VERSION 5.8 ;
BUSBITCHARS "[]" ;
DIVIDERCHAR "/" ;
UNITS
    DATABASE MICRONS 1000 ;
END UNITS

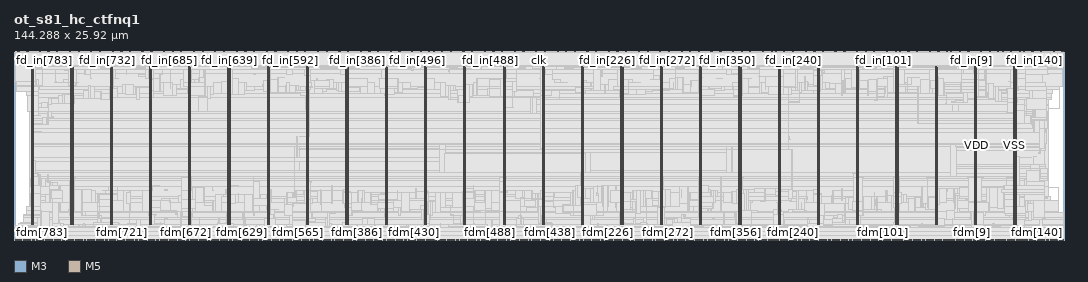
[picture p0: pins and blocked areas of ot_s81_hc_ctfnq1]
MACRO ot_s81_hc_ctfnq1
  FOREIGN ot_s81_hc_ctfnq1 0 0 ;
  CLASS BLOCK ;
  SIZE 144.288 BY 25.92 ;
  PIN clk
    DIRECTION INPUT ;
    USE SIGNAL ;
    PORT
      LAYER M3 ;
        RECT  72.144 25.882 72.162 25.92 ;
    END
  END clk
  PIN fd_in[0]
    DIRECTION INPUT ;
    USE SIGNAL ;
    PORT
      LAYER M5 ;
        RECT  129.984 25.836 130.008 25.92 ;
    END
  END fd_in[0]
  PIN fd_in[100]
    DIRECTION INPUT ;
    USE SIGNAL ;
    PORT
      LAYER M5 ;
        RECT  119.232 25.836 119.256 25.92 ;
    END
  END fd_in[100]
  PIN fd_in[101]
    DIRECTION INPUT ;
    USE SIGNAL ;
    PORT
      LAYER M5 ;
        RECT  119.424 25.836 119.448 25.92 ;
    END
  END fd_in[101]
  PIN fd_in[102]
    DIRECTION INPUT ;
    USE SIGNAL ;
    PORT
      LAYER M5 ;
        RECT  119.568 25.836 119.592 25.92 ;
    END
  END fd_in[102]
  PIN fd_in[103]
    DIRECTION INPUT ;
    USE SIGNAL ;
    PORT
      LAYER M5 ;
        RECT  119.76 25.836 119.784 25.92 ;
    END
  END fd_in[103]
  PIN fd_in[104]
    DIRECTION INPUT ;
    USE SIGNAL ;
    PORT
      LAYER M5 ;
        RECT  119.952 25.836 119.976 25.92 ;
    END
  END fd_in[104]
  PIN fd_in[105]
    DIRECTION INPUT ;
    USE SIGNAL ;
    PORT
      LAYER M5 ;
        RECT  120.144 25.836 120.168 25.92 ;
    END
  END fd_in[105]
  PIN fd_in[106]
    DIRECTION INPUT ;
    USE SIGNAL ;
    PORT
      LAYER M5 ;
        RECT  120.288 25.836 120.312 25.92 ;
    END
  END fd_in[106]
  PIN fd_in[107]
    DIRECTION INPUT ;
    USE SIGNAL ;
    PORT
      LAYER M5 ;
        RECT  120.48 25.836 120.504 25.92 ;
    END
  END fd_in[107]
  PIN fd_in[108]
    DIRECTION INPUT ;
    USE SIGNAL ;
    PORT
      LAYER M5 ;
        RECT  120.672 25.836 120.696 25.92 ;
    END
  END fd_in[108]
  PIN fd_in[109]
    DIRECTION INPUT ;
    USE SIGNAL ;
    PORT
      LAYER M5 ;
        RECT  120.864 25.836 120.888 25.92 ;
    END
  END fd_in[109]
  PIN fd_in[10]
    DIRECTION INPUT ;
    USE SIGNAL ;
    PORT
      LAYER M5 ;
        RECT  131.808 25.836 131.832 25.92 ;
    END
  END fd_in[10]
  PIN fd_in[110]
    DIRECTION INPUT ;
    USE SIGNAL ;
    PORT
      LAYER M5 ;
        RECT  121.008 25.836 121.032 25.92 ;
    END
  END fd_in[110]
  PIN fd_in[111]
    DIRECTION INPUT ;
    USE SIGNAL ;
    PORT
      LAYER M5 ;
        RECT  121.2 25.836 121.224 25.92 ;
    END
  END fd_in[111]
  PIN fd_in[112]
    DIRECTION INPUT ;
    USE SIGNAL ;
    PORT
      LAYER M5 ;
        RECT  121.392 25.836 121.416 25.92 ;
    END
  END fd_in[112]
  PIN fd_in[113]
    DIRECTION INPUT ;
    USE SIGNAL ;
    PORT
      LAYER M5 ;
        RECT  121.584 25.836 121.608 25.92 ;
    END
  END fd_in[113]
  PIN fd_in[114]
    DIRECTION INPUT ;
    USE SIGNAL ;
    PORT
      LAYER M5 ;
        RECT  121.728 25.836 121.752 25.92 ;
    END
  END fd_in[114]
  PIN fd_in[115]
    DIRECTION INPUT ;
    USE SIGNAL ;
    PORT
      LAYER M5 ;
        RECT  121.92 25.836 121.944 25.92 ;
    END
  END fd_in[115]
  PIN fd_in[116]
    DIRECTION INPUT ;
    USE SIGNAL ;
    PORT
      LAYER M5 ;
        RECT  122.112 25.836 122.136 25.92 ;
    END
  END fd_in[116]
  PIN fd_in[117]
    DIRECTION INPUT ;
    USE SIGNAL ;
    PORT
      LAYER M5 ;
        RECT  122.304 25.836 122.328 25.92 ;
    END
  END fd_in[117]
  PIN fd_in[118]
    DIRECTION INPUT ;
    USE SIGNAL ;
    PORT
      LAYER M5 ;
        RECT  122.448 25.836 122.472 25.92 ;
    END
  END fd_in[118]
  PIN fd_in[119]
    DIRECTION INPUT ;
    USE SIGNAL ;
    PORT
      LAYER M5 ;
        RECT  122.64 25.836 122.664 25.92 ;
    END
  END fd_in[119]
  PIN fd_in[11]
    DIRECTION INPUT ;
    USE SIGNAL ;
    PORT
      LAYER M5 ;
        RECT  131.952 25.836 131.976 25.92 ;
    END
  END fd_in[11]
  PIN fd_in[120]
    DIRECTION INPUT ;
    USE SIGNAL ;
    PORT
      LAYER M5 ;
        RECT  122.832 25.836 122.856 25.92 ;
    END
  END fd_in[120]
  PIN fd_in[121]
    DIRECTION INPUT ;
    USE SIGNAL ;
    PORT
      LAYER M5 ;
        RECT  122.976 25.836 123 25.92 ;
    END
  END fd_in[121]
  PIN fd_in[122]
    DIRECTION INPUT ;
    USE SIGNAL ;
    PORT
      LAYER M5 ;
        RECT  123.168 25.836 123.192 25.92 ;
    END
  END fd_in[122]
  PIN fd_in[123]
    DIRECTION INPUT ;
    USE SIGNAL ;
    PORT
      LAYER M5 ;
        RECT  123.36 25.836 123.384 25.92 ;
    END
  END fd_in[123]
  PIN fd_in[124]
    DIRECTION INPUT ;
    USE SIGNAL ;
    PORT
      LAYER M5 ;
        RECT  123.552 25.836 123.576 25.92 ;
    END
  END fd_in[124]
  PIN fd_in[125]
    DIRECTION INPUT ;
    USE SIGNAL ;
    PORT
      LAYER M5 ;
        RECT  123.696 25.836 123.72 25.92 ;
    END
  END fd_in[125]
  PIN fd_in[126]
    DIRECTION INPUT ;
    USE SIGNAL ;
    PORT
      LAYER M5 ;
        RECT  123.888 25.836 123.912 25.92 ;
    END
  END fd_in[126]
  PIN fd_in[127]
    DIRECTION INPUT ;
    USE SIGNAL ;
    PORT
      LAYER M5 ;
        RECT  124.08 25.836 124.104 25.92 ;
    END
  END fd_in[127]
  PIN fd_in[128]
    DIRECTION INPUT ;
    USE SIGNAL ;
    PORT
      LAYER M5 ;
        RECT  141.456 25.836 141.48 25.92 ;
    END
  END fd_in[128]
  PIN fd_in[129]
    DIRECTION INPUT ;
    USE SIGNAL ;
    PORT
      LAYER M5 ;
        RECT  141.648 25.836 141.672 25.92 ;
    END
  END fd_in[129]
  PIN fd_in[12]
    DIRECTION INPUT ;
    USE SIGNAL ;
    PORT
      LAYER M5 ;
        RECT  132.144 25.836 132.168 25.92 ;
    END
  END fd_in[12]
  PIN fd_in[130]
    DIRECTION INPUT ;
    USE SIGNAL ;
    PORT
      LAYER M5 ;
        RECT  141.84 25.836 141.864 25.92 ;
    END
  END fd_in[130]
  PIN fd_in[131]
    DIRECTION INPUT ;
    USE SIGNAL ;
    PORT
      LAYER M5 ;
        RECT  142.032 25.836 142.056 25.92 ;
    END
  END fd_in[131]
  PIN fd_in[132]
    DIRECTION INPUT ;
    USE SIGNAL ;
    PORT
      LAYER M5 ;
        RECT  142.176 25.836 142.2 25.92 ;
    END
  END fd_in[132]
  PIN fd_in[133]
    DIRECTION INPUT ;
    USE SIGNAL ;
    PORT
      LAYER M5 ;
        RECT  142.368 25.836 142.392 25.92 ;
    END
  END fd_in[133]
  PIN fd_in[134]
    DIRECTION INPUT ;
    USE SIGNAL ;
    PORT
      LAYER M5 ;
        RECT  142.56 25.836 142.584 25.92 ;
    END
  END fd_in[134]
  PIN fd_in[135]
    DIRECTION INPUT ;
    USE SIGNAL ;
    PORT
      LAYER M5 ;
        RECT  142.704 25.836 142.728 25.92 ;
    END
  END fd_in[135]
  PIN fd_in[136]
    DIRECTION INPUT ;
    USE SIGNAL ;
    PORT
      LAYER M5 ;
        RECT  142.896 25.836 142.92 25.92 ;
    END
  END fd_in[136]
  PIN fd_in[137]
    DIRECTION INPUT ;
    USE SIGNAL ;
    PORT
      LAYER M5 ;
        RECT  143.088 25.836 143.112 25.92 ;
    END
  END fd_in[137]
  PIN fd_in[138]
    DIRECTION INPUT ;
    USE SIGNAL ;
    PORT
      LAYER M5 ;
        RECT  143.28 25.836 143.304 25.92 ;
    END
  END fd_in[138]
  PIN fd_in[139]
    DIRECTION INPUT ;
    USE SIGNAL ;
    PORT
      LAYER M5 ;
        RECT  143.424 25.836 143.448 25.92 ;
    END
  END fd_in[139]
  PIN fd_in[13]
    DIRECTION INPUT ;
    USE SIGNAL ;
    PORT
      LAYER M5 ;
        RECT  132.336 25.836 132.36 25.92 ;
    END
  END fd_in[13]
  PIN fd_in[140]
    DIRECTION INPUT ;
    USE SIGNAL ;
    PORT
      LAYER M5 ;
        RECT  143.616 25.836 143.64 25.92 ;
    END
  END fd_in[140]
  PIN fd_in[141]
    DIRECTION INPUT ;
    USE SIGNAL ;
    PORT
      LAYER M5 ;
        RECT  143.808 25.836 143.832 25.92 ;
    END
  END fd_in[141]
  PIN fd_in[142]
    DIRECTION INPUT ;
    USE SIGNAL ;
    PORT
      LAYER M5 ;
        RECT  144 25.836 144.024 25.92 ;
    END
  END fd_in[142]
  PIN fd_in[143]
    DIRECTION INPUT ;
    USE SIGNAL ;
    PORT
      LAYER M5 ;
        RECT  144.144 25.836 144.168 25.92 ;
    END
  END fd_in[143]
  PIN fd_in[144]
    DIRECTION INPUT ;
    USE SIGNAL ;
    PORT
      LAYER M5 ;
        RECT  112.8 25.836 112.824 25.92 ;
    END
  END fd_in[144]
  PIN fd_in[145]
    DIRECTION INPUT ;
    USE SIGNAL ;
    PORT
      LAYER M5 ;
        RECT  112.944 25.836 112.968 25.92 ;
    END
  END fd_in[145]
  PIN fd_in[146]
    DIRECTION INPUT ;
    USE SIGNAL ;
    PORT
      LAYER M5 ;
        RECT  113.136 25.836 113.16 25.92 ;
    END
  END fd_in[146]
  PIN fd_in[147]
    DIRECTION INPUT ;
    USE SIGNAL ;
    PORT
      LAYER M5 ;
        RECT  113.328 25.836 113.352 25.92 ;
    END
  END fd_in[147]
  PIN fd_in[148]
    DIRECTION INPUT ;
    USE SIGNAL ;
    PORT
      LAYER M5 ;
        RECT  113.472 25.836 113.496 25.92 ;
    END
  END fd_in[148]
  PIN fd_in[149]
    DIRECTION INPUT ;
    USE SIGNAL ;
    PORT
      LAYER M5 ;
        RECT  113.664 25.836 113.688 25.92 ;
    END
  END fd_in[149]
  PIN fd_in[14]
    DIRECTION INPUT ;
    USE SIGNAL ;
    PORT
      LAYER M5 ;
        RECT  132.528 25.836 132.552 25.92 ;
    END
  END fd_in[14]
  PIN fd_in[150]
    DIRECTION INPUT ;
    USE SIGNAL ;
    PORT
      LAYER M5 ;
        RECT  113.856 25.836 113.88 25.92 ;
    END
  END fd_in[150]
  PIN fd_in[151]
    DIRECTION INPUT ;
    USE SIGNAL ;
    PORT
      LAYER M5 ;
        RECT  114.048 25.836 114.072 25.92 ;
    END
  END fd_in[151]
  PIN fd_in[152]
    DIRECTION INPUT ;
    USE SIGNAL ;
    PORT
      LAYER M5 ;
        RECT  114.192 25.836 114.216 25.92 ;
    END
  END fd_in[152]
  PIN fd_in[153]
    DIRECTION INPUT ;
    USE SIGNAL ;
    PORT
      LAYER M5 ;
        RECT  114.384 25.836 114.408 25.92 ;
    END
  END fd_in[153]
  PIN fd_in[154]
    DIRECTION INPUT ;
    USE SIGNAL ;
    PORT
      LAYER M5 ;
        RECT  114.576 25.836 114.6 25.92 ;
    END
  END fd_in[154]
  PIN fd_in[155]
    DIRECTION INPUT ;
    USE SIGNAL ;
    PORT
      LAYER M5 ;
        RECT  114.768 25.836 114.792 25.92 ;
    END
  END fd_in[155]
  PIN fd_in[156]
    DIRECTION INPUT ;
    USE SIGNAL ;
    PORT
      LAYER M5 ;
        RECT  114.912 25.836 114.936 25.92 ;
    END
  END fd_in[156]
  PIN fd_in[157]
    DIRECTION INPUT ;
    USE SIGNAL ;
    PORT
      LAYER M5 ;
        RECT  115.104 25.836 115.128 25.92 ;
    END
  END fd_in[157]
  PIN fd_in[158]
    DIRECTION INPUT ;
    USE SIGNAL ;
    PORT
      LAYER M5 ;
        RECT  115.296 25.836 115.32 25.92 ;
    END
  END fd_in[158]
  PIN fd_in[159]
    DIRECTION INPUT ;
    USE SIGNAL ;
    PORT
      LAYER M5 ;
        RECT  115.488 25.836 115.512 25.92 ;
    END
  END fd_in[159]
  PIN fd_in[15]
    DIRECTION INPUT ;
    USE SIGNAL ;
    PORT
      LAYER M5 ;
        RECT  132.672 25.836 132.696 25.92 ;
    END
  END fd_in[15]
  PIN fd_in[160]
    DIRECTION INPUT ;
    USE SIGNAL ;
    PORT
      LAYER M5 ;
        RECT  115.632 25.836 115.656 25.92 ;
    END
  END fd_in[160]
  PIN fd_in[161]
    DIRECTION INPUT ;
    USE SIGNAL ;
    PORT
      LAYER M5 ;
        RECT  115.824 25.836 115.848 25.92 ;
    END
  END fd_in[161]
  PIN fd_in[162]
    DIRECTION INPUT ;
    USE SIGNAL ;
    PORT
      LAYER M5 ;
        RECT  116.016 25.836 116.04 25.92 ;
    END
  END fd_in[162]
  PIN fd_in[163]
    DIRECTION INPUT ;
    USE SIGNAL ;
    PORT
      LAYER M5 ;
        RECT  116.208 25.836 116.232 25.92 ;
    END
  END fd_in[163]
  PIN fd_in[164]
    DIRECTION INPUT ;
    USE SIGNAL ;
    PORT
      LAYER M5 ;
        RECT  116.352 25.836 116.376 25.92 ;
    END
  END fd_in[164]
  PIN fd_in[165]
    DIRECTION INPUT ;
    USE SIGNAL ;
    PORT
      LAYER M5 ;
        RECT  116.544 25.836 116.568 25.92 ;
    END
  END fd_in[165]
  PIN fd_in[166]
    DIRECTION INPUT ;
    USE SIGNAL ;
    PORT
      LAYER M5 ;
        RECT  116.736 25.836 116.76 25.92 ;
    END
  END fd_in[166]
  PIN fd_in[167]
    DIRECTION INPUT ;
    USE SIGNAL ;
    PORT
      LAYER M5 ;
        RECT  116.88 25.836 116.904 25.92 ;
    END
  END fd_in[167]
  PIN fd_in[168]
    DIRECTION INPUT ;
    USE SIGNAL ;
    PORT
      LAYER M5 ;
        RECT  117.072 25.836 117.096 25.92 ;
    END
  END fd_in[168]
  PIN fd_in[169]
    DIRECTION INPUT ;
    USE SIGNAL ;
    PORT
      LAYER M5 ;
        RECT  117.264 25.836 117.288 25.92 ;
    END
  END fd_in[169]
  PIN fd_in[16]
    DIRECTION INPUT ;
    USE SIGNAL ;
    PORT
      LAYER M5 ;
        RECT  132.864 25.836 132.888 25.92 ;
    END
  END fd_in[16]
  PIN fd_in[170]
    DIRECTION INPUT ;
    USE SIGNAL ;
    PORT
      LAYER M5 ;
        RECT  117.456 25.836 117.48 25.92 ;
    END
  END fd_in[170]
  PIN fd_in[171]
    DIRECTION INPUT ;
    USE SIGNAL ;
    PORT
      LAYER M5 ;
        RECT  117.6 25.836 117.624 25.92 ;
    END
  END fd_in[171]
  PIN fd_in[172]
    DIRECTION INPUT ;
    USE SIGNAL ;
    PORT
      LAYER M5 ;
        RECT  117.792 25.836 117.816 25.92 ;
    END
  END fd_in[172]
  PIN fd_in[173]
    DIRECTION INPUT ;
    USE SIGNAL ;
    PORT
      LAYER M5 ;
        RECT  117.984 25.836 118.008 25.92 ;
    END
  END fd_in[173]
  PIN fd_in[174]
    DIRECTION INPUT ;
    USE SIGNAL ;
    PORT
      LAYER M5 ;
        RECT  118.176 25.836 118.2 25.92 ;
    END
  END fd_in[174]
  PIN fd_in[175]
    DIRECTION INPUT ;
    USE SIGNAL ;
    PORT
      LAYER M5 ;
        RECT  118.32 25.836 118.344 25.92 ;
    END
  END fd_in[175]
  PIN fd_in[176]
    DIRECTION INPUT ;
    USE SIGNAL ;
    PORT
      LAYER M5 ;
        RECT  101.28 25.836 101.304 25.92 ;
    END
  END fd_in[176]
  PIN fd_in[177]
    DIRECTION INPUT ;
    USE SIGNAL ;
    PORT
      LAYER M5 ;
        RECT  101.472 25.836 101.496 25.92 ;
    END
  END fd_in[177]
  PIN fd_in[178]
    DIRECTION INPUT ;
    USE SIGNAL ;
    PORT
      LAYER M5 ;
        RECT  101.664 25.836 101.688 25.92 ;
    END
  END fd_in[178]
  PIN fd_in[179]
    DIRECTION INPUT ;
    USE SIGNAL ;
    PORT
      LAYER M5 ;
        RECT  101.856 25.836 101.88 25.92 ;
    END
  END fd_in[179]
  PIN fd_in[17]
    DIRECTION INPUT ;
    USE SIGNAL ;
    PORT
      LAYER M5 ;
        RECT  133.056 25.836 133.08 25.92 ;
    END
  END fd_in[17]
  PIN fd_in[180]
    DIRECTION INPUT ;
    USE SIGNAL ;
    PORT
      LAYER M5 ;
        RECT  102 25.836 102.024 25.92 ;
    END
  END fd_in[180]
  PIN fd_in[181]
    DIRECTION INPUT ;
    USE SIGNAL ;
    PORT
      LAYER M5 ;
        RECT  102.192 25.836 102.216 25.92 ;
    END
  END fd_in[181]
  PIN fd_in[182]
    DIRECTION INPUT ;
    USE SIGNAL ;
    PORT
      LAYER M5 ;
        RECT  102.384 25.836 102.408 25.92 ;
    END
  END fd_in[182]
  PIN fd_in[183]
    DIRECTION INPUT ;
    USE SIGNAL ;
    PORT
      LAYER M5 ;
        RECT  102.576 25.836 102.6 25.92 ;
    END
  END fd_in[183]
  PIN fd_in[184]
    DIRECTION INPUT ;
    USE SIGNAL ;
    PORT
      LAYER M5 ;
        RECT  102.72 25.836 102.744 25.92 ;
    END
  END fd_in[184]
  PIN fd_in[185]
    DIRECTION INPUT ;
    USE SIGNAL ;
    PORT
      LAYER M5 ;
        RECT  102.912 25.836 102.936 25.92 ;
    END
  END fd_in[185]
  PIN fd_in[186]
    DIRECTION INPUT ;
    USE SIGNAL ;
    PORT
      LAYER M5 ;
        RECT  103.104 25.836 103.128 25.92 ;
    END
  END fd_in[186]
  PIN fd_in[187]
    DIRECTION INPUT ;
    USE SIGNAL ;
    PORT
      LAYER M5 ;
        RECT  103.248 25.836 103.272 25.92 ;
    END
  END fd_in[187]
  PIN fd_in[188]
    DIRECTION INPUT ;
    USE SIGNAL ;
    PORT
      LAYER M5 ;
        RECT  103.44 25.836 103.464 25.92 ;
    END
  END fd_in[188]
  PIN fd_in[189]
    DIRECTION INPUT ;
    USE SIGNAL ;
    PORT
      LAYER M5 ;
        RECT  103.632 25.836 103.656 25.92 ;
    END
  END fd_in[189]
  PIN fd_in[18]
    DIRECTION INPUT ;
    USE SIGNAL ;
    PORT
      LAYER M5 ;
        RECT  133.2 25.836 133.224 25.92 ;
    END
  END fd_in[18]
  PIN fd_in[190]
    DIRECTION INPUT ;
    USE SIGNAL ;
    PORT
      LAYER M5 ;
        RECT  103.824 25.836 103.848 25.92 ;
    END
  END fd_in[190]
  PIN fd_in[191]
    DIRECTION INPUT ;
    USE SIGNAL ;
    PORT
      LAYER M5 ;
        RECT  103.968 25.836 103.992 25.92 ;
    END
  END fd_in[191]
  PIN fd_in[192]
    DIRECTION INPUT ;
    USE SIGNAL ;
    PORT
      LAYER M5 ;
        RECT  104.16 25.836 104.184 25.92 ;
    END
  END fd_in[192]
  PIN fd_in[193]
    DIRECTION INPUT ;
    USE SIGNAL ;
    PORT
      LAYER M5 ;
        RECT  104.352 25.836 104.376 25.92 ;
    END
  END fd_in[193]
  PIN fd_in[194]
    DIRECTION INPUT ;
    USE SIGNAL ;
    PORT
      LAYER M5 ;
        RECT  104.544 25.836 104.568 25.92 ;
    END
  END fd_in[194]
  PIN fd_in[195]
    DIRECTION INPUT ;
    USE SIGNAL ;
    PORT
      LAYER M5 ;
        RECT  104.688 25.836 104.712 25.92 ;
    END
  END fd_in[195]
  PIN fd_in[196]
    DIRECTION INPUT ;
    USE SIGNAL ;
    PORT
      LAYER M5 ;
        RECT  104.88 25.836 104.904 25.92 ;
    END
  END fd_in[196]
  PIN fd_in[197]
    DIRECTION INPUT ;
    USE SIGNAL ;
    PORT
      LAYER M5 ;
        RECT  105.072 25.836 105.096 25.92 ;
    END
  END fd_in[197]
  PIN fd_in[198]
    DIRECTION INPUT ;
    USE SIGNAL ;
    PORT
      LAYER M5 ;
        RECT  105.264 25.836 105.288 25.92 ;
    END
  END fd_in[198]
  PIN fd_in[199]
    DIRECTION INPUT ;
    USE SIGNAL ;
    PORT
      LAYER M5 ;
        RECT  105.408 25.836 105.432 25.92 ;
    END
  END fd_in[199]
  PIN fd_in[19]
    DIRECTION INPUT ;
    USE SIGNAL ;
    PORT
      LAYER M5 ;
        RECT  133.392 25.836 133.416 25.92 ;
    END
  END fd_in[19]
  PIN fd_in[1]
    DIRECTION INPUT ;
    USE SIGNAL ;
    PORT
      LAYER M5 ;
        RECT  130.176 25.836 130.2 25.92 ;
    END
  END fd_in[1]
  PIN fd_in[200]
    DIRECTION INPUT ;
    USE SIGNAL ;
    PORT
      LAYER M5 ;
        RECT  105.6 25.836 105.624 25.92 ;
    END
  END fd_in[200]
  PIN fd_in[201]
    DIRECTION INPUT ;
    USE SIGNAL ;
    PORT
      LAYER M5 ;
        RECT  105.792 25.836 105.816 25.92 ;
    END
  END fd_in[201]
  PIN fd_in[202]
    DIRECTION INPUT ;
    USE SIGNAL ;
    PORT
      LAYER M5 ;
        RECT  105.984 25.836 106.008 25.92 ;
    END
  END fd_in[202]
  PIN fd_in[203]
    DIRECTION INPUT ;
    USE SIGNAL ;
    PORT
      LAYER M5 ;
        RECT  106.128 25.836 106.152 25.92 ;
    END
  END fd_in[203]
  PIN fd_in[204]
    DIRECTION INPUT ;
    USE SIGNAL ;
    PORT
      LAYER M5 ;
        RECT  106.32 25.836 106.344 25.92 ;
    END
  END fd_in[204]
  PIN fd_in[205]
    DIRECTION INPUT ;
    USE SIGNAL ;
    PORT
      LAYER M5 ;
        RECT  106.512 25.836 106.536 25.92 ;
    END
  END fd_in[205]
  PIN fd_in[206]
    DIRECTION INPUT ;
    USE SIGNAL ;
    PORT
      LAYER M5 ;
        RECT  106.656 25.836 106.68 25.92 ;
    END
  END fd_in[206]
  PIN fd_in[207]
    DIRECTION INPUT ;
    USE SIGNAL ;
    PORT
      LAYER M5 ;
        RECT  106.848 25.836 106.872 25.92 ;
    END
  END fd_in[207]
  PIN fd_in[208]
    DIRECTION INPUT ;
    USE SIGNAL ;
    PORT
      LAYER M5 ;
        RECT  78.336 25.836 78.36 25.92 ;
    END
  END fd_in[208]
  PIN fd_in[209]
    DIRECTION INPUT ;
    USE SIGNAL ;
    PORT
      LAYER M5 ;
        RECT  78.528 25.836 78.552 25.92 ;
    END
  END fd_in[209]
  PIN fd_in[20]
    DIRECTION INPUT ;
    USE SIGNAL ;
    PORT
      LAYER M5 ;
        RECT  133.584 25.836 133.608 25.92 ;
    END
  END fd_in[20]
  PIN fd_in[210]
    DIRECTION INPUT ;
    USE SIGNAL ;
    PORT
      LAYER M5 ;
        RECT  78.72 25.836 78.744 25.92 ;
    END
  END fd_in[210]
  PIN fd_in[211]
    DIRECTION INPUT ;
    USE SIGNAL ;
    PORT
      LAYER M5 ;
        RECT  78.864 25.836 78.888 25.92 ;
    END
  END fd_in[211]
  PIN fd_in[212]
    DIRECTION INPUT ;
    USE SIGNAL ;
    PORT
      LAYER M5 ;
        RECT  79.056 25.836 79.08 25.92 ;
    END
  END fd_in[212]
  PIN fd_in[213]
    DIRECTION INPUT ;
    USE SIGNAL ;
    PORT
      LAYER M5 ;
        RECT  79.248 25.836 79.272 25.92 ;
    END
  END fd_in[213]
  PIN fd_in[214]
    DIRECTION INPUT ;
    USE SIGNAL ;
    PORT
      LAYER M5 ;
        RECT  79.44 25.836 79.464 25.92 ;
    END
  END fd_in[214]
  PIN fd_in[215]
    DIRECTION INPUT ;
    USE SIGNAL ;
    PORT
      LAYER M5 ;
        RECT  79.584 25.836 79.608 25.92 ;
    END
  END fd_in[215]
  PIN fd_in[216]
    DIRECTION INPUT ;
    USE SIGNAL ;
    PORT
      LAYER M5 ;
        RECT  79.776 25.836 79.8 25.92 ;
    END
  END fd_in[216]
  PIN fd_in[217]
    DIRECTION INPUT ;
    USE SIGNAL ;
    PORT
      LAYER M5 ;
        RECT  79.968 25.836 79.992 25.92 ;
    END
  END fd_in[217]
  PIN fd_in[218]
    DIRECTION INPUT ;
    USE SIGNAL ;
    PORT
      LAYER M5 ;
        RECT  80.16 25.836 80.184 25.92 ;
    END
  END fd_in[218]
  PIN fd_in[219]
    DIRECTION INPUT ;
    USE SIGNAL ;
    PORT
      LAYER M5 ;
        RECT  80.304 25.836 80.328 25.92 ;
    END
  END fd_in[219]
  PIN fd_in[21]
    DIRECTION INPUT ;
    USE SIGNAL ;
    PORT
      LAYER M5 ;
        RECT  133.776 25.836 133.8 25.92 ;
    END
  END fd_in[21]
  PIN fd_in[220]
    DIRECTION INPUT ;
    USE SIGNAL ;
    PORT
      LAYER M5 ;
        RECT  80.496 25.836 80.52 25.92 ;
    END
  END fd_in[220]
  PIN fd_in[221]
    DIRECTION INPUT ;
    USE SIGNAL ;
    PORT
      LAYER M5 ;
        RECT  80.688 25.836 80.712 25.92 ;
    END
  END fd_in[221]
  PIN fd_in[222]
    DIRECTION INPUT ;
    USE SIGNAL ;
    PORT
      LAYER M5 ;
        RECT  80.832 25.836 80.856 25.92 ;
    END
  END fd_in[222]
  PIN fd_in[223]
    DIRECTION INPUT ;
    USE SIGNAL ;
    PORT
      LAYER M5 ;
        RECT  81.024 25.836 81.048 25.92 ;
    END
  END fd_in[223]
  PIN fd_in[224]
    DIRECTION INPUT ;
    USE SIGNAL ;
    PORT
      LAYER M5 ;
        RECT  81.216 25.836 81.24 25.92 ;
    END
  END fd_in[224]
  PIN fd_in[225]
    DIRECTION INPUT ;
    USE SIGNAL ;
    PORT
      LAYER M5 ;
        RECT  81.408 25.836 81.432 25.92 ;
    END
  END fd_in[225]
  PIN fd_in[226]
    DIRECTION INPUT ;
    USE SIGNAL ;
    PORT
      LAYER M5 ;
        RECT  81.552 25.836 81.576 25.92 ;
    END
  END fd_in[226]
  PIN fd_in[227]
    DIRECTION INPUT ;
    USE SIGNAL ;
    PORT
      LAYER M5 ;
        RECT  81.744 25.836 81.768 25.92 ;
    END
  END fd_in[227]
  PIN fd_in[228]
    DIRECTION INPUT ;
    USE SIGNAL ;
    PORT
      LAYER M5 ;
        RECT  81.936 25.836 81.96 25.92 ;
    END
  END fd_in[228]
  PIN fd_in[229]
    DIRECTION INPUT ;
    USE SIGNAL ;
    PORT
      LAYER M5 ;
        RECT  82.128 25.836 82.152 25.92 ;
    END
  END fd_in[229]
  PIN fd_in[22]
    DIRECTION INPUT ;
    USE SIGNAL ;
    PORT
      LAYER M5 ;
        RECT  133.92 25.836 133.944 25.92 ;
    END
  END fd_in[22]
  PIN fd_in[230]
    DIRECTION INPUT ;
    USE SIGNAL ;
    PORT
      LAYER M5 ;
        RECT  82.272 25.836 82.296 25.92 ;
    END
  END fd_in[230]
  PIN fd_in[231]
    DIRECTION INPUT ;
    USE SIGNAL ;
    PORT
      LAYER M5 ;
        RECT  82.464 25.836 82.488 25.92 ;
    END
  END fd_in[231]
  PIN fd_in[232]
    DIRECTION INPUT ;
    USE SIGNAL ;
    PORT
      LAYER M5 ;
        RECT  82.656 25.836 82.68 25.92 ;
    END
  END fd_in[232]
  PIN fd_in[233]
    DIRECTION INPUT ;
    USE SIGNAL ;
    PORT
      LAYER M5 ;
        RECT  82.848 25.836 82.872 25.92 ;
    END
  END fd_in[233]
  PIN fd_in[234]
    DIRECTION INPUT ;
    USE SIGNAL ;
    PORT
      LAYER M5 ;
        RECT  82.992 25.836 83.016 25.92 ;
    END
  END fd_in[234]
  PIN fd_in[235]
    DIRECTION INPUT ;
    USE SIGNAL ;
    PORT
      LAYER M5 ;
        RECT  83.184 25.836 83.208 25.92 ;
    END
  END fd_in[235]
  PIN fd_in[236]
    DIRECTION INPUT ;
    USE SIGNAL ;
    PORT
      LAYER M5 ;
        RECT  83.376 25.836 83.4 25.92 ;
    END
  END fd_in[236]
  PIN fd_in[237]
    DIRECTION INPUT ;
    USE SIGNAL ;
    PORT
      LAYER M5 ;
        RECT  83.52 25.836 83.544 25.92 ;
    END
  END fd_in[237]
  PIN fd_in[238]
    DIRECTION INPUT ;
    USE SIGNAL ;
    PORT
      LAYER M5 ;
        RECT  83.712 25.836 83.736 25.92 ;
    END
  END fd_in[238]
  PIN fd_in[239]
    DIRECTION INPUT ;
    USE SIGNAL ;
    PORT
      LAYER M5 ;
        RECT  83.904 25.836 83.928 25.92 ;
    END
  END fd_in[239]
  PIN fd_in[23]
    DIRECTION INPUT ;
    USE SIGNAL ;
    PORT
      LAYER M5 ;
        RECT  134.112 25.836 134.136 25.92 ;
    END
  END fd_in[23]
  PIN fd_in[240]
    DIRECTION INPUT ;
    USE SIGNAL ;
    PORT
      LAYER M5 ;
        RECT  107.04 25.836 107.064 25.92 ;
    END
  END fd_in[240]
  PIN fd_in[241]
    DIRECTION INPUT ;
    USE SIGNAL ;
    PORT
      LAYER M5 ;
        RECT  107.232 25.836 107.256 25.92 ;
    END
  END fd_in[241]
  PIN fd_in[242]
    DIRECTION INPUT ;
    USE SIGNAL ;
    PORT
      LAYER M5 ;
        RECT  107.376 25.836 107.4 25.92 ;
    END
  END fd_in[242]
  PIN fd_in[243]
    DIRECTION INPUT ;
    USE SIGNAL ;
    PORT
      LAYER M5 ;
        RECT  107.568 25.836 107.592 25.92 ;
    END
  END fd_in[243]
  PIN fd_in[244]
    DIRECTION INPUT ;
    USE SIGNAL ;
    PORT
      LAYER M5 ;
        RECT  107.76 25.836 107.784 25.92 ;
    END
  END fd_in[244]
  PIN fd_in[245]
    DIRECTION INPUT ;
    USE SIGNAL ;
    PORT
      LAYER M5 ;
        RECT  107.952 25.836 107.976 25.92 ;
    END
  END fd_in[245]
  PIN fd_in[246]
    DIRECTION INPUT ;
    USE SIGNAL ;
    PORT
      LAYER M5 ;
        RECT  108.096 25.836 108.12 25.92 ;
    END
  END fd_in[246]
  PIN fd_in[247]
    DIRECTION INPUT ;
    USE SIGNAL ;
    PORT
      LAYER M5 ;
        RECT  108.288 25.836 108.312 25.92 ;
    END
  END fd_in[247]
  PIN fd_in[248]
    DIRECTION INPUT ;
    USE SIGNAL ;
    PORT
      LAYER M5 ;
        RECT  108.48 25.836 108.504 25.92 ;
    END
  END fd_in[248]
  PIN fd_in[249]
    DIRECTION INPUT ;
    USE SIGNAL ;
    PORT
      LAYER M5 ;
        RECT  108.672 25.836 108.696 25.92 ;
    END
  END fd_in[249]
  PIN fd_in[24]
    DIRECTION INPUT ;
    USE SIGNAL ;
    PORT
      LAYER M5 ;
        RECT  134.304 25.836 134.328 25.92 ;
    END
  END fd_in[24]
  PIN fd_in[250]
    DIRECTION INPUT ;
    USE SIGNAL ;
    PORT
      LAYER M5 ;
        RECT  108.816 25.836 108.84 25.92 ;
    END
  END fd_in[250]
  PIN fd_in[251]
    DIRECTION INPUT ;
    USE SIGNAL ;
    PORT
      LAYER M5 ;
        RECT  109.008 25.836 109.032 25.92 ;
    END
  END fd_in[251]
  PIN fd_in[252]
    DIRECTION INPUT ;
    USE SIGNAL ;
    PORT
      LAYER M5 ;
        RECT  109.2 25.836 109.224 25.92 ;
    END
  END fd_in[252]
  PIN fd_in[253]
    DIRECTION INPUT ;
    USE SIGNAL ;
    PORT
      LAYER M5 ;
        RECT  109.392 25.836 109.416 25.92 ;
    END
  END fd_in[253]
  PIN fd_in[254]
    DIRECTION INPUT ;
    USE SIGNAL ;
    PORT
      LAYER M5 ;
        RECT  109.536 25.836 109.56 25.92 ;
    END
  END fd_in[254]
  PIN fd_in[255]
    DIRECTION INPUT ;
    USE SIGNAL ;
    PORT
      LAYER M5 ;
        RECT  109.728 25.836 109.752 25.92 ;
    END
  END fd_in[255]
  PIN fd_in[256]
    DIRECTION INPUT ;
    USE SIGNAL ;
    PORT
      LAYER M5 ;
        RECT  109.92 25.836 109.944 25.92 ;
    END
  END fd_in[256]
  PIN fd_in[257]
    DIRECTION INPUT ;
    USE SIGNAL ;
    PORT
      LAYER M5 ;
        RECT  110.064 25.836 110.088 25.92 ;
    END
  END fd_in[257]
  PIN fd_in[258]
    DIRECTION INPUT ;
    USE SIGNAL ;
    PORT
      LAYER M5 ;
        RECT  110.256 25.836 110.28 25.92 ;
    END
  END fd_in[258]
  PIN fd_in[259]
    DIRECTION INPUT ;
    USE SIGNAL ;
    PORT
      LAYER M5 ;
        RECT  110.448 25.836 110.472 25.92 ;
    END
  END fd_in[259]
  PIN fd_in[25]
    DIRECTION INPUT ;
    USE SIGNAL ;
    PORT
      LAYER M5 ;
        RECT  134.496 25.836 134.52 25.92 ;
    END
  END fd_in[25]
  PIN fd_in[260]
    DIRECTION INPUT ;
    USE SIGNAL ;
    PORT
      LAYER M5 ;
        RECT  110.64 25.836 110.664 25.92 ;
    END
  END fd_in[260]
  PIN fd_in[261]
    DIRECTION INPUT ;
    USE SIGNAL ;
    PORT
      LAYER M5 ;
        RECT  110.784 25.836 110.808 25.92 ;
    END
  END fd_in[261]
  PIN fd_in[262]
    DIRECTION INPUT ;
    USE SIGNAL ;
    PORT
      LAYER M5 ;
        RECT  110.976 25.836 111 25.92 ;
    END
  END fd_in[262]
  PIN fd_in[263]
    DIRECTION INPUT ;
    USE SIGNAL ;
    PORT
      LAYER M5 ;
        RECT  111.168 25.836 111.192 25.92 ;
    END
  END fd_in[263]
  PIN fd_in[264]
    DIRECTION INPUT ;
    USE SIGNAL ;
    PORT
      LAYER M5 ;
        RECT  111.36 25.836 111.384 25.92 ;
    END
  END fd_in[264]
  PIN fd_in[265]
    DIRECTION INPUT ;
    USE SIGNAL ;
    PORT
      LAYER M5 ;
        RECT  111.504 25.836 111.528 25.92 ;
    END
  END fd_in[265]
  PIN fd_in[266]
    DIRECTION INPUT ;
    USE SIGNAL ;
    PORT
      LAYER M5 ;
        RECT  111.696 25.836 111.72 25.92 ;
    END
  END fd_in[266]
  PIN fd_in[267]
    DIRECTION INPUT ;
    USE SIGNAL ;
    PORT
      LAYER M5 ;
        RECT  111.888 25.836 111.912 25.92 ;
    END
  END fd_in[267]
  PIN fd_in[268]
    DIRECTION INPUT ;
    USE SIGNAL ;
    PORT
      LAYER M5 ;
        RECT  112.08 25.836 112.104 25.92 ;
    END
  END fd_in[268]
  PIN fd_in[269]
    DIRECTION INPUT ;
    USE SIGNAL ;
    PORT
      LAYER M5 ;
        RECT  112.224 25.836 112.248 25.92 ;
    END
  END fd_in[269]
  PIN fd_in[26]
    DIRECTION INPUT ;
    USE SIGNAL ;
    PORT
      LAYER M5 ;
        RECT  134.64 25.836 134.664 25.92 ;
    END
  END fd_in[26]
  PIN fd_in[270]
    DIRECTION INPUT ;
    USE SIGNAL ;
    PORT
      LAYER M5 ;
        RECT  112.416 25.836 112.44 25.92 ;
    END
  END fd_in[270]
  PIN fd_in[271]
    DIRECTION INPUT ;
    USE SIGNAL ;
    PORT
      LAYER M5 ;
        RECT  112.608 25.836 112.632 25.92 ;
    END
  END fd_in[271]
  PIN fd_in[272]
    DIRECTION INPUT ;
    USE SIGNAL ;
    PORT
      LAYER M5 ;
        RECT  89.808 25.836 89.832 25.92 ;
    END
  END fd_in[272]
  PIN fd_in[273]
    DIRECTION INPUT ;
    USE SIGNAL ;
    PORT
      LAYER M5 ;
        RECT  90 25.836 90.024 25.92 ;
    END
  END fd_in[273]
  PIN fd_in[274]
    DIRECTION INPUT ;
    USE SIGNAL ;
    PORT
      LAYER M5 ;
        RECT  90.192 25.836 90.216 25.92 ;
    END
  END fd_in[274]
  PIN fd_in[275]
    DIRECTION INPUT ;
    USE SIGNAL ;
    PORT
      LAYER M5 ;
        RECT  90.336 25.836 90.36 25.92 ;
    END
  END fd_in[275]
  PIN fd_in[276]
    DIRECTION INPUT ;
    USE SIGNAL ;
    PORT
      LAYER M5 ;
        RECT  90.528 25.836 90.552 25.92 ;
    END
  END fd_in[276]
  PIN fd_in[277]
    DIRECTION INPUT ;
    USE SIGNAL ;
    PORT
      LAYER M5 ;
        RECT  90.72 25.836 90.744 25.92 ;
    END
  END fd_in[277]
  PIN fd_in[278]
    DIRECTION INPUT ;
    USE SIGNAL ;
    PORT
      LAYER M5 ;
        RECT  90.912 25.836 90.936 25.92 ;
    END
  END fd_in[278]
  PIN fd_in[279]
    DIRECTION INPUT ;
    USE SIGNAL ;
    PORT
      LAYER M5 ;
        RECT  91.056 25.836 91.08 25.92 ;
    END
  END fd_in[279]
  PIN fd_in[27]
    DIRECTION INPUT ;
    USE SIGNAL ;
    PORT
      LAYER M5 ;
        RECT  134.832 25.836 134.856 25.92 ;
    END
  END fd_in[27]
  PIN fd_in[280]
    DIRECTION INPUT ;
    USE SIGNAL ;
    PORT
      LAYER M5 ;
        RECT  91.248 25.836 91.272 25.92 ;
    END
  END fd_in[280]
  PIN fd_in[281]
    DIRECTION INPUT ;
    USE SIGNAL ;
    PORT
      LAYER M5 ;
        RECT  91.44 25.836 91.464 25.92 ;
    END
  END fd_in[281]
  PIN fd_in[282]
    DIRECTION INPUT ;
    USE SIGNAL ;
    PORT
      LAYER M5 ;
        RECT  91.632 25.836 91.656 25.92 ;
    END
  END fd_in[282]
  PIN fd_in[283]
    DIRECTION INPUT ;
    USE SIGNAL ;
    PORT
      LAYER M5 ;
        RECT  91.776 25.836 91.8 25.92 ;
    END
  END fd_in[283]
  PIN fd_in[284]
    DIRECTION INPUT ;
    USE SIGNAL ;
    PORT
      LAYER M5 ;
        RECT  91.968 25.836 91.992 25.92 ;
    END
  END fd_in[284]
  PIN fd_in[285]
    DIRECTION INPUT ;
    USE SIGNAL ;
    PORT
      LAYER M5 ;
        RECT  92.16 25.836 92.184 25.92 ;
    END
  END fd_in[285]
  PIN fd_in[286]
    DIRECTION INPUT ;
    USE SIGNAL ;
    PORT
      LAYER M5 ;
        RECT  92.352 25.836 92.376 25.92 ;
    END
  END fd_in[286]
  PIN fd_in[287]
    DIRECTION INPUT ;
    USE SIGNAL ;
    PORT
      LAYER M5 ;
        RECT  92.496 25.836 92.52 25.92 ;
    END
  END fd_in[287]
  PIN fd_in[288]
    DIRECTION INPUT ;
    USE SIGNAL ;
    PORT
      LAYER M5 ;
        RECT  92.688 25.836 92.712 25.92 ;
    END
  END fd_in[288]
  PIN fd_in[289]
    DIRECTION INPUT ;
    USE SIGNAL ;
    PORT
      LAYER M5 ;
        RECT  92.88 25.836 92.904 25.92 ;
    END
  END fd_in[289]
  PIN fd_in[28]
    DIRECTION INPUT ;
    USE SIGNAL ;
    PORT
      LAYER M5 ;
        RECT  135.024 25.836 135.048 25.92 ;
    END
  END fd_in[28]
  PIN fd_in[290]
    DIRECTION INPUT ;
    USE SIGNAL ;
    PORT
      LAYER M5 ;
        RECT  93.072 25.836 93.096 25.92 ;
    END
  END fd_in[290]
  PIN fd_in[291]
    DIRECTION INPUT ;
    USE SIGNAL ;
    PORT
      LAYER M5 ;
        RECT  93.216 25.836 93.24 25.92 ;
    END
  END fd_in[291]
  PIN fd_in[292]
    DIRECTION INPUT ;
    USE SIGNAL ;
    PORT
      LAYER M5 ;
        RECT  93.408 25.836 93.432 25.92 ;
    END
  END fd_in[292]
  PIN fd_in[293]
    DIRECTION INPUT ;
    USE SIGNAL ;
    PORT
      LAYER M5 ;
        RECT  93.6 25.836 93.624 25.92 ;
    END
  END fd_in[293]
  PIN fd_in[294]
    DIRECTION INPUT ;
    USE SIGNAL ;
    PORT
      LAYER M5 ;
        RECT  93.744 25.836 93.768 25.92 ;
    END
  END fd_in[294]
  PIN fd_in[295]
    DIRECTION INPUT ;
    USE SIGNAL ;
    PORT
      LAYER M5 ;
        RECT  93.936 25.836 93.96 25.92 ;
    END
  END fd_in[295]
  PIN fd_in[296]
    DIRECTION INPUT ;
    USE SIGNAL ;
    PORT
      LAYER M5 ;
        RECT  94.128 25.836 94.152 25.92 ;
    END
  END fd_in[296]
  PIN fd_in[297]
    DIRECTION INPUT ;
    USE SIGNAL ;
    PORT
      LAYER M5 ;
        RECT  94.32 25.836 94.344 25.92 ;
    END
  END fd_in[297]
  PIN fd_in[298]
    DIRECTION INPUT ;
    USE SIGNAL ;
    PORT
      LAYER M5 ;
        RECT  94.464 25.836 94.488 25.92 ;
    END
  END fd_in[298]
  PIN fd_in[299]
    DIRECTION INPUT ;
    USE SIGNAL ;
    PORT
      LAYER M5 ;
        RECT  94.656 25.836 94.68 25.92 ;
    END
  END fd_in[299]
  PIN fd_in[29]
    DIRECTION INPUT ;
    USE SIGNAL ;
    PORT
      LAYER M5 ;
        RECT  135.216 25.836 135.24 25.92 ;
    END
  END fd_in[29]
  PIN fd_in[2]
    DIRECTION INPUT ;
    USE SIGNAL ;
    PORT
      LAYER M5 ;
        RECT  130.368 25.836 130.392 25.92 ;
    END
  END fd_in[2]
  PIN fd_in[300]
    DIRECTION INPUT ;
    USE SIGNAL ;
    PORT
      LAYER M5 ;
        RECT  94.848 25.836 94.872 25.92 ;
    END
  END fd_in[300]
  PIN fd_in[301]
    DIRECTION INPUT ;
    USE SIGNAL ;
    PORT
      LAYER M5 ;
        RECT  95.04 25.836 95.064 25.92 ;
    END
  END fd_in[301]
  PIN fd_in[302]
    DIRECTION INPUT ;
    USE SIGNAL ;
    PORT
      LAYER M5 ;
        RECT  95.184 25.836 95.208 25.92 ;
    END
  END fd_in[302]
  PIN fd_in[303]
    DIRECTION INPUT ;
    USE SIGNAL ;
    PORT
      LAYER M5 ;
        RECT  95.376 25.836 95.4 25.92 ;
    END
  END fd_in[303]
  PIN fd_in[304]
    DIRECTION INPUT ;
    USE SIGNAL ;
    PORT
      LAYER M5 ;
        RECT  84.096 25.836 84.12 25.92 ;
    END
  END fd_in[304]
  PIN fd_in[305]
    DIRECTION INPUT ;
    USE SIGNAL ;
    PORT
      LAYER M5 ;
        RECT  84.24 25.836 84.264 25.92 ;
    END
  END fd_in[305]
  PIN fd_in[306]
    DIRECTION INPUT ;
    USE SIGNAL ;
    PORT
      LAYER M5 ;
        RECT  84.432 25.836 84.456 25.92 ;
    END
  END fd_in[306]
  PIN fd_in[307]
    DIRECTION INPUT ;
    USE SIGNAL ;
    PORT
      LAYER M5 ;
        RECT  84.624 25.836 84.648 25.92 ;
    END
  END fd_in[307]
  PIN fd_in[308]
    DIRECTION INPUT ;
    USE SIGNAL ;
    PORT
      LAYER M5 ;
        RECT  84.816 25.836 84.84 25.92 ;
    END
  END fd_in[308]
  PIN fd_in[309]
    DIRECTION INPUT ;
    USE SIGNAL ;
    PORT
      LAYER M5 ;
        RECT  84.96 25.836 84.984 25.92 ;
    END
  END fd_in[309]
  PIN fd_in[30]
    DIRECTION INPUT ;
    USE SIGNAL ;
    PORT
      LAYER M5 ;
        RECT  135.36 25.836 135.384 25.92 ;
    END
  END fd_in[30]
  PIN fd_in[310]
    DIRECTION INPUT ;
    USE SIGNAL ;
    PORT
      LAYER M5 ;
        RECT  85.152 25.836 85.176 25.92 ;
    END
  END fd_in[310]
  PIN fd_in[311]
    DIRECTION INPUT ;
    USE SIGNAL ;
    PORT
      LAYER M5 ;
        RECT  85.344 25.836 85.368 25.92 ;
    END
  END fd_in[311]
  PIN fd_in[312]
    DIRECTION INPUT ;
    USE SIGNAL ;
    PORT
      LAYER M5 ;
        RECT  85.536 25.836 85.56 25.92 ;
    END
  END fd_in[312]
  PIN fd_in[313]
    DIRECTION INPUT ;
    USE SIGNAL ;
    PORT
      LAYER M5 ;
        RECT  85.68 25.836 85.704 25.92 ;
    END
  END fd_in[313]
  PIN fd_in[314]
    DIRECTION INPUT ;
    USE SIGNAL ;
    PORT
      LAYER M5 ;
        RECT  85.872 25.836 85.896 25.92 ;
    END
  END fd_in[314]
  PIN fd_in[315]
    DIRECTION INPUT ;
    USE SIGNAL ;
    PORT
      LAYER M5 ;
        RECT  86.064 25.836 86.088 25.92 ;
    END
  END fd_in[315]
  PIN fd_in[316]
    DIRECTION INPUT ;
    USE SIGNAL ;
    PORT
      LAYER M5 ;
        RECT  86.256 25.836 86.28 25.92 ;
    END
  END fd_in[316]
  PIN fd_in[317]
    DIRECTION INPUT ;
    USE SIGNAL ;
    PORT
      LAYER M5 ;
        RECT  86.4 25.836 86.424 25.92 ;
    END
  END fd_in[317]
  PIN fd_in[318]
    DIRECTION INPUT ;
    USE SIGNAL ;
    PORT
      LAYER M5 ;
        RECT  86.592 25.836 86.616 25.92 ;
    END
  END fd_in[318]
  PIN fd_in[319]
    DIRECTION INPUT ;
    USE SIGNAL ;
    PORT
      LAYER M5 ;
        RECT  86.784 25.836 86.808 25.92 ;
    END
  END fd_in[319]
  PIN fd_in[31]
    DIRECTION INPUT ;
    USE SIGNAL ;
    PORT
      LAYER M5 ;
        RECT  135.552 25.836 135.576 25.92 ;
    END
  END fd_in[31]
  PIN fd_in[320]
    DIRECTION INPUT ;
    USE SIGNAL ;
    PORT
      LAYER M5 ;
        RECT  86.928 25.836 86.952 25.92 ;
    END
  END fd_in[320]
  PIN fd_in[321]
    DIRECTION INPUT ;
    USE SIGNAL ;
    PORT
      LAYER M5 ;
        RECT  87.12 25.836 87.144 25.92 ;
    END
  END fd_in[321]
  PIN fd_in[322]
    DIRECTION INPUT ;
    USE SIGNAL ;
    PORT
      LAYER M5 ;
        RECT  87.312 25.836 87.336 25.92 ;
    END
  END fd_in[322]
  PIN fd_in[323]
    DIRECTION INPUT ;
    USE SIGNAL ;
    PORT
      LAYER M5 ;
        RECT  87.504 25.836 87.528 25.92 ;
    END
  END fd_in[323]
  PIN fd_in[324]
    DIRECTION INPUT ;
    USE SIGNAL ;
    PORT
      LAYER M5 ;
        RECT  87.648 25.836 87.672 25.92 ;
    END
  END fd_in[324]
  PIN fd_in[325]
    DIRECTION INPUT ;
    USE SIGNAL ;
    PORT
      LAYER M5 ;
        RECT  87.84 25.836 87.864 25.92 ;
    END
  END fd_in[325]
  PIN fd_in[326]
    DIRECTION INPUT ;
    USE SIGNAL ;
    PORT
      LAYER M5 ;
        RECT  88.032 25.836 88.056 25.92 ;
    END
  END fd_in[326]
  PIN fd_in[327]
    DIRECTION INPUT ;
    USE SIGNAL ;
    PORT
      LAYER M5 ;
        RECT  88.224 25.836 88.248 25.92 ;
    END
  END fd_in[327]
  PIN fd_in[328]
    DIRECTION INPUT ;
    USE SIGNAL ;
    PORT
      LAYER M5 ;
        RECT  88.368 25.836 88.392 25.92 ;
    END
  END fd_in[328]
  PIN fd_in[329]
    DIRECTION INPUT ;
    USE SIGNAL ;
    PORT
      LAYER M5 ;
        RECT  88.56 25.836 88.584 25.92 ;
    END
  END fd_in[329]
  PIN fd_in[32]
    DIRECTION INPUT ;
    USE SIGNAL ;
    PORT
      LAYER M5 ;
        RECT  124.272 25.836 124.296 25.92 ;
    END
  END fd_in[32]
  PIN fd_in[330]
    DIRECTION INPUT ;
    USE SIGNAL ;
    PORT
      LAYER M5 ;
        RECT  88.752 25.836 88.776 25.92 ;
    END
  END fd_in[330]
  PIN fd_in[331]
    DIRECTION INPUT ;
    USE SIGNAL ;
    PORT
      LAYER M5 ;
        RECT  88.944 25.836 88.968 25.92 ;
    END
  END fd_in[331]
  PIN fd_in[332]
    DIRECTION INPUT ;
    USE SIGNAL ;
    PORT
      LAYER M5 ;
        RECT  89.088 25.836 89.112 25.92 ;
    END
  END fd_in[332]
  PIN fd_in[333]
    DIRECTION INPUT ;
    USE SIGNAL ;
    PORT
      LAYER M5 ;
        RECT  89.28 25.836 89.304 25.92 ;
    END
  END fd_in[333]
  PIN fd_in[334]
    DIRECTION INPUT ;
    USE SIGNAL ;
    PORT
      LAYER M5 ;
        RECT  89.472 25.836 89.496 25.92 ;
    END
  END fd_in[334]
  PIN fd_in[335]
    DIRECTION INPUT ;
    USE SIGNAL ;
    PORT
      LAYER M5 ;
        RECT  89.664 25.836 89.688 25.92 ;
    END
  END fd_in[335]
  PIN fd_in[336]
    DIRECTION INPUT ;
    USE SIGNAL ;
    PORT
      LAYER M5 ;
        RECT  95.568 25.836 95.592 25.92 ;
    END
  END fd_in[336]
  PIN fd_in[337]
    DIRECTION INPUT ;
    USE SIGNAL ;
    PORT
      LAYER M5 ;
        RECT  95.76 25.836 95.784 25.92 ;
    END
  END fd_in[337]
  PIN fd_in[338]
    DIRECTION INPUT ;
    USE SIGNAL ;
    PORT
      LAYER M5 ;
        RECT  95.904 25.836 95.928 25.92 ;
    END
  END fd_in[338]
  PIN fd_in[339]
    DIRECTION INPUT ;
    USE SIGNAL ;
    PORT
      LAYER M5 ;
        RECT  96.096 25.836 96.12 25.92 ;
    END
  END fd_in[339]
  PIN fd_in[33]
    DIRECTION INPUT ;
    USE SIGNAL ;
    PORT
      LAYER M5 ;
        RECT  124.416 25.836 124.44 25.92 ;
    END
  END fd_in[33]
  PIN fd_in[340]
    DIRECTION INPUT ;
    USE SIGNAL ;
    PORT
      LAYER M5 ;
        RECT  96.288 25.836 96.312 25.92 ;
    END
  END fd_in[340]
  PIN fd_in[341]
    DIRECTION INPUT ;
    USE SIGNAL ;
    PORT
      LAYER M5 ;
        RECT  96.48 25.836 96.504 25.92 ;
    END
  END fd_in[341]
  PIN fd_in[342]
    DIRECTION INPUT ;
    USE SIGNAL ;
    PORT
      LAYER M5 ;
        RECT  96.624 25.836 96.648 25.92 ;
    END
  END fd_in[342]
  PIN fd_in[343]
    DIRECTION INPUT ;
    USE SIGNAL ;
    PORT
      LAYER M5 ;
        RECT  96.816 25.836 96.84 25.92 ;
    END
  END fd_in[343]
  PIN fd_in[344]
    DIRECTION INPUT ;
    USE SIGNAL ;
    PORT
      LAYER M5 ;
        RECT  97.008 25.836 97.032 25.92 ;
    END
  END fd_in[344]
  PIN fd_in[345]
    DIRECTION INPUT ;
    USE SIGNAL ;
    PORT
      LAYER M5 ;
        RECT  97.152 25.836 97.176 25.92 ;
    END
  END fd_in[345]
  PIN fd_in[346]
    DIRECTION INPUT ;
    USE SIGNAL ;
    PORT
      LAYER M5 ;
        RECT  97.344 25.836 97.368 25.92 ;
    END
  END fd_in[346]
  PIN fd_in[347]
    DIRECTION INPUT ;
    USE SIGNAL ;
    PORT
      LAYER M5 ;
        RECT  97.536 25.836 97.56 25.92 ;
    END
  END fd_in[347]
  PIN fd_in[348]
    DIRECTION INPUT ;
    USE SIGNAL ;
    PORT
      LAYER M5 ;
        RECT  97.728 25.836 97.752 25.92 ;
    END
  END fd_in[348]
  PIN fd_in[349]
    DIRECTION INPUT ;
    USE SIGNAL ;
    PORT
      LAYER M5 ;
        RECT  97.872 25.836 97.896 25.92 ;
    END
  END fd_in[349]
  PIN fd_in[34]
    DIRECTION INPUT ;
    USE SIGNAL ;
    PORT
      LAYER M5 ;
        RECT  124.608 25.836 124.632 25.92 ;
    END
  END fd_in[34]
  PIN fd_in[350]
    DIRECTION INPUT ;
    USE SIGNAL ;
    PORT
      LAYER M5 ;
        RECT  98.064 25.836 98.088 25.92 ;
    END
  END fd_in[350]
  PIN fd_in[351]
    DIRECTION INPUT ;
    USE SIGNAL ;
    PORT
      LAYER M5 ;
        RECT  98.256 25.836 98.28 25.92 ;
    END
  END fd_in[351]
  PIN fd_in[352]
    DIRECTION INPUT ;
    USE SIGNAL ;
    PORT
      LAYER M5 ;
        RECT  98.448 25.836 98.472 25.92 ;
    END
  END fd_in[352]
  PIN fd_in[353]
    DIRECTION INPUT ;
    USE SIGNAL ;
    PORT
      LAYER M5 ;
        RECT  98.592 25.836 98.616 25.92 ;
    END
  END fd_in[353]
  PIN fd_in[354]
    DIRECTION INPUT ;
    USE SIGNAL ;
    PORT
      LAYER M5 ;
        RECT  98.784 25.836 98.808 25.92 ;
    END
  END fd_in[354]
  PIN fd_in[355]
    DIRECTION INPUT ;
    USE SIGNAL ;
    PORT
      LAYER M5 ;
        RECT  98.976 25.836 99 25.92 ;
    END
  END fd_in[355]
  PIN fd_in[356]
    DIRECTION INPUT ;
    USE SIGNAL ;
    PORT
      LAYER M5 ;
        RECT  99.168 25.836 99.192 25.92 ;
    END
  END fd_in[356]
  PIN fd_in[357]
    DIRECTION INPUT ;
    USE SIGNAL ;
    PORT
      LAYER M5 ;
        RECT  99.312 25.836 99.336 25.92 ;
    END
  END fd_in[357]
  PIN fd_in[358]
    DIRECTION INPUT ;
    USE SIGNAL ;
    PORT
      LAYER M5 ;
        RECT  99.504 25.836 99.528 25.92 ;
    END
  END fd_in[358]
  PIN fd_in[359]
    DIRECTION INPUT ;
    USE SIGNAL ;
    PORT
      LAYER M5 ;
        RECT  99.696 25.836 99.72 25.92 ;
    END
  END fd_in[359]
  PIN fd_in[35]
    DIRECTION INPUT ;
    USE SIGNAL ;
    PORT
      LAYER M5 ;
        RECT  124.8 25.836 124.824 25.92 ;
    END
  END fd_in[35]
  PIN fd_in[360]
    DIRECTION INPUT ;
    USE SIGNAL ;
    PORT
      LAYER M5 ;
        RECT  99.84 25.836 99.864 25.92 ;
    END
  END fd_in[360]
  PIN fd_in[361]
    DIRECTION INPUT ;
    USE SIGNAL ;
    PORT
      LAYER M5 ;
        RECT  100.032 25.836 100.056 25.92 ;
    END
  END fd_in[361]
  PIN fd_in[362]
    DIRECTION INPUT ;
    USE SIGNAL ;
    PORT
      LAYER M5 ;
        RECT  100.224 25.836 100.248 25.92 ;
    END
  END fd_in[362]
  PIN fd_in[363]
    DIRECTION INPUT ;
    USE SIGNAL ;
    PORT
      LAYER M5 ;
        RECT  100.416 25.836 100.44 25.92 ;
    END
  END fd_in[363]
  PIN fd_in[364]
    DIRECTION INPUT ;
    USE SIGNAL ;
    PORT
      LAYER M5 ;
        RECT  100.56 25.836 100.584 25.92 ;
    END
  END fd_in[364]
  PIN fd_in[365]
    DIRECTION INPUT ;
    USE SIGNAL ;
    PORT
      LAYER M5 ;
        RECT  100.752 25.836 100.776 25.92 ;
    END
  END fd_in[365]
  PIN fd_in[366]
    DIRECTION INPUT ;
    USE SIGNAL ;
    PORT
      LAYER M5 ;
        RECT  100.944 25.836 100.968 25.92 ;
    END
  END fd_in[366]
  PIN fd_in[367]
    DIRECTION INPUT ;
    USE SIGNAL ;
    PORT
      LAYER M5 ;
        RECT  101.136 25.836 101.16 25.92 ;
    END
  END fd_in[367]
  PIN fd_in[368]
    DIRECTION INPUT ;
    USE SIGNAL ;
    PORT
      LAYER M5 ;
        RECT  43.92 25.836 43.944 25.92 ;
    END
  END fd_in[368]
  PIN fd_in[369]
    DIRECTION INPUT ;
    USE SIGNAL ;
    PORT
      LAYER M5 ;
        RECT  44.112 25.836 44.136 25.92 ;
    END
  END fd_in[369]
  PIN fd_in[36]
    DIRECTION INPUT ;
    USE SIGNAL ;
    PORT
      LAYER M5 ;
        RECT  124.992 25.836 125.016 25.92 ;
    END
  END fd_in[36]
  PIN fd_in[370]
    DIRECTION INPUT ;
    USE SIGNAL ;
    PORT
      LAYER M5 ;
        RECT  44.256 25.836 44.28 25.92 ;
    END
  END fd_in[370]
  PIN fd_in[371]
    DIRECTION INPUT ;
    USE SIGNAL ;
    PORT
      LAYER M5 ;
        RECT  44.448 25.836 44.472 25.92 ;
    END
  END fd_in[371]
  PIN fd_in[372]
    DIRECTION INPUT ;
    USE SIGNAL ;
    PORT
      LAYER M5 ;
        RECT  44.64 25.836 44.664 25.92 ;
    END
  END fd_in[372]
  PIN fd_in[373]
    DIRECTION INPUT ;
    USE SIGNAL ;
    PORT
      LAYER M5 ;
        RECT  44.784 25.836 44.808 25.92 ;
    END
  END fd_in[373]
  PIN fd_in[374]
    DIRECTION INPUT ;
    USE SIGNAL ;
    PORT
      LAYER M5 ;
        RECT  44.976 25.836 45 25.92 ;
    END
  END fd_in[374]
  PIN fd_in[375]
    DIRECTION INPUT ;
    USE SIGNAL ;
    PORT
      LAYER M5 ;
        RECT  45.168 25.836 45.192 25.92 ;
    END
  END fd_in[375]
  PIN fd_in[376]
    DIRECTION INPUT ;
    USE SIGNAL ;
    PORT
      LAYER M5 ;
        RECT  45.36 25.836 45.384 25.92 ;
    END
  END fd_in[376]
  PIN fd_in[377]
    DIRECTION INPUT ;
    USE SIGNAL ;
    PORT
      LAYER M5 ;
        RECT  45.504 25.836 45.528 25.92 ;
    END
  END fd_in[377]
  PIN fd_in[378]
    DIRECTION INPUT ;
    USE SIGNAL ;
    PORT
      LAYER M5 ;
        RECT  45.696 25.836 45.72 25.92 ;
    END
  END fd_in[378]
  PIN fd_in[379]
    DIRECTION INPUT ;
    USE SIGNAL ;
    PORT
      LAYER M5 ;
        RECT  45.888 25.836 45.912 25.92 ;
    END
  END fd_in[379]
  PIN fd_in[37]
    DIRECTION INPUT ;
    USE SIGNAL ;
    PORT
      LAYER M5 ;
        RECT  125.136 25.836 125.16 25.92 ;
    END
  END fd_in[37]
  PIN fd_in[380]
    DIRECTION INPUT ;
    USE SIGNAL ;
    PORT
      LAYER M5 ;
        RECT  46.08 25.836 46.104 25.92 ;
    END
  END fd_in[380]
  PIN fd_in[381]
    DIRECTION INPUT ;
    USE SIGNAL ;
    PORT
      LAYER M5 ;
        RECT  46.224 25.836 46.248 25.92 ;
    END
  END fd_in[381]
  PIN fd_in[382]
    DIRECTION INPUT ;
    USE SIGNAL ;
    PORT
      LAYER M5 ;
        RECT  46.416 25.836 46.44 25.92 ;
    END
  END fd_in[382]
  PIN fd_in[383]
    DIRECTION INPUT ;
    USE SIGNAL ;
    PORT
      LAYER M5 ;
        RECT  46.608 25.836 46.632 25.92 ;
    END
  END fd_in[383]
  PIN fd_in[384]
    DIRECTION INPUT ;
    USE SIGNAL ;
    PORT
      LAYER M5 ;
        RECT  46.8 25.836 46.824 25.92 ;
    END
  END fd_in[384]
  PIN fd_in[385]
    DIRECTION INPUT ;
    USE SIGNAL ;
    PORT
      LAYER M5 ;
        RECT  46.944 25.836 46.968 25.92 ;
    END
  END fd_in[385]
  PIN fd_in[386]
    DIRECTION INPUT ;
    USE SIGNAL ;
    PORT
      LAYER M5 ;
        RECT  47.136 25.836 47.16 25.92 ;
    END
  END fd_in[386]
  PIN fd_in[387]
    DIRECTION INPUT ;
    USE SIGNAL ;
    PORT
      LAYER M5 ;
        RECT  47.328 25.836 47.352 25.92 ;
    END
  END fd_in[387]
  PIN fd_in[388]
    DIRECTION INPUT ;
    USE SIGNAL ;
    PORT
      LAYER M5 ;
        RECT  47.472 25.836 47.496 25.92 ;
    END
  END fd_in[388]
  PIN fd_in[389]
    DIRECTION INPUT ;
    USE SIGNAL ;
    PORT
      LAYER M5 ;
        RECT  47.664 25.836 47.688 25.92 ;
    END
  END fd_in[389]
  PIN fd_in[38]
    DIRECTION INPUT ;
    USE SIGNAL ;
    PORT
      LAYER M5 ;
        RECT  125.328 25.836 125.352 25.92 ;
    END
  END fd_in[38]
  PIN fd_in[390]
    DIRECTION INPUT ;
    USE SIGNAL ;
    PORT
      LAYER M5 ;
        RECT  47.856 25.836 47.88 25.92 ;
    END
  END fd_in[390]
  PIN fd_in[391]
    DIRECTION INPUT ;
    USE SIGNAL ;
    PORT
      LAYER M5 ;
        RECT  48.048 25.836 48.072 25.92 ;
    END
  END fd_in[391]
  PIN fd_in[392]
    DIRECTION INPUT ;
    USE SIGNAL ;
    PORT
      LAYER M5 ;
        RECT  48.192 25.836 48.216 25.92 ;
    END
  END fd_in[392]
  PIN fd_in[393]
    DIRECTION INPUT ;
    USE SIGNAL ;
    PORT
      LAYER M5 ;
        RECT  48.384 25.836 48.408 25.92 ;
    END
  END fd_in[393]
  PIN fd_in[394]
    DIRECTION INPUT ;
    USE SIGNAL ;
    PORT
      LAYER M5 ;
        RECT  48.576 25.836 48.6 25.92 ;
    END
  END fd_in[394]
  PIN fd_in[395]
    DIRECTION INPUT ;
    USE SIGNAL ;
    PORT
      LAYER M5 ;
        RECT  48.768 25.836 48.792 25.92 ;
    END
  END fd_in[395]
  PIN fd_in[396]
    DIRECTION INPUT ;
    USE SIGNAL ;
    PORT
      LAYER M5 ;
        RECT  48.912 25.836 48.936 25.92 ;
    END
  END fd_in[396]
  PIN fd_in[397]
    DIRECTION INPUT ;
    USE SIGNAL ;
    PORT
      LAYER M5 ;
        RECT  49.104 25.836 49.128 25.92 ;
    END
  END fd_in[397]
  PIN fd_in[398]
    DIRECTION INPUT ;
    USE SIGNAL ;
    PORT
      LAYER M5 ;
        RECT  49.296 25.836 49.32 25.92 ;
    END
  END fd_in[398]
  PIN fd_in[399]
    DIRECTION INPUT ;
    USE SIGNAL ;
    PORT
      LAYER M5 ;
        RECT  49.488 25.836 49.512 25.92 ;
    END
  END fd_in[399]
  PIN fd_in[39]
    DIRECTION INPUT ;
    USE SIGNAL ;
    PORT
      LAYER M5 ;
        RECT  125.52 25.836 125.544 25.92 ;
    END
  END fd_in[39]
  PIN fd_in[3]
    DIRECTION INPUT ;
    USE SIGNAL ;
    PORT
      LAYER M5 ;
        RECT  130.512 25.836 130.536 25.92 ;
    END
  END fd_in[3]
  PIN fd_in[400]
    DIRECTION INPUT ;
    USE SIGNAL ;
    PORT
      LAYER M5 ;
        RECT  49.632 25.836 49.656 25.92 ;
    END
  END fd_in[400]
  PIN fd_in[401]
    DIRECTION INPUT ;
    USE SIGNAL ;
    PORT
      LAYER M5 ;
        RECT  49.824 25.836 49.848 25.92 ;
    END
  END fd_in[401]
  PIN fd_in[402]
    DIRECTION INPUT ;
    USE SIGNAL ;
    PORT
      LAYER M5 ;
        RECT  50.016 25.836 50.04 25.92 ;
    END
  END fd_in[402]
  PIN fd_in[403]
    DIRECTION INPUT ;
    USE SIGNAL ;
    PORT
      LAYER M5 ;
        RECT  50.208 25.836 50.232 25.92 ;
    END
  END fd_in[403]
  PIN fd_in[404]
    DIRECTION INPUT ;
    USE SIGNAL ;
    PORT
      LAYER M5 ;
        RECT  50.352 25.836 50.376 25.92 ;
    END
  END fd_in[404]
  PIN fd_in[405]
    DIRECTION INPUT ;
    USE SIGNAL ;
    PORT
      LAYER M5 ;
        RECT  50.544 25.836 50.568 25.92 ;
    END
  END fd_in[405]
  PIN fd_in[406]
    DIRECTION INPUT ;
    USE SIGNAL ;
    PORT
      LAYER M5 ;
        RECT  50.736 25.836 50.76 25.92 ;
    END
  END fd_in[406]
  PIN fd_in[407]
    DIRECTION INPUT ;
    USE SIGNAL ;
    PORT
      LAYER M5 ;
        RECT  50.88 25.836 50.904 25.92 ;
    END
  END fd_in[407]
  PIN fd_in[408]
    DIRECTION INPUT ;
    USE SIGNAL ;
    PORT
      LAYER M5 ;
        RECT  51.072 25.836 51.096 25.92 ;
    END
  END fd_in[408]
  PIN fd_in[409]
    DIRECTION INPUT ;
    USE SIGNAL ;
    PORT
      LAYER M5 ;
        RECT  51.264 25.836 51.288 25.92 ;
    END
  END fd_in[409]
  PIN fd_in[40]
    DIRECTION INPUT ;
    USE SIGNAL ;
    PORT
      LAYER M5 ;
        RECT  125.712 25.836 125.736 25.92 ;
    END
  END fd_in[40]
  PIN fd_in[410]
    DIRECTION INPUT ;
    USE SIGNAL ;
    PORT
      LAYER M5 ;
        RECT  51.456 25.836 51.48 25.92 ;
    END
  END fd_in[410]
  PIN fd_in[411]
    DIRECTION INPUT ;
    USE SIGNAL ;
    PORT
      LAYER M5 ;
        RECT  51.6 25.836 51.624 25.92 ;
    END
  END fd_in[411]
  PIN fd_in[412]
    DIRECTION INPUT ;
    USE SIGNAL ;
    PORT
      LAYER M5 ;
        RECT  51.792 25.836 51.816 25.92 ;
    END
  END fd_in[412]
  PIN fd_in[413]
    DIRECTION INPUT ;
    USE SIGNAL ;
    PORT
      LAYER M5 ;
        RECT  51.984 25.836 52.008 25.92 ;
    END
  END fd_in[413]
  PIN fd_in[414]
    DIRECTION INPUT ;
    USE SIGNAL ;
    PORT
      LAYER M5 ;
        RECT  52.176 25.836 52.2 25.92 ;
    END
  END fd_in[414]
  PIN fd_in[415]
    DIRECTION INPUT ;
    USE SIGNAL ;
    PORT
      LAYER M5 ;
        RECT  52.32 25.836 52.344 25.92 ;
    END
  END fd_in[415]
  PIN fd_in[416]
    DIRECTION INPUT ;
    USE SIGNAL ;
    PORT
      LAYER M5 ;
        RECT  52.512 25.836 52.536 25.92 ;
    END
  END fd_in[416]
  PIN fd_in[417]
    DIRECTION INPUT ;
    USE SIGNAL ;
    PORT
      LAYER M5 ;
        RECT  52.704 25.836 52.728 25.92 ;
    END
  END fd_in[417]
  PIN fd_in[418]
    DIRECTION INPUT ;
    USE SIGNAL ;
    PORT
      LAYER M5 ;
        RECT  52.896 25.836 52.92 25.92 ;
    END
  END fd_in[418]
  PIN fd_in[419]
    DIRECTION INPUT ;
    USE SIGNAL ;
    PORT
      LAYER M5 ;
        RECT  53.04 25.836 53.064 25.92 ;
    END
  END fd_in[419]
  PIN fd_in[41]
    DIRECTION INPUT ;
    USE SIGNAL ;
    PORT
      LAYER M5 ;
        RECT  125.856 25.836 125.88 25.92 ;
    END
  END fd_in[41]
  PIN fd_in[420]
    DIRECTION INPUT ;
    USE SIGNAL ;
    PORT
      LAYER M5 ;
        RECT  53.232 25.836 53.256 25.92 ;
    END
  END fd_in[420]
  PIN fd_in[421]
    DIRECTION INPUT ;
    USE SIGNAL ;
    PORT
      LAYER M5 ;
        RECT  53.424 25.836 53.448 25.92 ;
    END
  END fd_in[421]
  PIN fd_in[422]
    DIRECTION INPUT ;
    USE SIGNAL ;
    PORT
      LAYER M5 ;
        RECT  53.616 25.836 53.64 25.92 ;
    END
  END fd_in[422]
  PIN fd_in[423]
    DIRECTION INPUT ;
    USE SIGNAL ;
    PORT
      LAYER M5 ;
        RECT  53.76 25.836 53.784 25.92 ;
    END
  END fd_in[423]
  PIN fd_in[424]
    DIRECTION INPUT ;
    USE SIGNAL ;
    PORT
      LAYER M5 ;
        RECT  53.952 25.836 53.976 25.92 ;
    END
  END fd_in[424]
  PIN fd_in[425]
    DIRECTION INPUT ;
    USE SIGNAL ;
    PORT
      LAYER M5 ;
        RECT  54.144 25.836 54.168 25.92 ;
    END
  END fd_in[425]
  PIN fd_in[426]
    DIRECTION INPUT ;
    USE SIGNAL ;
    PORT
      LAYER M5 ;
        RECT  54.288 25.836 54.312 25.92 ;
    END
  END fd_in[426]
  PIN fd_in[427]
    DIRECTION INPUT ;
    USE SIGNAL ;
    PORT
      LAYER M5 ;
        RECT  54.48 25.836 54.504 25.92 ;
    END
  END fd_in[427]
  PIN fd_in[428]
    DIRECTION INPUT ;
    USE SIGNAL ;
    PORT
      LAYER M5 ;
        RECT  54.672 25.836 54.696 25.92 ;
    END
  END fd_in[428]
  PIN fd_in[429]
    DIRECTION INPUT ;
    USE SIGNAL ;
    PORT
      LAYER M5 ;
        RECT  54.864 25.836 54.888 25.92 ;
    END
  END fd_in[429]
  PIN fd_in[42]
    DIRECTION INPUT ;
    USE SIGNAL ;
    PORT
      LAYER M5 ;
        RECT  126.048 25.836 126.072 25.92 ;
    END
  END fd_in[42]
  PIN fd_in[430]
    DIRECTION INPUT ;
    USE SIGNAL ;
    PORT
      LAYER M5 ;
        RECT  55.008 25.836 55.032 25.92 ;
    END
  END fd_in[430]
  PIN fd_in[431]
    DIRECTION INPUT ;
    USE SIGNAL ;
    PORT
      LAYER M5 ;
        RECT  55.2 25.836 55.224 25.92 ;
    END
  END fd_in[431]
  PIN fd_in[432]
    DIRECTION INPUT ;
    USE SIGNAL ;
    PORT
      LAYER M5 ;
        RECT  72.624 25.836 72.648 25.92 ;
    END
  END fd_in[432]
  PIN fd_in[433]
    DIRECTION INPUT ;
    USE SIGNAL ;
    PORT
      LAYER M5 ;
        RECT  72.768 25.836 72.792 25.92 ;
    END
  END fd_in[433]
  PIN fd_in[434]
    DIRECTION INPUT ;
    USE SIGNAL ;
    PORT
      LAYER M5 ;
        RECT  72.96 25.836 72.984 25.92 ;
    END
  END fd_in[434]
  PIN fd_in[435]
    DIRECTION INPUT ;
    USE SIGNAL ;
    PORT
      LAYER M5 ;
        RECT  73.152 25.836 73.176 25.92 ;
    END
  END fd_in[435]
  PIN fd_in[436]
    DIRECTION INPUT ;
    USE SIGNAL ;
    PORT
      LAYER M5 ;
        RECT  73.344 25.836 73.368 25.92 ;
    END
  END fd_in[436]
  PIN fd_in[437]
    DIRECTION INPUT ;
    USE SIGNAL ;
    PORT
      LAYER M5 ;
        RECT  73.488 25.836 73.512 25.92 ;
    END
  END fd_in[437]
  PIN fd_in[438]
    DIRECTION INPUT ;
    USE SIGNAL ;
    PORT
      LAYER M5 ;
        RECT  73.68 25.836 73.704 25.92 ;
    END
  END fd_in[438]
  PIN fd_in[439]
    DIRECTION INPUT ;
    USE SIGNAL ;
    PORT
      LAYER M5 ;
        RECT  73.872 25.836 73.896 25.92 ;
    END
  END fd_in[439]
  PIN fd_in[43]
    DIRECTION INPUT ;
    USE SIGNAL ;
    PORT
      LAYER M5 ;
        RECT  126.24 25.836 126.264 25.92 ;
    END
  END fd_in[43]
  PIN fd_in[440]
    DIRECTION INPUT ;
    USE SIGNAL ;
    PORT
      LAYER M5 ;
        RECT  74.016 25.836 74.04 25.92 ;
    END
  END fd_in[440]
  PIN fd_in[441]
    DIRECTION INPUT ;
    USE SIGNAL ;
    PORT
      LAYER M5 ;
        RECT  74.208 25.836 74.232 25.92 ;
    END
  END fd_in[441]
  PIN fd_in[442]
    DIRECTION INPUT ;
    USE SIGNAL ;
    PORT
      LAYER M5 ;
        RECT  74.4 25.836 74.424 25.92 ;
    END
  END fd_in[442]
  PIN fd_in[443]
    DIRECTION INPUT ;
    USE SIGNAL ;
    PORT
      LAYER M5 ;
        RECT  74.592 25.836 74.616 25.92 ;
    END
  END fd_in[443]
  PIN fd_in[444]
    DIRECTION INPUT ;
    USE SIGNAL ;
    PORT
      LAYER M5 ;
        RECT  74.736 25.836 74.76 25.92 ;
    END
  END fd_in[444]
  PIN fd_in[445]
    DIRECTION INPUT ;
    USE SIGNAL ;
    PORT
      LAYER M5 ;
        RECT  74.928 25.836 74.952 25.92 ;
    END
  END fd_in[445]
  PIN fd_in[446]
    DIRECTION INPUT ;
    USE SIGNAL ;
    PORT
      LAYER M5 ;
        RECT  75.12 25.836 75.144 25.92 ;
    END
  END fd_in[446]
  PIN fd_in[447]
    DIRECTION INPUT ;
    USE SIGNAL ;
    PORT
      LAYER M5 ;
        RECT  75.312 25.836 75.336 25.92 ;
    END
  END fd_in[447]
  PIN fd_in[448]
    DIRECTION INPUT ;
    USE SIGNAL ;
    PORT
      LAYER M5 ;
        RECT  75.456 25.836 75.48 25.92 ;
    END
  END fd_in[448]
  PIN fd_in[449]
    DIRECTION INPUT ;
    USE SIGNAL ;
    PORT
      LAYER M5 ;
        RECT  75.648 25.836 75.672 25.92 ;
    END
  END fd_in[449]
  PIN fd_in[44]
    DIRECTION INPUT ;
    USE SIGNAL ;
    PORT
      LAYER M5 ;
        RECT  126.384 25.836 126.408 25.92 ;
    END
  END fd_in[44]
  PIN fd_in[450]
    DIRECTION INPUT ;
    USE SIGNAL ;
    PORT
      LAYER M5 ;
        RECT  75.84 25.836 75.864 25.92 ;
    END
  END fd_in[450]
  PIN fd_in[451]
    DIRECTION INPUT ;
    USE SIGNAL ;
    PORT
      LAYER M5 ;
        RECT  76.032 25.836 76.056 25.92 ;
    END
  END fd_in[451]
  PIN fd_in[452]
    DIRECTION INPUT ;
    USE SIGNAL ;
    PORT
      LAYER M5 ;
        RECT  76.176 25.836 76.2 25.92 ;
    END
  END fd_in[452]
  PIN fd_in[453]
    DIRECTION INPUT ;
    USE SIGNAL ;
    PORT
      LAYER M5 ;
        RECT  76.368 25.836 76.392 25.92 ;
    END
  END fd_in[453]
  PIN fd_in[454]
    DIRECTION INPUT ;
    USE SIGNAL ;
    PORT
      LAYER M5 ;
        RECT  76.56 25.836 76.584 25.92 ;
    END
  END fd_in[454]
  PIN fd_in[455]
    DIRECTION INPUT ;
    USE SIGNAL ;
    PORT
      LAYER M5 ;
        RECT  76.752 25.836 76.776 25.92 ;
    END
  END fd_in[455]
  PIN fd_in[456]
    DIRECTION INPUT ;
    USE SIGNAL ;
    PORT
      LAYER M5 ;
        RECT  76.896 25.836 76.92 25.92 ;
    END
  END fd_in[456]
  PIN fd_in[457]
    DIRECTION INPUT ;
    USE SIGNAL ;
    PORT
      LAYER M5 ;
        RECT  77.088 25.836 77.112 25.92 ;
    END
  END fd_in[457]
  PIN fd_in[458]
    DIRECTION INPUT ;
    USE SIGNAL ;
    PORT
      LAYER M5 ;
        RECT  77.28 25.836 77.304 25.92 ;
    END
  END fd_in[458]
  PIN fd_in[459]
    DIRECTION INPUT ;
    USE SIGNAL ;
    PORT
      LAYER M5 ;
        RECT  77.424 25.836 77.448 25.92 ;
    END
  END fd_in[459]
  PIN fd_in[45]
    DIRECTION INPUT ;
    USE SIGNAL ;
    PORT
      LAYER M5 ;
        RECT  126.576 25.836 126.6 25.92 ;
    END
  END fd_in[45]
  PIN fd_in[460]
    DIRECTION INPUT ;
    USE SIGNAL ;
    PORT
      LAYER M5 ;
        RECT  77.616 25.836 77.64 25.92 ;
    END
  END fd_in[460]
  PIN fd_in[461]
    DIRECTION INPUT ;
    USE SIGNAL ;
    PORT
      LAYER M5 ;
        RECT  77.808 25.836 77.832 25.92 ;
    END
  END fd_in[461]
  PIN fd_in[462]
    DIRECTION INPUT ;
    USE SIGNAL ;
    PORT
      LAYER M5 ;
        RECT  78 25.836 78.024 25.92 ;
    END
  END fd_in[462]
  PIN fd_in[463]
    DIRECTION INPUT ;
    USE SIGNAL ;
    PORT
      LAYER M5 ;
        RECT  78.144 25.836 78.168 25.92 ;
    END
  END fd_in[463]
  PIN fd_in[464]
    DIRECTION INPUT ;
    USE SIGNAL ;
    PORT
      LAYER M5 ;
        RECT  61.104 25.836 61.128 25.92 ;
    END
  END fd_in[464]
  PIN fd_in[465]
    DIRECTION INPUT ;
    USE SIGNAL ;
    PORT
      LAYER M5 ;
        RECT  61.296 25.836 61.32 25.92 ;
    END
  END fd_in[465]
  PIN fd_in[466]
    DIRECTION INPUT ;
    USE SIGNAL ;
    PORT
      LAYER M5 ;
        RECT  61.488 25.836 61.512 25.92 ;
    END
  END fd_in[466]
  PIN fd_in[467]
    DIRECTION INPUT ;
    USE SIGNAL ;
    PORT
      LAYER M5 ;
        RECT  61.68 25.836 61.704 25.92 ;
    END
  END fd_in[467]
  PIN fd_in[468]
    DIRECTION INPUT ;
    USE SIGNAL ;
    PORT
      LAYER M5 ;
        RECT  61.824 25.836 61.848 25.92 ;
    END
  END fd_in[468]
  PIN fd_in[469]
    DIRECTION INPUT ;
    USE SIGNAL ;
    PORT
      LAYER M5 ;
        RECT  62.016 25.836 62.04 25.92 ;
    END
  END fd_in[469]
  PIN fd_in[46]
    DIRECTION INPUT ;
    USE SIGNAL ;
    PORT
      LAYER M5 ;
        RECT  126.768 25.836 126.792 25.92 ;
    END
  END fd_in[46]
  PIN fd_in[470]
    DIRECTION INPUT ;
    USE SIGNAL ;
    PORT
      LAYER M5 ;
        RECT  62.208 25.836 62.232 25.92 ;
    END
  END fd_in[470]
  PIN fd_in[471]
    DIRECTION INPUT ;
    USE SIGNAL ;
    PORT
      LAYER M5 ;
        RECT  62.4 25.836 62.424 25.92 ;
    END
  END fd_in[471]
  PIN fd_in[472]
    DIRECTION INPUT ;
    USE SIGNAL ;
    PORT
      LAYER M5 ;
        RECT  62.544 25.836 62.568 25.92 ;
    END
  END fd_in[472]
  PIN fd_in[473]
    DIRECTION INPUT ;
    USE SIGNAL ;
    PORT
      LAYER M5 ;
        RECT  62.736 25.836 62.76 25.92 ;
    END
  END fd_in[473]
  PIN fd_in[474]
    DIRECTION INPUT ;
    USE SIGNAL ;
    PORT
      LAYER M5 ;
        RECT  62.928 25.836 62.952 25.92 ;
    END
  END fd_in[474]
  PIN fd_in[475]
    DIRECTION INPUT ;
    USE SIGNAL ;
    PORT
      LAYER M5 ;
        RECT  63.12 25.836 63.144 25.92 ;
    END
  END fd_in[475]
  PIN fd_in[476]
    DIRECTION INPUT ;
    USE SIGNAL ;
    PORT
      LAYER M5 ;
        RECT  63.264 25.836 63.288 25.92 ;
    END
  END fd_in[476]
  PIN fd_in[477]
    DIRECTION INPUT ;
    USE SIGNAL ;
    PORT
      LAYER M5 ;
        RECT  63.456 25.836 63.48 25.92 ;
    END
  END fd_in[477]
  PIN fd_in[478]
    DIRECTION INPUT ;
    USE SIGNAL ;
    PORT
      LAYER M5 ;
        RECT  63.648 25.836 63.672 25.92 ;
    END
  END fd_in[478]
  PIN fd_in[479]
    DIRECTION INPUT ;
    USE SIGNAL ;
    PORT
      LAYER M5 ;
        RECT  63.84 25.836 63.864 25.92 ;
    END
  END fd_in[479]
  PIN fd_in[47]
    DIRECTION INPUT ;
    USE SIGNAL ;
    PORT
      LAYER M5 ;
        RECT  126.96 25.836 126.984 25.92 ;
    END
  END fd_in[47]
  PIN fd_in[480]
    DIRECTION INPUT ;
    USE SIGNAL ;
    PORT
      LAYER M5 ;
        RECT  63.984 25.836 64.008 25.92 ;
    END
  END fd_in[480]
  PIN fd_in[481]
    DIRECTION INPUT ;
    USE SIGNAL ;
    PORT
      LAYER M5 ;
        RECT  64.176 25.836 64.2 25.92 ;
    END
  END fd_in[481]
  PIN fd_in[482]
    DIRECTION INPUT ;
    USE SIGNAL ;
    PORT
      LAYER M5 ;
        RECT  64.368 25.836 64.392 25.92 ;
    END
  END fd_in[482]
  PIN fd_in[483]
    DIRECTION INPUT ;
    USE SIGNAL ;
    PORT
      LAYER M5 ;
        RECT  64.512 25.836 64.536 25.92 ;
    END
  END fd_in[483]
  PIN fd_in[484]
    DIRECTION INPUT ;
    USE SIGNAL ;
    PORT
      LAYER M5 ;
        RECT  64.704 25.836 64.728 25.92 ;
    END
  END fd_in[484]
  PIN fd_in[485]
    DIRECTION INPUT ;
    USE SIGNAL ;
    PORT
      LAYER M5 ;
        RECT  64.896 25.836 64.92 25.92 ;
    END
  END fd_in[485]
  PIN fd_in[486]
    DIRECTION INPUT ;
    USE SIGNAL ;
    PORT
      LAYER M5 ;
        RECT  65.088 25.836 65.112 25.92 ;
    END
  END fd_in[486]
  PIN fd_in[487]
    DIRECTION INPUT ;
    USE SIGNAL ;
    PORT
      LAYER M5 ;
        RECT  65.232 25.836 65.256 25.92 ;
    END
  END fd_in[487]
  PIN fd_in[488]
    DIRECTION INPUT ;
    USE SIGNAL ;
    PORT
      LAYER M5 ;
        RECT  65.424 25.836 65.448 25.92 ;
    END
  END fd_in[488]
  PIN fd_in[489]
    DIRECTION INPUT ;
    USE SIGNAL ;
    PORT
      LAYER M5 ;
        RECT  65.616 25.836 65.64 25.92 ;
    END
  END fd_in[489]
  PIN fd_in[48]
    DIRECTION INPUT ;
    USE SIGNAL ;
    PORT
      LAYER M5 ;
        RECT  127.104 25.836 127.128 25.92 ;
    END
  END fd_in[48]
  PIN fd_in[490]
    DIRECTION INPUT ;
    USE SIGNAL ;
    PORT
      LAYER M5 ;
        RECT  65.808 25.836 65.832 25.92 ;
    END
  END fd_in[490]
  PIN fd_in[491]
    DIRECTION INPUT ;
    USE SIGNAL ;
    PORT
      LAYER M5 ;
        RECT  65.952 25.836 65.976 25.92 ;
    END
  END fd_in[491]
  PIN fd_in[492]
    DIRECTION INPUT ;
    USE SIGNAL ;
    PORT
      LAYER M5 ;
        RECT  66.144 25.836 66.168 25.92 ;
    END
  END fd_in[492]
  PIN fd_in[493]
    DIRECTION INPUT ;
    USE SIGNAL ;
    PORT
      LAYER M5 ;
        RECT  66.336 25.836 66.36 25.92 ;
    END
  END fd_in[493]
  PIN fd_in[494]
    DIRECTION INPUT ;
    USE SIGNAL ;
    PORT
      LAYER M5 ;
        RECT  66.528 25.836 66.552 25.92 ;
    END
  END fd_in[494]
  PIN fd_in[495]
    DIRECTION INPUT ;
    USE SIGNAL ;
    PORT
      LAYER M5 ;
        RECT  66.672 25.836 66.696 25.92 ;
    END
  END fd_in[495]
  PIN fd_in[496]
    DIRECTION INPUT ;
    USE SIGNAL ;
    PORT
      LAYER M5 ;
        RECT  55.392 25.836 55.416 25.92 ;
    END
  END fd_in[496]
  PIN fd_in[497]
    DIRECTION INPUT ;
    USE SIGNAL ;
    PORT
      LAYER M5 ;
        RECT  55.584 25.836 55.608 25.92 ;
    END
  END fd_in[497]
  PIN fd_in[498]
    DIRECTION INPUT ;
    USE SIGNAL ;
    PORT
      LAYER M5 ;
        RECT  55.728 25.836 55.752 25.92 ;
    END
  END fd_in[498]
  PIN fd_in[499]
    DIRECTION INPUT ;
    USE SIGNAL ;
    PORT
      LAYER M5 ;
        RECT  55.92 25.836 55.944 25.92 ;
    END
  END fd_in[499]
  PIN fd_in[49]
    DIRECTION INPUT ;
    USE SIGNAL ;
    PORT
      LAYER M5 ;
        RECT  127.296 25.836 127.32 25.92 ;
    END
  END fd_in[49]
  PIN fd_in[4]
    DIRECTION INPUT ;
    USE SIGNAL ;
    PORT
      LAYER M5 ;
        RECT  130.704 25.836 130.728 25.92 ;
    END
  END fd_in[4]
  PIN fd_in[500]
    DIRECTION INPUT ;
    USE SIGNAL ;
    PORT
      LAYER M5 ;
        RECT  56.112 25.836 56.136 25.92 ;
    END
  END fd_in[500]
  PIN fd_in[501]
    DIRECTION INPUT ;
    USE SIGNAL ;
    PORT
      LAYER M5 ;
        RECT  56.304 25.836 56.328 25.92 ;
    END
  END fd_in[501]
  PIN fd_in[502]
    DIRECTION INPUT ;
    USE SIGNAL ;
    PORT
      LAYER M5 ;
        RECT  56.448 25.836 56.472 25.92 ;
    END
  END fd_in[502]
  PIN fd_in[503]
    DIRECTION INPUT ;
    USE SIGNAL ;
    PORT
      LAYER M5 ;
        RECT  56.64 25.836 56.664 25.92 ;
    END
  END fd_in[503]
  PIN fd_in[504]
    DIRECTION INPUT ;
    USE SIGNAL ;
    PORT
      LAYER M5 ;
        RECT  56.832 25.836 56.856 25.92 ;
    END
  END fd_in[504]
  PIN fd_in[505]
    DIRECTION INPUT ;
    USE SIGNAL ;
    PORT
      LAYER M5 ;
        RECT  57.024 25.836 57.048 25.92 ;
    END
  END fd_in[505]
  PIN fd_in[506]
    DIRECTION INPUT ;
    USE SIGNAL ;
    PORT
      LAYER M5 ;
        RECT  57.168 25.836 57.192 25.92 ;
    END
  END fd_in[506]
  PIN fd_in[507]
    DIRECTION INPUT ;
    USE SIGNAL ;
    PORT
      LAYER M5 ;
        RECT  57.36 25.836 57.384 25.92 ;
    END
  END fd_in[507]
  PIN fd_in[508]
    DIRECTION INPUT ;
    USE SIGNAL ;
    PORT
      LAYER M5 ;
        RECT  57.552 25.836 57.576 25.92 ;
    END
  END fd_in[508]
  PIN fd_in[509]
    DIRECTION INPUT ;
    USE SIGNAL ;
    PORT
      LAYER M5 ;
        RECT  57.696 25.836 57.72 25.92 ;
    END
  END fd_in[509]
  PIN fd_in[50]
    DIRECTION INPUT ;
    USE SIGNAL ;
    PORT
      LAYER M5 ;
        RECT  127.488 25.836 127.512 25.92 ;
    END
  END fd_in[50]
  PIN fd_in[510]
    DIRECTION INPUT ;
    USE SIGNAL ;
    PORT
      LAYER M5 ;
        RECT  57.888 25.836 57.912 25.92 ;
    END
  END fd_in[510]
  PIN fd_in[511]
    DIRECTION INPUT ;
    USE SIGNAL ;
    PORT
      LAYER M5 ;
        RECT  58.08 25.836 58.104 25.92 ;
    END
  END fd_in[511]
  PIN fd_in[512]
    DIRECTION INPUT ;
    USE SIGNAL ;
    PORT
      LAYER M5 ;
        RECT  58.272 25.836 58.296 25.92 ;
    END
  END fd_in[512]
  PIN fd_in[513]
    DIRECTION INPUT ;
    USE SIGNAL ;
    PORT
      LAYER M5 ;
        RECT  58.416 25.836 58.44 25.92 ;
    END
  END fd_in[513]
  PIN fd_in[514]
    DIRECTION INPUT ;
    USE SIGNAL ;
    PORT
      LAYER M5 ;
        RECT  58.608 25.836 58.632 25.92 ;
    END
  END fd_in[514]
  PIN fd_in[515]
    DIRECTION INPUT ;
    USE SIGNAL ;
    PORT
      LAYER M5 ;
        RECT  58.8 25.836 58.824 25.92 ;
    END
  END fd_in[515]
  PIN fd_in[516]
    DIRECTION INPUT ;
    USE SIGNAL ;
    PORT
      LAYER M5 ;
        RECT  58.992 25.836 59.016 25.92 ;
    END
  END fd_in[516]
  PIN fd_in[517]
    DIRECTION INPUT ;
    USE SIGNAL ;
    PORT
      LAYER M5 ;
        RECT  59.136 25.836 59.16 25.92 ;
    END
  END fd_in[517]
  PIN fd_in[518]
    DIRECTION INPUT ;
    USE SIGNAL ;
    PORT
      LAYER M5 ;
        RECT  59.328 25.836 59.352 25.92 ;
    END
  END fd_in[518]
  PIN fd_in[519]
    DIRECTION INPUT ;
    USE SIGNAL ;
    PORT
      LAYER M5 ;
        RECT  59.52 25.836 59.544 25.92 ;
    END
  END fd_in[519]
  PIN fd_in[51]
    DIRECTION INPUT ;
    USE SIGNAL ;
    PORT
      LAYER M5 ;
        RECT  127.68 25.836 127.704 25.92 ;
    END
  END fd_in[51]
  PIN fd_in[520]
    DIRECTION INPUT ;
    USE SIGNAL ;
    PORT
      LAYER M5 ;
        RECT  59.712 25.836 59.736 25.92 ;
    END
  END fd_in[520]
  PIN fd_in[521]
    DIRECTION INPUT ;
    USE SIGNAL ;
    PORT
      LAYER M5 ;
        RECT  59.856 25.836 59.88 25.92 ;
    END
  END fd_in[521]
  PIN fd_in[522]
    DIRECTION INPUT ;
    USE SIGNAL ;
    PORT
      LAYER M5 ;
        RECT  60.048 25.836 60.072 25.92 ;
    END
  END fd_in[522]
  PIN fd_in[523]
    DIRECTION INPUT ;
    USE SIGNAL ;
    PORT
      LAYER M5 ;
        RECT  60.24 25.836 60.264 25.92 ;
    END
  END fd_in[523]
  PIN fd_in[524]
    DIRECTION INPUT ;
    USE SIGNAL ;
    PORT
      LAYER M5 ;
        RECT  60.432 25.836 60.456 25.92 ;
    END
  END fd_in[524]
  PIN fd_in[525]
    DIRECTION INPUT ;
    USE SIGNAL ;
    PORT
      LAYER M5 ;
        RECT  60.576 25.836 60.6 25.92 ;
    END
  END fd_in[525]
  PIN fd_in[526]
    DIRECTION INPUT ;
    USE SIGNAL ;
    PORT
      LAYER M5 ;
        RECT  60.768 25.836 60.792 25.92 ;
    END
  END fd_in[526]
  PIN fd_in[527]
    DIRECTION INPUT ;
    USE SIGNAL ;
    PORT
      LAYER M5 ;
        RECT  60.96 25.836 60.984 25.92 ;
    END
  END fd_in[527]
  PIN fd_in[528]
    DIRECTION INPUT ;
    USE SIGNAL ;
    PORT
      LAYER M5 ;
        RECT  66.864 25.836 66.888 25.92 ;
    END
  END fd_in[528]
  PIN fd_in[529]
    DIRECTION INPUT ;
    USE SIGNAL ;
    PORT
      LAYER M5 ;
        RECT  67.056 25.836 67.08 25.92 ;
    END
  END fd_in[529]
  PIN fd_in[52]
    DIRECTION INPUT ;
    USE SIGNAL ;
    PORT
      LAYER M5 ;
        RECT  127.824 25.836 127.848 25.92 ;
    END
  END fd_in[52]
  PIN fd_in[530]
    DIRECTION INPUT ;
    USE SIGNAL ;
    PORT
      LAYER M5 ;
        RECT  67.2 25.836 67.224 25.92 ;
    END
  END fd_in[530]
  PIN fd_in[531]
    DIRECTION INPUT ;
    USE SIGNAL ;
    PORT
      LAYER M5 ;
        RECT  67.392 25.836 67.416 25.92 ;
    END
  END fd_in[531]
  PIN fd_in[532]
    DIRECTION INPUT ;
    USE SIGNAL ;
    PORT
      LAYER M5 ;
        RECT  67.584 25.836 67.608 25.92 ;
    END
  END fd_in[532]
  PIN fd_in[533]
    DIRECTION INPUT ;
    USE SIGNAL ;
    PORT
      LAYER M5 ;
        RECT  67.776 25.836 67.8 25.92 ;
    END
  END fd_in[533]
  PIN fd_in[534]
    DIRECTION INPUT ;
    USE SIGNAL ;
    PORT
      LAYER M5 ;
        RECT  67.92 25.836 67.944 25.92 ;
    END
  END fd_in[534]
  PIN fd_in[535]
    DIRECTION INPUT ;
    USE SIGNAL ;
    PORT
      LAYER M5 ;
        RECT  68.112 25.836 68.136 25.92 ;
    END
  END fd_in[535]
  PIN fd_in[536]
    DIRECTION INPUT ;
    USE SIGNAL ;
    PORT
      LAYER M5 ;
        RECT  68.304 25.836 68.328 25.92 ;
    END
  END fd_in[536]
  PIN fd_in[537]
    DIRECTION INPUT ;
    USE SIGNAL ;
    PORT
      LAYER M5 ;
        RECT  68.496 25.836 68.52 25.92 ;
    END
  END fd_in[537]
  PIN fd_in[538]
    DIRECTION INPUT ;
    USE SIGNAL ;
    PORT
      LAYER M5 ;
        RECT  68.64 25.836 68.664 25.92 ;
    END
  END fd_in[538]
  PIN fd_in[539]
    DIRECTION INPUT ;
    USE SIGNAL ;
    PORT
      LAYER M5 ;
        RECT  68.832 25.836 68.856 25.92 ;
    END
  END fd_in[539]
  PIN fd_in[53]
    DIRECTION INPUT ;
    USE SIGNAL ;
    PORT
      LAYER M5 ;
        RECT  128.016 25.836 128.04 25.92 ;
    END
  END fd_in[53]
  PIN fd_in[540]
    DIRECTION INPUT ;
    USE SIGNAL ;
    PORT
      LAYER M5 ;
        RECT  69.024 25.836 69.048 25.92 ;
    END
  END fd_in[540]
  PIN fd_in[541]
    DIRECTION INPUT ;
    USE SIGNAL ;
    PORT
      LAYER M5 ;
        RECT  69.216 25.836 69.24 25.92 ;
    END
  END fd_in[541]
  PIN fd_in[542]
    DIRECTION INPUT ;
    USE SIGNAL ;
    PORT
      LAYER M5 ;
        RECT  69.36 25.836 69.384 25.92 ;
    END
  END fd_in[542]
  PIN fd_in[543]
    DIRECTION INPUT ;
    USE SIGNAL ;
    PORT
      LAYER M5 ;
        RECT  69.552 25.836 69.576 25.92 ;
    END
  END fd_in[543]
  PIN fd_in[544]
    DIRECTION INPUT ;
    USE SIGNAL ;
    PORT
      LAYER M5 ;
        RECT  69.744 25.836 69.768 25.92 ;
    END
  END fd_in[544]
  PIN fd_in[545]
    DIRECTION INPUT ;
    USE SIGNAL ;
    PORT
      LAYER M5 ;
        RECT  69.936 25.836 69.96 25.92 ;
    END
  END fd_in[545]
  PIN fd_in[546]
    DIRECTION INPUT ;
    USE SIGNAL ;
    PORT
      LAYER M5 ;
        RECT  70.08 25.836 70.104 25.92 ;
    END
  END fd_in[546]
  PIN fd_in[547]
    DIRECTION INPUT ;
    USE SIGNAL ;
    PORT
      LAYER M5 ;
        RECT  70.272 25.836 70.296 25.92 ;
    END
  END fd_in[547]
  PIN fd_in[548]
    DIRECTION INPUT ;
    USE SIGNAL ;
    PORT
      LAYER M5 ;
        RECT  70.464 25.836 70.488 25.92 ;
    END
  END fd_in[548]
  PIN fd_in[549]
    DIRECTION INPUT ;
    USE SIGNAL ;
    PORT
      LAYER M5 ;
        RECT  70.608 25.836 70.632 25.92 ;
    END
  END fd_in[549]
  PIN fd_in[54]
    DIRECTION INPUT ;
    USE SIGNAL ;
    PORT
      LAYER M5 ;
        RECT  128.208 25.836 128.232 25.92 ;
    END
  END fd_in[54]
  PIN fd_in[550]
    DIRECTION INPUT ;
    USE SIGNAL ;
    PORT
      LAYER M5 ;
        RECT  70.8 25.836 70.824 25.92 ;
    END
  END fd_in[550]
  PIN fd_in[551]
    DIRECTION INPUT ;
    USE SIGNAL ;
    PORT
      LAYER M5 ;
        RECT  70.992 25.836 71.016 25.92 ;
    END
  END fd_in[551]
  PIN fd_in[552]
    DIRECTION INPUT ;
    USE SIGNAL ;
    PORT
      LAYER M5 ;
        RECT  71.184 25.836 71.208 25.92 ;
    END
  END fd_in[552]
  PIN fd_in[553]
    DIRECTION INPUT ;
    USE SIGNAL ;
    PORT
      LAYER M5 ;
        RECT  71.328 25.836 71.352 25.92 ;
    END
  END fd_in[553]
  PIN fd_in[554]
    DIRECTION INPUT ;
    USE SIGNAL ;
    PORT
      LAYER M5 ;
        RECT  71.52 25.836 71.544 25.92 ;
    END
  END fd_in[554]
  PIN fd_in[555]
    DIRECTION INPUT ;
    USE SIGNAL ;
    PORT
      LAYER M5 ;
        RECT  71.712 25.836 71.736 25.92 ;
    END
  END fd_in[555]
  PIN fd_in[556]
    DIRECTION INPUT ;
    USE SIGNAL ;
    PORT
      LAYER M5 ;
        RECT  71.904 25.836 71.928 25.92 ;
    END
  END fd_in[556]
  PIN fd_in[557]
    DIRECTION INPUT ;
    USE SIGNAL ;
    PORT
      LAYER M5 ;
        RECT  72.048 25.836 72.072 25.92 ;
    END
  END fd_in[557]
  PIN fd_in[558]
    DIRECTION INPUT ;
    USE SIGNAL ;
    PORT
      LAYER M5 ;
        RECT  72.24 25.836 72.264 25.92 ;
    END
  END fd_in[558]
  PIN fd_in[559]
    DIRECTION INPUT ;
    USE SIGNAL ;
    PORT
      LAYER M5 ;
        RECT  72.432 25.836 72.456 25.92 ;
    END
  END fd_in[559]
  PIN fd_in[55]
    DIRECTION INPUT ;
    USE SIGNAL ;
    PORT
      LAYER M5 ;
        RECT  128.4 25.836 128.424 25.92 ;
    END
  END fd_in[55]
  PIN fd_in[560]
    DIRECTION INPUT ;
    USE SIGNAL ;
    PORT
      LAYER M5 ;
        RECT  38.16 25.836 38.184 25.92 ;
    END
  END fd_in[560]
  PIN fd_in[561]
    DIRECTION INPUT ;
    USE SIGNAL ;
    PORT
      LAYER M5 ;
        RECT  38.352 25.836 38.376 25.92 ;
    END
  END fd_in[561]
  PIN fd_in[562]
    DIRECTION INPUT ;
    USE SIGNAL ;
    PORT
      LAYER M5 ;
        RECT  38.544 25.836 38.568 25.92 ;
    END
  END fd_in[562]
  PIN fd_in[563]
    DIRECTION INPUT ;
    USE SIGNAL ;
    PORT
      LAYER M5 ;
        RECT  38.688 25.836 38.712 25.92 ;
    END
  END fd_in[563]
  PIN fd_in[564]
    DIRECTION INPUT ;
    USE SIGNAL ;
    PORT
      LAYER M5 ;
        RECT  38.88 25.836 38.904 25.92 ;
    END
  END fd_in[564]
  PIN fd_in[565]
    DIRECTION INPUT ;
    USE SIGNAL ;
    PORT
      LAYER M5 ;
        RECT  39.072 25.836 39.096 25.92 ;
    END
  END fd_in[565]
  PIN fd_in[566]
    DIRECTION INPUT ;
    USE SIGNAL ;
    PORT
      LAYER M5 ;
        RECT  39.264 25.836 39.288 25.92 ;
    END
  END fd_in[566]
  PIN fd_in[567]
    DIRECTION INPUT ;
    USE SIGNAL ;
    PORT
      LAYER M5 ;
        RECT  39.408 25.836 39.432 25.92 ;
    END
  END fd_in[567]
  PIN fd_in[568]
    DIRECTION INPUT ;
    USE SIGNAL ;
    PORT
      LAYER M5 ;
        RECT  39.6 25.836 39.624 25.92 ;
    END
  END fd_in[568]
  PIN fd_in[569]
    DIRECTION INPUT ;
    USE SIGNAL ;
    PORT
      LAYER M5 ;
        RECT  39.792 25.836 39.816 25.92 ;
    END
  END fd_in[569]
  PIN fd_in[56]
    DIRECTION INPUT ;
    USE SIGNAL ;
    PORT
      LAYER M5 ;
        RECT  128.544 25.836 128.568 25.92 ;
    END
  END fd_in[56]
  PIN fd_in[570]
    DIRECTION INPUT ;
    USE SIGNAL ;
    PORT
      LAYER M5 ;
        RECT  39.984 25.836 40.008 25.92 ;
    END
  END fd_in[570]
  PIN fd_in[571]
    DIRECTION INPUT ;
    USE SIGNAL ;
    PORT
      LAYER M5 ;
        RECT  40.128 25.836 40.152 25.92 ;
    END
  END fd_in[571]
  PIN fd_in[572]
    DIRECTION INPUT ;
    USE SIGNAL ;
    PORT
      LAYER M5 ;
        RECT  40.32 25.836 40.344 25.92 ;
    END
  END fd_in[572]
  PIN fd_in[573]
    DIRECTION INPUT ;
    USE SIGNAL ;
    PORT
      LAYER M5 ;
        RECT  40.512 25.836 40.536 25.92 ;
    END
  END fd_in[573]
  PIN fd_in[574]
    DIRECTION INPUT ;
    USE SIGNAL ;
    PORT
      LAYER M5 ;
        RECT  40.704 25.836 40.728 25.92 ;
    END
  END fd_in[574]
  PIN fd_in[575]
    DIRECTION INPUT ;
    USE SIGNAL ;
    PORT
      LAYER M5 ;
        RECT  40.848 25.836 40.872 25.92 ;
    END
  END fd_in[575]
  PIN fd_in[576]
    DIRECTION INPUT ;
    USE SIGNAL ;
    PORT
      LAYER M5 ;
        RECT  41.04 25.836 41.064 25.92 ;
    END
  END fd_in[576]
  PIN fd_in[577]
    DIRECTION INPUT ;
    USE SIGNAL ;
    PORT
      LAYER M5 ;
        RECT  41.232 25.836 41.256 25.92 ;
    END
  END fd_in[577]
  PIN fd_in[578]
    DIRECTION INPUT ;
    USE SIGNAL ;
    PORT
      LAYER M5 ;
        RECT  41.376 25.836 41.4 25.92 ;
    END
  END fd_in[578]
  PIN fd_in[579]
    DIRECTION INPUT ;
    USE SIGNAL ;
    PORT
      LAYER M5 ;
        RECT  41.568 25.836 41.592 25.92 ;
    END
  END fd_in[579]
  PIN fd_in[57]
    DIRECTION INPUT ;
    USE SIGNAL ;
    PORT
      LAYER M5 ;
        RECT  128.736 25.836 128.76 25.92 ;
    END
  END fd_in[57]
  PIN fd_in[580]
    DIRECTION INPUT ;
    USE SIGNAL ;
    PORT
      LAYER M5 ;
        RECT  41.76 25.836 41.784 25.92 ;
    END
  END fd_in[580]
  PIN fd_in[581]
    DIRECTION INPUT ;
    USE SIGNAL ;
    PORT
      LAYER M5 ;
        RECT  41.952 25.836 41.976 25.92 ;
    END
  END fd_in[581]
  PIN fd_in[582]
    DIRECTION INPUT ;
    USE SIGNAL ;
    PORT
      LAYER M5 ;
        RECT  42.096 25.836 42.12 25.92 ;
    END
  END fd_in[582]
  PIN fd_in[583]
    DIRECTION INPUT ;
    USE SIGNAL ;
    PORT
      LAYER M5 ;
        RECT  42.288 25.836 42.312 25.92 ;
    END
  END fd_in[583]
  PIN fd_in[584]
    DIRECTION INPUT ;
    USE SIGNAL ;
    PORT
      LAYER M5 ;
        RECT  42.48 25.836 42.504 25.92 ;
    END
  END fd_in[584]
  PIN fd_in[585]
    DIRECTION INPUT ;
    USE SIGNAL ;
    PORT
      LAYER M5 ;
        RECT  42.672 25.836 42.696 25.92 ;
    END
  END fd_in[585]
  PIN fd_in[586]
    DIRECTION INPUT ;
    USE SIGNAL ;
    PORT
      LAYER M5 ;
        RECT  42.816 25.836 42.84 25.92 ;
    END
  END fd_in[586]
  PIN fd_in[587]
    DIRECTION INPUT ;
    USE SIGNAL ;
    PORT
      LAYER M5 ;
        RECT  43.008 25.836 43.032 25.92 ;
    END
  END fd_in[587]
  PIN fd_in[588]
    DIRECTION INPUT ;
    USE SIGNAL ;
    PORT
      LAYER M5 ;
        RECT  43.2 25.836 43.224 25.92 ;
    END
  END fd_in[588]
  PIN fd_in[589]
    DIRECTION INPUT ;
    USE SIGNAL ;
    PORT
      LAYER M5 ;
        RECT  43.392 25.836 43.416 25.92 ;
    END
  END fd_in[589]
  PIN fd_in[58]
    DIRECTION INPUT ;
    USE SIGNAL ;
    PORT
      LAYER M5 ;
        RECT  128.928 25.836 128.952 25.92 ;
    END
  END fd_in[58]
  PIN fd_in[590]
    DIRECTION INPUT ;
    USE SIGNAL ;
    PORT
      LAYER M5 ;
        RECT  43.536 25.836 43.56 25.92 ;
    END
  END fd_in[590]
  PIN fd_in[591]
    DIRECTION INPUT ;
    USE SIGNAL ;
    PORT
      LAYER M5 ;
        RECT  43.728 25.836 43.752 25.92 ;
    END
  END fd_in[591]
  PIN fd_in[592]
    DIRECTION INPUT ;
    USE SIGNAL ;
    PORT
      LAYER M5 ;
        RECT  37.968 25.836 37.992 25.92 ;
    END
  END fd_in[592]
  PIN fd_in[593]
    DIRECTION INPUT ;
    USE SIGNAL ;
    PORT
      LAYER M5 ;
        RECT  37.824 25.836 37.848 25.92 ;
    END
  END fd_in[593]
  PIN fd_in[594]
    DIRECTION INPUT ;
    USE SIGNAL ;
    PORT
      LAYER M5 ;
        RECT  37.632 25.836 37.656 25.92 ;
    END
  END fd_in[594]
  PIN fd_in[595]
    DIRECTION INPUT ;
    USE SIGNAL ;
    PORT
      LAYER M5 ;
        RECT  37.44 25.836 37.464 25.92 ;
    END
  END fd_in[595]
  PIN fd_in[596]
    DIRECTION INPUT ;
    USE SIGNAL ;
    PORT
      LAYER M5 ;
        RECT  37.296 25.836 37.32 25.92 ;
    END
  END fd_in[596]
  PIN fd_in[597]
    DIRECTION INPUT ;
    USE SIGNAL ;
    PORT
      LAYER M5 ;
        RECT  37.104 25.836 37.128 25.92 ;
    END
  END fd_in[597]
  PIN fd_in[598]
    DIRECTION INPUT ;
    USE SIGNAL ;
    PORT
      LAYER M5 ;
        RECT  36.912 25.836 36.936 25.92 ;
    END
  END fd_in[598]
  PIN fd_in[599]
    DIRECTION INPUT ;
    USE SIGNAL ;
    PORT
      LAYER M5 ;
        RECT  36.72 25.836 36.744 25.92 ;
    END
  END fd_in[599]
  PIN fd_in[59]
    DIRECTION INPUT ;
    USE SIGNAL ;
    PORT
      LAYER M5 ;
        RECT  129.12 25.836 129.144 25.92 ;
    END
  END fd_in[59]
  PIN fd_in[5]
    DIRECTION INPUT ;
    USE SIGNAL ;
    PORT
      LAYER M5 ;
        RECT  130.896 25.836 130.92 25.92 ;
    END
  END fd_in[5]
  PIN fd_in[600]
    DIRECTION INPUT ;
    USE SIGNAL ;
    PORT
      LAYER M5 ;
        RECT  36.576 25.836 36.6 25.92 ;
    END
  END fd_in[600]
  PIN fd_in[601]
    DIRECTION INPUT ;
    USE SIGNAL ;
    PORT
      LAYER M5 ;
        RECT  36.384 25.836 36.408 25.92 ;
    END
  END fd_in[601]
  PIN fd_in[602]
    DIRECTION INPUT ;
    USE SIGNAL ;
    PORT
      LAYER M5 ;
        RECT  36.192 25.836 36.216 25.92 ;
    END
  END fd_in[602]
  PIN fd_in[603]
    DIRECTION INPUT ;
    USE SIGNAL ;
    PORT
      LAYER M5 ;
        RECT  36 25.836 36.024 25.92 ;
    END
  END fd_in[603]
  PIN fd_in[604]
    DIRECTION INPUT ;
    USE SIGNAL ;
    PORT
      LAYER M5 ;
        RECT  35.856 25.836 35.88 25.92 ;
    END
  END fd_in[604]
  PIN fd_in[605]
    DIRECTION INPUT ;
    USE SIGNAL ;
    PORT
      LAYER M5 ;
        RECT  35.664 25.836 35.688 25.92 ;
    END
  END fd_in[605]
  PIN fd_in[606]
    DIRECTION INPUT ;
    USE SIGNAL ;
    PORT
      LAYER M5 ;
        RECT  35.472 25.836 35.496 25.92 ;
    END
  END fd_in[606]
  PIN fd_in[607]
    DIRECTION INPUT ;
    USE SIGNAL ;
    PORT
      LAYER M5 ;
        RECT  35.28 25.836 35.304 25.92 ;
    END
  END fd_in[607]
  PIN fd_in[608]
    DIRECTION INPUT ;
    USE SIGNAL ;
    PORT
      LAYER M5 ;
        RECT  35.136 25.836 35.16 25.92 ;
    END
  END fd_in[608]
  PIN fd_in[609]
    DIRECTION INPUT ;
    USE SIGNAL ;
    PORT
      LAYER M5 ;
        RECT  34.944 25.836 34.968 25.92 ;
    END
  END fd_in[609]
  PIN fd_in[60]
    DIRECTION INPUT ;
    USE SIGNAL ;
    PORT
      LAYER M5 ;
        RECT  129.264 25.836 129.288 25.92 ;
    END
  END fd_in[60]
  PIN fd_in[610]
    DIRECTION INPUT ;
    USE SIGNAL ;
    PORT
      LAYER M5 ;
        RECT  34.752 25.836 34.776 25.92 ;
    END
  END fd_in[610]
  PIN fd_in[611]
    DIRECTION INPUT ;
    USE SIGNAL ;
    PORT
      LAYER M5 ;
        RECT  34.56 25.836 34.584 25.92 ;
    END
  END fd_in[611]
  PIN fd_in[612]
    DIRECTION INPUT ;
    USE SIGNAL ;
    PORT
      LAYER M5 ;
        RECT  34.416 25.836 34.44 25.92 ;
    END
  END fd_in[612]
  PIN fd_in[613]
    DIRECTION INPUT ;
    USE SIGNAL ;
    PORT
      LAYER M5 ;
        RECT  34.224 25.836 34.248 25.92 ;
    END
  END fd_in[613]
  PIN fd_in[614]
    DIRECTION INPUT ;
    USE SIGNAL ;
    PORT
      LAYER M5 ;
        RECT  34.032 25.836 34.056 25.92 ;
    END
  END fd_in[614]
  PIN fd_in[615]
    DIRECTION INPUT ;
    USE SIGNAL ;
    PORT
      LAYER M5 ;
        RECT  33.888 25.836 33.912 25.92 ;
    END
  END fd_in[615]
  PIN fd_in[616]
    DIRECTION INPUT ;
    USE SIGNAL ;
    PORT
      LAYER M5 ;
        RECT  33.696 25.836 33.72 25.92 ;
    END
  END fd_in[616]
  PIN fd_in[617]
    DIRECTION INPUT ;
    USE SIGNAL ;
    PORT
      LAYER M5 ;
        RECT  33.504 25.836 33.528 25.92 ;
    END
  END fd_in[617]
  PIN fd_in[618]
    DIRECTION INPUT ;
    USE SIGNAL ;
    PORT
      LAYER M5 ;
        RECT  33.312 25.836 33.336 25.92 ;
    END
  END fd_in[618]
  PIN fd_in[619]
    DIRECTION INPUT ;
    USE SIGNAL ;
    PORT
      LAYER M5 ;
        RECT  33.168 25.836 33.192 25.92 ;
    END
  END fd_in[619]
  PIN fd_in[61]
    DIRECTION INPUT ;
    USE SIGNAL ;
    PORT
      LAYER M5 ;
        RECT  129.456 25.836 129.48 25.92 ;
    END
  END fd_in[61]
  PIN fd_in[620]
    DIRECTION INPUT ;
    USE SIGNAL ;
    PORT
      LAYER M5 ;
        RECT  32.976 25.836 33 25.92 ;
    END
  END fd_in[620]
  PIN fd_in[621]
    DIRECTION INPUT ;
    USE SIGNAL ;
    PORT
      LAYER M5 ;
        RECT  32.784 25.836 32.808 25.92 ;
    END
  END fd_in[621]
  PIN fd_in[622]
    DIRECTION INPUT ;
    USE SIGNAL ;
    PORT
      LAYER M5 ;
        RECT  32.592 25.836 32.616 25.92 ;
    END
  END fd_in[622]
  PIN fd_in[623]
    DIRECTION INPUT ;
    USE SIGNAL ;
    PORT
      LAYER M5 ;
        RECT  32.448 25.836 32.472 25.92 ;
    END
  END fd_in[623]
  PIN fd_in[624]
    DIRECTION INPUT ;
    USE SIGNAL ;
    PORT
      LAYER M5 ;
        RECT  32.256 25.836 32.28 25.92 ;
    END
  END fd_in[624]
  PIN fd_in[625]
    DIRECTION INPUT ;
    USE SIGNAL ;
    PORT
      LAYER M5 ;
        RECT  32.064 25.836 32.088 25.92 ;
    END
  END fd_in[625]
  PIN fd_in[626]
    DIRECTION INPUT ;
    USE SIGNAL ;
    PORT
      LAYER M5 ;
        RECT  31.872 25.836 31.896 25.92 ;
    END
  END fd_in[626]
  PIN fd_in[627]
    DIRECTION INPUT ;
    USE SIGNAL ;
    PORT
      LAYER M5 ;
        RECT  31.728 25.836 31.752 25.92 ;
    END
  END fd_in[627]
  PIN fd_in[628]
    DIRECTION INPUT ;
    USE SIGNAL ;
    PORT
      LAYER M5 ;
        RECT  31.536 25.836 31.56 25.92 ;
    END
  END fd_in[628]
  PIN fd_in[629]
    DIRECTION INPUT ;
    USE SIGNAL ;
    PORT
      LAYER M5 ;
        RECT  31.344 25.836 31.368 25.92 ;
    END
  END fd_in[629]
  PIN fd_in[62]
    DIRECTION INPUT ;
    USE SIGNAL ;
    PORT
      LAYER M5 ;
        RECT  129.648 25.836 129.672 25.92 ;
    END
  END fd_in[62]
  PIN fd_in[630]
    DIRECTION INPUT ;
    USE SIGNAL ;
    PORT
      LAYER M5 ;
        RECT  31.152 25.836 31.176 25.92 ;
    END
  END fd_in[630]
  PIN fd_in[631]
    DIRECTION INPUT ;
    USE SIGNAL ;
    PORT
      LAYER M5 ;
        RECT  31.008 25.836 31.032 25.92 ;
    END
  END fd_in[631]
  PIN fd_in[632]
    DIRECTION INPUT ;
    USE SIGNAL ;
    PORT
      LAYER M5 ;
        RECT  30.816 25.836 30.84 25.92 ;
    END
  END fd_in[632]
  PIN fd_in[633]
    DIRECTION INPUT ;
    USE SIGNAL ;
    PORT
      LAYER M5 ;
        RECT  30.624 25.836 30.648 25.92 ;
    END
  END fd_in[633]
  PIN fd_in[634]
    DIRECTION INPUT ;
    USE SIGNAL ;
    PORT
      LAYER M5 ;
        RECT  30.48 25.836 30.504 25.92 ;
    END
  END fd_in[634]
  PIN fd_in[635]
    DIRECTION INPUT ;
    USE SIGNAL ;
    PORT
      LAYER M5 ;
        RECT  30.288 25.836 30.312 25.92 ;
    END
  END fd_in[635]
  PIN fd_in[636]
    DIRECTION INPUT ;
    USE SIGNAL ;
    PORT
      LAYER M5 ;
        RECT  30.096 25.836 30.12 25.92 ;
    END
  END fd_in[636]
  PIN fd_in[637]
    DIRECTION INPUT ;
    USE SIGNAL ;
    PORT
      LAYER M5 ;
        RECT  29.904 25.836 29.928 25.92 ;
    END
  END fd_in[637]
  PIN fd_in[638]
    DIRECTION INPUT ;
    USE SIGNAL ;
    PORT
      LAYER M5 ;
        RECT  29.76 25.836 29.784 25.92 ;
    END
  END fd_in[638]
  PIN fd_in[639]
    DIRECTION INPUT ;
    USE SIGNAL ;
    PORT
      LAYER M5 ;
        RECT  29.568 25.836 29.592 25.92 ;
    END
  END fd_in[639]
  PIN fd_in[63]
    DIRECTION INPUT ;
    USE SIGNAL ;
    PORT
      LAYER M5 ;
        RECT  129.792 25.836 129.816 25.92 ;
    END
  END fd_in[63]
  PIN fd_in[640]
    DIRECTION INPUT ;
    USE SIGNAL ;
    PORT
      LAYER M5 ;
        RECT  29.376 25.836 29.4 25.92 ;
    END
  END fd_in[640]
  PIN fd_in[641]
    DIRECTION INPUT ;
    USE SIGNAL ;
    PORT
      LAYER M5 ;
        RECT  29.184 25.836 29.208 25.92 ;
    END
  END fd_in[641]
  PIN fd_in[642]
    DIRECTION INPUT ;
    USE SIGNAL ;
    PORT
      LAYER M5 ;
        RECT  29.04 25.836 29.064 25.92 ;
    END
  END fd_in[642]
  PIN fd_in[643]
    DIRECTION INPUT ;
    USE SIGNAL ;
    PORT
      LAYER M5 ;
        RECT  28.848 25.836 28.872 25.92 ;
    END
  END fd_in[643]
  PIN fd_in[644]
    DIRECTION INPUT ;
    USE SIGNAL ;
    PORT
      LAYER M5 ;
        RECT  28.656 25.836 28.68 25.92 ;
    END
  END fd_in[644]
  PIN fd_in[645]
    DIRECTION INPUT ;
    USE SIGNAL ;
    PORT
      LAYER M5 ;
        RECT  28.464 25.836 28.488 25.92 ;
    END
  END fd_in[645]
  PIN fd_in[646]
    DIRECTION INPUT ;
    USE SIGNAL ;
    PORT
      LAYER M5 ;
        RECT  28.32 25.836 28.344 25.92 ;
    END
  END fd_in[646]
  PIN fd_in[647]
    DIRECTION INPUT ;
    USE SIGNAL ;
    PORT
      LAYER M5 ;
        RECT  28.128 25.836 28.152 25.92 ;
    END
  END fd_in[647]
  PIN fd_in[648]
    DIRECTION INPUT ;
    USE SIGNAL ;
    PORT
      LAYER M5 ;
        RECT  27.936 25.836 27.96 25.92 ;
    END
  END fd_in[648]
  PIN fd_in[649]
    DIRECTION INPUT ;
    USE SIGNAL ;
    PORT
      LAYER M5 ;
        RECT  27.792 25.836 27.816 25.92 ;
    END
  END fd_in[649]
  PIN fd_in[64]
    DIRECTION INPUT ;
    USE SIGNAL ;
    PORT
      LAYER M5 ;
        RECT  135.744 25.836 135.768 25.92 ;
    END
  END fd_in[64]
  PIN fd_in[650]
    DIRECTION INPUT ;
    USE SIGNAL ;
    PORT
      LAYER M5 ;
        RECT  27.6 25.836 27.624 25.92 ;
    END
  END fd_in[650]
  PIN fd_in[651]
    DIRECTION INPUT ;
    USE SIGNAL ;
    PORT
      LAYER M5 ;
        RECT  27.408 25.836 27.432 25.92 ;
    END
  END fd_in[651]
  PIN fd_in[652]
    DIRECTION INPUT ;
    USE SIGNAL ;
    PORT
      LAYER M5 ;
        RECT  27.216 25.836 27.24 25.92 ;
    END
  END fd_in[652]
  PIN fd_in[653]
    DIRECTION INPUT ;
    USE SIGNAL ;
    PORT
      LAYER M5 ;
        RECT  27.072 25.836 27.096 25.92 ;
    END
  END fd_in[653]
  PIN fd_in[654]
    DIRECTION INPUT ;
    USE SIGNAL ;
    PORT
      LAYER M5 ;
        RECT  26.88 25.836 26.904 25.92 ;
    END
  END fd_in[654]
  PIN fd_in[655]
    DIRECTION INPUT ;
    USE SIGNAL ;
    PORT
      LAYER M5 ;
        RECT  26.688 25.836 26.712 25.92 ;
    END
  END fd_in[655]
  PIN fd_in[656]
    DIRECTION INPUT ;
    USE SIGNAL ;
    PORT
      LAYER M5 ;
        RECT  26.496 25.836 26.52 25.92 ;
    END
  END fd_in[656]
  PIN fd_in[657]
    DIRECTION INPUT ;
    USE SIGNAL ;
    PORT
      LAYER M5 ;
        RECT  26.352 25.836 26.376 25.92 ;
    END
  END fd_in[657]
  PIN fd_in[658]
    DIRECTION INPUT ;
    USE SIGNAL ;
    PORT
      LAYER M5 ;
        RECT  26.16 25.836 26.184 25.92 ;
    END
  END fd_in[658]
  PIN fd_in[659]
    DIRECTION INPUT ;
    USE SIGNAL ;
    PORT
      LAYER M5 ;
        RECT  25.968 25.836 25.992 25.92 ;
    END
  END fd_in[659]
  PIN fd_in[65]
    DIRECTION INPUT ;
    USE SIGNAL ;
    PORT
      LAYER M5 ;
        RECT  135.888 25.836 135.912 25.92 ;
    END
  END fd_in[65]
  PIN fd_in[660]
    DIRECTION INPUT ;
    USE SIGNAL ;
    PORT
      LAYER M5 ;
        RECT  25.776 25.836 25.8 25.92 ;
    END
  END fd_in[660]
  PIN fd_in[661]
    DIRECTION INPUT ;
    USE SIGNAL ;
    PORT
      LAYER M5 ;
        RECT  25.632 25.836 25.656 25.92 ;
    END
  END fd_in[661]
  PIN fd_in[662]
    DIRECTION INPUT ;
    USE SIGNAL ;
    PORT
      LAYER M5 ;
        RECT  25.44 25.836 25.464 25.92 ;
    END
  END fd_in[662]
  PIN fd_in[663]
    DIRECTION INPUT ;
    USE SIGNAL ;
    PORT
      LAYER M5 ;
        RECT  25.248 25.836 25.272 25.92 ;
    END
  END fd_in[663]
  PIN fd_in[664]
    DIRECTION INPUT ;
    USE SIGNAL ;
    PORT
      LAYER M5 ;
        RECT  25.056 25.836 25.08 25.92 ;
    END
  END fd_in[664]
  PIN fd_in[665]
    DIRECTION INPUT ;
    USE SIGNAL ;
    PORT
      LAYER M5 ;
        RECT  24.912 25.836 24.936 25.92 ;
    END
  END fd_in[665]
  PIN fd_in[666]
    DIRECTION INPUT ;
    USE SIGNAL ;
    PORT
      LAYER M5 ;
        RECT  24.72 25.836 24.744 25.92 ;
    END
  END fd_in[666]
  PIN fd_in[667]
    DIRECTION INPUT ;
    USE SIGNAL ;
    PORT
      LAYER M5 ;
        RECT  24.528 25.836 24.552 25.92 ;
    END
  END fd_in[667]
  PIN fd_in[668]
    DIRECTION INPUT ;
    USE SIGNAL ;
    PORT
      LAYER M5 ;
        RECT  24.384 25.836 24.408 25.92 ;
    END
  END fd_in[668]
  PIN fd_in[669]
    DIRECTION INPUT ;
    USE SIGNAL ;
    PORT
      LAYER M5 ;
        RECT  24.192 25.836 24.216 25.92 ;
    END
  END fd_in[669]
  PIN fd_in[66]
    DIRECTION INPUT ;
    USE SIGNAL ;
    PORT
      LAYER M5 ;
        RECT  136.08 25.836 136.104 25.92 ;
    END
  END fd_in[66]
  PIN fd_in[670]
    DIRECTION INPUT ;
    USE SIGNAL ;
    PORT
      LAYER M5 ;
        RECT  24 25.836 24.024 25.92 ;
    END
  END fd_in[670]
  PIN fd_in[671]
    DIRECTION INPUT ;
    USE SIGNAL ;
    PORT
      LAYER M5 ;
        RECT  23.808 25.836 23.832 25.92 ;
    END
  END fd_in[671]
  PIN fd_in[672]
    DIRECTION INPUT ;
    USE SIGNAL ;
    PORT
      LAYER M5 ;
        RECT  23.664 25.836 23.688 25.92 ;
    END
  END fd_in[672]
  PIN fd_in[673]
    DIRECTION INPUT ;
    USE SIGNAL ;
    PORT
      LAYER M5 ;
        RECT  23.472 25.836 23.496 25.92 ;
    END
  END fd_in[673]
  PIN fd_in[674]
    DIRECTION INPUT ;
    USE SIGNAL ;
    PORT
      LAYER M5 ;
        RECT  23.28 25.836 23.304 25.92 ;
    END
  END fd_in[674]
  PIN fd_in[675]
    DIRECTION INPUT ;
    USE SIGNAL ;
    PORT
      LAYER M5 ;
        RECT  23.088 25.836 23.112 25.92 ;
    END
  END fd_in[675]
  PIN fd_in[676]
    DIRECTION INPUT ;
    USE SIGNAL ;
    PORT
      LAYER M5 ;
        RECT  22.944 25.836 22.968 25.92 ;
    END
  END fd_in[676]
  PIN fd_in[677]
    DIRECTION INPUT ;
    USE SIGNAL ;
    PORT
      LAYER M5 ;
        RECT  22.752 25.836 22.776 25.92 ;
    END
  END fd_in[677]
  PIN fd_in[678]
    DIRECTION INPUT ;
    USE SIGNAL ;
    PORT
      LAYER M5 ;
        RECT  22.56 25.836 22.584 25.92 ;
    END
  END fd_in[678]
  PIN fd_in[679]
    DIRECTION INPUT ;
    USE SIGNAL ;
    PORT
      LAYER M5 ;
        RECT  22.368 25.836 22.392 25.92 ;
    END
  END fd_in[679]
  PIN fd_in[67]
    DIRECTION INPUT ;
    USE SIGNAL ;
    PORT
      LAYER M5 ;
        RECT  136.272 25.836 136.296 25.92 ;
    END
  END fd_in[67]
  PIN fd_in[680]
    DIRECTION INPUT ;
    USE SIGNAL ;
    PORT
      LAYER M5 ;
        RECT  22.224 25.836 22.248 25.92 ;
    END
  END fd_in[680]
  PIN fd_in[681]
    DIRECTION INPUT ;
    USE SIGNAL ;
    PORT
      LAYER M5 ;
        RECT  22.032 25.836 22.056 25.92 ;
    END
  END fd_in[681]
  PIN fd_in[682]
    DIRECTION INPUT ;
    USE SIGNAL ;
    PORT
      LAYER M5 ;
        RECT  21.84 25.836 21.864 25.92 ;
    END
  END fd_in[682]
  PIN fd_in[683]
    DIRECTION INPUT ;
    USE SIGNAL ;
    PORT
      LAYER M5 ;
        RECT  21.648 25.836 21.672 25.92 ;
    END
  END fd_in[683]
  PIN fd_in[684]
    DIRECTION INPUT ;
    USE SIGNAL ;
    PORT
      LAYER M5 ;
        RECT  21.504 25.836 21.528 25.92 ;
    END
  END fd_in[684]
  PIN fd_in[685]
    DIRECTION INPUT ;
    USE SIGNAL ;
    PORT
      LAYER M5 ;
        RECT  21.312 25.836 21.336 25.92 ;
    END
  END fd_in[685]
  PIN fd_in[686]
    DIRECTION INPUT ;
    USE SIGNAL ;
    PORT
      LAYER M5 ;
        RECT  21.12 25.836 21.144 25.92 ;
    END
  END fd_in[686]
  PIN fd_in[687]
    DIRECTION INPUT ;
    USE SIGNAL ;
    PORT
      LAYER M5 ;
        RECT  20.976 25.836 21 25.92 ;
    END
  END fd_in[687]
  PIN fd_in[688]
    DIRECTION INPUT ;
    USE SIGNAL ;
    PORT
      LAYER M5 ;
        RECT  20.784 25.836 20.808 25.92 ;
    END
  END fd_in[688]
  PIN fd_in[689]
    DIRECTION INPUT ;
    USE SIGNAL ;
    PORT
      LAYER M5 ;
        RECT  20.592 25.836 20.616 25.92 ;
    END
  END fd_in[689]
  PIN fd_in[68]
    DIRECTION INPUT ;
    USE SIGNAL ;
    PORT
      LAYER M5 ;
        RECT  136.464 25.836 136.488 25.92 ;
    END
  END fd_in[68]
  PIN fd_in[690]
    DIRECTION INPUT ;
    USE SIGNAL ;
    PORT
      LAYER M5 ;
        RECT  20.4 25.836 20.424 25.92 ;
    END
  END fd_in[690]
  PIN fd_in[691]
    DIRECTION INPUT ;
    USE SIGNAL ;
    PORT
      LAYER M5 ;
        RECT  20.256 25.836 20.28 25.92 ;
    END
  END fd_in[691]
  PIN fd_in[692]
    DIRECTION INPUT ;
    USE SIGNAL ;
    PORT
      LAYER M5 ;
        RECT  20.064 25.836 20.088 25.92 ;
    END
  END fd_in[692]
  PIN fd_in[693]
    DIRECTION INPUT ;
    USE SIGNAL ;
    PORT
      LAYER M5 ;
        RECT  19.872 25.836 19.896 25.92 ;
    END
  END fd_in[693]
  PIN fd_in[694]
    DIRECTION INPUT ;
    USE SIGNAL ;
    PORT
      LAYER M5 ;
        RECT  19.68 25.836 19.704 25.92 ;
    END
  END fd_in[694]
  PIN fd_in[695]
    DIRECTION INPUT ;
    USE SIGNAL ;
    PORT
      LAYER M5 ;
        RECT  19.536 25.836 19.56 25.92 ;
    END
  END fd_in[695]
  PIN fd_in[696]
    DIRECTION INPUT ;
    USE SIGNAL ;
    PORT
      LAYER M5 ;
        RECT  19.344 25.836 19.368 25.92 ;
    END
  END fd_in[696]
  PIN fd_in[697]
    DIRECTION INPUT ;
    USE SIGNAL ;
    PORT
      LAYER M5 ;
        RECT  19.152 25.836 19.176 25.92 ;
    END
  END fd_in[697]
  PIN fd_in[698]
    DIRECTION INPUT ;
    USE SIGNAL ;
    PORT
      LAYER M5 ;
        RECT  18.96 25.836 18.984 25.92 ;
    END
  END fd_in[698]
  PIN fd_in[699]
    DIRECTION INPUT ;
    USE SIGNAL ;
    PORT
      LAYER M5 ;
        RECT  18.816 25.836 18.84 25.92 ;
    END
  END fd_in[699]
  PIN fd_in[69]
    DIRECTION INPUT ;
    USE SIGNAL ;
    PORT
      LAYER M5 ;
        RECT  136.608 25.836 136.632 25.92 ;
    END
  END fd_in[69]
  PIN fd_in[6]
    DIRECTION INPUT ;
    USE SIGNAL ;
    PORT
      LAYER M5 ;
        RECT  131.088 25.836 131.112 25.92 ;
    END
  END fd_in[6]
  PIN fd_in[700]
    DIRECTION INPUT ;
    USE SIGNAL ;
    PORT
      LAYER M5 ;
        RECT  18.624 25.836 18.648 25.92 ;
    END
  END fd_in[700]
  PIN fd_in[701]
    DIRECTION INPUT ;
    USE SIGNAL ;
    PORT
      LAYER M5 ;
        RECT  18.432 25.836 18.456 25.92 ;
    END
  END fd_in[701]
  PIN fd_in[702]
    DIRECTION INPUT ;
    USE SIGNAL ;
    PORT
      LAYER M5 ;
        RECT  18.24 25.836 18.264 25.92 ;
    END
  END fd_in[702]
  PIN fd_in[703]
    DIRECTION INPUT ;
    USE SIGNAL ;
    PORT
      LAYER M5 ;
        RECT  18.096 25.836 18.12 25.92 ;
    END
  END fd_in[703]
  PIN fd_in[704]
    DIRECTION INPUT ;
    USE SIGNAL ;
    PORT
      LAYER M5 ;
        RECT  17.904 25.836 17.928 25.92 ;
    END
  END fd_in[704]
  PIN fd_in[705]
    DIRECTION INPUT ;
    USE SIGNAL ;
    PORT
      LAYER M5 ;
        RECT  17.712 25.836 17.736 25.92 ;
    END
  END fd_in[705]
  PIN fd_in[706]
    DIRECTION INPUT ;
    USE SIGNAL ;
    PORT
      LAYER M5 ;
        RECT  17.568 25.836 17.592 25.92 ;
    END
  END fd_in[706]
  PIN fd_in[707]
    DIRECTION INPUT ;
    USE SIGNAL ;
    PORT
      LAYER M5 ;
        RECT  17.376 25.836 17.4 25.92 ;
    END
  END fd_in[707]
  PIN fd_in[708]
    DIRECTION INPUT ;
    USE SIGNAL ;
    PORT
      LAYER M5 ;
        RECT  17.184 25.836 17.208 25.92 ;
    END
  END fd_in[708]
  PIN fd_in[709]
    DIRECTION INPUT ;
    USE SIGNAL ;
    PORT
      LAYER M5 ;
        RECT  16.992 25.836 17.016 25.92 ;
    END
  END fd_in[709]
  PIN fd_in[70]
    DIRECTION INPUT ;
    USE SIGNAL ;
    PORT
      LAYER M5 ;
        RECT  136.8 25.836 136.824 25.92 ;
    END
  END fd_in[70]
  PIN fd_in[710]
    DIRECTION INPUT ;
    USE SIGNAL ;
    PORT
      LAYER M5 ;
        RECT  16.848 25.836 16.872 25.92 ;
    END
  END fd_in[710]
  PIN fd_in[711]
    DIRECTION INPUT ;
    USE SIGNAL ;
    PORT
      LAYER M5 ;
        RECT  16.656 25.836 16.68 25.92 ;
    END
  END fd_in[711]
  PIN fd_in[712]
    DIRECTION INPUT ;
    USE SIGNAL ;
    PORT
      LAYER M5 ;
        RECT  16.464 25.836 16.488 25.92 ;
    END
  END fd_in[712]
  PIN fd_in[713]
    DIRECTION INPUT ;
    USE SIGNAL ;
    PORT
      LAYER M5 ;
        RECT  16.272 25.836 16.296 25.92 ;
    END
  END fd_in[713]
  PIN fd_in[714]
    DIRECTION INPUT ;
    USE SIGNAL ;
    PORT
      LAYER M5 ;
        RECT  16.128 25.836 16.152 25.92 ;
    END
  END fd_in[714]
  PIN fd_in[715]
    DIRECTION INPUT ;
    USE SIGNAL ;
    PORT
      LAYER M5 ;
        RECT  15.936 25.836 15.96 25.92 ;
    END
  END fd_in[715]
  PIN fd_in[716]
    DIRECTION INPUT ;
    USE SIGNAL ;
    PORT
      LAYER M5 ;
        RECT  15.744 25.836 15.768 25.92 ;
    END
  END fd_in[716]
  PIN fd_in[717]
    DIRECTION INPUT ;
    USE SIGNAL ;
    PORT
      LAYER M5 ;
        RECT  15.552 25.836 15.576 25.92 ;
    END
  END fd_in[717]
  PIN fd_in[718]
    DIRECTION INPUT ;
    USE SIGNAL ;
    PORT
      LAYER M5 ;
        RECT  15.408 25.836 15.432 25.92 ;
    END
  END fd_in[718]
  PIN fd_in[719]
    DIRECTION INPUT ;
    USE SIGNAL ;
    PORT
      LAYER M5 ;
        RECT  15.216 25.836 15.24 25.92 ;
    END
  END fd_in[719]
  PIN fd_in[71]
    DIRECTION INPUT ;
    USE SIGNAL ;
    PORT
      LAYER M5 ;
        RECT  136.992 25.836 137.016 25.92 ;
    END
  END fd_in[71]
  PIN fd_in[720]
    DIRECTION INPUT ;
    USE SIGNAL ;
    PORT
      LAYER M5 ;
        RECT  15.024 25.836 15.048 25.92 ;
    END
  END fd_in[720]
  PIN fd_in[721]
    DIRECTION INPUT ;
    USE SIGNAL ;
    PORT
      LAYER M5 ;
        RECT  14.832 25.836 14.856 25.92 ;
    END
  END fd_in[721]
  PIN fd_in[722]
    DIRECTION INPUT ;
    USE SIGNAL ;
    PORT
      LAYER M5 ;
        RECT  14.688 25.836 14.712 25.92 ;
    END
  END fd_in[722]
  PIN fd_in[723]
    DIRECTION INPUT ;
    USE SIGNAL ;
    PORT
      LAYER M5 ;
        RECT  14.496 25.836 14.52 25.92 ;
    END
  END fd_in[723]
  PIN fd_in[724]
    DIRECTION INPUT ;
    USE SIGNAL ;
    PORT
      LAYER M5 ;
        RECT  14.304 25.836 14.328 25.92 ;
    END
  END fd_in[724]
  PIN fd_in[725]
    DIRECTION INPUT ;
    USE SIGNAL ;
    PORT
      LAYER M5 ;
        RECT  14.16 25.836 14.184 25.92 ;
    END
  END fd_in[725]
  PIN fd_in[726]
    DIRECTION INPUT ;
    USE SIGNAL ;
    PORT
      LAYER M5 ;
        RECT  13.968 25.836 13.992 25.92 ;
    END
  END fd_in[726]
  PIN fd_in[727]
    DIRECTION INPUT ;
    USE SIGNAL ;
    PORT
      LAYER M5 ;
        RECT  13.776 25.836 13.8 25.92 ;
    END
  END fd_in[727]
  PIN fd_in[728]
    DIRECTION INPUT ;
    USE SIGNAL ;
    PORT
      LAYER M5 ;
        RECT  13.584 25.836 13.608 25.92 ;
    END
  END fd_in[728]
  PIN fd_in[729]
    DIRECTION INPUT ;
    USE SIGNAL ;
    PORT
      LAYER M5 ;
        RECT  13.44 25.836 13.464 25.92 ;
    END
  END fd_in[729]
  PIN fd_in[72]
    DIRECTION INPUT ;
    USE SIGNAL ;
    PORT
      LAYER M5 ;
        RECT  137.184 25.836 137.208 25.92 ;
    END
  END fd_in[72]
  PIN fd_in[730]
    DIRECTION INPUT ;
    USE SIGNAL ;
    PORT
      LAYER M5 ;
        RECT  13.248 25.836 13.272 25.92 ;
    END
  END fd_in[730]
  PIN fd_in[731]
    DIRECTION INPUT ;
    USE SIGNAL ;
    PORT
      LAYER M5 ;
        RECT  13.056 25.836 13.08 25.92 ;
    END
  END fd_in[731]
  PIN fd_in[732]
    DIRECTION INPUT ;
    USE SIGNAL ;
    PORT
      LAYER M5 ;
        RECT  12.864 25.836 12.888 25.92 ;
    END
  END fd_in[732]
  PIN fd_in[733]
    DIRECTION INPUT ;
    USE SIGNAL ;
    PORT
      LAYER M5 ;
        RECT  12.72 25.836 12.744 25.92 ;
    END
  END fd_in[733]
  PIN fd_in[734]
    DIRECTION INPUT ;
    USE SIGNAL ;
    PORT
      LAYER M5 ;
        RECT  12.528 25.836 12.552 25.92 ;
    END
  END fd_in[734]
  PIN fd_in[735]
    DIRECTION INPUT ;
    USE SIGNAL ;
    PORT
      LAYER M5 ;
        RECT  12.336 25.836 12.36 25.92 ;
    END
  END fd_in[735]
  PIN fd_in[736]
    DIRECTION INPUT ;
    USE SIGNAL ;
    PORT
      LAYER M5 ;
        RECT  12.144 25.836 12.168 25.92 ;
    END
  END fd_in[736]
  PIN fd_in[737]
    DIRECTION INPUT ;
    USE SIGNAL ;
    PORT
      LAYER M5 ;
        RECT  12 25.836 12.024 25.92 ;
    END
  END fd_in[737]
  PIN fd_in[738]
    DIRECTION INPUT ;
    USE SIGNAL ;
    PORT
      LAYER M5 ;
        RECT  11.808 25.836 11.832 25.92 ;
    END
  END fd_in[738]
  PIN fd_in[739]
    DIRECTION INPUT ;
    USE SIGNAL ;
    PORT
      LAYER M5 ;
        RECT  11.616 25.836 11.64 25.92 ;
    END
  END fd_in[739]
  PIN fd_in[73]
    DIRECTION INPUT ;
    USE SIGNAL ;
    PORT
      LAYER M5 ;
        RECT  137.328 25.836 137.352 25.92 ;
    END
  END fd_in[73]
  PIN fd_in[740]
    DIRECTION INPUT ;
    USE SIGNAL ;
    PORT
      LAYER M5 ;
        RECT  11.472 25.836 11.496 25.92 ;
    END
  END fd_in[740]
  PIN fd_in[741]
    DIRECTION INPUT ;
    USE SIGNAL ;
    PORT
      LAYER M5 ;
        RECT  11.28 25.836 11.304 25.92 ;
    END
  END fd_in[741]
  PIN fd_in[742]
    DIRECTION INPUT ;
    USE SIGNAL ;
    PORT
      LAYER M5 ;
        RECT  11.088 25.836 11.112 25.92 ;
    END
  END fd_in[742]
  PIN fd_in[743]
    DIRECTION INPUT ;
    USE SIGNAL ;
    PORT
      LAYER M5 ;
        RECT  10.896 25.836 10.92 25.92 ;
    END
  END fd_in[743]
  PIN fd_in[744]
    DIRECTION INPUT ;
    USE SIGNAL ;
    PORT
      LAYER M5 ;
        RECT  10.752 25.836 10.776 25.92 ;
    END
  END fd_in[744]
  PIN fd_in[745]
    DIRECTION INPUT ;
    USE SIGNAL ;
    PORT
      LAYER M5 ;
        RECT  10.56 25.836 10.584 25.92 ;
    END
  END fd_in[745]
  PIN fd_in[746]
    DIRECTION INPUT ;
    USE SIGNAL ;
    PORT
      LAYER M5 ;
        RECT  10.368 25.836 10.392 25.92 ;
    END
  END fd_in[746]
  PIN fd_in[747]
    DIRECTION INPUT ;
    USE SIGNAL ;
    PORT
      LAYER M5 ;
        RECT  10.176 25.836 10.2 25.92 ;
    END
  END fd_in[747]
  PIN fd_in[748]
    DIRECTION INPUT ;
    USE SIGNAL ;
    PORT
      LAYER M5 ;
        RECT  10.032 25.836 10.056 25.92 ;
    END
  END fd_in[748]
  PIN fd_in[749]
    DIRECTION INPUT ;
    USE SIGNAL ;
    PORT
      LAYER M5 ;
        RECT  9.84 25.836 9.864 25.92 ;
    END
  END fd_in[749]
  PIN fd_in[74]
    DIRECTION INPUT ;
    USE SIGNAL ;
    PORT
      LAYER M5 ;
        RECT  137.52 25.836 137.544 25.92 ;
    END
  END fd_in[74]
  PIN fd_in[750]
    DIRECTION INPUT ;
    USE SIGNAL ;
    PORT
      LAYER M5 ;
        RECT  9.648 25.836 9.672 25.92 ;
    END
  END fd_in[750]
  PIN fd_in[751]
    DIRECTION INPUT ;
    USE SIGNAL ;
    PORT
      LAYER M5 ;
        RECT  9.456 25.836 9.48 25.92 ;
    END
  END fd_in[751]
  PIN fd_in[752]
    DIRECTION INPUT ;
    USE SIGNAL ;
    PORT
      LAYER M5 ;
        RECT  9.312 25.836 9.336 25.92 ;
    END
  END fd_in[752]
  PIN fd_in[753]
    DIRECTION INPUT ;
    USE SIGNAL ;
    PORT
      LAYER M5 ;
        RECT  9.12 25.836 9.144 25.92 ;
    END
  END fd_in[753]
  PIN fd_in[754]
    DIRECTION INPUT ;
    USE SIGNAL ;
    PORT
      LAYER M5 ;
        RECT  8.928 25.836 8.952 25.92 ;
    END
  END fd_in[754]
  PIN fd_in[755]
    DIRECTION INPUT ;
    USE SIGNAL ;
    PORT
      LAYER M5 ;
        RECT  8.736 25.836 8.76 25.92 ;
    END
  END fd_in[755]
  PIN fd_in[756]
    DIRECTION INPUT ;
    USE SIGNAL ;
    PORT
      LAYER M5 ;
        RECT  8.592 25.836 8.616 25.92 ;
    END
  END fd_in[756]
  PIN fd_in[757]
    DIRECTION INPUT ;
    USE SIGNAL ;
    PORT
      LAYER M5 ;
        RECT  8.4 25.836 8.424 25.92 ;
    END
  END fd_in[757]
  PIN fd_in[758]
    DIRECTION INPUT ;
    USE SIGNAL ;
    PORT
      LAYER M5 ;
        RECT  8.208 25.836 8.232 25.92 ;
    END
  END fd_in[758]
  PIN fd_in[759]
    DIRECTION INPUT ;
    USE SIGNAL ;
    PORT
      LAYER M5 ;
        RECT  8.064 25.836 8.088 25.92 ;
    END
  END fd_in[759]
  PIN fd_in[75]
    DIRECTION INPUT ;
    USE SIGNAL ;
    PORT
      LAYER M5 ;
        RECT  137.712 25.836 137.736 25.92 ;
    END
  END fd_in[75]
  PIN fd_in[760]
    DIRECTION INPUT ;
    USE SIGNAL ;
    PORT
      LAYER M5 ;
        RECT  7.872 25.836 7.896 25.92 ;
    END
  END fd_in[760]
  PIN fd_in[761]
    DIRECTION INPUT ;
    USE SIGNAL ;
    PORT
      LAYER M5 ;
        RECT  7.68 25.836 7.704 25.92 ;
    END
  END fd_in[761]
  PIN fd_in[762]
    DIRECTION INPUT ;
    USE SIGNAL ;
    PORT
      LAYER M5 ;
        RECT  7.488 25.836 7.512 25.92 ;
    END
  END fd_in[762]
  PIN fd_in[763]
    DIRECTION INPUT ;
    USE SIGNAL ;
    PORT
      LAYER M5 ;
        RECT  7.344 25.836 7.368 25.92 ;
    END
  END fd_in[763]
  PIN fd_in[764]
    DIRECTION INPUT ;
    USE SIGNAL ;
    PORT
      LAYER M5 ;
        RECT  7.152 25.836 7.176 25.92 ;
    END
  END fd_in[764]
  PIN fd_in[765]
    DIRECTION INPUT ;
    USE SIGNAL ;
    PORT
      LAYER M5 ;
        RECT  6.96 25.836 6.984 25.92 ;
    END
  END fd_in[765]
  PIN fd_in[766]
    DIRECTION INPUT ;
    USE SIGNAL ;
    PORT
      LAYER M5 ;
        RECT  6.768 25.836 6.792 25.92 ;
    END
  END fd_in[766]
  PIN fd_in[767]
    DIRECTION INPUT ;
    USE SIGNAL ;
    PORT
      LAYER M5 ;
        RECT  6.624 25.836 6.648 25.92 ;
    END
  END fd_in[767]
  PIN fd_in[768]
    DIRECTION INPUT ;
    USE SIGNAL ;
    PORT
      LAYER M5 ;
        RECT  6.432 25.836 6.456 25.92 ;
    END
  END fd_in[768]
  PIN fd_in[769]
    DIRECTION INPUT ;
    USE SIGNAL ;
    PORT
      LAYER M5 ;
        RECT  6.24 25.836 6.264 25.92 ;
    END
  END fd_in[769]
  PIN fd_in[76]
    DIRECTION INPUT ;
    USE SIGNAL ;
    PORT
      LAYER M5 ;
        RECT  137.904 25.836 137.928 25.92 ;
    END
  END fd_in[76]
  PIN fd_in[770]
    DIRECTION INPUT ;
    USE SIGNAL ;
    PORT
      LAYER M5 ;
        RECT  6.048 25.836 6.072 25.92 ;
    END
  END fd_in[770]
  PIN fd_in[771]
    DIRECTION INPUT ;
    USE SIGNAL ;
    PORT
      LAYER M5 ;
        RECT  5.904 25.836 5.928 25.92 ;
    END
  END fd_in[771]
  PIN fd_in[772]
    DIRECTION INPUT ;
    USE SIGNAL ;
    PORT
      LAYER M5 ;
        RECT  5.712 25.836 5.736 25.92 ;
    END
  END fd_in[772]
  PIN fd_in[773]
    DIRECTION INPUT ;
    USE SIGNAL ;
    PORT
      LAYER M5 ;
        RECT  5.52 25.836 5.544 25.92 ;
    END
  END fd_in[773]
  PIN fd_in[774]
    DIRECTION INPUT ;
    USE SIGNAL ;
    PORT
      LAYER M5 ;
        RECT  5.328 25.836 5.352 25.92 ;
    END
  END fd_in[774]
  PIN fd_in[775]
    DIRECTION INPUT ;
    USE SIGNAL ;
    PORT
      LAYER M5 ;
        RECT  5.184 25.836 5.208 25.92 ;
    END
  END fd_in[775]
  PIN fd_in[776]
    DIRECTION INPUT ;
    USE SIGNAL ;
    PORT
      LAYER M5 ;
        RECT  4.992 25.836 5.016 25.92 ;
    END
  END fd_in[776]
  PIN fd_in[777]
    DIRECTION INPUT ;
    USE SIGNAL ;
    PORT
      LAYER M5 ;
        RECT  4.8 25.836 4.824 25.92 ;
    END
  END fd_in[777]
  PIN fd_in[778]
    DIRECTION INPUT ;
    USE SIGNAL ;
    PORT
      LAYER M5 ;
        RECT  4.656 25.836 4.68 25.92 ;
    END
  END fd_in[778]
  PIN fd_in[779]
    DIRECTION INPUT ;
    USE SIGNAL ;
    PORT
      LAYER M5 ;
        RECT  4.464 25.836 4.488 25.92 ;
    END
  END fd_in[779]
  PIN fd_in[77]
    DIRECTION INPUT ;
    USE SIGNAL ;
    PORT
      LAYER M5 ;
        RECT  138.048 25.836 138.072 25.92 ;
    END
  END fd_in[77]
  PIN fd_in[780]
    DIRECTION INPUT ;
    USE SIGNAL ;
    PORT
      LAYER M5 ;
        RECT  4.272 25.836 4.296 25.92 ;
    END
  END fd_in[780]
  PIN fd_in[781]
    DIRECTION INPUT ;
    USE SIGNAL ;
    PORT
      LAYER M5 ;
        RECT  4.08 25.836 4.104 25.92 ;
    END
  END fd_in[781]
  PIN fd_in[782]
    DIRECTION INPUT ;
    USE SIGNAL ;
    PORT
      LAYER M5 ;
        RECT  3.936 25.836 3.96 25.92 ;
    END
  END fd_in[782]
  PIN fd_in[783]
    DIRECTION INPUT ;
    USE SIGNAL ;
    PORT
      LAYER M5 ;
        RECT  3.744 25.836 3.768 25.92 ;
    END
  END fd_in[783]
  PIN fd_in[784]
    DIRECTION INPUT ;
    USE SIGNAL ;
    PORT
      LAYER M5 ;
        RECT  3.552 25.836 3.576 25.92 ;
    END
  END fd_in[784]
  PIN fd_in[785]
    DIRECTION INPUT ;
    USE SIGNAL ;
    PORT
      LAYER M5 ;
        RECT  3.36 25.836 3.384 25.92 ;
    END
  END fd_in[785]
  PIN fd_in[786]
    DIRECTION INPUT ;
    USE SIGNAL ;
    PORT
      LAYER M5 ;
        RECT  3.216 25.836 3.24 25.92 ;
    END
  END fd_in[786]
  PIN fd_in[787]
    DIRECTION INPUT ;
    USE SIGNAL ;
    PORT
      LAYER M5 ;
        RECT  3.024 25.836 3.048 25.92 ;
    END
  END fd_in[787]
  PIN fd_in[788]
    DIRECTION INPUT ;
    USE SIGNAL ;
    PORT
      LAYER M5 ;
        RECT  2.832 25.836 2.856 25.92 ;
    END
  END fd_in[788]
  PIN fd_in[789]
    DIRECTION INPUT ;
    USE SIGNAL ;
    PORT
      LAYER M5 ;
        RECT  2.64 25.836 2.664 25.92 ;
    END
  END fd_in[789]
  PIN fd_in[78]
    DIRECTION INPUT ;
    USE SIGNAL ;
    PORT
      LAYER M5 ;
        RECT  138.24 25.836 138.264 25.92 ;
    END
  END fd_in[78]
  PIN fd_in[790]
    DIRECTION INPUT ;
    USE SIGNAL ;
    PORT
      LAYER M5 ;
        RECT  2.496 25.836 2.52 25.92 ;
    END
  END fd_in[790]
  PIN fd_in[791]
    DIRECTION INPUT ;
    USE SIGNAL ;
    PORT
      LAYER M5 ;
        RECT  2.304 25.836 2.328 25.92 ;
    END
  END fd_in[791]
  PIN fd_in[792]
    DIRECTION INPUT ;
    USE SIGNAL ;
    PORT
      LAYER M5 ;
        RECT  2.112 25.836 2.136 25.92 ;
    END
  END fd_in[792]
  PIN fd_in[793]
    DIRECTION INPUT ;
    USE SIGNAL ;
    PORT
      LAYER M5 ;
        RECT  1.92 25.836 1.944 25.92 ;
    END
  END fd_in[793]
  PIN fd_in[794]
    DIRECTION INPUT ;
    USE SIGNAL ;
    PORT
      LAYER M5 ;
        RECT  1.776 25.836 1.8 25.92 ;
    END
  END fd_in[794]
  PIN fd_in[795]
    DIRECTION INPUT ;
    USE SIGNAL ;
    PORT
      LAYER M5 ;
        RECT  1.584 25.836 1.608 25.92 ;
    END
  END fd_in[795]
  PIN fd_in[796]
    DIRECTION INPUT ;
    USE SIGNAL ;
    PORT
      LAYER M5 ;
        RECT  1.392 25.836 1.416 25.92 ;
    END
  END fd_in[796]
  PIN fd_in[797]
    DIRECTION INPUT ;
    USE SIGNAL ;
    PORT
      LAYER M5 ;
        RECT  1.248 25.836 1.272 25.92 ;
    END
  END fd_in[797]
  PIN fd_in[798]
    DIRECTION INPUT ;
    USE SIGNAL ;
    PORT
      LAYER M5 ;
        RECT  1.056 25.836 1.08 25.92 ;
    END
  END fd_in[798]
  PIN fd_in[799]
    DIRECTION INPUT ;
    USE SIGNAL ;
    PORT
      LAYER M5 ;
        RECT  0.864 25.836 0.888 25.92 ;
    END
  END fd_in[799]
  PIN fd_in[79]
    DIRECTION INPUT ;
    USE SIGNAL ;
    PORT
      LAYER M5 ;
        RECT  138.432 25.836 138.456 25.92 ;
    END
  END fd_in[79]
  PIN fd_in[7]
    DIRECTION INPUT ;
    USE SIGNAL ;
    PORT
      LAYER M5 ;
        RECT  131.232 25.836 131.256 25.92 ;
    END
  END fd_in[7]
  PIN fd_in[800]
    DIRECTION INPUT ;
    USE SIGNAL ;
    PORT
      LAYER M5 ;
        RECT  0.672 25.836 0.696 25.92 ;
    END
  END fd_in[800]
  PIN fd_in[801]
    DIRECTION INPUT ;
    USE SIGNAL ;
    PORT
      LAYER M5 ;
        RECT  0.528 25.836 0.552 25.92 ;
    END
  END fd_in[801]
  PIN fd_in[802]
    DIRECTION INPUT ;
    USE SIGNAL ;
    PORT
      LAYER M5 ;
        RECT  0.336 25.836 0.36 25.92 ;
    END
  END fd_in[802]
  PIN fd_in[803]
    DIRECTION INPUT ;
    USE SIGNAL ;
    PORT
      LAYER M5 ;
        RECT  0.144 25.836 0.168 25.92 ;
    END
  END fd_in[803]
  PIN fd_in[80]
    DIRECTION INPUT ;
    USE SIGNAL ;
    PORT
      LAYER M5 ;
        RECT  138.624 25.836 138.648 25.92 ;
    END
  END fd_in[80]
  PIN fd_in[81]
    DIRECTION INPUT ;
    USE SIGNAL ;
    PORT
      LAYER M5 ;
        RECT  138.768 25.836 138.792 25.92 ;
    END
  END fd_in[81]
  PIN fd_in[82]
    DIRECTION INPUT ;
    USE SIGNAL ;
    PORT
      LAYER M5 ;
        RECT  138.96 25.836 138.984 25.92 ;
    END
  END fd_in[82]
  PIN fd_in[83]
    DIRECTION INPUT ;
    USE SIGNAL ;
    PORT
      LAYER M5 ;
        RECT  139.152 25.836 139.176 25.92 ;
    END
  END fd_in[83]
  PIN fd_in[84]
    DIRECTION INPUT ;
    USE SIGNAL ;
    PORT
      LAYER M5 ;
        RECT  139.296 25.836 139.32 25.92 ;
    END
  END fd_in[84]
  PIN fd_in[85]
    DIRECTION INPUT ;
    USE SIGNAL ;
    PORT
      LAYER M5 ;
        RECT  139.488 25.836 139.512 25.92 ;
    END
  END fd_in[85]
  PIN fd_in[86]
    DIRECTION INPUT ;
    USE SIGNAL ;
    PORT
      LAYER M5 ;
        RECT  139.68 25.836 139.704 25.92 ;
    END
  END fd_in[86]
  PIN fd_in[87]
    DIRECTION INPUT ;
    USE SIGNAL ;
    PORT
      LAYER M5 ;
        RECT  139.872 25.836 139.896 25.92 ;
    END
  END fd_in[87]
  PIN fd_in[88]
    DIRECTION INPUT ;
    USE SIGNAL ;
    PORT
      LAYER M5 ;
        RECT  140.016 25.836 140.04 25.92 ;
    END
  END fd_in[88]
  PIN fd_in[89]
    DIRECTION INPUT ;
    USE SIGNAL ;
    PORT
      LAYER M5 ;
        RECT  140.208 25.836 140.232 25.92 ;
    END
  END fd_in[89]
  PIN fd_in[8]
    DIRECTION INPUT ;
    USE SIGNAL ;
    PORT
      LAYER M5 ;
        RECT  131.424 25.836 131.448 25.92 ;
    END
  END fd_in[8]
  PIN fd_in[90]
    DIRECTION INPUT ;
    USE SIGNAL ;
    PORT
      LAYER M5 ;
        RECT  140.4 25.836 140.424 25.92 ;
    END
  END fd_in[90]
  PIN fd_in[91]
    DIRECTION INPUT ;
    USE SIGNAL ;
    PORT
      LAYER M5 ;
        RECT  140.592 25.836 140.616 25.92 ;
    END
  END fd_in[91]
  PIN fd_in[92]
    DIRECTION INPUT ;
    USE SIGNAL ;
    PORT
      LAYER M5 ;
        RECT  140.736 25.836 140.76 25.92 ;
    END
  END fd_in[92]
  PIN fd_in[93]
    DIRECTION INPUT ;
    USE SIGNAL ;
    PORT
      LAYER M5 ;
        RECT  140.928 25.836 140.952 25.92 ;
    END
  END fd_in[93]
  PIN fd_in[94]
    DIRECTION INPUT ;
    USE SIGNAL ;
    PORT
      LAYER M5 ;
        RECT  141.12 25.836 141.144 25.92 ;
    END
  END fd_in[94]
  PIN fd_in[95]
    DIRECTION INPUT ;
    USE SIGNAL ;
    PORT
      LAYER M5 ;
        RECT  141.312 25.836 141.336 25.92 ;
    END
  END fd_in[95]
  PIN fd_in[96]
    DIRECTION INPUT ;
    USE SIGNAL ;
    PORT
      LAYER M5 ;
        RECT  118.512 25.836 118.536 25.92 ;
    END
  END fd_in[96]
  PIN fd_in[97]
    DIRECTION INPUT ;
    USE SIGNAL ;
    PORT
      LAYER M5 ;
        RECT  118.704 25.836 118.728 25.92 ;
    END
  END fd_in[97]
  PIN fd_in[98]
    DIRECTION INPUT ;
    USE SIGNAL ;
    PORT
      LAYER M5 ;
        RECT  118.896 25.836 118.92 25.92 ;
    END
  END fd_in[98]
  PIN fd_in[99]
    DIRECTION INPUT ;
    USE SIGNAL ;
    PORT
      LAYER M5 ;
        RECT  119.04 25.836 119.064 25.92 ;
    END
  END fd_in[99]
  PIN fd_in[9]
    DIRECTION INPUT ;
    USE SIGNAL ;
    PORT
      LAYER M5 ;
        RECT  131.616 25.836 131.64 25.92 ;
    END
  END fd_in[9]
  PIN fdm[0]
    DIRECTION OUTPUT ;
    USE SIGNAL ;
    PORT
      LAYER M5 ;
        RECT  129.984 0 130.008 0.084 ;
    END
  END fdm[0]
  PIN fdm[100]
    DIRECTION OUTPUT ;
    USE SIGNAL ;
    PORT
      LAYER M5 ;
        RECT  119.232 0 119.256 0.084 ;
    END
  END fdm[100]
  PIN fdm[101]
    DIRECTION OUTPUT ;
    USE SIGNAL ;
    PORT
      LAYER M5 ;
        RECT  119.424 0 119.448 0.084 ;
    END
  END fdm[101]
  PIN fdm[102]
    DIRECTION OUTPUT ;
    USE SIGNAL ;
    PORT
      LAYER M5 ;
        RECT  119.568 0 119.592 0.084 ;
    END
  END fdm[102]
  PIN fdm[103]
    DIRECTION OUTPUT ;
    USE SIGNAL ;
    PORT
      LAYER M5 ;
        RECT  119.76 0 119.784 0.084 ;
    END
  END fdm[103]
  PIN fdm[104]
    DIRECTION OUTPUT ;
    USE SIGNAL ;
    PORT
      LAYER M5 ;
        RECT  119.952 0 119.976 0.084 ;
    END
  END fdm[104]
  PIN fdm[105]
    DIRECTION OUTPUT ;
    USE SIGNAL ;
    PORT
      LAYER M5 ;
        RECT  120.144 0 120.168 0.084 ;
    END
  END fdm[105]
  PIN fdm[106]
    DIRECTION OUTPUT ;
    USE SIGNAL ;
    PORT
      LAYER M5 ;
        RECT  120.288 0 120.312 0.084 ;
    END
  END fdm[106]
  PIN fdm[107]
    DIRECTION OUTPUT ;
    USE SIGNAL ;
    PORT
      LAYER M5 ;
        RECT  120.48 0 120.504 0.084 ;
    END
  END fdm[107]
  PIN fdm[108]
    DIRECTION OUTPUT ;
    USE SIGNAL ;
    PORT
      LAYER M5 ;
        RECT  120.672 0 120.696 0.084 ;
    END
  END fdm[108]
  PIN fdm[109]
    DIRECTION OUTPUT ;
    USE SIGNAL ;
    PORT
      LAYER M5 ;
        RECT  120.864 0 120.888 0.084 ;
    END
  END fdm[109]
  PIN fdm[10]
    DIRECTION OUTPUT ;
    USE SIGNAL ;
    PORT
      LAYER M5 ;
        RECT  131.808 0 131.832 0.084 ;
    END
  END fdm[10]
  PIN fdm[110]
    DIRECTION OUTPUT ;
    USE SIGNAL ;
    PORT
      LAYER M5 ;
        RECT  121.008 0 121.032 0.084 ;
    END
  END fdm[110]
  PIN fdm[111]
    DIRECTION OUTPUT ;
    USE SIGNAL ;
    PORT
      LAYER M5 ;
        RECT  121.2 0 121.224 0.084 ;
    END
  END fdm[111]
  PIN fdm[112]
    DIRECTION OUTPUT ;
    USE SIGNAL ;
    PORT
      LAYER M5 ;
        RECT  121.392 0 121.416 0.084 ;
    END
  END fdm[112]
  PIN fdm[113]
    DIRECTION OUTPUT ;
    USE SIGNAL ;
    PORT
      LAYER M5 ;
        RECT  121.584 0 121.608 0.084 ;
    END
  END fdm[113]
  PIN fdm[114]
    DIRECTION OUTPUT ;
    USE SIGNAL ;
    PORT
      LAYER M5 ;
        RECT  121.728 0 121.752 0.084 ;
    END
  END fdm[114]
  PIN fdm[115]
    DIRECTION OUTPUT ;
    USE SIGNAL ;
    PORT
      LAYER M5 ;
        RECT  121.92 0 121.944 0.084 ;
    END
  END fdm[115]
  PIN fdm[116]
    DIRECTION OUTPUT ;
    USE SIGNAL ;
    PORT
      LAYER M5 ;
        RECT  122.112 0 122.136 0.084 ;
    END
  END fdm[116]
  PIN fdm[117]
    DIRECTION OUTPUT ;
    USE SIGNAL ;
    PORT
      LAYER M5 ;
        RECT  122.304 0 122.328 0.084 ;
    END
  END fdm[117]
  PIN fdm[118]
    DIRECTION OUTPUT ;
    USE SIGNAL ;
    PORT
      LAYER M5 ;
        RECT  122.448 0 122.472 0.084 ;
    END
  END fdm[118]
  PIN fdm[119]
    DIRECTION OUTPUT ;
    USE SIGNAL ;
    PORT
      LAYER M5 ;
        RECT  122.64 0 122.664 0.084 ;
    END
  END fdm[119]
  PIN fdm[11]
    DIRECTION OUTPUT ;
    USE SIGNAL ;
    PORT
      LAYER M5 ;
        RECT  131.952 0 131.976 0.084 ;
    END
  END fdm[11]
  PIN fdm[120]
    DIRECTION OUTPUT ;
    USE SIGNAL ;
    PORT
      LAYER M5 ;
        RECT  122.832 0 122.856 0.084 ;
    END
  END fdm[120]
  PIN fdm[121]
    DIRECTION OUTPUT ;
    USE SIGNAL ;
    PORT
      LAYER M5 ;
        RECT  122.976 0 123 0.084 ;
    END
  END fdm[121]
  PIN fdm[122]
    DIRECTION OUTPUT ;
    USE SIGNAL ;
    PORT
      LAYER M5 ;
        RECT  123.168 0 123.192 0.084 ;
    END
  END fdm[122]
  PIN fdm[123]
    DIRECTION OUTPUT ;
    USE SIGNAL ;
    PORT
      LAYER M5 ;
        RECT  123.36 0 123.384 0.084 ;
    END
  END fdm[123]
  PIN fdm[124]
    DIRECTION OUTPUT ;
    USE SIGNAL ;
    PORT
      LAYER M5 ;
        RECT  123.552 0 123.576 0.084 ;
    END
  END fdm[124]
  PIN fdm[125]
    DIRECTION OUTPUT ;
    USE SIGNAL ;
    PORT
      LAYER M5 ;
        RECT  123.696 0 123.72 0.084 ;
    END
  END fdm[125]
  PIN fdm[126]
    DIRECTION OUTPUT ;
    USE SIGNAL ;
    PORT
      LAYER M5 ;
        RECT  123.888 0 123.912 0.084 ;
    END
  END fdm[126]
  PIN fdm[127]
    DIRECTION OUTPUT ;
    USE SIGNAL ;
    PORT
      LAYER M5 ;
        RECT  124.08 0 124.104 0.084 ;
    END
  END fdm[127]
  PIN fdm[128]
    DIRECTION OUTPUT ;
    USE SIGNAL ;
    PORT
      LAYER M5 ;
        RECT  141.456 0 141.48 0.084 ;
    END
  END fdm[128]
  PIN fdm[129]
    DIRECTION OUTPUT ;
    USE SIGNAL ;
    PORT
      LAYER M5 ;
        RECT  141.648 0 141.672 0.084 ;
    END
  END fdm[129]
  PIN fdm[12]
    DIRECTION OUTPUT ;
    USE SIGNAL ;
    PORT
      LAYER M5 ;
        RECT  132.144 0 132.168 0.084 ;
    END
  END fdm[12]
  PIN fdm[130]
    DIRECTION OUTPUT ;
    USE SIGNAL ;
    PORT
      LAYER M5 ;
        RECT  141.84 0 141.864 0.084 ;
    END
  END fdm[130]
  PIN fdm[131]
    DIRECTION OUTPUT ;
    USE SIGNAL ;
    PORT
      LAYER M5 ;
        RECT  142.032 0 142.056 0.084 ;
    END
  END fdm[131]
  PIN fdm[132]
    DIRECTION OUTPUT ;
    USE SIGNAL ;
    PORT
      LAYER M5 ;
        RECT  142.176 0 142.2 0.084 ;
    END
  END fdm[132]
  PIN fdm[133]
    DIRECTION OUTPUT ;
    USE SIGNAL ;
    PORT
      LAYER M5 ;
        RECT  142.368 0 142.392 0.084 ;
    END
  END fdm[133]
  PIN fdm[134]
    DIRECTION OUTPUT ;
    USE SIGNAL ;
    PORT
      LAYER M5 ;
        RECT  142.56 0 142.584 0.084 ;
    END
  END fdm[134]
  PIN fdm[135]
    DIRECTION OUTPUT ;
    USE SIGNAL ;
    PORT
      LAYER M5 ;
        RECT  142.704 0 142.728 0.084 ;
    END
  END fdm[135]
  PIN fdm[136]
    DIRECTION OUTPUT ;
    USE SIGNAL ;
    PORT
      LAYER M5 ;
        RECT  142.896 0 142.92 0.084 ;
    END
  END fdm[136]
  PIN fdm[137]
    DIRECTION OUTPUT ;
    USE SIGNAL ;
    PORT
      LAYER M5 ;
        RECT  143.088 0 143.112 0.084 ;
    END
  END fdm[137]
  PIN fdm[138]
    DIRECTION OUTPUT ;
    USE SIGNAL ;
    PORT
      LAYER M5 ;
        RECT  143.28 0 143.304 0.084 ;
    END
  END fdm[138]
  PIN fdm[139]
    DIRECTION OUTPUT ;
    USE SIGNAL ;
    PORT
      LAYER M5 ;
        RECT  143.424 0 143.448 0.084 ;
    END
  END fdm[139]
  PIN fdm[13]
    DIRECTION OUTPUT ;
    USE SIGNAL ;
    PORT
      LAYER M5 ;
        RECT  132.336 0 132.36 0.084 ;
    END
  END fdm[13]
  PIN fdm[140]
    DIRECTION OUTPUT ;
    USE SIGNAL ;
    PORT
      LAYER M5 ;
        RECT  143.616 0 143.64 0.084 ;
    END
  END fdm[140]
  PIN fdm[141]
    DIRECTION OUTPUT ;
    USE SIGNAL ;
    PORT
      LAYER M5 ;
        RECT  143.808 0 143.832 0.084 ;
    END
  END fdm[141]
  PIN fdm[142]
    DIRECTION OUTPUT ;
    USE SIGNAL ;
    PORT
      LAYER M5 ;
        RECT  144 0 144.024 0.084 ;
    END
  END fdm[142]
  PIN fdm[143]
    DIRECTION OUTPUT ;
    USE SIGNAL ;
    PORT
      LAYER M5 ;
        RECT  144.144 0 144.168 0.084 ;
    END
  END fdm[143]
  PIN fdm[144]
    DIRECTION OUTPUT ;
    USE SIGNAL ;
    PORT
      LAYER M5 ;
        RECT  112.8 0 112.824 0.084 ;
    END
  END fdm[144]
  PIN fdm[145]
    DIRECTION OUTPUT ;
    USE SIGNAL ;
    PORT
      LAYER M5 ;
        RECT  112.944 0 112.968 0.084 ;
    END
  END fdm[145]
  PIN fdm[146]
    DIRECTION OUTPUT ;
    USE SIGNAL ;
    PORT
      LAYER M5 ;
        RECT  113.136 0 113.16 0.084 ;
    END
  END fdm[146]
  PIN fdm[147]
    DIRECTION OUTPUT ;
    USE SIGNAL ;
    PORT
      LAYER M5 ;
        RECT  113.328 0 113.352 0.084 ;
    END
  END fdm[147]
  PIN fdm[148]
    DIRECTION OUTPUT ;
    USE SIGNAL ;
    PORT
      LAYER M5 ;
        RECT  113.472 0 113.496 0.084 ;
    END
  END fdm[148]
  PIN fdm[149]
    DIRECTION OUTPUT ;
    USE SIGNAL ;
    PORT
      LAYER M5 ;
        RECT  113.664 0 113.688 0.084 ;
    END
  END fdm[149]
  PIN fdm[14]
    DIRECTION OUTPUT ;
    USE SIGNAL ;
    PORT
      LAYER M5 ;
        RECT  132.528 0 132.552 0.084 ;
    END
  END fdm[14]
  PIN fdm[150]
    DIRECTION OUTPUT ;
    USE SIGNAL ;
    PORT
      LAYER M5 ;
        RECT  113.856 0 113.88 0.084 ;
    END
  END fdm[150]
  PIN fdm[151]
    DIRECTION OUTPUT ;
    USE SIGNAL ;
    PORT
      LAYER M5 ;
        RECT  114.048 0 114.072 0.084 ;
    END
  END fdm[151]
  PIN fdm[152]
    DIRECTION OUTPUT ;
    USE SIGNAL ;
    PORT
      LAYER M5 ;
        RECT  114.192 0 114.216 0.084 ;
    END
  END fdm[152]
  PIN fdm[153]
    DIRECTION OUTPUT ;
    USE SIGNAL ;
    PORT
      LAYER M5 ;
        RECT  114.384 0 114.408 0.084 ;
    END
  END fdm[153]
  PIN fdm[154]
    DIRECTION OUTPUT ;
    USE SIGNAL ;
    PORT
      LAYER M5 ;
        RECT  114.576 0 114.6 0.084 ;
    END
  END fdm[154]
  PIN fdm[155]
    DIRECTION OUTPUT ;
    USE SIGNAL ;
    PORT
      LAYER M5 ;
        RECT  114.768 0 114.792 0.084 ;
    END
  END fdm[155]
  PIN fdm[156]
    DIRECTION OUTPUT ;
    USE SIGNAL ;
    PORT
      LAYER M5 ;
        RECT  114.912 0 114.936 0.084 ;
    END
  END fdm[156]
  PIN fdm[157]
    DIRECTION OUTPUT ;
    USE SIGNAL ;
    PORT
      LAYER M5 ;
        RECT  115.104 0 115.128 0.084 ;
    END
  END fdm[157]
  PIN fdm[158]
    DIRECTION OUTPUT ;
    USE SIGNAL ;
    PORT
      LAYER M5 ;
        RECT  115.296 0 115.32 0.084 ;
    END
  END fdm[158]
  PIN fdm[159]
    DIRECTION OUTPUT ;
    USE SIGNAL ;
    PORT
      LAYER M5 ;
        RECT  115.488 0 115.512 0.084 ;
    END
  END fdm[159]
  PIN fdm[15]
    DIRECTION OUTPUT ;
    USE SIGNAL ;
    PORT
      LAYER M5 ;
        RECT  132.672 0 132.696 0.084 ;
    END
  END fdm[15]
  PIN fdm[160]
    DIRECTION OUTPUT ;
    USE SIGNAL ;
    PORT
      LAYER M5 ;
        RECT  115.632 0 115.656 0.084 ;
    END
  END fdm[160]
  PIN fdm[161]
    DIRECTION OUTPUT ;
    USE SIGNAL ;
    PORT
      LAYER M5 ;
        RECT  115.824 0 115.848 0.084 ;
    END
  END fdm[161]
  PIN fdm[162]
    DIRECTION OUTPUT ;
    USE SIGNAL ;
    PORT
      LAYER M5 ;
        RECT  116.016 0 116.04 0.084 ;
    END
  END fdm[162]
  PIN fdm[163]
    DIRECTION OUTPUT ;
    USE SIGNAL ;
    PORT
      LAYER M5 ;
        RECT  116.208 0 116.232 0.084 ;
    END
  END fdm[163]
  PIN fdm[164]
    DIRECTION OUTPUT ;
    USE SIGNAL ;
    PORT
      LAYER M5 ;
        RECT  116.352 0 116.376 0.084 ;
    END
  END fdm[164]
  PIN fdm[165]
    DIRECTION OUTPUT ;
    USE SIGNAL ;
    PORT
      LAYER M5 ;
        RECT  116.544 0 116.568 0.084 ;
    END
  END fdm[165]
  PIN fdm[166]
    DIRECTION OUTPUT ;
    USE SIGNAL ;
    PORT
      LAYER M5 ;
        RECT  116.736 0 116.76 0.084 ;
    END
  END fdm[166]
  PIN fdm[167]
    DIRECTION OUTPUT ;
    USE SIGNAL ;
    PORT
      LAYER M5 ;
        RECT  116.88 0 116.904 0.084 ;
    END
  END fdm[167]
  PIN fdm[168]
    DIRECTION OUTPUT ;
    USE SIGNAL ;
    PORT
      LAYER M5 ;
        RECT  117.072 0 117.096 0.084 ;
    END
  END fdm[168]
  PIN fdm[169]
    DIRECTION OUTPUT ;
    USE SIGNAL ;
    PORT
      LAYER M5 ;
        RECT  117.264 0 117.288 0.084 ;
    END
  END fdm[169]
  PIN fdm[16]
    DIRECTION OUTPUT ;
    USE SIGNAL ;
    PORT
      LAYER M5 ;
        RECT  132.864 0 132.888 0.084 ;
    END
  END fdm[16]
  PIN fdm[170]
    DIRECTION OUTPUT ;
    USE SIGNAL ;
    PORT
      LAYER M5 ;
        RECT  117.456 0 117.48 0.084 ;
    END
  END fdm[170]
  PIN fdm[171]
    DIRECTION OUTPUT ;
    USE SIGNAL ;
    PORT
      LAYER M5 ;
        RECT  117.6 0 117.624 0.084 ;
    END
  END fdm[171]
  PIN fdm[172]
    DIRECTION OUTPUT ;
    USE SIGNAL ;
    PORT
      LAYER M5 ;
        RECT  117.792 0 117.816 0.084 ;
    END
  END fdm[172]
  PIN fdm[173]
    DIRECTION OUTPUT ;
    USE SIGNAL ;
    PORT
      LAYER M5 ;
        RECT  117.984 0 118.008 0.084 ;
    END
  END fdm[173]
  PIN fdm[174]
    DIRECTION OUTPUT ;
    USE SIGNAL ;
    PORT
      LAYER M5 ;
        RECT  118.176 0 118.2 0.084 ;
    END
  END fdm[174]
  PIN fdm[175]
    DIRECTION OUTPUT ;
    USE SIGNAL ;
    PORT
      LAYER M5 ;
        RECT  118.32 0 118.344 0.084 ;
    END
  END fdm[175]
  PIN fdm[176]
    DIRECTION OUTPUT ;
    USE SIGNAL ;
    PORT
      LAYER M5 ;
        RECT  101.28 0 101.304 0.084 ;
    END
  END fdm[176]
  PIN fdm[177]
    DIRECTION OUTPUT ;
    USE SIGNAL ;
    PORT
      LAYER M5 ;
        RECT  101.472 0 101.496 0.084 ;
    END
  END fdm[177]
  PIN fdm[178]
    DIRECTION OUTPUT ;
    USE SIGNAL ;
    PORT
      LAYER M5 ;
        RECT  101.664 0 101.688 0.084 ;
    END
  END fdm[178]
  PIN fdm[179]
    DIRECTION OUTPUT ;
    USE SIGNAL ;
    PORT
      LAYER M5 ;
        RECT  101.856 0 101.88 0.084 ;
    END
  END fdm[179]
  PIN fdm[17]
    DIRECTION OUTPUT ;
    USE SIGNAL ;
    PORT
      LAYER M5 ;
        RECT  133.056 0 133.08 0.084 ;
    END
  END fdm[17]
  PIN fdm[180]
    DIRECTION OUTPUT ;
    USE SIGNAL ;
    PORT
      LAYER M5 ;
        RECT  102 0 102.024 0.084 ;
    END
  END fdm[180]
  PIN fdm[181]
    DIRECTION OUTPUT ;
    USE SIGNAL ;
    PORT
      LAYER M5 ;
        RECT  102.192 0 102.216 0.084 ;
    END
  END fdm[181]
  PIN fdm[182]
    DIRECTION OUTPUT ;
    USE SIGNAL ;
    PORT
      LAYER M5 ;
        RECT  102.384 0 102.408 0.084 ;
    END
  END fdm[182]
  PIN fdm[183]
    DIRECTION OUTPUT ;
    USE SIGNAL ;
    PORT
      LAYER M5 ;
        RECT  102.576 0 102.6 0.084 ;
    END
  END fdm[183]
  PIN fdm[184]
    DIRECTION OUTPUT ;
    USE SIGNAL ;
    PORT
      LAYER M5 ;
        RECT  102.72 0 102.744 0.084 ;
    END
  END fdm[184]
  PIN fdm[185]
    DIRECTION OUTPUT ;
    USE SIGNAL ;
    PORT
      LAYER M5 ;
        RECT  102.912 0 102.936 0.084 ;
    END
  END fdm[185]
  PIN fdm[186]
    DIRECTION OUTPUT ;
    USE SIGNAL ;
    PORT
      LAYER M5 ;
        RECT  103.104 0 103.128 0.084 ;
    END
  END fdm[186]
  PIN fdm[187]
    DIRECTION OUTPUT ;
    USE SIGNAL ;
    PORT
      LAYER M5 ;
        RECT  103.248 0 103.272 0.084 ;
    END
  END fdm[187]
  PIN fdm[188]
    DIRECTION OUTPUT ;
    USE SIGNAL ;
    PORT
      LAYER M5 ;
        RECT  103.44 0 103.464 0.084 ;
    END
  END fdm[188]
  PIN fdm[189]
    DIRECTION OUTPUT ;
    USE SIGNAL ;
    PORT
      LAYER M5 ;
        RECT  103.632 0 103.656 0.084 ;
    END
  END fdm[189]
  PIN fdm[18]
    DIRECTION OUTPUT ;
    USE SIGNAL ;
    PORT
      LAYER M5 ;
        RECT  133.2 0 133.224 0.084 ;
    END
  END fdm[18]
  PIN fdm[190]
    DIRECTION OUTPUT ;
    USE SIGNAL ;
    PORT
      LAYER M5 ;
        RECT  103.824 0 103.848 0.084 ;
    END
  END fdm[190]
  PIN fdm[191]
    DIRECTION OUTPUT ;
    USE SIGNAL ;
    PORT
      LAYER M5 ;
        RECT  103.968 0 103.992 0.084 ;
    END
  END fdm[191]
  PIN fdm[192]
    DIRECTION OUTPUT ;
    USE SIGNAL ;
    PORT
      LAYER M5 ;
        RECT  104.16 0 104.184 0.084 ;
    END
  END fdm[192]
  PIN fdm[193]
    DIRECTION OUTPUT ;
    USE SIGNAL ;
    PORT
      LAYER M5 ;
        RECT  104.352 0 104.376 0.084 ;
    END
  END fdm[193]
  PIN fdm[194]
    DIRECTION OUTPUT ;
    USE SIGNAL ;
    PORT
      LAYER M5 ;
        RECT  104.544 0 104.568 0.084 ;
    END
  END fdm[194]
  PIN fdm[195]
    DIRECTION OUTPUT ;
    USE SIGNAL ;
    PORT
      LAYER M5 ;
        RECT  104.688 0 104.712 0.084 ;
    END
  END fdm[195]
  PIN fdm[196]
    DIRECTION OUTPUT ;
    USE SIGNAL ;
    PORT
      LAYER M5 ;
        RECT  104.88 0 104.904 0.084 ;
    END
  END fdm[196]
  PIN fdm[197]
    DIRECTION OUTPUT ;
    USE SIGNAL ;
    PORT
      LAYER M5 ;
        RECT  105.072 0 105.096 0.084 ;
    END
  END fdm[197]
  PIN fdm[198]
    DIRECTION OUTPUT ;
    USE SIGNAL ;
    PORT
      LAYER M5 ;
        RECT  105.264 0 105.288 0.084 ;
    END
  END fdm[198]
  PIN fdm[199]
    DIRECTION OUTPUT ;
    USE SIGNAL ;
    PORT
      LAYER M5 ;
        RECT  105.408 0 105.432 0.084 ;
    END
  END fdm[199]
  PIN fdm[19]
    DIRECTION OUTPUT ;
    USE SIGNAL ;
    PORT
      LAYER M5 ;
        RECT  133.392 0 133.416 0.084 ;
    END
  END fdm[19]
  PIN fdm[1]
    DIRECTION OUTPUT ;
    USE SIGNAL ;
    PORT
      LAYER M5 ;
        RECT  130.176 0 130.2 0.084 ;
    END
  END fdm[1]
  PIN fdm[200]
    DIRECTION OUTPUT ;
    USE SIGNAL ;
    PORT
      LAYER M5 ;
        RECT  105.6 0 105.624 0.084 ;
    END
  END fdm[200]
  PIN fdm[201]
    DIRECTION OUTPUT ;
    USE SIGNAL ;
    PORT
      LAYER M5 ;
        RECT  105.792 0 105.816 0.084 ;
    END
  END fdm[201]
  PIN fdm[202]
    DIRECTION OUTPUT ;
    USE SIGNAL ;
    PORT
      LAYER M5 ;
        RECT  105.984 0 106.008 0.084 ;
    END
  END fdm[202]
  PIN fdm[203]
    DIRECTION OUTPUT ;
    USE SIGNAL ;
    PORT
      LAYER M5 ;
        RECT  106.128 0 106.152 0.084 ;
    END
  END fdm[203]
  PIN fdm[204]
    DIRECTION OUTPUT ;
    USE SIGNAL ;
    PORT
      LAYER M5 ;
        RECT  106.32 0 106.344 0.084 ;
    END
  END fdm[204]
  PIN fdm[205]
    DIRECTION OUTPUT ;
    USE SIGNAL ;
    PORT
      LAYER M5 ;
        RECT  106.512 0 106.536 0.084 ;
    END
  END fdm[205]
  PIN fdm[206]
    DIRECTION OUTPUT ;
    USE SIGNAL ;
    PORT
      LAYER M5 ;
        RECT  106.656 0 106.68 0.084 ;
    END
  END fdm[206]
  PIN fdm[207]
    DIRECTION OUTPUT ;
    USE SIGNAL ;
    PORT
      LAYER M5 ;
        RECT  106.848 0 106.872 0.084 ;
    END
  END fdm[207]
  PIN fdm[208]
    DIRECTION OUTPUT ;
    USE SIGNAL ;
    PORT
      LAYER M5 ;
        RECT  78.336 0 78.36 0.084 ;
    END
  END fdm[208]
  PIN fdm[209]
    DIRECTION OUTPUT ;
    USE SIGNAL ;
    PORT
      LAYER M5 ;
        RECT  78.528 0 78.552 0.084 ;
    END
  END fdm[209]
  PIN fdm[20]
    DIRECTION OUTPUT ;
    USE SIGNAL ;
    PORT
      LAYER M5 ;
        RECT  133.584 0 133.608 0.084 ;
    END
  END fdm[20]
  PIN fdm[210]
    DIRECTION OUTPUT ;
    USE SIGNAL ;
    PORT
      LAYER M5 ;
        RECT  78.72 0 78.744 0.084 ;
    END
  END fdm[210]
  PIN fdm[211]
    DIRECTION OUTPUT ;
    USE SIGNAL ;
    PORT
      LAYER M5 ;
        RECT  78.864 0 78.888 0.084 ;
    END
  END fdm[211]
  PIN fdm[212]
    DIRECTION OUTPUT ;
    USE SIGNAL ;
    PORT
      LAYER M5 ;
        RECT  79.056 0 79.08 0.084 ;
    END
  END fdm[212]
  PIN fdm[213]
    DIRECTION OUTPUT ;
    USE SIGNAL ;
    PORT
      LAYER M5 ;
        RECT  79.248 0 79.272 0.084 ;
    END
  END fdm[213]
  PIN fdm[214]
    DIRECTION OUTPUT ;
    USE SIGNAL ;
    PORT
      LAYER M5 ;
        RECT  79.44 0 79.464 0.084 ;
    END
  END fdm[214]
  PIN fdm[215]
    DIRECTION OUTPUT ;
    USE SIGNAL ;
    PORT
      LAYER M5 ;
        RECT  79.584 0 79.608 0.084 ;
    END
  END fdm[215]
  PIN fdm[216]
    DIRECTION OUTPUT ;
    USE SIGNAL ;
    PORT
      LAYER M5 ;
        RECT  79.776 0 79.8 0.084 ;
    END
  END fdm[216]
  PIN fdm[217]
    DIRECTION OUTPUT ;
    USE SIGNAL ;
    PORT
      LAYER M5 ;
        RECT  79.968 0 79.992 0.084 ;
    END
  END fdm[217]
  PIN fdm[218]
    DIRECTION OUTPUT ;
    USE SIGNAL ;
    PORT
      LAYER M5 ;
        RECT  80.16 0 80.184 0.084 ;
    END
  END fdm[218]
  PIN fdm[219]
    DIRECTION OUTPUT ;
    USE SIGNAL ;
    PORT
      LAYER M5 ;
        RECT  80.304 0 80.328 0.084 ;
    END
  END fdm[219]
  PIN fdm[21]
    DIRECTION OUTPUT ;
    USE SIGNAL ;
    PORT
      LAYER M5 ;
        RECT  133.776 0 133.8 0.084 ;
    END
  END fdm[21]
  PIN fdm[220]
    DIRECTION OUTPUT ;
    USE SIGNAL ;
    PORT
      LAYER M5 ;
        RECT  80.496 0 80.52 0.084 ;
    END
  END fdm[220]
  PIN fdm[221]
    DIRECTION OUTPUT ;
    USE SIGNAL ;
    PORT
      LAYER M5 ;
        RECT  80.688 0 80.712 0.084 ;
    END
  END fdm[221]
  PIN fdm[222]
    DIRECTION OUTPUT ;
    USE SIGNAL ;
    PORT
      LAYER M5 ;
        RECT  80.832 0 80.856 0.084 ;
    END
  END fdm[222]
  PIN fdm[223]
    DIRECTION OUTPUT ;
    USE SIGNAL ;
    PORT
      LAYER M5 ;
        RECT  81.024 0 81.048 0.084 ;
    END
  END fdm[223]
  PIN fdm[224]
    DIRECTION OUTPUT ;
    USE SIGNAL ;
    PORT
      LAYER M5 ;
        RECT  81.216 0 81.24 0.084 ;
    END
  END fdm[224]
  PIN fdm[225]
    DIRECTION OUTPUT ;
    USE SIGNAL ;
    PORT
      LAYER M5 ;
        RECT  81.408 0 81.432 0.084 ;
    END
  END fdm[225]
  PIN fdm[226]
    DIRECTION OUTPUT ;
    USE SIGNAL ;
    PORT
      LAYER M5 ;
        RECT  81.552 0 81.576 0.084 ;
    END
  END fdm[226]
  PIN fdm[227]
    DIRECTION OUTPUT ;
    USE SIGNAL ;
    PORT
      LAYER M5 ;
        RECT  81.744 0 81.768 0.084 ;
    END
  END fdm[227]
  PIN fdm[228]
    DIRECTION OUTPUT ;
    USE SIGNAL ;
    PORT
      LAYER M5 ;
        RECT  81.936 0 81.96 0.084 ;
    END
  END fdm[228]
  PIN fdm[229]
    DIRECTION OUTPUT ;
    USE SIGNAL ;
    PORT
      LAYER M5 ;
        RECT  82.128 0 82.152 0.084 ;
    END
  END fdm[229]
  PIN fdm[22]
    DIRECTION OUTPUT ;
    USE SIGNAL ;
    PORT
      LAYER M5 ;
        RECT  133.92 0 133.944 0.084 ;
    END
  END fdm[22]
  PIN fdm[230]
    DIRECTION OUTPUT ;
    USE SIGNAL ;
    PORT
      LAYER M5 ;
        RECT  82.272 0 82.296 0.084 ;
    END
  END fdm[230]
  PIN fdm[231]
    DIRECTION OUTPUT ;
    USE SIGNAL ;
    PORT
      LAYER M5 ;
        RECT  82.464 0 82.488 0.084 ;
    END
  END fdm[231]
  PIN fdm[232]
    DIRECTION OUTPUT ;
    USE SIGNAL ;
    PORT
      LAYER M5 ;
        RECT  82.656 0 82.68 0.084 ;
    END
  END fdm[232]
  PIN fdm[233]
    DIRECTION OUTPUT ;
    USE SIGNAL ;
    PORT
      LAYER M5 ;
        RECT  82.848 0 82.872 0.084 ;
    END
  END fdm[233]
  PIN fdm[234]
    DIRECTION OUTPUT ;
    USE SIGNAL ;
    PORT
      LAYER M5 ;
        RECT  82.992 0 83.016 0.084 ;
    END
  END fdm[234]
  PIN fdm[235]
    DIRECTION OUTPUT ;
    USE SIGNAL ;
    PORT
      LAYER M5 ;
        RECT  83.184 0 83.208 0.084 ;
    END
  END fdm[235]
  PIN fdm[236]
    DIRECTION OUTPUT ;
    USE SIGNAL ;
    PORT
      LAYER M5 ;
        RECT  83.376 0 83.4 0.084 ;
    END
  END fdm[236]
  PIN fdm[237]
    DIRECTION OUTPUT ;
    USE SIGNAL ;
    PORT
      LAYER M5 ;
        RECT  83.52 0 83.544 0.084 ;
    END
  END fdm[237]
  PIN fdm[238]
    DIRECTION OUTPUT ;
    USE SIGNAL ;
    PORT
      LAYER M5 ;
        RECT  83.712 0 83.736 0.084 ;
    END
  END fdm[238]
  PIN fdm[239]
    DIRECTION OUTPUT ;
    USE SIGNAL ;
    PORT
      LAYER M5 ;
        RECT  83.904 0 83.928 0.084 ;
    END
  END fdm[239]
  PIN fdm[23]
    DIRECTION OUTPUT ;
    USE SIGNAL ;
    PORT
      LAYER M5 ;
        RECT  134.112 0 134.136 0.084 ;
    END
  END fdm[23]
  PIN fdm[240]
    DIRECTION OUTPUT ;
    USE SIGNAL ;
    PORT
      LAYER M5 ;
        RECT  107.04 0 107.064 0.084 ;
    END
  END fdm[240]
  PIN fdm[241]
    DIRECTION OUTPUT ;
    USE SIGNAL ;
    PORT
      LAYER M5 ;
        RECT  107.232 0 107.256 0.084 ;
    END
  END fdm[241]
  PIN fdm[242]
    DIRECTION OUTPUT ;
    USE SIGNAL ;
    PORT
      LAYER M5 ;
        RECT  107.376 0 107.4 0.084 ;
    END
  END fdm[242]
  PIN fdm[243]
    DIRECTION OUTPUT ;
    USE SIGNAL ;
    PORT
      LAYER M5 ;
        RECT  107.568 0 107.592 0.084 ;
    END
  END fdm[243]
  PIN fdm[244]
    DIRECTION OUTPUT ;
    USE SIGNAL ;
    PORT
      LAYER M5 ;
        RECT  107.76 0 107.784 0.084 ;
    END
  END fdm[244]
  PIN fdm[245]
    DIRECTION OUTPUT ;
    USE SIGNAL ;
    PORT
      LAYER M5 ;
        RECT  107.952 0 107.976 0.084 ;
    END
  END fdm[245]
  PIN fdm[246]
    DIRECTION OUTPUT ;
    USE SIGNAL ;
    PORT
      LAYER M5 ;
        RECT  108.096 0 108.12 0.084 ;
    END
  END fdm[246]
  PIN fdm[247]
    DIRECTION OUTPUT ;
    USE SIGNAL ;
    PORT
      LAYER M5 ;
        RECT  108.288 0 108.312 0.084 ;
    END
  END fdm[247]
  PIN fdm[248]
    DIRECTION OUTPUT ;
    USE SIGNAL ;
    PORT
      LAYER M5 ;
        RECT  108.48 0 108.504 0.084 ;
    END
  END fdm[248]
  PIN fdm[249]
    DIRECTION OUTPUT ;
    USE SIGNAL ;
    PORT
      LAYER M5 ;
        RECT  108.672 0 108.696 0.084 ;
    END
  END fdm[249]
  PIN fdm[24]
    DIRECTION OUTPUT ;
    USE SIGNAL ;
    PORT
      LAYER M5 ;
        RECT  134.304 0 134.328 0.084 ;
    END
  END fdm[24]
  PIN fdm[250]
    DIRECTION OUTPUT ;
    USE SIGNAL ;
    PORT
      LAYER M5 ;
        RECT  108.816 0 108.84 0.084 ;
    END
  END fdm[250]
  PIN fdm[251]
    DIRECTION OUTPUT ;
    USE SIGNAL ;
    PORT
      LAYER M5 ;
        RECT  109.008 0 109.032 0.084 ;
    END
  END fdm[251]
  PIN fdm[252]
    DIRECTION OUTPUT ;
    USE SIGNAL ;
    PORT
      LAYER M5 ;
        RECT  109.2 0 109.224 0.084 ;
    END
  END fdm[252]
  PIN fdm[253]
    DIRECTION OUTPUT ;
    USE SIGNAL ;
    PORT
      LAYER M5 ;
        RECT  109.392 0 109.416 0.084 ;
    END
  END fdm[253]
  PIN fdm[254]
    DIRECTION OUTPUT ;
    USE SIGNAL ;
    PORT
      LAYER M5 ;
        RECT  109.536 0 109.56 0.084 ;
    END
  END fdm[254]
  PIN fdm[255]
    DIRECTION OUTPUT ;
    USE SIGNAL ;
    PORT
      LAYER M5 ;
        RECT  109.728 0 109.752 0.084 ;
    END
  END fdm[255]
  PIN fdm[256]
    DIRECTION OUTPUT ;
    USE SIGNAL ;
    PORT
      LAYER M5 ;
        RECT  109.92 0 109.944 0.084 ;
    END
  END fdm[256]
  PIN fdm[257]
    DIRECTION OUTPUT ;
    USE SIGNAL ;
    PORT
      LAYER M5 ;
        RECT  110.064 0 110.088 0.084 ;
    END
  END fdm[257]
  PIN fdm[258]
    DIRECTION OUTPUT ;
    USE SIGNAL ;
    PORT
      LAYER M5 ;
        RECT  110.256 0 110.28 0.084 ;
    END
  END fdm[258]
  PIN fdm[259]
    DIRECTION OUTPUT ;
    USE SIGNAL ;
    PORT
      LAYER M5 ;
        RECT  110.448 0 110.472 0.084 ;
    END
  END fdm[259]
  PIN fdm[25]
    DIRECTION OUTPUT ;
    USE SIGNAL ;
    PORT
      LAYER M5 ;
        RECT  134.496 0 134.52 0.084 ;
    END
  END fdm[25]
  PIN fdm[260]
    DIRECTION OUTPUT ;
    USE SIGNAL ;
    PORT
      LAYER M5 ;
        RECT  110.64 0 110.664 0.084 ;
    END
  END fdm[260]
  PIN fdm[261]
    DIRECTION OUTPUT ;
    USE SIGNAL ;
    PORT
      LAYER M5 ;
        RECT  110.784 0 110.808 0.084 ;
    END
  END fdm[261]
  PIN fdm[262]
    DIRECTION OUTPUT ;
    USE SIGNAL ;
    PORT
      LAYER M5 ;
        RECT  110.976 0 111 0.084 ;
    END
  END fdm[262]
  PIN fdm[263]
    DIRECTION OUTPUT ;
    USE SIGNAL ;
    PORT
      LAYER M5 ;
        RECT  111.168 0 111.192 0.084 ;
    END
  END fdm[263]
  PIN fdm[264]
    DIRECTION OUTPUT ;
    USE SIGNAL ;
    PORT
      LAYER M5 ;
        RECT  111.36 0 111.384 0.084 ;
    END
  END fdm[264]
  PIN fdm[265]
    DIRECTION OUTPUT ;
    USE SIGNAL ;
    PORT
      LAYER M5 ;
        RECT  111.504 0 111.528 0.084 ;
    END
  END fdm[265]
  PIN fdm[266]
    DIRECTION OUTPUT ;
    USE SIGNAL ;
    PORT
      LAYER M5 ;
        RECT  111.696 0 111.72 0.084 ;
    END
  END fdm[266]
  PIN fdm[267]
    DIRECTION OUTPUT ;
    USE SIGNAL ;
    PORT
      LAYER M5 ;
        RECT  111.888 0 111.912 0.084 ;
    END
  END fdm[267]
  PIN fdm[268]
    DIRECTION OUTPUT ;
    USE SIGNAL ;
    PORT
      LAYER M5 ;
        RECT  112.08 0 112.104 0.084 ;
    END
  END fdm[268]
  PIN fdm[269]
    DIRECTION OUTPUT ;
    USE SIGNAL ;
    PORT
      LAYER M5 ;
        RECT  112.224 0 112.248 0.084 ;
    END
  END fdm[269]
  PIN fdm[26]
    DIRECTION OUTPUT ;
    USE SIGNAL ;
    PORT
      LAYER M5 ;
        RECT  134.64 0 134.664 0.084 ;
    END
  END fdm[26]
  PIN fdm[270]
    DIRECTION OUTPUT ;
    USE SIGNAL ;
    PORT
      LAYER M5 ;
        RECT  112.416 0 112.44 0.084 ;
    END
  END fdm[270]
  PIN fdm[271]
    DIRECTION OUTPUT ;
    USE SIGNAL ;
    PORT
      LAYER M5 ;
        RECT  112.608 0 112.632 0.084 ;
    END
  END fdm[271]
  PIN fdm[272]
    DIRECTION OUTPUT ;
    USE SIGNAL ;
    PORT
      LAYER M5 ;
        RECT  89.808 0 89.832 0.084 ;
    END
  END fdm[272]
  PIN fdm[273]
    DIRECTION OUTPUT ;
    USE SIGNAL ;
    PORT
      LAYER M5 ;
        RECT  90 0 90.024 0.084 ;
    END
  END fdm[273]
  PIN fdm[274]
    DIRECTION OUTPUT ;
    USE SIGNAL ;
    PORT
      LAYER M5 ;
        RECT  90.192 0 90.216 0.084 ;
    END
  END fdm[274]
  PIN fdm[275]
    DIRECTION OUTPUT ;
    USE SIGNAL ;
    PORT
      LAYER M5 ;
        RECT  90.336 0 90.36 0.084 ;
    END
  END fdm[275]
  PIN fdm[276]
    DIRECTION OUTPUT ;
    USE SIGNAL ;
    PORT
      LAYER M5 ;
        RECT  90.528 0 90.552 0.084 ;
    END
  END fdm[276]
  PIN fdm[277]
    DIRECTION OUTPUT ;
    USE SIGNAL ;
    PORT
      LAYER M5 ;
        RECT  90.72 0 90.744 0.084 ;
    END
  END fdm[277]
  PIN fdm[278]
    DIRECTION OUTPUT ;
    USE SIGNAL ;
    PORT
      LAYER M5 ;
        RECT  90.912 0 90.936 0.084 ;
    END
  END fdm[278]
  PIN fdm[279]
    DIRECTION OUTPUT ;
    USE SIGNAL ;
    PORT
      LAYER M5 ;
        RECT  91.056 0 91.08 0.084 ;
    END
  END fdm[279]
  PIN fdm[27]
    DIRECTION OUTPUT ;
    USE SIGNAL ;
    PORT
      LAYER M5 ;
        RECT  134.832 0 134.856 0.084 ;
    END
  END fdm[27]
  PIN fdm[280]
    DIRECTION OUTPUT ;
    USE SIGNAL ;
    PORT
      LAYER M5 ;
        RECT  91.248 0 91.272 0.084 ;
    END
  END fdm[280]
  PIN fdm[281]
    DIRECTION OUTPUT ;
    USE SIGNAL ;
    PORT
      LAYER M5 ;
        RECT  91.44 0 91.464 0.084 ;
    END
  END fdm[281]
  PIN fdm[282]
    DIRECTION OUTPUT ;
    USE SIGNAL ;
    PORT
      LAYER M5 ;
        RECT  91.632 0 91.656 0.084 ;
    END
  END fdm[282]
  PIN fdm[283]
    DIRECTION OUTPUT ;
    USE SIGNAL ;
    PORT
      LAYER M5 ;
        RECT  91.776 0 91.8 0.084 ;
    END
  END fdm[283]
  PIN fdm[284]
    DIRECTION OUTPUT ;
    USE SIGNAL ;
    PORT
      LAYER M5 ;
        RECT  91.968 0 91.992 0.084 ;
    END
  END fdm[284]
  PIN fdm[285]
    DIRECTION OUTPUT ;
    USE SIGNAL ;
    PORT
      LAYER M5 ;
        RECT  92.16 0 92.184 0.084 ;
    END
  END fdm[285]
  PIN fdm[286]
    DIRECTION OUTPUT ;
    USE SIGNAL ;
    PORT
      LAYER M5 ;
        RECT  92.352 0 92.376 0.084 ;
    END
  END fdm[286]
  PIN fdm[287]
    DIRECTION OUTPUT ;
    USE SIGNAL ;
    PORT
      LAYER M5 ;
        RECT  92.496 0 92.52 0.084 ;
    END
  END fdm[287]
  PIN fdm[288]
    DIRECTION OUTPUT ;
    USE SIGNAL ;
    PORT
      LAYER M5 ;
        RECT  92.688 0 92.712 0.084 ;
    END
  END fdm[288]
  PIN fdm[289]
    DIRECTION OUTPUT ;
    USE SIGNAL ;
    PORT
      LAYER M5 ;
        RECT  92.88 0 92.904 0.084 ;
    END
  END fdm[289]
  PIN fdm[28]
    DIRECTION OUTPUT ;
    USE SIGNAL ;
    PORT
      LAYER M5 ;
        RECT  135.024 0 135.048 0.084 ;
    END
  END fdm[28]
  PIN fdm[290]
    DIRECTION OUTPUT ;
    USE SIGNAL ;
    PORT
      LAYER M5 ;
        RECT  93.072 0 93.096 0.084 ;
    END
  END fdm[290]
  PIN fdm[291]
    DIRECTION OUTPUT ;
    USE SIGNAL ;
    PORT
      LAYER M5 ;
        RECT  93.216 0 93.24 0.084 ;
    END
  END fdm[291]
  PIN fdm[292]
    DIRECTION OUTPUT ;
    USE SIGNAL ;
    PORT
      LAYER M5 ;
        RECT  93.408 0 93.432 0.084 ;
    END
  END fdm[292]
  PIN fdm[293]
    DIRECTION OUTPUT ;
    USE SIGNAL ;
    PORT
      LAYER M5 ;
        RECT  93.6 0 93.624 0.084 ;
    END
  END fdm[293]
  PIN fdm[294]
    DIRECTION OUTPUT ;
    USE SIGNAL ;
    PORT
      LAYER M5 ;
        RECT  93.744 0 93.768 0.084 ;
    END
  END fdm[294]
  PIN fdm[295]
    DIRECTION OUTPUT ;
    USE SIGNAL ;
    PORT
      LAYER M5 ;
        RECT  93.936 0 93.96 0.084 ;
    END
  END fdm[295]
  PIN fdm[296]
    DIRECTION OUTPUT ;
    USE SIGNAL ;
    PORT
      LAYER M5 ;
        RECT  94.128 0 94.152 0.084 ;
    END
  END fdm[296]
  PIN fdm[297]
    DIRECTION OUTPUT ;
    USE SIGNAL ;
    PORT
      LAYER M5 ;
        RECT  94.32 0 94.344 0.084 ;
    END
  END fdm[297]
  PIN fdm[298]
    DIRECTION OUTPUT ;
    USE SIGNAL ;
    PORT
      LAYER M5 ;
        RECT  94.464 0 94.488 0.084 ;
    END
  END fdm[298]
  PIN fdm[299]
    DIRECTION OUTPUT ;
    USE SIGNAL ;
    PORT
      LAYER M5 ;
        RECT  94.656 0 94.68 0.084 ;
    END
  END fdm[299]
  PIN fdm[29]
    DIRECTION OUTPUT ;
    USE SIGNAL ;
    PORT
      LAYER M5 ;
        RECT  135.216 0 135.24 0.084 ;
    END
  END fdm[29]
  PIN fdm[2]
    DIRECTION OUTPUT ;
    USE SIGNAL ;
    PORT
      LAYER M5 ;
        RECT  130.368 0 130.392 0.084 ;
    END
  END fdm[2]
  PIN fdm[300]
    DIRECTION OUTPUT ;
    USE SIGNAL ;
    PORT
      LAYER M5 ;
        RECT  94.848 0 94.872 0.084 ;
    END
  END fdm[300]
  PIN fdm[301]
    DIRECTION OUTPUT ;
    USE SIGNAL ;
    PORT
      LAYER M5 ;
        RECT  95.04 0 95.064 0.084 ;
    END
  END fdm[301]
  PIN fdm[302]
    DIRECTION OUTPUT ;
    USE SIGNAL ;
    PORT
      LAYER M5 ;
        RECT  95.184 0 95.208 0.084 ;
    END
  END fdm[302]
  PIN fdm[303]
    DIRECTION OUTPUT ;
    USE SIGNAL ;
    PORT
      LAYER M5 ;
        RECT  95.376 0 95.4 0.084 ;
    END
  END fdm[303]
  PIN fdm[304]
    DIRECTION OUTPUT ;
    USE SIGNAL ;
    PORT
      LAYER M5 ;
        RECT  84.096 0 84.12 0.084 ;
    END
  END fdm[304]
  PIN fdm[305]
    DIRECTION OUTPUT ;
    USE SIGNAL ;
    PORT
      LAYER M5 ;
        RECT  84.24 0 84.264 0.084 ;
    END
  END fdm[305]
  PIN fdm[306]
    DIRECTION OUTPUT ;
    USE SIGNAL ;
    PORT
      LAYER M5 ;
        RECT  84.432 0 84.456 0.084 ;
    END
  END fdm[306]
  PIN fdm[307]
    DIRECTION OUTPUT ;
    USE SIGNAL ;
    PORT
      LAYER M5 ;
        RECT  84.624 0 84.648 0.084 ;
    END
  END fdm[307]
  PIN fdm[308]
    DIRECTION OUTPUT ;
    USE SIGNAL ;
    PORT
      LAYER M5 ;
        RECT  84.816 0 84.84 0.084 ;
    END
  END fdm[308]
  PIN fdm[309]
    DIRECTION OUTPUT ;
    USE SIGNAL ;
    PORT
      LAYER M5 ;
        RECT  84.96 0 84.984 0.084 ;
    END
  END fdm[309]
  PIN fdm[30]
    DIRECTION OUTPUT ;
    USE SIGNAL ;
    PORT
      LAYER M5 ;
        RECT  135.36 0 135.384 0.084 ;
    END
  END fdm[30]
  PIN fdm[310]
    DIRECTION OUTPUT ;
    USE SIGNAL ;
    PORT
      LAYER M5 ;
        RECT  85.152 0 85.176 0.084 ;
    END
  END fdm[310]
  PIN fdm[311]
    DIRECTION OUTPUT ;
    USE SIGNAL ;
    PORT
      LAYER M5 ;
        RECT  85.344 0 85.368 0.084 ;
    END
  END fdm[311]
  PIN fdm[312]
    DIRECTION OUTPUT ;
    USE SIGNAL ;
    PORT
      LAYER M5 ;
        RECT  85.536 0 85.56 0.084 ;
    END
  END fdm[312]
  PIN fdm[313]
    DIRECTION OUTPUT ;
    USE SIGNAL ;
    PORT
      LAYER M5 ;
        RECT  85.68 0 85.704 0.084 ;
    END
  END fdm[313]
  PIN fdm[314]
    DIRECTION OUTPUT ;
    USE SIGNAL ;
    PORT
      LAYER M5 ;
        RECT  85.872 0 85.896 0.084 ;
    END
  END fdm[314]
  PIN fdm[315]
    DIRECTION OUTPUT ;
    USE SIGNAL ;
    PORT
      LAYER M5 ;
        RECT  86.064 0 86.088 0.084 ;
    END
  END fdm[315]
  PIN fdm[316]
    DIRECTION OUTPUT ;
    USE SIGNAL ;
    PORT
      LAYER M5 ;
        RECT  86.256 0 86.28 0.084 ;
    END
  END fdm[316]
  PIN fdm[317]
    DIRECTION OUTPUT ;
    USE SIGNAL ;
    PORT
      LAYER M5 ;
        RECT  86.4 0 86.424 0.084 ;
    END
  END fdm[317]
  PIN fdm[318]
    DIRECTION OUTPUT ;
    USE SIGNAL ;
    PORT
      LAYER M5 ;
        RECT  86.592 0 86.616 0.084 ;
    END
  END fdm[318]
  PIN fdm[319]
    DIRECTION OUTPUT ;
    USE SIGNAL ;
    PORT
      LAYER M5 ;
        RECT  86.784 0 86.808 0.084 ;
    END
  END fdm[319]
  PIN fdm[31]
    DIRECTION OUTPUT ;
    USE SIGNAL ;
    PORT
      LAYER M5 ;
        RECT  135.552 0 135.576 0.084 ;
    END
  END fdm[31]
  PIN fdm[320]
    DIRECTION OUTPUT ;
    USE SIGNAL ;
    PORT
      LAYER M5 ;
        RECT  86.928 0 86.952 0.084 ;
    END
  END fdm[320]
  PIN fdm[321]
    DIRECTION OUTPUT ;
    USE SIGNAL ;
    PORT
      LAYER M5 ;
        RECT  87.12 0 87.144 0.084 ;
    END
  END fdm[321]
  PIN fdm[322]
    DIRECTION OUTPUT ;
    USE SIGNAL ;
    PORT
      LAYER M5 ;
        RECT  87.312 0 87.336 0.084 ;
    END
  END fdm[322]
  PIN fdm[323]
    DIRECTION OUTPUT ;
    USE SIGNAL ;
    PORT
      LAYER M5 ;
        RECT  87.504 0 87.528 0.084 ;
    END
  END fdm[323]
  PIN fdm[324]
    DIRECTION OUTPUT ;
    USE SIGNAL ;
    PORT
      LAYER M5 ;
        RECT  87.648 0 87.672 0.084 ;
    END
  END fdm[324]
  PIN fdm[325]
    DIRECTION OUTPUT ;
    USE SIGNAL ;
    PORT
      LAYER M5 ;
        RECT  87.84 0 87.864 0.084 ;
    END
  END fdm[325]
  PIN fdm[326]
    DIRECTION OUTPUT ;
    USE SIGNAL ;
    PORT
      LAYER M5 ;
        RECT  88.032 0 88.056 0.084 ;
    END
  END fdm[326]
  PIN fdm[327]
    DIRECTION OUTPUT ;
    USE SIGNAL ;
    PORT
      LAYER M5 ;
        RECT  88.224 0 88.248 0.084 ;
    END
  END fdm[327]
  PIN fdm[328]
    DIRECTION OUTPUT ;
    USE SIGNAL ;
    PORT
      LAYER M5 ;
        RECT  88.368 0 88.392 0.084 ;
    END
  END fdm[328]
  PIN fdm[329]
    DIRECTION OUTPUT ;
    USE SIGNAL ;
    PORT
      LAYER M5 ;
        RECT  88.56 0 88.584 0.084 ;
    END
  END fdm[329]
  PIN fdm[32]
    DIRECTION OUTPUT ;
    USE SIGNAL ;
    PORT
      LAYER M5 ;
        RECT  124.272 0 124.296 0.084 ;
    END
  END fdm[32]
  PIN fdm[330]
    DIRECTION OUTPUT ;
    USE SIGNAL ;
    PORT
      LAYER M5 ;
        RECT  88.752 0 88.776 0.084 ;
    END
  END fdm[330]
  PIN fdm[331]
    DIRECTION OUTPUT ;
    USE SIGNAL ;
    PORT
      LAYER M5 ;
        RECT  88.944 0 88.968 0.084 ;
    END
  END fdm[331]
  PIN fdm[332]
    DIRECTION OUTPUT ;
    USE SIGNAL ;
    PORT
      LAYER M5 ;
        RECT  89.088 0 89.112 0.084 ;
    END
  END fdm[332]
  PIN fdm[333]
    DIRECTION OUTPUT ;
    USE SIGNAL ;
    PORT
      LAYER M5 ;
        RECT  89.28 0 89.304 0.084 ;
    END
  END fdm[333]
  PIN fdm[334]
    DIRECTION OUTPUT ;
    USE SIGNAL ;
    PORT
      LAYER M5 ;
        RECT  89.472 0 89.496 0.084 ;
    END
  END fdm[334]
  PIN fdm[335]
    DIRECTION OUTPUT ;
    USE SIGNAL ;
    PORT
      LAYER M5 ;
        RECT  89.664 0 89.688 0.084 ;
    END
  END fdm[335]
  PIN fdm[336]
    DIRECTION OUTPUT ;
    USE SIGNAL ;
    PORT
      LAYER M5 ;
        RECT  95.568 0 95.592 0.084 ;
    END
  END fdm[336]
  PIN fdm[337]
    DIRECTION OUTPUT ;
    USE SIGNAL ;
    PORT
      LAYER M5 ;
        RECT  95.76 0 95.784 0.084 ;
    END
  END fdm[337]
  PIN fdm[338]
    DIRECTION OUTPUT ;
    USE SIGNAL ;
    PORT
      LAYER M5 ;
        RECT  95.904 0 95.928 0.084 ;
    END
  END fdm[338]
  PIN fdm[339]
    DIRECTION OUTPUT ;
    USE SIGNAL ;
    PORT
      LAYER M5 ;
        RECT  96.096 0 96.12 0.084 ;
    END
  END fdm[339]
  PIN fdm[33]
    DIRECTION OUTPUT ;
    USE SIGNAL ;
    PORT
      LAYER M5 ;
        RECT  124.416 0 124.44 0.084 ;
    END
  END fdm[33]
  PIN fdm[340]
    DIRECTION OUTPUT ;
    USE SIGNAL ;
    PORT
      LAYER M5 ;
        RECT  96.288 0 96.312 0.084 ;
    END
  END fdm[340]
  PIN fdm[341]
    DIRECTION OUTPUT ;
    USE SIGNAL ;
    PORT
      LAYER M5 ;
        RECT  96.48 0 96.504 0.084 ;
    END
  END fdm[341]
  PIN fdm[342]
    DIRECTION OUTPUT ;
    USE SIGNAL ;
    PORT
      LAYER M5 ;
        RECT  96.624 0 96.648 0.084 ;
    END
  END fdm[342]
  PIN fdm[343]
    DIRECTION OUTPUT ;
    USE SIGNAL ;
    PORT
      LAYER M5 ;
        RECT  96.816 0 96.84 0.084 ;
    END
  END fdm[343]
  PIN fdm[344]
    DIRECTION OUTPUT ;
    USE SIGNAL ;
    PORT
      LAYER M5 ;
        RECT  97.008 0 97.032 0.084 ;
    END
  END fdm[344]
  PIN fdm[345]
    DIRECTION OUTPUT ;
    USE SIGNAL ;
    PORT
      LAYER M5 ;
        RECT  97.152 0 97.176 0.084 ;
    END
  END fdm[345]
  PIN fdm[346]
    DIRECTION OUTPUT ;
    USE SIGNAL ;
    PORT
      LAYER M5 ;
        RECT  97.344 0 97.368 0.084 ;
    END
  END fdm[346]
  PIN fdm[347]
    DIRECTION OUTPUT ;
    USE SIGNAL ;
    PORT
      LAYER M5 ;
        RECT  97.536 0 97.56 0.084 ;
    END
  END fdm[347]
  PIN fdm[348]
    DIRECTION OUTPUT ;
    USE SIGNAL ;
    PORT
      LAYER M5 ;
        RECT  97.728 0 97.752 0.084 ;
    END
  END fdm[348]
  PIN fdm[349]
    DIRECTION OUTPUT ;
    USE SIGNAL ;
    PORT
      LAYER M5 ;
        RECT  97.872 0 97.896 0.084 ;
    END
  END fdm[349]
  PIN fdm[34]
    DIRECTION OUTPUT ;
    USE SIGNAL ;
    PORT
      LAYER M5 ;
        RECT  124.608 0 124.632 0.084 ;
    END
  END fdm[34]
  PIN fdm[350]
    DIRECTION OUTPUT ;
    USE SIGNAL ;
    PORT
      LAYER M5 ;
        RECT  98.064 0 98.088 0.084 ;
    END
  END fdm[350]
  PIN fdm[351]
    DIRECTION OUTPUT ;
    USE SIGNAL ;
    PORT
      LAYER M5 ;
        RECT  98.256 0 98.28 0.084 ;
    END
  END fdm[351]
  PIN fdm[352]
    DIRECTION OUTPUT ;
    USE SIGNAL ;
    PORT
      LAYER M5 ;
        RECT  98.448 0 98.472 0.084 ;
    END
  END fdm[352]
  PIN fdm[353]
    DIRECTION OUTPUT ;
    USE SIGNAL ;
    PORT
      LAYER M5 ;
        RECT  98.592 0 98.616 0.084 ;
    END
  END fdm[353]
  PIN fdm[354]
    DIRECTION OUTPUT ;
    USE SIGNAL ;
    PORT
      LAYER M5 ;
        RECT  98.784 0 98.808 0.084 ;
    END
  END fdm[354]
  PIN fdm[355]
    DIRECTION OUTPUT ;
    USE SIGNAL ;
    PORT
      LAYER M5 ;
        RECT  98.976 0 99 0.084 ;
    END
  END fdm[355]
  PIN fdm[356]
    DIRECTION OUTPUT ;
    USE SIGNAL ;
    PORT
      LAYER M5 ;
        RECT  99.168 0 99.192 0.084 ;
    END
  END fdm[356]
  PIN fdm[357]
    DIRECTION OUTPUT ;
    USE SIGNAL ;
    PORT
      LAYER M5 ;
        RECT  99.312 0 99.336 0.084 ;
    END
  END fdm[357]
  PIN fdm[358]
    DIRECTION OUTPUT ;
    USE SIGNAL ;
    PORT
      LAYER M5 ;
        RECT  99.504 0 99.528 0.084 ;
    END
  END fdm[358]
  PIN fdm[359]
    DIRECTION OUTPUT ;
    USE SIGNAL ;
    PORT
      LAYER M5 ;
        RECT  99.696 0 99.72 0.084 ;
    END
  END fdm[359]
  PIN fdm[35]
    DIRECTION OUTPUT ;
    USE SIGNAL ;
    PORT
      LAYER M5 ;
        RECT  124.8 0 124.824 0.084 ;
    END
  END fdm[35]
  PIN fdm[360]
    DIRECTION OUTPUT ;
    USE SIGNAL ;
    PORT
      LAYER M5 ;
        RECT  99.84 0 99.864 0.084 ;
    END
  END fdm[360]
  PIN fdm[361]
    DIRECTION OUTPUT ;
    USE SIGNAL ;
    PORT
      LAYER M5 ;
        RECT  100.032 0 100.056 0.084 ;
    END
  END fdm[361]
  PIN fdm[362]
    DIRECTION OUTPUT ;
    USE SIGNAL ;
    PORT
      LAYER M5 ;
        RECT  100.224 0 100.248 0.084 ;
    END
  END fdm[362]
  PIN fdm[363]
    DIRECTION OUTPUT ;
    USE SIGNAL ;
    PORT
      LAYER M5 ;
        RECT  100.416 0 100.44 0.084 ;
    END
  END fdm[363]
  PIN fdm[364]
    DIRECTION OUTPUT ;
    USE SIGNAL ;
    PORT
      LAYER M5 ;
        RECT  100.56 0 100.584 0.084 ;
    END
  END fdm[364]
  PIN fdm[365]
    DIRECTION OUTPUT ;
    USE SIGNAL ;
    PORT
      LAYER M5 ;
        RECT  100.752 0 100.776 0.084 ;
    END
  END fdm[365]
  PIN fdm[366]
    DIRECTION OUTPUT ;
    USE SIGNAL ;
    PORT
      LAYER M5 ;
        RECT  100.944 0 100.968 0.084 ;
    END
  END fdm[366]
  PIN fdm[367]
    DIRECTION OUTPUT ;
    USE SIGNAL ;
    PORT
      LAYER M5 ;
        RECT  101.136 0 101.16 0.084 ;
    END
  END fdm[367]
  PIN fdm[368]
    DIRECTION OUTPUT ;
    USE SIGNAL ;
    PORT
      LAYER M5 ;
        RECT  43.92 0 43.944 0.084 ;
    END
  END fdm[368]
  PIN fdm[369]
    DIRECTION OUTPUT ;
    USE SIGNAL ;
    PORT
      LAYER M5 ;
        RECT  44.112 0 44.136 0.084 ;
    END
  END fdm[369]
  PIN fdm[36]
    DIRECTION OUTPUT ;
    USE SIGNAL ;
    PORT
      LAYER M5 ;
        RECT  124.992 0 125.016 0.084 ;
    END
  END fdm[36]
  PIN fdm[370]
    DIRECTION OUTPUT ;
    USE SIGNAL ;
    PORT
      LAYER M5 ;
        RECT  44.256 0 44.28 0.084 ;
    END
  END fdm[370]
  PIN fdm[371]
    DIRECTION OUTPUT ;
    USE SIGNAL ;
    PORT
      LAYER M5 ;
        RECT  44.448 0 44.472 0.084 ;
    END
  END fdm[371]
  PIN fdm[372]
    DIRECTION OUTPUT ;
    USE SIGNAL ;
    PORT
      LAYER M5 ;
        RECT  44.64 0 44.664 0.084 ;
    END
  END fdm[372]
  PIN fdm[373]
    DIRECTION OUTPUT ;
    USE SIGNAL ;
    PORT
      LAYER M5 ;
        RECT  44.784 0 44.808 0.084 ;
    END
  END fdm[373]
  PIN fdm[374]
    DIRECTION OUTPUT ;
    USE SIGNAL ;
    PORT
      LAYER M5 ;
        RECT  44.976 0 45 0.084 ;
    END
  END fdm[374]
  PIN fdm[375]
    DIRECTION OUTPUT ;
    USE SIGNAL ;
    PORT
      LAYER M5 ;
        RECT  45.168 0 45.192 0.084 ;
    END
  END fdm[375]
  PIN fdm[376]
    DIRECTION OUTPUT ;
    USE SIGNAL ;
    PORT
      LAYER M5 ;
        RECT  45.36 0 45.384 0.084 ;
    END
  END fdm[376]
  PIN fdm[377]
    DIRECTION OUTPUT ;
    USE SIGNAL ;
    PORT
      LAYER M5 ;
        RECT  45.504 0 45.528 0.084 ;
    END
  END fdm[377]
  PIN fdm[378]
    DIRECTION OUTPUT ;
    USE SIGNAL ;
    PORT
      LAYER M5 ;
        RECT  45.696 0 45.72 0.084 ;
    END
  END fdm[378]
  PIN fdm[379]
    DIRECTION OUTPUT ;
    USE SIGNAL ;
    PORT
      LAYER M5 ;
        RECT  45.888 0 45.912 0.084 ;
    END
  END fdm[379]
  PIN fdm[37]
    DIRECTION OUTPUT ;
    USE SIGNAL ;
    PORT
      LAYER M5 ;
        RECT  125.136 0 125.16 0.084 ;
    END
  END fdm[37]
  PIN fdm[380]
    DIRECTION OUTPUT ;
    USE SIGNAL ;
    PORT
      LAYER M5 ;
        RECT  46.08 0 46.104 0.084 ;
    END
  END fdm[380]
  PIN fdm[381]
    DIRECTION OUTPUT ;
    USE SIGNAL ;
    PORT
      LAYER M5 ;
        RECT  46.224 0 46.248 0.084 ;
    END
  END fdm[381]
  PIN fdm[382]
    DIRECTION OUTPUT ;
    USE SIGNAL ;
    PORT
      LAYER M5 ;
        RECT  46.416 0 46.44 0.084 ;
    END
  END fdm[382]
  PIN fdm[383]
    DIRECTION OUTPUT ;
    USE SIGNAL ;
    PORT
      LAYER M5 ;
        RECT  46.608 0 46.632 0.084 ;
    END
  END fdm[383]
  PIN fdm[384]
    DIRECTION OUTPUT ;
    USE SIGNAL ;
    PORT
      LAYER M5 ;
        RECT  46.8 0 46.824 0.084 ;
    END
  END fdm[384]
  PIN fdm[385]
    DIRECTION OUTPUT ;
    USE SIGNAL ;
    PORT
      LAYER M5 ;
        RECT  46.944 0 46.968 0.084 ;
    END
  END fdm[385]
  PIN fdm[386]
    DIRECTION OUTPUT ;
    USE SIGNAL ;
    PORT
      LAYER M5 ;
        RECT  47.136 0 47.16 0.084 ;
    END
  END fdm[386]
  PIN fdm[387]
    DIRECTION OUTPUT ;
    USE SIGNAL ;
    PORT
      LAYER M5 ;
        RECT  47.328 0 47.352 0.084 ;
    END
  END fdm[387]
  PIN fdm[388]
    DIRECTION OUTPUT ;
    USE SIGNAL ;
    PORT
      LAYER M5 ;
        RECT  47.472 0 47.496 0.084 ;
    END
  END fdm[388]
  PIN fdm[389]
    DIRECTION OUTPUT ;
    USE SIGNAL ;
    PORT
      LAYER M5 ;
        RECT  47.664 0 47.688 0.084 ;
    END
  END fdm[389]
  PIN fdm[38]
    DIRECTION OUTPUT ;
    USE SIGNAL ;
    PORT
      LAYER M5 ;
        RECT  125.328 0 125.352 0.084 ;
    END
  END fdm[38]
  PIN fdm[390]
    DIRECTION OUTPUT ;
    USE SIGNAL ;
    PORT
      LAYER M5 ;
        RECT  47.856 0 47.88 0.084 ;
    END
  END fdm[390]
  PIN fdm[391]
    DIRECTION OUTPUT ;
    USE SIGNAL ;
    PORT
      LAYER M5 ;
        RECT  48.048 0 48.072 0.084 ;
    END
  END fdm[391]
  PIN fdm[392]
    DIRECTION OUTPUT ;
    USE SIGNAL ;
    PORT
      LAYER M5 ;
        RECT  48.192 0 48.216 0.084 ;
    END
  END fdm[392]
  PIN fdm[393]
    DIRECTION OUTPUT ;
    USE SIGNAL ;
    PORT
      LAYER M5 ;
        RECT  48.384 0 48.408 0.084 ;
    END
  END fdm[393]
  PIN fdm[394]
    DIRECTION OUTPUT ;
    USE SIGNAL ;
    PORT
      LAYER M5 ;
        RECT  48.576 0 48.6 0.084 ;
    END
  END fdm[394]
  PIN fdm[395]
    DIRECTION OUTPUT ;
    USE SIGNAL ;
    PORT
      LAYER M5 ;
        RECT  48.768 0 48.792 0.084 ;
    END
  END fdm[395]
  PIN fdm[396]
    DIRECTION OUTPUT ;
    USE SIGNAL ;
    PORT
      LAYER M5 ;
        RECT  48.912 0 48.936 0.084 ;
    END
  END fdm[396]
  PIN fdm[397]
    DIRECTION OUTPUT ;
    USE SIGNAL ;
    PORT
      LAYER M5 ;
        RECT  49.104 0 49.128 0.084 ;
    END
  END fdm[397]
  PIN fdm[398]
    DIRECTION OUTPUT ;
    USE SIGNAL ;
    PORT
      LAYER M5 ;
        RECT  49.296 0 49.32 0.084 ;
    END
  END fdm[398]
  PIN fdm[399]
    DIRECTION OUTPUT ;
    USE SIGNAL ;
    PORT
      LAYER M5 ;
        RECT  49.488 0 49.512 0.084 ;
    END
  END fdm[399]
  PIN fdm[39]
    DIRECTION OUTPUT ;
    USE SIGNAL ;
    PORT
      LAYER M5 ;
        RECT  125.52 0 125.544 0.084 ;
    END
  END fdm[39]
  PIN fdm[3]
    DIRECTION OUTPUT ;
    USE SIGNAL ;
    PORT
      LAYER M5 ;
        RECT  130.512 0 130.536 0.084 ;
    END
  END fdm[3]
  PIN fdm[400]
    DIRECTION OUTPUT ;
    USE SIGNAL ;
    PORT
      LAYER M5 ;
        RECT  49.632 0 49.656 0.084 ;
    END
  END fdm[400]
  PIN fdm[401]
    DIRECTION OUTPUT ;
    USE SIGNAL ;
    PORT
      LAYER M5 ;
        RECT  49.824 0 49.848 0.084 ;
    END
  END fdm[401]
  PIN fdm[402]
    DIRECTION OUTPUT ;
    USE SIGNAL ;
    PORT
      LAYER M5 ;
        RECT  50.016 0 50.04 0.084 ;
    END
  END fdm[402]
  PIN fdm[403]
    DIRECTION OUTPUT ;
    USE SIGNAL ;
    PORT
      LAYER M5 ;
        RECT  50.208 0 50.232 0.084 ;
    END
  END fdm[403]
  PIN fdm[404]
    DIRECTION OUTPUT ;
    USE SIGNAL ;
    PORT
      LAYER M5 ;
        RECT  50.352 0 50.376 0.084 ;
    END
  END fdm[404]
  PIN fdm[405]
    DIRECTION OUTPUT ;
    USE SIGNAL ;
    PORT
      LAYER M5 ;
        RECT  50.544 0 50.568 0.084 ;
    END
  END fdm[405]
  PIN fdm[406]
    DIRECTION OUTPUT ;
    USE SIGNAL ;
    PORT
      LAYER M5 ;
        RECT  50.736 0 50.76 0.084 ;
    END
  END fdm[406]
  PIN fdm[407]
    DIRECTION OUTPUT ;
    USE SIGNAL ;
    PORT
      LAYER M5 ;
        RECT  50.88 0 50.904 0.084 ;
    END
  END fdm[407]
  PIN fdm[408]
    DIRECTION OUTPUT ;
    USE SIGNAL ;
    PORT
      LAYER M5 ;
        RECT  51.072 0 51.096 0.084 ;
    END
  END fdm[408]
  PIN fdm[409]
    DIRECTION OUTPUT ;
    USE SIGNAL ;
    PORT
      LAYER M5 ;
        RECT  51.264 0 51.288 0.084 ;
    END
  END fdm[409]
  PIN fdm[40]
    DIRECTION OUTPUT ;
    USE SIGNAL ;
    PORT
      LAYER M5 ;
        RECT  125.712 0 125.736 0.084 ;
    END
  END fdm[40]
  PIN fdm[410]
    DIRECTION OUTPUT ;
    USE SIGNAL ;
    PORT
      LAYER M5 ;
        RECT  51.456 0 51.48 0.084 ;
    END
  END fdm[410]
  PIN fdm[411]
    DIRECTION OUTPUT ;
    USE SIGNAL ;
    PORT
      LAYER M5 ;
        RECT  51.6 0 51.624 0.084 ;
    END
  END fdm[411]
  PIN fdm[412]
    DIRECTION OUTPUT ;
    USE SIGNAL ;
    PORT
      LAYER M5 ;
        RECT  51.792 0 51.816 0.084 ;
    END
  END fdm[412]
  PIN fdm[413]
    DIRECTION OUTPUT ;
    USE SIGNAL ;
    PORT
      LAYER M5 ;
        RECT  51.984 0 52.008 0.084 ;
    END
  END fdm[413]
  PIN fdm[414]
    DIRECTION OUTPUT ;
    USE SIGNAL ;
    PORT
      LAYER M5 ;
        RECT  52.176 0 52.2 0.084 ;
    END
  END fdm[414]
  PIN fdm[415]
    DIRECTION OUTPUT ;
    USE SIGNAL ;
    PORT
      LAYER M5 ;
        RECT  52.32 0 52.344 0.084 ;
    END
  END fdm[415]
  PIN fdm[416]
    DIRECTION OUTPUT ;
    USE SIGNAL ;
    PORT
      LAYER M5 ;
        RECT  52.512 0 52.536 0.084 ;
    END
  END fdm[416]
  PIN fdm[417]
    DIRECTION OUTPUT ;
    USE SIGNAL ;
    PORT
      LAYER M5 ;
        RECT  52.704 0 52.728 0.084 ;
    END
  END fdm[417]
  PIN fdm[418]
    DIRECTION OUTPUT ;
    USE SIGNAL ;
    PORT
      LAYER M5 ;
        RECT  52.896 0 52.92 0.084 ;
    END
  END fdm[418]
  PIN fdm[419]
    DIRECTION OUTPUT ;
    USE SIGNAL ;
    PORT
      LAYER M5 ;
        RECT  53.04 0 53.064 0.084 ;
    END
  END fdm[419]
  PIN fdm[41]
    DIRECTION OUTPUT ;
    USE SIGNAL ;
    PORT
      LAYER M5 ;
        RECT  125.856 0 125.88 0.084 ;
    END
  END fdm[41]
  PIN fdm[420]
    DIRECTION OUTPUT ;
    USE SIGNAL ;
    PORT
      LAYER M5 ;
        RECT  53.232 0 53.256 0.084 ;
    END
  END fdm[420]
  PIN fdm[421]
    DIRECTION OUTPUT ;
    USE SIGNAL ;
    PORT
      LAYER M5 ;
        RECT  53.424 0 53.448 0.084 ;
    END
  END fdm[421]
  PIN fdm[422]
    DIRECTION OUTPUT ;
    USE SIGNAL ;
    PORT
      LAYER M5 ;
        RECT  53.616 0 53.64 0.084 ;
    END
  END fdm[422]
  PIN fdm[423]
    DIRECTION OUTPUT ;
    USE SIGNAL ;
    PORT
      LAYER M5 ;
        RECT  53.76 0 53.784 0.084 ;
    END
  END fdm[423]
  PIN fdm[424]
    DIRECTION OUTPUT ;
    USE SIGNAL ;
    PORT
      LAYER M5 ;
        RECT  53.952 0 53.976 0.084 ;
    END
  END fdm[424]
  PIN fdm[425]
    DIRECTION OUTPUT ;
    USE SIGNAL ;
    PORT
      LAYER M5 ;
        RECT  54.144 0 54.168 0.084 ;
    END
  END fdm[425]
  PIN fdm[426]
    DIRECTION OUTPUT ;
    USE SIGNAL ;
    PORT
      LAYER M5 ;
        RECT  54.288 0 54.312 0.084 ;
    END
  END fdm[426]
  PIN fdm[427]
    DIRECTION OUTPUT ;
    USE SIGNAL ;
    PORT
      LAYER M5 ;
        RECT  54.48 0 54.504 0.084 ;
    END
  END fdm[427]
  PIN fdm[428]
    DIRECTION OUTPUT ;
    USE SIGNAL ;
    PORT
      LAYER M5 ;
        RECT  54.672 0 54.696 0.084 ;
    END
  END fdm[428]
  PIN fdm[429]
    DIRECTION OUTPUT ;
    USE SIGNAL ;
    PORT
      LAYER M5 ;
        RECT  54.864 0 54.888 0.084 ;
    END
  END fdm[429]
  PIN fdm[42]
    DIRECTION OUTPUT ;
    USE SIGNAL ;
    PORT
      LAYER M5 ;
        RECT  126.048 0 126.072 0.084 ;
    END
  END fdm[42]
  PIN fdm[430]
    DIRECTION OUTPUT ;
    USE SIGNAL ;
    PORT
      LAYER M5 ;
        RECT  55.008 0 55.032 0.084 ;
    END
  END fdm[430]
  PIN fdm[431]
    DIRECTION OUTPUT ;
    USE SIGNAL ;
    PORT
      LAYER M5 ;
        RECT  55.2 0 55.224 0.084 ;
    END
  END fdm[431]
  PIN fdm[432]
    DIRECTION OUTPUT ;
    USE SIGNAL ;
    PORT
      LAYER M5 ;
        RECT  72.624 0 72.648 0.084 ;
    END
  END fdm[432]
  PIN fdm[433]
    DIRECTION OUTPUT ;
    USE SIGNAL ;
    PORT
      LAYER M5 ;
        RECT  72.768 0 72.792 0.084 ;
    END
  END fdm[433]
  PIN fdm[434]
    DIRECTION OUTPUT ;
    USE SIGNAL ;
    PORT
      LAYER M5 ;
        RECT  72.96 0 72.984 0.084 ;
    END
  END fdm[434]
  PIN fdm[435]
    DIRECTION OUTPUT ;
    USE SIGNAL ;
    PORT
      LAYER M5 ;
        RECT  73.152 0 73.176 0.084 ;
    END
  END fdm[435]
  PIN fdm[436]
    DIRECTION OUTPUT ;
    USE SIGNAL ;
    PORT
      LAYER M5 ;
        RECT  73.344 0 73.368 0.084 ;
    END
  END fdm[436]
  PIN fdm[437]
    DIRECTION OUTPUT ;
    USE SIGNAL ;
    PORT
      LAYER M5 ;
        RECT  73.488 0 73.512 0.084 ;
    END
  END fdm[437]
  PIN fdm[438]
    DIRECTION OUTPUT ;
    USE SIGNAL ;
    PORT
      LAYER M5 ;
        RECT  73.68 0 73.704 0.084 ;
    END
  END fdm[438]
  PIN fdm[439]
    DIRECTION OUTPUT ;
    USE SIGNAL ;
    PORT
      LAYER M5 ;
        RECT  73.872 0 73.896 0.084 ;
    END
  END fdm[439]
  PIN fdm[43]
    DIRECTION OUTPUT ;
    USE SIGNAL ;
    PORT
      LAYER M5 ;
        RECT  126.24 0 126.264 0.084 ;
    END
  END fdm[43]
  PIN fdm[440]
    DIRECTION OUTPUT ;
    USE SIGNAL ;
    PORT
      LAYER M5 ;
        RECT  74.016 0 74.04 0.084 ;
    END
  END fdm[440]
  PIN fdm[441]
    DIRECTION OUTPUT ;
    USE SIGNAL ;
    PORT
      LAYER M5 ;
        RECT  74.208 0 74.232 0.084 ;
    END
  END fdm[441]
  PIN fdm[442]
    DIRECTION OUTPUT ;
    USE SIGNAL ;
    PORT
      LAYER M5 ;
        RECT  74.4 0 74.424 0.084 ;
    END
  END fdm[442]
  PIN fdm[443]
    DIRECTION OUTPUT ;
    USE SIGNAL ;
    PORT
      LAYER M5 ;
        RECT  74.592 0 74.616 0.084 ;
    END
  END fdm[443]
  PIN fdm[444]
    DIRECTION OUTPUT ;
    USE SIGNAL ;
    PORT
      LAYER M5 ;
        RECT  74.736 0 74.76 0.084 ;
    END
  END fdm[444]
  PIN fdm[445]
    DIRECTION OUTPUT ;
    USE SIGNAL ;
    PORT
      LAYER M5 ;
        RECT  74.928 0 74.952 0.084 ;
    END
  END fdm[445]
  PIN fdm[446]
    DIRECTION OUTPUT ;
    USE SIGNAL ;
    PORT
      LAYER M5 ;
        RECT  75.12 0 75.144 0.084 ;
    END
  END fdm[446]
  PIN fdm[447]
    DIRECTION OUTPUT ;
    USE SIGNAL ;
    PORT
      LAYER M5 ;
        RECT  75.312 0 75.336 0.084 ;
    END
  END fdm[447]
  PIN fdm[448]
    DIRECTION OUTPUT ;
    USE SIGNAL ;
    PORT
      LAYER M5 ;
        RECT  75.456 0 75.48 0.084 ;
    END
  END fdm[448]
  PIN fdm[449]
    DIRECTION OUTPUT ;
    USE SIGNAL ;
    PORT
      LAYER M5 ;
        RECT  75.648 0 75.672 0.084 ;
    END
  END fdm[449]
  PIN fdm[44]
    DIRECTION OUTPUT ;
    USE SIGNAL ;
    PORT
      LAYER M5 ;
        RECT  126.384 0 126.408 0.084 ;
    END
  END fdm[44]
  PIN fdm[450]
    DIRECTION OUTPUT ;
    USE SIGNAL ;
    PORT
      LAYER M5 ;
        RECT  75.84 0 75.864 0.084 ;
    END
  END fdm[450]
  PIN fdm[451]
    DIRECTION OUTPUT ;
    USE SIGNAL ;
    PORT
      LAYER M5 ;
        RECT  76.032 0 76.056 0.084 ;
    END
  END fdm[451]
  PIN fdm[452]
    DIRECTION OUTPUT ;
    USE SIGNAL ;
    PORT
      LAYER M5 ;
        RECT  76.176 0 76.2 0.084 ;
    END
  END fdm[452]
  PIN fdm[453]
    DIRECTION OUTPUT ;
    USE SIGNAL ;
    PORT
      LAYER M5 ;
        RECT  76.368 0 76.392 0.084 ;
    END
  END fdm[453]
  PIN fdm[454]
    DIRECTION OUTPUT ;
    USE SIGNAL ;
    PORT
      LAYER M5 ;
        RECT  76.56 0 76.584 0.084 ;
    END
  END fdm[454]
  PIN fdm[455]
    DIRECTION OUTPUT ;
    USE SIGNAL ;
    PORT
      LAYER M5 ;
        RECT  76.752 0 76.776 0.084 ;
    END
  END fdm[455]
  PIN fdm[456]
    DIRECTION OUTPUT ;
    USE SIGNAL ;
    PORT
      LAYER M5 ;
        RECT  76.896 0 76.92 0.084 ;
    END
  END fdm[456]
  PIN fdm[457]
    DIRECTION OUTPUT ;
    USE SIGNAL ;
    PORT
      LAYER M5 ;
        RECT  77.088 0 77.112 0.084 ;
    END
  END fdm[457]
  PIN fdm[458]
    DIRECTION OUTPUT ;
    USE SIGNAL ;
    PORT
      LAYER M5 ;
        RECT  77.28 0 77.304 0.084 ;
    END
  END fdm[458]
  PIN fdm[459]
    DIRECTION OUTPUT ;
    USE SIGNAL ;
    PORT
      LAYER M5 ;
        RECT  77.424 0 77.448 0.084 ;
    END
  END fdm[459]
  PIN fdm[45]
    DIRECTION OUTPUT ;
    USE SIGNAL ;
    PORT
      LAYER M5 ;
        RECT  126.576 0 126.6 0.084 ;
    END
  END fdm[45]
  PIN fdm[460]
    DIRECTION OUTPUT ;
    USE SIGNAL ;
    PORT
      LAYER M5 ;
        RECT  77.616 0 77.64 0.084 ;
    END
  END fdm[460]
  PIN fdm[461]
    DIRECTION OUTPUT ;
    USE SIGNAL ;
    PORT
      LAYER M5 ;
        RECT  77.808 0 77.832 0.084 ;
    END
  END fdm[461]
  PIN fdm[462]
    DIRECTION OUTPUT ;
    USE SIGNAL ;
    PORT
      LAYER M5 ;
        RECT  78 0 78.024 0.084 ;
    END
  END fdm[462]
  PIN fdm[463]
    DIRECTION OUTPUT ;
    USE SIGNAL ;
    PORT
      LAYER M5 ;
        RECT  78.144 0 78.168 0.084 ;
    END
  END fdm[463]
  PIN fdm[464]
    DIRECTION OUTPUT ;
    USE SIGNAL ;
    PORT
      LAYER M5 ;
        RECT  61.104 0 61.128 0.084 ;
    END
  END fdm[464]
  PIN fdm[465]
    DIRECTION OUTPUT ;
    USE SIGNAL ;
    PORT
      LAYER M5 ;
        RECT  61.296 0 61.32 0.084 ;
    END
  END fdm[465]
  PIN fdm[466]
    DIRECTION OUTPUT ;
    USE SIGNAL ;
    PORT
      LAYER M5 ;
        RECT  61.488 0 61.512 0.084 ;
    END
  END fdm[466]
  PIN fdm[467]
    DIRECTION OUTPUT ;
    USE SIGNAL ;
    PORT
      LAYER M5 ;
        RECT  61.68 0 61.704 0.084 ;
    END
  END fdm[467]
  PIN fdm[468]
    DIRECTION OUTPUT ;
    USE SIGNAL ;
    PORT
      LAYER M5 ;
        RECT  61.824 0 61.848 0.084 ;
    END
  END fdm[468]
  PIN fdm[469]
    DIRECTION OUTPUT ;
    USE SIGNAL ;
    PORT
      LAYER M5 ;
        RECT  62.016 0 62.04 0.084 ;
    END
  END fdm[469]
  PIN fdm[46]
    DIRECTION OUTPUT ;
    USE SIGNAL ;
    PORT
      LAYER M5 ;
        RECT  126.768 0 126.792 0.084 ;
    END
  END fdm[46]
  PIN fdm[470]
    DIRECTION OUTPUT ;
    USE SIGNAL ;
    PORT
      LAYER M5 ;
        RECT  62.208 0 62.232 0.084 ;
    END
  END fdm[470]
  PIN fdm[471]
    DIRECTION OUTPUT ;
    USE SIGNAL ;
    PORT
      LAYER M5 ;
        RECT  62.4 0 62.424 0.084 ;
    END
  END fdm[471]
  PIN fdm[472]
    DIRECTION OUTPUT ;
    USE SIGNAL ;
    PORT
      LAYER M5 ;
        RECT  62.544 0 62.568 0.084 ;
    END
  END fdm[472]
  PIN fdm[473]
    DIRECTION OUTPUT ;
    USE SIGNAL ;
    PORT
      LAYER M5 ;
        RECT  62.736 0 62.76 0.084 ;
    END
  END fdm[473]
  PIN fdm[474]
    DIRECTION OUTPUT ;
    USE SIGNAL ;
    PORT
      LAYER M5 ;
        RECT  62.928 0 62.952 0.084 ;
    END
  END fdm[474]
  PIN fdm[475]
    DIRECTION OUTPUT ;
    USE SIGNAL ;
    PORT
      LAYER M5 ;
        RECT  63.12 0 63.144 0.084 ;
    END
  END fdm[475]
  PIN fdm[476]
    DIRECTION OUTPUT ;
    USE SIGNAL ;
    PORT
      LAYER M5 ;
        RECT  63.264 0 63.288 0.084 ;
    END
  END fdm[476]
  PIN fdm[477]
    DIRECTION OUTPUT ;
    USE SIGNAL ;
    PORT
      LAYER M5 ;
        RECT  63.456 0 63.48 0.084 ;
    END
  END fdm[477]
  PIN fdm[478]
    DIRECTION OUTPUT ;
    USE SIGNAL ;
    PORT
      LAYER M5 ;
        RECT  63.648 0 63.672 0.084 ;
    END
  END fdm[478]
  PIN fdm[479]
    DIRECTION OUTPUT ;
    USE SIGNAL ;
    PORT
      LAYER M5 ;
        RECT  63.84 0 63.864 0.084 ;
    END
  END fdm[479]
  PIN fdm[47]
    DIRECTION OUTPUT ;
    USE SIGNAL ;
    PORT
      LAYER M5 ;
        RECT  126.96 0 126.984 0.084 ;
    END
  END fdm[47]
  PIN fdm[480]
    DIRECTION OUTPUT ;
    USE SIGNAL ;
    PORT
      LAYER M5 ;
        RECT  63.984 0 64.008 0.084 ;
    END
  END fdm[480]
  PIN fdm[481]
    DIRECTION OUTPUT ;
    USE SIGNAL ;
    PORT
      LAYER M5 ;
        RECT  64.176 0 64.2 0.084 ;
    END
  END fdm[481]
  PIN fdm[482]
    DIRECTION OUTPUT ;
    USE SIGNAL ;
    PORT
      LAYER M5 ;
        RECT  64.368 0 64.392 0.084 ;
    END
  END fdm[482]
  PIN fdm[483]
    DIRECTION OUTPUT ;
    USE SIGNAL ;
    PORT
      LAYER M5 ;
        RECT  64.512 0 64.536 0.084 ;
    END
  END fdm[483]
  PIN fdm[484]
    DIRECTION OUTPUT ;
    USE SIGNAL ;
    PORT
      LAYER M5 ;
        RECT  64.704 0 64.728 0.084 ;
    END
  END fdm[484]
  PIN fdm[485]
    DIRECTION OUTPUT ;
    USE SIGNAL ;
    PORT
      LAYER M5 ;
        RECT  64.896 0 64.92 0.084 ;
    END
  END fdm[485]
  PIN fdm[486]
    DIRECTION OUTPUT ;
    USE SIGNAL ;
    PORT
      LAYER M5 ;
        RECT  65.088 0 65.112 0.084 ;
    END
  END fdm[486]
  PIN fdm[487]
    DIRECTION OUTPUT ;
    USE SIGNAL ;
    PORT
      LAYER M5 ;
        RECT  65.232 0 65.256 0.084 ;
    END
  END fdm[487]
  PIN fdm[488]
    DIRECTION OUTPUT ;
    USE SIGNAL ;
    PORT
      LAYER M5 ;
        RECT  65.424 0 65.448 0.084 ;
    END
  END fdm[488]
  PIN fdm[489]
    DIRECTION OUTPUT ;
    USE SIGNAL ;
    PORT
      LAYER M5 ;
        RECT  65.616 0 65.64 0.084 ;
    END
  END fdm[489]
  PIN fdm[48]
    DIRECTION OUTPUT ;
    USE SIGNAL ;
    PORT
      LAYER M5 ;
        RECT  127.104 0 127.128 0.084 ;
    END
  END fdm[48]
  PIN fdm[490]
    DIRECTION OUTPUT ;
    USE SIGNAL ;
    PORT
      LAYER M5 ;
        RECT  65.808 0 65.832 0.084 ;
    END
  END fdm[490]
  PIN fdm[491]
    DIRECTION OUTPUT ;
    USE SIGNAL ;
    PORT
      LAYER M5 ;
        RECT  65.952 0 65.976 0.084 ;
    END
  END fdm[491]
  PIN fdm[492]
    DIRECTION OUTPUT ;
    USE SIGNAL ;
    PORT
      LAYER M5 ;
        RECT  66.144 0 66.168 0.084 ;
    END
  END fdm[492]
  PIN fdm[493]
    DIRECTION OUTPUT ;
    USE SIGNAL ;
    PORT
      LAYER M5 ;
        RECT  66.336 0 66.36 0.084 ;
    END
  END fdm[493]
  PIN fdm[494]
    DIRECTION OUTPUT ;
    USE SIGNAL ;
    PORT
      LAYER M5 ;
        RECT  66.528 0 66.552 0.084 ;
    END
  END fdm[494]
  PIN fdm[495]
    DIRECTION OUTPUT ;
    USE SIGNAL ;
    PORT
      LAYER M5 ;
        RECT  66.672 0 66.696 0.084 ;
    END
  END fdm[495]
  PIN fdm[496]
    DIRECTION OUTPUT ;
    USE SIGNAL ;
    PORT
      LAYER M5 ;
        RECT  55.392 0 55.416 0.084 ;
    END
  END fdm[496]
  PIN fdm[497]
    DIRECTION OUTPUT ;
    USE SIGNAL ;
    PORT
      LAYER M5 ;
        RECT  55.584 0 55.608 0.084 ;
    END
  END fdm[497]
  PIN fdm[498]
    DIRECTION OUTPUT ;
    USE SIGNAL ;
    PORT
      LAYER M5 ;
        RECT  55.728 0 55.752 0.084 ;
    END
  END fdm[498]
  PIN fdm[499]
    DIRECTION OUTPUT ;
    USE SIGNAL ;
    PORT
      LAYER M5 ;
        RECT  55.92 0 55.944 0.084 ;
    END
  END fdm[499]
  PIN fdm[49]
    DIRECTION OUTPUT ;
    USE SIGNAL ;
    PORT
      LAYER M5 ;
        RECT  127.296 0 127.32 0.084 ;
    END
  END fdm[49]
  PIN fdm[4]
    DIRECTION OUTPUT ;
    USE SIGNAL ;
    PORT
      LAYER M5 ;
        RECT  130.704 0 130.728 0.084 ;
    END
  END fdm[4]
  PIN fdm[500]
    DIRECTION OUTPUT ;
    USE SIGNAL ;
    PORT
      LAYER M5 ;
        RECT  56.112 0 56.136 0.084 ;
    END
  END fdm[500]
  PIN fdm[501]
    DIRECTION OUTPUT ;
    USE SIGNAL ;
    PORT
      LAYER M5 ;
        RECT  56.304 0 56.328 0.084 ;
    END
  END fdm[501]
  PIN fdm[502]
    DIRECTION OUTPUT ;
    USE SIGNAL ;
    PORT
      LAYER M5 ;
        RECT  56.448 0 56.472 0.084 ;
    END
  END fdm[502]
  PIN fdm[503]
    DIRECTION OUTPUT ;
    USE SIGNAL ;
    PORT
      LAYER M5 ;
        RECT  56.64 0 56.664 0.084 ;
    END
  END fdm[503]
  PIN fdm[504]
    DIRECTION OUTPUT ;
    USE SIGNAL ;
    PORT
      LAYER M5 ;
        RECT  56.832 0 56.856 0.084 ;
    END
  END fdm[504]
  PIN fdm[505]
    DIRECTION OUTPUT ;
    USE SIGNAL ;
    PORT
      LAYER M5 ;
        RECT  57.024 0 57.048 0.084 ;
    END
  END fdm[505]
  PIN fdm[506]
    DIRECTION OUTPUT ;
    USE SIGNAL ;
    PORT
      LAYER M5 ;
        RECT  57.168 0 57.192 0.084 ;
    END
  END fdm[506]
  PIN fdm[507]
    DIRECTION OUTPUT ;
    USE SIGNAL ;
    PORT
      LAYER M5 ;
        RECT  57.36 0 57.384 0.084 ;
    END
  END fdm[507]
  PIN fdm[508]
    DIRECTION OUTPUT ;
    USE SIGNAL ;
    PORT
      LAYER M5 ;
        RECT  57.552 0 57.576 0.084 ;
    END
  END fdm[508]
  PIN fdm[509]
    DIRECTION OUTPUT ;
    USE SIGNAL ;
    PORT
      LAYER M5 ;
        RECT  57.696 0 57.72 0.084 ;
    END
  END fdm[509]
  PIN fdm[50]
    DIRECTION OUTPUT ;
    USE SIGNAL ;
    PORT
      LAYER M5 ;
        RECT  127.488 0 127.512 0.084 ;
    END
  END fdm[50]
  PIN fdm[510]
    DIRECTION OUTPUT ;
    USE SIGNAL ;
    PORT
      LAYER M5 ;
        RECT  57.888 0 57.912 0.084 ;
    END
  END fdm[510]
  PIN fdm[511]
    DIRECTION OUTPUT ;
    USE SIGNAL ;
    PORT
      LAYER M5 ;
        RECT  58.08 0 58.104 0.084 ;
    END
  END fdm[511]
  PIN fdm[512]
    DIRECTION OUTPUT ;
    USE SIGNAL ;
    PORT
      LAYER M5 ;
        RECT  58.272 0 58.296 0.084 ;
    END
  END fdm[512]
  PIN fdm[513]
    DIRECTION OUTPUT ;
    USE SIGNAL ;
    PORT
      LAYER M5 ;
        RECT  58.416 0 58.44 0.084 ;
    END
  END fdm[513]
  PIN fdm[514]
    DIRECTION OUTPUT ;
    USE SIGNAL ;
    PORT
      LAYER M5 ;
        RECT  58.608 0 58.632 0.084 ;
    END
  END fdm[514]
  PIN fdm[515]
    DIRECTION OUTPUT ;
    USE SIGNAL ;
    PORT
      LAYER M5 ;
        RECT  58.8 0 58.824 0.084 ;
    END
  END fdm[515]
  PIN fdm[516]
    DIRECTION OUTPUT ;
    USE SIGNAL ;
    PORT
      LAYER M5 ;
        RECT  58.992 0 59.016 0.084 ;
    END
  END fdm[516]
  PIN fdm[517]
    DIRECTION OUTPUT ;
    USE SIGNAL ;
    PORT
      LAYER M5 ;
        RECT  59.136 0 59.16 0.084 ;
    END
  END fdm[517]
  PIN fdm[518]
    DIRECTION OUTPUT ;
    USE SIGNAL ;
    PORT
      LAYER M5 ;
        RECT  59.328 0 59.352 0.084 ;
    END
  END fdm[518]
  PIN fdm[519]
    DIRECTION OUTPUT ;
    USE SIGNAL ;
    PORT
      LAYER M5 ;
        RECT  59.52 0 59.544 0.084 ;
    END
  END fdm[519]
  PIN fdm[51]
    DIRECTION OUTPUT ;
    USE SIGNAL ;
    PORT
      LAYER M5 ;
        RECT  127.68 0 127.704 0.084 ;
    END
  END fdm[51]
  PIN fdm[520]
    DIRECTION OUTPUT ;
    USE SIGNAL ;
    PORT
      LAYER M5 ;
        RECT  59.712 0 59.736 0.084 ;
    END
  END fdm[520]
  PIN fdm[521]
    DIRECTION OUTPUT ;
    USE SIGNAL ;
    PORT
      LAYER M5 ;
        RECT  59.856 0 59.88 0.084 ;
    END
  END fdm[521]
  PIN fdm[522]
    DIRECTION OUTPUT ;
    USE SIGNAL ;
    PORT
      LAYER M5 ;
        RECT  60.048 0 60.072 0.084 ;
    END
  END fdm[522]
  PIN fdm[523]
    DIRECTION OUTPUT ;
    USE SIGNAL ;
    PORT
      LAYER M5 ;
        RECT  60.24 0 60.264 0.084 ;
    END
  END fdm[523]
  PIN fdm[524]
    DIRECTION OUTPUT ;
    USE SIGNAL ;
    PORT
      LAYER M5 ;
        RECT  60.432 0 60.456 0.084 ;
    END
  END fdm[524]
  PIN fdm[525]
    DIRECTION OUTPUT ;
    USE SIGNAL ;
    PORT
      LAYER M5 ;
        RECT  60.576 0 60.6 0.084 ;
    END
  END fdm[525]
  PIN fdm[526]
    DIRECTION OUTPUT ;
    USE SIGNAL ;
    PORT
      LAYER M5 ;
        RECT  60.768 0 60.792 0.084 ;
    END
  END fdm[526]
  PIN fdm[527]
    DIRECTION OUTPUT ;
    USE SIGNAL ;
    PORT
      LAYER M5 ;
        RECT  60.96 0 60.984 0.084 ;
    END
  END fdm[527]
  PIN fdm[528]
    DIRECTION OUTPUT ;
    USE SIGNAL ;
    PORT
      LAYER M5 ;
        RECT  66.864 0 66.888 0.084 ;
    END
  END fdm[528]
  PIN fdm[529]
    DIRECTION OUTPUT ;
    USE SIGNAL ;
    PORT
      LAYER M5 ;
        RECT  67.056 0 67.08 0.084 ;
    END
  END fdm[529]
  PIN fdm[52]
    DIRECTION OUTPUT ;
    USE SIGNAL ;
    PORT
      LAYER M5 ;
        RECT  127.824 0 127.848 0.084 ;
    END
  END fdm[52]
  PIN fdm[530]
    DIRECTION OUTPUT ;
    USE SIGNAL ;
    PORT
      LAYER M5 ;
        RECT  67.2 0 67.224 0.084 ;
    END
  END fdm[530]
  PIN fdm[531]
    DIRECTION OUTPUT ;
    USE SIGNAL ;
    PORT
      LAYER M5 ;
        RECT  67.392 0 67.416 0.084 ;
    END
  END fdm[531]
  PIN fdm[532]
    DIRECTION OUTPUT ;
    USE SIGNAL ;
    PORT
      LAYER M5 ;
        RECT  67.584 0 67.608 0.084 ;
    END
  END fdm[532]
  PIN fdm[533]
    DIRECTION OUTPUT ;
    USE SIGNAL ;
    PORT
      LAYER M5 ;
        RECT  67.776 0 67.8 0.084 ;
    END
  END fdm[533]
  PIN fdm[534]
    DIRECTION OUTPUT ;
    USE SIGNAL ;
    PORT
      LAYER M5 ;
        RECT  67.92 0 67.944 0.084 ;
    END
  END fdm[534]
  PIN fdm[535]
    DIRECTION OUTPUT ;
    USE SIGNAL ;
    PORT
      LAYER M5 ;
        RECT  68.112 0 68.136 0.084 ;
    END
  END fdm[535]
  PIN fdm[536]
    DIRECTION OUTPUT ;
    USE SIGNAL ;
    PORT
      LAYER M5 ;
        RECT  68.304 0 68.328 0.084 ;
    END
  END fdm[536]
  PIN fdm[537]
    DIRECTION OUTPUT ;
    USE SIGNAL ;
    PORT
      LAYER M5 ;
        RECT  68.496 0 68.52 0.084 ;
    END
  END fdm[537]
  PIN fdm[538]
    DIRECTION OUTPUT ;
    USE SIGNAL ;
    PORT
      LAYER M5 ;
        RECT  68.64 0 68.664 0.084 ;
    END
  END fdm[538]
  PIN fdm[539]
    DIRECTION OUTPUT ;
    USE SIGNAL ;
    PORT
      LAYER M5 ;
        RECT  68.832 0 68.856 0.084 ;
    END
  END fdm[539]
  PIN fdm[53]
    DIRECTION OUTPUT ;
    USE SIGNAL ;
    PORT
      LAYER M5 ;
        RECT  128.016 0 128.04 0.084 ;
    END
  END fdm[53]
  PIN fdm[540]
    DIRECTION OUTPUT ;
    USE SIGNAL ;
    PORT
      LAYER M5 ;
        RECT  69.024 0 69.048 0.084 ;
    END
  END fdm[540]
  PIN fdm[541]
    DIRECTION OUTPUT ;
    USE SIGNAL ;
    PORT
      LAYER M5 ;
        RECT  69.216 0 69.24 0.084 ;
    END
  END fdm[541]
  PIN fdm[542]
    DIRECTION OUTPUT ;
    USE SIGNAL ;
    PORT
      LAYER M5 ;
        RECT  69.36 0 69.384 0.084 ;
    END
  END fdm[542]
  PIN fdm[543]
    DIRECTION OUTPUT ;
    USE SIGNAL ;
    PORT
      LAYER M5 ;
        RECT  69.552 0 69.576 0.084 ;
    END
  END fdm[543]
  PIN fdm[544]
    DIRECTION OUTPUT ;
    USE SIGNAL ;
    PORT
      LAYER M5 ;
        RECT  69.744 0 69.768 0.084 ;
    END
  END fdm[544]
  PIN fdm[545]
    DIRECTION OUTPUT ;
    USE SIGNAL ;
    PORT
      LAYER M5 ;
        RECT  69.936 0 69.96 0.084 ;
    END
  END fdm[545]
  PIN fdm[546]
    DIRECTION OUTPUT ;
    USE SIGNAL ;
    PORT
      LAYER M5 ;
        RECT  70.08 0 70.104 0.084 ;
    END
  END fdm[546]
  PIN fdm[547]
    DIRECTION OUTPUT ;
    USE SIGNAL ;
    PORT
      LAYER M5 ;
        RECT  70.272 0 70.296 0.084 ;
    END
  END fdm[547]
  PIN fdm[548]
    DIRECTION OUTPUT ;
    USE SIGNAL ;
    PORT
      LAYER M5 ;
        RECT  70.464 0 70.488 0.084 ;
    END
  END fdm[548]
  PIN fdm[549]
    DIRECTION OUTPUT ;
    USE SIGNAL ;
    PORT
      LAYER M5 ;
        RECT  70.608 0 70.632 0.084 ;
    END
  END fdm[549]
  PIN fdm[54]
    DIRECTION OUTPUT ;
    USE SIGNAL ;
    PORT
      LAYER M5 ;
        RECT  128.208 0 128.232 0.084 ;
    END
  END fdm[54]
  PIN fdm[550]
    DIRECTION OUTPUT ;
    USE SIGNAL ;
    PORT
      LAYER M5 ;
        RECT  70.8 0 70.824 0.084 ;
    END
  END fdm[550]
  PIN fdm[551]
    DIRECTION OUTPUT ;
    USE SIGNAL ;
    PORT
      LAYER M5 ;
        RECT  70.992 0 71.016 0.084 ;
    END
  END fdm[551]
  PIN fdm[552]
    DIRECTION OUTPUT ;
    USE SIGNAL ;
    PORT
      LAYER M5 ;
        RECT  71.184 0 71.208 0.084 ;
    END
  END fdm[552]
  PIN fdm[553]
    DIRECTION OUTPUT ;
    USE SIGNAL ;
    PORT
      LAYER M5 ;
        RECT  71.328 0 71.352 0.084 ;
    END
  END fdm[553]
  PIN fdm[554]
    DIRECTION OUTPUT ;
    USE SIGNAL ;
    PORT
      LAYER M5 ;
        RECT  71.52 0 71.544 0.084 ;
    END
  END fdm[554]
  PIN fdm[555]
    DIRECTION OUTPUT ;
    USE SIGNAL ;
    PORT
      LAYER M5 ;
        RECT  71.712 0 71.736 0.084 ;
    END
  END fdm[555]
  PIN fdm[556]
    DIRECTION OUTPUT ;
    USE SIGNAL ;
    PORT
      LAYER M5 ;
        RECT  71.904 0 71.928 0.084 ;
    END
  END fdm[556]
  PIN fdm[557]
    DIRECTION OUTPUT ;
    USE SIGNAL ;
    PORT
      LAYER M5 ;
        RECT  72.048 0 72.072 0.084 ;
    END
  END fdm[557]
  PIN fdm[558]
    DIRECTION OUTPUT ;
    USE SIGNAL ;
    PORT
      LAYER M5 ;
        RECT  72.24 0 72.264 0.084 ;
    END
  END fdm[558]
  PIN fdm[559]
    DIRECTION OUTPUT ;
    USE SIGNAL ;
    PORT
      LAYER M5 ;
        RECT  72.432 0 72.456 0.084 ;
    END
  END fdm[559]
  PIN fdm[55]
    DIRECTION OUTPUT ;
    USE SIGNAL ;
    PORT
      LAYER M5 ;
        RECT  128.4 0 128.424 0.084 ;
    END
  END fdm[55]
  PIN fdm[560]
    DIRECTION OUTPUT ;
    USE SIGNAL ;
    PORT
      LAYER M5 ;
        RECT  38.16 0 38.184 0.084 ;
    END
  END fdm[560]
  PIN fdm[561]
    DIRECTION OUTPUT ;
    USE SIGNAL ;
    PORT
      LAYER M5 ;
        RECT  38.352 0 38.376 0.084 ;
    END
  END fdm[561]
  PIN fdm[562]
    DIRECTION OUTPUT ;
    USE SIGNAL ;
    PORT
      LAYER M5 ;
        RECT  38.544 0 38.568 0.084 ;
    END
  END fdm[562]
  PIN fdm[563]
    DIRECTION OUTPUT ;
    USE SIGNAL ;
    PORT
      LAYER M5 ;
        RECT  38.688 0 38.712 0.084 ;
    END
  END fdm[563]
  PIN fdm[564]
    DIRECTION OUTPUT ;
    USE SIGNAL ;
    PORT
      LAYER M5 ;
        RECT  38.88 0 38.904 0.084 ;
    END
  END fdm[564]
  PIN fdm[565]
    DIRECTION OUTPUT ;
    USE SIGNAL ;
    PORT
      LAYER M5 ;
        RECT  39.072 0 39.096 0.084 ;
    END
  END fdm[565]
  PIN fdm[566]
    DIRECTION OUTPUT ;
    USE SIGNAL ;
    PORT
      LAYER M5 ;
        RECT  39.264 0 39.288 0.084 ;
    END
  END fdm[566]
  PIN fdm[567]
    DIRECTION OUTPUT ;
    USE SIGNAL ;
    PORT
      LAYER M5 ;
        RECT  39.408 0 39.432 0.084 ;
    END
  END fdm[567]
  PIN fdm[568]
    DIRECTION OUTPUT ;
    USE SIGNAL ;
    PORT
      LAYER M5 ;
        RECT  39.6 0 39.624 0.084 ;
    END
  END fdm[568]
  PIN fdm[569]
    DIRECTION OUTPUT ;
    USE SIGNAL ;
    PORT
      LAYER M5 ;
        RECT  39.792 0 39.816 0.084 ;
    END
  END fdm[569]
  PIN fdm[56]
    DIRECTION OUTPUT ;
    USE SIGNAL ;
    PORT
      LAYER M5 ;
        RECT  128.544 0 128.568 0.084 ;
    END
  END fdm[56]
  PIN fdm[570]
    DIRECTION OUTPUT ;
    USE SIGNAL ;
    PORT
      LAYER M5 ;
        RECT  39.984 0 40.008 0.084 ;
    END
  END fdm[570]
  PIN fdm[571]
    DIRECTION OUTPUT ;
    USE SIGNAL ;
    PORT
      LAYER M5 ;
        RECT  40.128 0 40.152 0.084 ;
    END
  END fdm[571]
  PIN fdm[572]
    DIRECTION OUTPUT ;
    USE SIGNAL ;
    PORT
      LAYER M5 ;
        RECT  40.32 0 40.344 0.084 ;
    END
  END fdm[572]
  PIN fdm[573]
    DIRECTION OUTPUT ;
    USE SIGNAL ;
    PORT
      LAYER M5 ;
        RECT  40.512 0 40.536 0.084 ;
    END
  END fdm[573]
  PIN fdm[574]
    DIRECTION OUTPUT ;
    USE SIGNAL ;
    PORT
      LAYER M5 ;
        RECT  40.704 0 40.728 0.084 ;
    END
  END fdm[574]
  PIN fdm[575]
    DIRECTION OUTPUT ;
    USE SIGNAL ;
    PORT
      LAYER M5 ;
        RECT  40.848 0 40.872 0.084 ;
    END
  END fdm[575]
  PIN fdm[576]
    DIRECTION OUTPUT ;
    USE SIGNAL ;
    PORT
      LAYER M5 ;
        RECT  41.04 0 41.064 0.084 ;
    END
  END fdm[576]
  PIN fdm[577]
    DIRECTION OUTPUT ;
    USE SIGNAL ;
    PORT
      LAYER M5 ;
        RECT  41.232 0 41.256 0.084 ;
    END
  END fdm[577]
  PIN fdm[578]
    DIRECTION OUTPUT ;
    USE SIGNAL ;
    PORT
      LAYER M5 ;
        RECT  41.376 0 41.4 0.084 ;
    END
  END fdm[578]
  PIN fdm[579]
    DIRECTION OUTPUT ;
    USE SIGNAL ;
    PORT
      LAYER M5 ;
        RECT  41.568 0 41.592 0.084 ;
    END
  END fdm[579]
  PIN fdm[57]
    DIRECTION OUTPUT ;
    USE SIGNAL ;
    PORT
      LAYER M5 ;
        RECT  128.736 0 128.76 0.084 ;
    END
  END fdm[57]
  PIN fdm[580]
    DIRECTION OUTPUT ;
    USE SIGNAL ;
    PORT
      LAYER M5 ;
        RECT  41.76 0 41.784 0.084 ;
    END
  END fdm[580]
  PIN fdm[581]
    DIRECTION OUTPUT ;
    USE SIGNAL ;
    PORT
      LAYER M5 ;
        RECT  41.952 0 41.976 0.084 ;
    END
  END fdm[581]
  PIN fdm[582]
    DIRECTION OUTPUT ;
    USE SIGNAL ;
    PORT
      LAYER M5 ;
        RECT  42.096 0 42.12 0.084 ;
    END
  END fdm[582]
  PIN fdm[583]
    DIRECTION OUTPUT ;
    USE SIGNAL ;
    PORT
      LAYER M5 ;
        RECT  42.288 0 42.312 0.084 ;
    END
  END fdm[583]
  PIN fdm[584]
    DIRECTION OUTPUT ;
    USE SIGNAL ;
    PORT
      LAYER M5 ;
        RECT  42.48 0 42.504 0.084 ;
    END
  END fdm[584]
  PIN fdm[585]
    DIRECTION OUTPUT ;
    USE SIGNAL ;
    PORT
      LAYER M5 ;
        RECT  42.672 0 42.696 0.084 ;
    END
  END fdm[585]
  PIN fdm[586]
    DIRECTION OUTPUT ;
    USE SIGNAL ;
    PORT
      LAYER M5 ;
        RECT  42.816 0 42.84 0.084 ;
    END
  END fdm[586]
  PIN fdm[587]
    DIRECTION OUTPUT ;
    USE SIGNAL ;
    PORT
      LAYER M5 ;
        RECT  43.008 0 43.032 0.084 ;
    END
  END fdm[587]
  PIN fdm[588]
    DIRECTION OUTPUT ;
    USE SIGNAL ;
    PORT
      LAYER M5 ;
        RECT  43.2 0 43.224 0.084 ;
    END
  END fdm[588]
  PIN fdm[589]
    DIRECTION OUTPUT ;
    USE SIGNAL ;
    PORT
      LAYER M5 ;
        RECT  43.392 0 43.416 0.084 ;
    END
  END fdm[589]
  PIN fdm[58]
    DIRECTION OUTPUT ;
    USE SIGNAL ;
    PORT
      LAYER M5 ;
        RECT  128.928 0 128.952 0.084 ;
    END
  END fdm[58]
  PIN fdm[590]
    DIRECTION OUTPUT ;
    USE SIGNAL ;
    PORT
      LAYER M5 ;
        RECT  43.536 0 43.56 0.084 ;
    END
  END fdm[590]
  PIN fdm[591]
    DIRECTION OUTPUT ;
    USE SIGNAL ;
    PORT
      LAYER M5 ;
        RECT  43.728 0 43.752 0.084 ;
    END
  END fdm[591]
  PIN fdm[592]
    DIRECTION OUTPUT ;
    USE SIGNAL ;
    PORT
      LAYER M5 ;
        RECT  37.968 0 37.992 0.084 ;
    END
  END fdm[592]
  PIN fdm[593]
    DIRECTION OUTPUT ;
    USE SIGNAL ;
    PORT
      LAYER M5 ;
        RECT  37.824 0 37.848 0.084 ;
    END
  END fdm[593]
  PIN fdm[594]
    DIRECTION OUTPUT ;
    USE SIGNAL ;
    PORT
      LAYER M5 ;
        RECT  37.632 0 37.656 0.084 ;
    END
  END fdm[594]
  PIN fdm[595]
    DIRECTION OUTPUT ;
    USE SIGNAL ;
    PORT
      LAYER M5 ;
        RECT  37.44 0 37.464 0.084 ;
    END
  END fdm[595]
  PIN fdm[596]
    DIRECTION OUTPUT ;
    USE SIGNAL ;
    PORT
      LAYER M5 ;
        RECT  37.296 0 37.32 0.084 ;
    END
  END fdm[596]
  PIN fdm[597]
    DIRECTION OUTPUT ;
    USE SIGNAL ;
    PORT
      LAYER M5 ;
        RECT  37.104 0 37.128 0.084 ;
    END
  END fdm[597]
  PIN fdm[598]
    DIRECTION OUTPUT ;
    USE SIGNAL ;
    PORT
      LAYER M5 ;
        RECT  36.912 0 36.936 0.084 ;
    END
  END fdm[598]
  PIN fdm[599]
    DIRECTION OUTPUT ;
    USE SIGNAL ;
    PORT
      LAYER M5 ;
        RECT  36.72 0 36.744 0.084 ;
    END
  END fdm[599]
  PIN fdm[59]
    DIRECTION OUTPUT ;
    USE SIGNAL ;
    PORT
      LAYER M5 ;
        RECT  129.12 0 129.144 0.084 ;
    END
  END fdm[59]
  PIN fdm[5]
    DIRECTION OUTPUT ;
    USE SIGNAL ;
    PORT
      LAYER M5 ;
        RECT  130.896 0 130.92 0.084 ;
    END
  END fdm[5]
  PIN fdm[600]
    DIRECTION OUTPUT ;
    USE SIGNAL ;
    PORT
      LAYER M5 ;
        RECT  36.576 0 36.6 0.084 ;
    END
  END fdm[600]
  PIN fdm[601]
    DIRECTION OUTPUT ;
    USE SIGNAL ;
    PORT
      LAYER M5 ;
        RECT  36.384 0 36.408 0.084 ;
    END
  END fdm[601]
  PIN fdm[602]
    DIRECTION OUTPUT ;
    USE SIGNAL ;
    PORT
      LAYER M5 ;
        RECT  36.192 0 36.216 0.084 ;
    END
  END fdm[602]
  PIN fdm[603]
    DIRECTION OUTPUT ;
    USE SIGNAL ;
    PORT
      LAYER M5 ;
        RECT  36 0 36.024 0.084 ;
    END
  END fdm[603]
  PIN fdm[604]
    DIRECTION OUTPUT ;
    USE SIGNAL ;
    PORT
      LAYER M5 ;
        RECT  35.856 0 35.88 0.084 ;
    END
  END fdm[604]
  PIN fdm[605]
    DIRECTION OUTPUT ;
    USE SIGNAL ;
    PORT
      LAYER M5 ;
        RECT  35.664 0 35.688 0.084 ;
    END
  END fdm[605]
  PIN fdm[606]
    DIRECTION OUTPUT ;
    USE SIGNAL ;
    PORT
      LAYER M5 ;
        RECT  35.472 0 35.496 0.084 ;
    END
  END fdm[606]
  PIN fdm[607]
    DIRECTION OUTPUT ;
    USE SIGNAL ;
    PORT
      LAYER M5 ;
        RECT  35.28 0 35.304 0.084 ;
    END
  END fdm[607]
  PIN fdm[608]
    DIRECTION OUTPUT ;
    USE SIGNAL ;
    PORT
      LAYER M5 ;
        RECT  35.136 0 35.16 0.084 ;
    END
  END fdm[608]
  PIN fdm[609]
    DIRECTION OUTPUT ;
    USE SIGNAL ;
    PORT
      LAYER M5 ;
        RECT  34.944 0 34.968 0.084 ;
    END
  END fdm[609]
  PIN fdm[60]
    DIRECTION OUTPUT ;
    USE SIGNAL ;
    PORT
      LAYER M5 ;
        RECT  129.264 0 129.288 0.084 ;
    END
  END fdm[60]
  PIN fdm[610]
    DIRECTION OUTPUT ;
    USE SIGNAL ;
    PORT
      LAYER M5 ;
        RECT  34.752 0 34.776 0.084 ;
    END
  END fdm[610]
  PIN fdm[611]
    DIRECTION OUTPUT ;
    USE SIGNAL ;
    PORT
      LAYER M5 ;
        RECT  34.56 0 34.584 0.084 ;
    END
  END fdm[611]
  PIN fdm[612]
    DIRECTION OUTPUT ;
    USE SIGNAL ;
    PORT
      LAYER M5 ;
        RECT  34.416 0 34.44 0.084 ;
    END
  END fdm[612]
  PIN fdm[613]
    DIRECTION OUTPUT ;
    USE SIGNAL ;
    PORT
      LAYER M5 ;
        RECT  34.224 0 34.248 0.084 ;
    END
  END fdm[613]
  PIN fdm[614]
    DIRECTION OUTPUT ;
    USE SIGNAL ;
    PORT
      LAYER M5 ;
        RECT  34.032 0 34.056 0.084 ;
    END
  END fdm[614]
  PIN fdm[615]
    DIRECTION OUTPUT ;
    USE SIGNAL ;
    PORT
      LAYER M5 ;
        RECT  33.888 0 33.912 0.084 ;
    END
  END fdm[615]
  PIN fdm[616]
    DIRECTION OUTPUT ;
    USE SIGNAL ;
    PORT
      LAYER M5 ;
        RECT  33.696 0 33.72 0.084 ;
    END
  END fdm[616]
  PIN fdm[617]
    DIRECTION OUTPUT ;
    USE SIGNAL ;
    PORT
      LAYER M5 ;
        RECT  33.504 0 33.528 0.084 ;
    END
  END fdm[617]
  PIN fdm[618]
    DIRECTION OUTPUT ;
    USE SIGNAL ;
    PORT
      LAYER M5 ;
        RECT  33.312 0 33.336 0.084 ;
    END
  END fdm[618]
  PIN fdm[619]
    DIRECTION OUTPUT ;
    USE SIGNAL ;
    PORT
      LAYER M5 ;
        RECT  33.168 0 33.192 0.084 ;
    END
  END fdm[619]
  PIN fdm[61]
    DIRECTION OUTPUT ;
    USE SIGNAL ;
    PORT
      LAYER M5 ;
        RECT  129.456 0 129.48 0.084 ;
    END
  END fdm[61]
  PIN fdm[620]
    DIRECTION OUTPUT ;
    USE SIGNAL ;
    PORT
      LAYER M5 ;
        RECT  32.976 0 33 0.084 ;
    END
  END fdm[620]
  PIN fdm[621]
    DIRECTION OUTPUT ;
    USE SIGNAL ;
    PORT
      LAYER M5 ;
        RECT  32.784 0 32.808 0.084 ;
    END
  END fdm[621]
  PIN fdm[622]
    DIRECTION OUTPUT ;
    USE SIGNAL ;
    PORT
      LAYER M5 ;
        RECT  32.592 0 32.616 0.084 ;
    END
  END fdm[622]
  PIN fdm[623]
    DIRECTION OUTPUT ;
    USE SIGNAL ;
    PORT
      LAYER M5 ;
        RECT  32.448 0 32.472 0.084 ;
    END
  END fdm[623]
  PIN fdm[624]
    DIRECTION OUTPUT ;
    USE SIGNAL ;
    PORT
      LAYER M5 ;
        RECT  32.256 0 32.28 0.084 ;
    END
  END fdm[624]
  PIN fdm[625]
    DIRECTION OUTPUT ;
    USE SIGNAL ;
    PORT
      LAYER M5 ;
        RECT  32.064 0 32.088 0.084 ;
    END
  END fdm[625]
  PIN fdm[626]
    DIRECTION OUTPUT ;
    USE SIGNAL ;
    PORT
      LAYER M5 ;
        RECT  31.872 0 31.896 0.084 ;
    END
  END fdm[626]
  PIN fdm[627]
    DIRECTION OUTPUT ;
    USE SIGNAL ;
    PORT
      LAYER M5 ;
        RECT  31.728 0 31.752 0.084 ;
    END
  END fdm[627]
  PIN fdm[628]
    DIRECTION OUTPUT ;
    USE SIGNAL ;
    PORT
      LAYER M5 ;
        RECT  31.536 0 31.56 0.084 ;
    END
  END fdm[628]
  PIN fdm[629]
    DIRECTION OUTPUT ;
    USE SIGNAL ;
    PORT
      LAYER M5 ;
        RECT  31.344 0 31.368 0.084 ;
    END
  END fdm[629]
  PIN fdm[62]
    DIRECTION OUTPUT ;
    USE SIGNAL ;
    PORT
      LAYER M5 ;
        RECT  129.648 0 129.672 0.084 ;
    END
  END fdm[62]
  PIN fdm[630]
    DIRECTION OUTPUT ;
    USE SIGNAL ;
    PORT
      LAYER M5 ;
        RECT  31.152 0 31.176 0.084 ;
    END
  END fdm[630]
  PIN fdm[631]
    DIRECTION OUTPUT ;
    USE SIGNAL ;
    PORT
      LAYER M5 ;
        RECT  31.008 0 31.032 0.084 ;
    END
  END fdm[631]
  PIN fdm[632]
    DIRECTION OUTPUT ;
    USE SIGNAL ;
    PORT
      LAYER M5 ;
        RECT  30.816 0 30.84 0.084 ;
    END
  END fdm[632]
  PIN fdm[633]
    DIRECTION OUTPUT ;
    USE SIGNAL ;
    PORT
      LAYER M5 ;
        RECT  30.624 0 30.648 0.084 ;
    END
  END fdm[633]
  PIN fdm[634]
    DIRECTION OUTPUT ;
    USE SIGNAL ;
    PORT
      LAYER M5 ;
        RECT  30.48 0 30.504 0.084 ;
    END
  END fdm[634]
  PIN fdm[635]
    DIRECTION OUTPUT ;
    USE SIGNAL ;
    PORT
      LAYER M5 ;
        RECT  30.288 0 30.312 0.084 ;
    END
  END fdm[635]
  PIN fdm[636]
    DIRECTION OUTPUT ;
    USE SIGNAL ;
    PORT
      LAYER M5 ;
        RECT  30.096 0 30.12 0.084 ;
    END
  END fdm[636]
  PIN fdm[637]
    DIRECTION OUTPUT ;
    USE SIGNAL ;
    PORT
      LAYER M5 ;
        RECT  29.904 0 29.928 0.084 ;
    END
  END fdm[637]
  PIN fdm[638]
    DIRECTION OUTPUT ;
    USE SIGNAL ;
    PORT
      LAYER M5 ;
        RECT  29.76 0 29.784 0.084 ;
    END
  END fdm[638]
  PIN fdm[639]
    DIRECTION OUTPUT ;
    USE SIGNAL ;
    PORT
      LAYER M5 ;
        RECT  29.568 0 29.592 0.084 ;
    END
  END fdm[639]
  PIN fdm[63]
    DIRECTION OUTPUT ;
    USE SIGNAL ;
    PORT
      LAYER M5 ;
        RECT  129.792 0 129.816 0.084 ;
    END
  END fdm[63]
  PIN fdm[640]
    DIRECTION OUTPUT ;
    USE SIGNAL ;
    PORT
      LAYER M5 ;
        RECT  29.376 0 29.4 0.084 ;
    END
  END fdm[640]
  PIN fdm[641]
    DIRECTION OUTPUT ;
    USE SIGNAL ;
    PORT
      LAYER M5 ;
        RECT  29.184 0 29.208 0.084 ;
    END
  END fdm[641]
  PIN fdm[642]
    DIRECTION OUTPUT ;
    USE SIGNAL ;
    PORT
      LAYER M5 ;
        RECT  29.04 0 29.064 0.084 ;
    END
  END fdm[642]
  PIN fdm[643]
    DIRECTION OUTPUT ;
    USE SIGNAL ;
    PORT
      LAYER M5 ;
        RECT  28.848 0 28.872 0.084 ;
    END
  END fdm[643]
  PIN fdm[644]
    DIRECTION OUTPUT ;
    USE SIGNAL ;
    PORT
      LAYER M5 ;
        RECT  28.656 0 28.68 0.084 ;
    END
  END fdm[644]
  PIN fdm[645]
    DIRECTION OUTPUT ;
    USE SIGNAL ;
    PORT
      LAYER M5 ;
        RECT  28.464 0 28.488 0.084 ;
    END
  END fdm[645]
  PIN fdm[646]
    DIRECTION OUTPUT ;
    USE SIGNAL ;
    PORT
      LAYER M5 ;
        RECT  28.32 0 28.344 0.084 ;
    END
  END fdm[646]
  PIN fdm[647]
    DIRECTION OUTPUT ;
    USE SIGNAL ;
    PORT
      LAYER M5 ;
        RECT  28.128 0 28.152 0.084 ;
    END
  END fdm[647]
  PIN fdm[648]
    DIRECTION OUTPUT ;
    USE SIGNAL ;
    PORT
      LAYER M5 ;
        RECT  27.936 0 27.96 0.084 ;
    END
  END fdm[648]
  PIN fdm[649]
    DIRECTION OUTPUT ;
    USE SIGNAL ;
    PORT
      LAYER M5 ;
        RECT  27.792 0 27.816 0.084 ;
    END
  END fdm[649]
  PIN fdm[64]
    DIRECTION OUTPUT ;
    USE SIGNAL ;
    PORT
      LAYER M5 ;
        RECT  135.744 0 135.768 0.084 ;
    END
  END fdm[64]
  PIN fdm[650]
    DIRECTION OUTPUT ;
    USE SIGNAL ;
    PORT
      LAYER M5 ;
        RECT  27.6 0 27.624 0.084 ;
    END
  END fdm[650]
  PIN fdm[651]
    DIRECTION OUTPUT ;
    USE SIGNAL ;
    PORT
      LAYER M5 ;
        RECT  27.408 0 27.432 0.084 ;
    END
  END fdm[651]
  PIN fdm[652]
    DIRECTION OUTPUT ;
    USE SIGNAL ;
    PORT
      LAYER M5 ;
        RECT  27.216 0 27.24 0.084 ;
    END
  END fdm[652]
  PIN fdm[653]
    DIRECTION OUTPUT ;
    USE SIGNAL ;
    PORT
      LAYER M5 ;
        RECT  27.072 0 27.096 0.084 ;
    END
  END fdm[653]
  PIN fdm[654]
    DIRECTION OUTPUT ;
    USE SIGNAL ;
    PORT
      LAYER M5 ;
        RECT  26.88 0 26.904 0.084 ;
    END
  END fdm[654]
  PIN fdm[655]
    DIRECTION OUTPUT ;
    USE SIGNAL ;
    PORT
      LAYER M5 ;
        RECT  26.688 0 26.712 0.084 ;
    END
  END fdm[655]
  PIN fdm[656]
    DIRECTION OUTPUT ;
    USE SIGNAL ;
    PORT
      LAYER M5 ;
        RECT  26.496 0 26.52 0.084 ;
    END
  END fdm[656]
  PIN fdm[657]
    DIRECTION OUTPUT ;
    USE SIGNAL ;
    PORT
      LAYER M5 ;
        RECT  26.352 0 26.376 0.084 ;
    END
  END fdm[657]
  PIN fdm[658]
    DIRECTION OUTPUT ;
    USE SIGNAL ;
    PORT
      LAYER M5 ;
        RECT  26.16 0 26.184 0.084 ;
    END
  END fdm[658]
  PIN fdm[659]
    DIRECTION OUTPUT ;
    USE SIGNAL ;
    PORT
      LAYER M5 ;
        RECT  25.968 0 25.992 0.084 ;
    END
  END fdm[659]
  PIN fdm[65]
    DIRECTION OUTPUT ;
    USE SIGNAL ;
    PORT
      LAYER M5 ;
        RECT  135.888 0 135.912 0.084 ;
    END
  END fdm[65]
  PIN fdm[660]
    DIRECTION OUTPUT ;
    USE SIGNAL ;
    PORT
      LAYER M5 ;
        RECT  25.776 0 25.8 0.084 ;
    END
  END fdm[660]
  PIN fdm[661]
    DIRECTION OUTPUT ;
    USE SIGNAL ;
    PORT
      LAYER M5 ;
        RECT  25.632 0 25.656 0.084 ;
    END
  END fdm[661]
  PIN fdm[662]
    DIRECTION OUTPUT ;
    USE SIGNAL ;
    PORT
      LAYER M5 ;
        RECT  25.44 0 25.464 0.084 ;
    END
  END fdm[662]
  PIN fdm[663]
    DIRECTION OUTPUT ;
    USE SIGNAL ;
    PORT
      LAYER M5 ;
        RECT  25.248 0 25.272 0.084 ;
    END
  END fdm[663]
  PIN fdm[664]
    DIRECTION OUTPUT ;
    USE SIGNAL ;
    PORT
      LAYER M5 ;
        RECT  25.056 0 25.08 0.084 ;
    END
  END fdm[664]
  PIN fdm[665]
    DIRECTION OUTPUT ;
    USE SIGNAL ;
    PORT
      LAYER M5 ;
        RECT  24.912 0 24.936 0.084 ;
    END
  END fdm[665]
  PIN fdm[666]
    DIRECTION OUTPUT ;
    USE SIGNAL ;
    PORT
      LAYER M5 ;
        RECT  24.72 0 24.744 0.084 ;
    END
  END fdm[666]
  PIN fdm[667]
    DIRECTION OUTPUT ;
    USE SIGNAL ;
    PORT
      LAYER M5 ;
        RECT  24.528 0 24.552 0.084 ;
    END
  END fdm[667]
  PIN fdm[668]
    DIRECTION OUTPUT ;
    USE SIGNAL ;
    PORT
      LAYER M5 ;
        RECT  24.384 0 24.408 0.084 ;
    END
  END fdm[668]
  PIN fdm[669]
    DIRECTION OUTPUT ;
    USE SIGNAL ;
    PORT
      LAYER M5 ;
        RECT  24.192 0 24.216 0.084 ;
    END
  END fdm[669]
  PIN fdm[66]
    DIRECTION OUTPUT ;
    USE SIGNAL ;
    PORT
      LAYER M5 ;
        RECT  136.08 0 136.104 0.084 ;
    END
  END fdm[66]
  PIN fdm[670]
    DIRECTION OUTPUT ;
    USE SIGNAL ;
    PORT
      LAYER M5 ;
        RECT  24 0 24.024 0.084 ;
    END
  END fdm[670]
  PIN fdm[671]
    DIRECTION OUTPUT ;
    USE SIGNAL ;
    PORT
      LAYER M5 ;
        RECT  23.808 0 23.832 0.084 ;
    END
  END fdm[671]
  PIN fdm[672]
    DIRECTION OUTPUT ;
    USE SIGNAL ;
    PORT
      LAYER M5 ;
        RECT  23.664 0 23.688 0.084 ;
    END
  END fdm[672]
  PIN fdm[673]
    DIRECTION OUTPUT ;
    USE SIGNAL ;
    PORT
      LAYER M5 ;
        RECT  23.472 0 23.496 0.084 ;
    END
  END fdm[673]
  PIN fdm[674]
    DIRECTION OUTPUT ;
    USE SIGNAL ;
    PORT
      LAYER M5 ;
        RECT  23.28 0 23.304 0.084 ;
    END
  END fdm[674]
  PIN fdm[675]
    DIRECTION OUTPUT ;
    USE SIGNAL ;
    PORT
      LAYER M5 ;
        RECT  23.088 0 23.112 0.084 ;
    END
  END fdm[675]
  PIN fdm[676]
    DIRECTION OUTPUT ;
    USE SIGNAL ;
    PORT
      LAYER M5 ;
        RECT  22.944 0 22.968 0.084 ;
    END
  END fdm[676]
  PIN fdm[677]
    DIRECTION OUTPUT ;
    USE SIGNAL ;
    PORT
      LAYER M5 ;
        RECT  22.752 0 22.776 0.084 ;
    END
  END fdm[677]
  PIN fdm[678]
    DIRECTION OUTPUT ;
    USE SIGNAL ;
    PORT
      LAYER M5 ;
        RECT  22.56 0 22.584 0.084 ;
    END
  END fdm[678]
  PIN fdm[679]
    DIRECTION OUTPUT ;
    USE SIGNAL ;
    PORT
      LAYER M5 ;
        RECT  22.368 0 22.392 0.084 ;
    END
  END fdm[679]
  PIN fdm[67]
    DIRECTION OUTPUT ;
    USE SIGNAL ;
    PORT
      LAYER M5 ;
        RECT  136.272 0 136.296 0.084 ;
    END
  END fdm[67]
  PIN fdm[680]
    DIRECTION OUTPUT ;
    USE SIGNAL ;
    PORT
      LAYER M5 ;
        RECT  22.224 0 22.248 0.084 ;
    END
  END fdm[680]
  PIN fdm[681]
    DIRECTION OUTPUT ;
    USE SIGNAL ;
    PORT
      LAYER M5 ;
        RECT  22.032 0 22.056 0.084 ;
    END
  END fdm[681]
  PIN fdm[682]
    DIRECTION OUTPUT ;
    USE SIGNAL ;
    PORT
      LAYER M5 ;
        RECT  21.84 0 21.864 0.084 ;
    END
  END fdm[682]
  PIN fdm[683]
    DIRECTION OUTPUT ;
    USE SIGNAL ;
    PORT
      LAYER M5 ;
        RECT  21.648 0 21.672 0.084 ;
    END
  END fdm[683]
  PIN fdm[684]
    DIRECTION OUTPUT ;
    USE SIGNAL ;
    PORT
      LAYER M5 ;
        RECT  21.504 0 21.528 0.084 ;
    END
  END fdm[684]
  PIN fdm[685]
    DIRECTION OUTPUT ;
    USE SIGNAL ;
    PORT
      LAYER M5 ;
        RECT  21.312 0 21.336 0.084 ;
    END
  END fdm[685]
  PIN fdm[686]
    DIRECTION OUTPUT ;
    USE SIGNAL ;
    PORT
      LAYER M5 ;
        RECT  21.12 0 21.144 0.084 ;
    END
  END fdm[686]
  PIN fdm[687]
    DIRECTION OUTPUT ;
    USE SIGNAL ;
    PORT
      LAYER M5 ;
        RECT  20.976 0 21 0.084 ;
    END
  END fdm[687]
  PIN fdm[688]
    DIRECTION OUTPUT ;
    USE SIGNAL ;
    PORT
      LAYER M5 ;
        RECT  20.784 0 20.808 0.084 ;
    END
  END fdm[688]
  PIN fdm[689]
    DIRECTION OUTPUT ;
    USE SIGNAL ;
    PORT
      LAYER M5 ;
        RECT  20.592 0 20.616 0.084 ;
    END
  END fdm[689]
  PIN fdm[68]
    DIRECTION OUTPUT ;
    USE SIGNAL ;
    PORT
      LAYER M5 ;
        RECT  136.464 0 136.488 0.084 ;
    END
  END fdm[68]
  PIN fdm[690]
    DIRECTION OUTPUT ;
    USE SIGNAL ;
    PORT
      LAYER M5 ;
        RECT  20.4 0 20.424 0.084 ;
    END
  END fdm[690]
  PIN fdm[691]
    DIRECTION OUTPUT ;
    USE SIGNAL ;
    PORT
      LAYER M5 ;
        RECT  20.256 0 20.28 0.084 ;
    END
  END fdm[691]
  PIN fdm[692]
    DIRECTION OUTPUT ;
    USE SIGNAL ;
    PORT
      LAYER M5 ;
        RECT  20.064 0 20.088 0.084 ;
    END
  END fdm[692]
  PIN fdm[693]
    DIRECTION OUTPUT ;
    USE SIGNAL ;
    PORT
      LAYER M5 ;
        RECT  19.872 0 19.896 0.084 ;
    END
  END fdm[693]
  PIN fdm[694]
    DIRECTION OUTPUT ;
    USE SIGNAL ;
    PORT
      LAYER M5 ;
        RECT  19.68 0 19.704 0.084 ;
    END
  END fdm[694]
  PIN fdm[695]
    DIRECTION OUTPUT ;
    USE SIGNAL ;
    PORT
      LAYER M5 ;
        RECT  19.536 0 19.56 0.084 ;
    END
  END fdm[695]
  PIN fdm[696]
    DIRECTION OUTPUT ;
    USE SIGNAL ;
    PORT
      LAYER M5 ;
        RECT  19.344 0 19.368 0.084 ;
    END
  END fdm[696]
  PIN fdm[697]
    DIRECTION OUTPUT ;
    USE SIGNAL ;
    PORT
      LAYER M5 ;
        RECT  19.152 0 19.176 0.084 ;
    END
  END fdm[697]
  PIN fdm[698]
    DIRECTION OUTPUT ;
    USE SIGNAL ;
    PORT
      LAYER M5 ;
        RECT  18.96 0 18.984 0.084 ;
    END
  END fdm[698]
  PIN fdm[699]
    DIRECTION OUTPUT ;
    USE SIGNAL ;
    PORT
      LAYER M5 ;
        RECT  18.816 0 18.84 0.084 ;
    END
  END fdm[699]
  PIN fdm[69]
    DIRECTION OUTPUT ;
    USE SIGNAL ;
    PORT
      LAYER M5 ;
        RECT  136.608 0 136.632 0.084 ;
    END
  END fdm[69]
  PIN fdm[6]
    DIRECTION OUTPUT ;
    USE SIGNAL ;
    PORT
      LAYER M5 ;
        RECT  131.088 0 131.112 0.084 ;
    END
  END fdm[6]
  PIN fdm[700]
    DIRECTION OUTPUT ;
    USE SIGNAL ;
    PORT
      LAYER M5 ;
        RECT  18.624 0 18.648 0.084 ;
    END
  END fdm[700]
  PIN fdm[701]
    DIRECTION OUTPUT ;
    USE SIGNAL ;
    PORT
      LAYER M5 ;
        RECT  18.432 0 18.456 0.084 ;
    END
  END fdm[701]
  PIN fdm[702]
    DIRECTION OUTPUT ;
    USE SIGNAL ;
    PORT
      LAYER M5 ;
        RECT  18.24 0 18.264 0.084 ;
    END
  END fdm[702]
  PIN fdm[703]
    DIRECTION OUTPUT ;
    USE SIGNAL ;
    PORT
      LAYER M5 ;
        RECT  18.096 0 18.12 0.084 ;
    END
  END fdm[703]
  PIN fdm[704]
    DIRECTION OUTPUT ;
    USE SIGNAL ;
    PORT
      LAYER M5 ;
        RECT  17.904 0 17.928 0.084 ;
    END
  END fdm[704]
  PIN fdm[705]
    DIRECTION OUTPUT ;
    USE SIGNAL ;
    PORT
      LAYER M5 ;
        RECT  17.712 0 17.736 0.084 ;
    END
  END fdm[705]
  PIN fdm[706]
    DIRECTION OUTPUT ;
    USE SIGNAL ;
    PORT
      LAYER M5 ;
        RECT  17.568 0 17.592 0.084 ;
    END
  END fdm[706]
  PIN fdm[707]
    DIRECTION OUTPUT ;
    USE SIGNAL ;
    PORT
      LAYER M5 ;
        RECT  17.376 0 17.4 0.084 ;
    END
  END fdm[707]
  PIN fdm[708]
    DIRECTION OUTPUT ;
    USE SIGNAL ;
    PORT
      LAYER M5 ;
        RECT  17.184 0 17.208 0.084 ;
    END
  END fdm[708]
  PIN fdm[709]
    DIRECTION OUTPUT ;
    USE SIGNAL ;
    PORT
      LAYER M5 ;
        RECT  16.992 0 17.016 0.084 ;
    END
  END fdm[709]
  PIN fdm[70]
    DIRECTION OUTPUT ;
    USE SIGNAL ;
    PORT
      LAYER M5 ;
        RECT  136.8 0 136.824 0.084 ;
    END
  END fdm[70]
  PIN fdm[710]
    DIRECTION OUTPUT ;
    USE SIGNAL ;
    PORT
      LAYER M5 ;
        RECT  16.848 0 16.872 0.084 ;
    END
  END fdm[710]
  PIN fdm[711]
    DIRECTION OUTPUT ;
    USE SIGNAL ;
    PORT
      LAYER M5 ;
        RECT  16.656 0 16.68 0.084 ;
    END
  END fdm[711]
  PIN fdm[712]
    DIRECTION OUTPUT ;
    USE SIGNAL ;
    PORT
      LAYER M5 ;
        RECT  16.464 0 16.488 0.084 ;
    END
  END fdm[712]
  PIN fdm[713]
    DIRECTION OUTPUT ;
    USE SIGNAL ;
    PORT
      LAYER M5 ;
        RECT  16.272 0 16.296 0.084 ;
    END
  END fdm[713]
  PIN fdm[714]
    DIRECTION OUTPUT ;
    USE SIGNAL ;
    PORT
      LAYER M5 ;
        RECT  16.128 0 16.152 0.084 ;
    END
  END fdm[714]
  PIN fdm[715]
    DIRECTION OUTPUT ;
    USE SIGNAL ;
    PORT
      LAYER M5 ;
        RECT  15.936 0 15.96 0.084 ;
    END
  END fdm[715]
  PIN fdm[716]
    DIRECTION OUTPUT ;
    USE SIGNAL ;
    PORT
      LAYER M5 ;
        RECT  15.744 0 15.768 0.084 ;
    END
  END fdm[716]
  PIN fdm[717]
    DIRECTION OUTPUT ;
    USE SIGNAL ;
    PORT
      LAYER M5 ;
        RECT  15.552 0 15.576 0.084 ;
    END
  END fdm[717]
  PIN fdm[718]
    DIRECTION OUTPUT ;
    USE SIGNAL ;
    PORT
      LAYER M5 ;
        RECT  15.408 0 15.432 0.084 ;
    END
  END fdm[718]
  PIN fdm[719]
    DIRECTION OUTPUT ;
    USE SIGNAL ;
    PORT
      LAYER M5 ;
        RECT  15.216 0 15.24 0.084 ;
    END
  END fdm[719]
  PIN fdm[71]
    DIRECTION OUTPUT ;
    USE SIGNAL ;
    PORT
      LAYER M5 ;
        RECT  136.992 0 137.016 0.084 ;
    END
  END fdm[71]
  PIN fdm[720]
    DIRECTION OUTPUT ;
    USE SIGNAL ;
    PORT
      LAYER M5 ;
        RECT  15.024 0 15.048 0.084 ;
    END
  END fdm[720]
  PIN fdm[721]
    DIRECTION OUTPUT ;
    USE SIGNAL ;
    PORT
      LAYER M5 ;
        RECT  14.832 0 14.856 0.084 ;
    END
  END fdm[721]
  PIN fdm[722]
    DIRECTION OUTPUT ;
    USE SIGNAL ;
    PORT
      LAYER M5 ;
        RECT  14.688 0 14.712 0.084 ;
    END
  END fdm[722]
  PIN fdm[723]
    DIRECTION OUTPUT ;
    USE SIGNAL ;
    PORT
      LAYER M5 ;
        RECT  14.496 0 14.52 0.084 ;
    END
  END fdm[723]
  PIN fdm[724]
    DIRECTION OUTPUT ;
    USE SIGNAL ;
    PORT
      LAYER M5 ;
        RECT  14.304 0 14.328 0.084 ;
    END
  END fdm[724]
  PIN fdm[725]
    DIRECTION OUTPUT ;
    USE SIGNAL ;
    PORT
      LAYER M5 ;
        RECT  14.16 0 14.184 0.084 ;
    END
  END fdm[725]
  PIN fdm[726]
    DIRECTION OUTPUT ;
    USE SIGNAL ;
    PORT
      LAYER M5 ;
        RECT  13.968 0 13.992 0.084 ;
    END
  END fdm[726]
  PIN fdm[727]
    DIRECTION OUTPUT ;
    USE SIGNAL ;
    PORT
      LAYER M5 ;
        RECT  13.776 0 13.8 0.084 ;
    END
  END fdm[727]
  PIN fdm[728]
    DIRECTION OUTPUT ;
    USE SIGNAL ;
    PORT
      LAYER M5 ;
        RECT  13.584 0 13.608 0.084 ;
    END
  END fdm[728]
  PIN fdm[729]
    DIRECTION OUTPUT ;
    USE SIGNAL ;
    PORT
      LAYER M5 ;
        RECT  13.44 0 13.464 0.084 ;
    END
  END fdm[729]
  PIN fdm[72]
    DIRECTION OUTPUT ;
    USE SIGNAL ;
    PORT
      LAYER M5 ;
        RECT  137.184 0 137.208 0.084 ;
    END
  END fdm[72]
  PIN fdm[730]
    DIRECTION OUTPUT ;
    USE SIGNAL ;
    PORT
      LAYER M5 ;
        RECT  13.248 0 13.272 0.084 ;
    END
  END fdm[730]
  PIN fdm[731]
    DIRECTION OUTPUT ;
    USE SIGNAL ;
    PORT
      LAYER M5 ;
        RECT  13.056 0 13.08 0.084 ;
    END
  END fdm[731]
  PIN fdm[732]
    DIRECTION OUTPUT ;
    USE SIGNAL ;
    PORT
      LAYER M5 ;
        RECT  12.864 0 12.888 0.084 ;
    END
  END fdm[732]
  PIN fdm[733]
    DIRECTION OUTPUT ;
    USE SIGNAL ;
    PORT
      LAYER M5 ;
        RECT  12.72 0 12.744 0.084 ;
    END
  END fdm[733]
  PIN fdm[734]
    DIRECTION OUTPUT ;
    USE SIGNAL ;
    PORT
      LAYER M5 ;
        RECT  12.528 0 12.552 0.084 ;
    END
  END fdm[734]
  PIN fdm[735]
    DIRECTION OUTPUT ;
    USE SIGNAL ;
    PORT
      LAYER M5 ;
        RECT  12.336 0 12.36 0.084 ;
    END
  END fdm[735]
  PIN fdm[736]
    DIRECTION OUTPUT ;
    USE SIGNAL ;
    PORT
      LAYER M5 ;
        RECT  12.144 0 12.168 0.084 ;
    END
  END fdm[736]
  PIN fdm[737]
    DIRECTION OUTPUT ;
    USE SIGNAL ;
    PORT
      LAYER M5 ;
        RECT  12 0 12.024 0.084 ;
    END
  END fdm[737]
  PIN fdm[738]
    DIRECTION OUTPUT ;
    USE SIGNAL ;
    PORT
      LAYER M5 ;
        RECT  11.808 0 11.832 0.084 ;
    END
  END fdm[738]
  PIN fdm[739]
    DIRECTION OUTPUT ;
    USE SIGNAL ;
    PORT
      LAYER M5 ;
        RECT  11.616 0 11.64 0.084 ;
    END
  END fdm[739]
  PIN fdm[73]
    DIRECTION OUTPUT ;
    USE SIGNAL ;
    PORT
      LAYER M5 ;
        RECT  137.328 0 137.352 0.084 ;
    END
  END fdm[73]
  PIN fdm[740]
    DIRECTION OUTPUT ;
    USE SIGNAL ;
    PORT
      LAYER M5 ;
        RECT  11.472 0 11.496 0.084 ;
    END
  END fdm[740]
  PIN fdm[741]
    DIRECTION OUTPUT ;
    USE SIGNAL ;
    PORT
      LAYER M5 ;
        RECT  11.28 0 11.304 0.084 ;
    END
  END fdm[741]
  PIN fdm[742]
    DIRECTION OUTPUT ;
    USE SIGNAL ;
    PORT
      LAYER M5 ;
        RECT  11.088 0 11.112 0.084 ;
    END
  END fdm[742]
  PIN fdm[743]
    DIRECTION OUTPUT ;
    USE SIGNAL ;
    PORT
      LAYER M5 ;
        RECT  10.896 0 10.92 0.084 ;
    END
  END fdm[743]
  PIN fdm[744]
    DIRECTION OUTPUT ;
    USE SIGNAL ;
    PORT
      LAYER M5 ;
        RECT  10.752 0 10.776 0.084 ;
    END
  END fdm[744]
  PIN fdm[745]
    DIRECTION OUTPUT ;
    USE SIGNAL ;
    PORT
      LAYER M5 ;
        RECT  10.56 0 10.584 0.084 ;
    END
  END fdm[745]
  PIN fdm[746]
    DIRECTION OUTPUT ;
    USE SIGNAL ;
    PORT
      LAYER M5 ;
        RECT  10.368 0 10.392 0.084 ;
    END
  END fdm[746]
  PIN fdm[747]
    DIRECTION OUTPUT ;
    USE SIGNAL ;
    PORT
      LAYER M5 ;
        RECT  10.176 0 10.2 0.084 ;
    END
  END fdm[747]
  PIN fdm[748]
    DIRECTION OUTPUT ;
    USE SIGNAL ;
    PORT
      LAYER M5 ;
        RECT  10.032 0 10.056 0.084 ;
    END
  END fdm[748]
  PIN fdm[749]
    DIRECTION OUTPUT ;
    USE SIGNAL ;
    PORT
      LAYER M5 ;
        RECT  9.84 0 9.864 0.084 ;
    END
  END fdm[749]
  PIN fdm[74]
    DIRECTION OUTPUT ;
    USE SIGNAL ;
    PORT
      LAYER M5 ;
        RECT  137.52 0 137.544 0.084 ;
    END
  END fdm[74]
  PIN fdm[750]
    DIRECTION OUTPUT ;
    USE SIGNAL ;
    PORT
      LAYER M5 ;
        RECT  9.648 0 9.672 0.084 ;
    END
  END fdm[750]
  PIN fdm[751]
    DIRECTION OUTPUT ;
    USE SIGNAL ;
    PORT
      LAYER M5 ;
        RECT  9.456 0 9.48 0.084 ;
    END
  END fdm[751]
  PIN fdm[752]
    DIRECTION OUTPUT ;
    USE SIGNAL ;
    PORT
      LAYER M5 ;
        RECT  9.312 0 9.336 0.084 ;
    END
  END fdm[752]
  PIN fdm[753]
    DIRECTION OUTPUT ;
    USE SIGNAL ;
    PORT
      LAYER M5 ;
        RECT  9.12 0 9.144 0.084 ;
    END
  END fdm[753]
  PIN fdm[754]
    DIRECTION OUTPUT ;
    USE SIGNAL ;
    PORT
      LAYER M5 ;
        RECT  8.928 0 8.952 0.084 ;
    END
  END fdm[754]
  PIN fdm[755]
    DIRECTION OUTPUT ;
    USE SIGNAL ;
    PORT
      LAYER M5 ;
        RECT  8.736 0 8.76 0.084 ;
    END
  END fdm[755]
  PIN fdm[756]
    DIRECTION OUTPUT ;
    USE SIGNAL ;
    PORT
      LAYER M5 ;
        RECT  8.592 0 8.616 0.084 ;
    END
  END fdm[756]
  PIN fdm[757]
    DIRECTION OUTPUT ;
    USE SIGNAL ;
    PORT
      LAYER M5 ;
        RECT  8.4 0 8.424 0.084 ;
    END
  END fdm[757]
  PIN fdm[758]
    DIRECTION OUTPUT ;
    USE SIGNAL ;
    PORT
      LAYER M5 ;
        RECT  8.208 0 8.232 0.084 ;
    END
  END fdm[758]
  PIN fdm[759]
    DIRECTION OUTPUT ;
    USE SIGNAL ;
    PORT
      LAYER M5 ;
        RECT  8.064 0 8.088 0.084 ;
    END
  END fdm[759]
  PIN fdm[75]
    DIRECTION OUTPUT ;
    USE SIGNAL ;
    PORT
      LAYER M5 ;
        RECT  137.712 0 137.736 0.084 ;
    END
  END fdm[75]
  PIN fdm[760]
    DIRECTION OUTPUT ;
    USE SIGNAL ;
    PORT
      LAYER M5 ;
        RECT  7.872 0 7.896 0.084 ;
    END
  END fdm[760]
  PIN fdm[761]
    DIRECTION OUTPUT ;
    USE SIGNAL ;
    PORT
      LAYER M5 ;
        RECT  7.68 0 7.704 0.084 ;
    END
  END fdm[761]
  PIN fdm[762]
    DIRECTION OUTPUT ;
    USE SIGNAL ;
    PORT
      LAYER M5 ;
        RECT  7.488 0 7.512 0.084 ;
    END
  END fdm[762]
  PIN fdm[763]
    DIRECTION OUTPUT ;
    USE SIGNAL ;
    PORT
      LAYER M5 ;
        RECT  7.344 0 7.368 0.084 ;
    END
  END fdm[763]
  PIN fdm[764]
    DIRECTION OUTPUT ;
    USE SIGNAL ;
    PORT
      LAYER M5 ;
        RECT  7.152 0 7.176 0.084 ;
    END
  END fdm[764]
  PIN fdm[765]
    DIRECTION OUTPUT ;
    USE SIGNAL ;
    PORT
      LAYER M5 ;
        RECT  6.96 0 6.984 0.084 ;
    END
  END fdm[765]
  PIN fdm[766]
    DIRECTION OUTPUT ;
    USE SIGNAL ;
    PORT
      LAYER M5 ;
        RECT  6.768 0 6.792 0.084 ;
    END
  END fdm[766]
  PIN fdm[767]
    DIRECTION OUTPUT ;
    USE SIGNAL ;
    PORT
      LAYER M5 ;
        RECT  6.624 0 6.648 0.084 ;
    END
  END fdm[767]
  PIN fdm[768]
    DIRECTION OUTPUT ;
    USE SIGNAL ;
    PORT
      LAYER M5 ;
        RECT  6.432 0 6.456 0.084 ;
    END
  END fdm[768]
  PIN fdm[769]
    DIRECTION OUTPUT ;
    USE SIGNAL ;
    PORT
      LAYER M5 ;
        RECT  6.24 0 6.264 0.084 ;
    END
  END fdm[769]
  PIN fdm[76]
    DIRECTION OUTPUT ;
    USE SIGNAL ;
    PORT
      LAYER M5 ;
        RECT  137.904 0 137.928 0.084 ;
    END
  END fdm[76]
  PIN fdm[770]
    DIRECTION OUTPUT ;
    USE SIGNAL ;
    PORT
      LAYER M5 ;
        RECT  6.048 0 6.072 0.084 ;
    END
  END fdm[770]
  PIN fdm[771]
    DIRECTION OUTPUT ;
    USE SIGNAL ;
    PORT
      LAYER M5 ;
        RECT  5.904 0 5.928 0.084 ;
    END
  END fdm[771]
  PIN fdm[772]
    DIRECTION OUTPUT ;
    USE SIGNAL ;
    PORT
      LAYER M5 ;
        RECT  5.712 0 5.736 0.084 ;
    END
  END fdm[772]
  PIN fdm[773]
    DIRECTION OUTPUT ;
    USE SIGNAL ;
    PORT
      LAYER M5 ;
        RECT  5.52 0 5.544 0.084 ;
    END
  END fdm[773]
  PIN fdm[774]
    DIRECTION OUTPUT ;
    USE SIGNAL ;
    PORT
      LAYER M5 ;
        RECT  5.328 0 5.352 0.084 ;
    END
  END fdm[774]
  PIN fdm[775]
    DIRECTION OUTPUT ;
    USE SIGNAL ;
    PORT
      LAYER M5 ;
        RECT  5.184 0 5.208 0.084 ;
    END
  END fdm[775]
  PIN fdm[776]
    DIRECTION OUTPUT ;
    USE SIGNAL ;
    PORT
      LAYER M5 ;
        RECT  4.992 0 5.016 0.084 ;
    END
  END fdm[776]
  PIN fdm[777]
    DIRECTION OUTPUT ;
    USE SIGNAL ;
    PORT
      LAYER M5 ;
        RECT  4.8 0 4.824 0.084 ;
    END
  END fdm[777]
  PIN fdm[778]
    DIRECTION OUTPUT ;
    USE SIGNAL ;
    PORT
      LAYER M5 ;
        RECT  4.656 0 4.68 0.084 ;
    END
  END fdm[778]
  PIN fdm[779]
    DIRECTION OUTPUT ;
    USE SIGNAL ;
    PORT
      LAYER M5 ;
        RECT  4.464 0 4.488 0.084 ;
    END
  END fdm[779]
  PIN fdm[77]
    DIRECTION OUTPUT ;
    USE SIGNAL ;
    PORT
      LAYER M5 ;
        RECT  138.048 0 138.072 0.084 ;
    END
  END fdm[77]
  PIN fdm[780]
    DIRECTION OUTPUT ;
    USE SIGNAL ;
    PORT
      LAYER M5 ;
        RECT  4.272 0 4.296 0.084 ;
    END
  END fdm[780]
  PIN fdm[781]
    DIRECTION OUTPUT ;
    USE SIGNAL ;
    PORT
      LAYER M5 ;
        RECT  4.08 0 4.104 0.084 ;
    END
  END fdm[781]
  PIN fdm[782]
    DIRECTION OUTPUT ;
    USE SIGNAL ;
    PORT
      LAYER M5 ;
        RECT  3.936 0 3.96 0.084 ;
    END
  END fdm[782]
  PIN fdm[783]
    DIRECTION OUTPUT ;
    USE SIGNAL ;
    PORT
      LAYER M5 ;
        RECT  3.744 0 3.768 0.084 ;
    END
  END fdm[783]
  PIN fdm[784]
    DIRECTION OUTPUT ;
    USE SIGNAL ;
    PORT
      LAYER M5 ;
        RECT  3.552 0 3.576 0.084 ;
    END
  END fdm[784]
  PIN fdm[785]
    DIRECTION OUTPUT ;
    USE SIGNAL ;
    PORT
      LAYER M5 ;
        RECT  3.36 0 3.384 0.084 ;
    END
  END fdm[785]
  PIN fdm[786]
    DIRECTION OUTPUT ;
    USE SIGNAL ;
    PORT
      LAYER M5 ;
        RECT  3.216 0 3.24 0.084 ;
    END
  END fdm[786]
  PIN fdm[787]
    DIRECTION OUTPUT ;
    USE SIGNAL ;
    PORT
      LAYER M5 ;
        RECT  3.024 0 3.048 0.084 ;
    END
  END fdm[787]
  PIN fdm[788]
    DIRECTION OUTPUT ;
    USE SIGNAL ;
    PORT
      LAYER M5 ;
        RECT  2.832 0 2.856 0.084 ;
    END
  END fdm[788]
  PIN fdm[789]
    DIRECTION OUTPUT ;
    USE SIGNAL ;
    PORT
      LAYER M5 ;
        RECT  2.64 0 2.664 0.084 ;
    END
  END fdm[789]
  PIN fdm[78]
    DIRECTION OUTPUT ;
    USE SIGNAL ;
    PORT
      LAYER M5 ;
        RECT  138.24 0 138.264 0.084 ;
    END
  END fdm[78]
  PIN fdm[790]
    DIRECTION OUTPUT ;
    USE SIGNAL ;
    PORT
      LAYER M5 ;
        RECT  2.496 0 2.52 0.084 ;
    END
  END fdm[790]
  PIN fdm[791]
    DIRECTION OUTPUT ;
    USE SIGNAL ;
    PORT
      LAYER M5 ;
        RECT  2.304 0 2.328 0.084 ;
    END
  END fdm[791]
  PIN fdm[792]
    DIRECTION OUTPUT ;
    USE SIGNAL ;
    PORT
      LAYER M5 ;
        RECT  2.112 0 2.136 0.084 ;
    END
  END fdm[792]
  PIN fdm[793]
    DIRECTION OUTPUT ;
    USE SIGNAL ;
    PORT
      LAYER M5 ;
        RECT  1.92 0 1.944 0.084 ;
    END
  END fdm[793]
  PIN fdm[794]
    DIRECTION OUTPUT ;
    USE SIGNAL ;
    PORT
      LAYER M5 ;
        RECT  1.776 0 1.8 0.084 ;
    END
  END fdm[794]
  PIN fdm[795]
    DIRECTION OUTPUT ;
    USE SIGNAL ;
    PORT
      LAYER M5 ;
        RECT  1.584 0 1.608 0.084 ;
    END
  END fdm[795]
  PIN fdm[796]
    DIRECTION OUTPUT ;
    USE SIGNAL ;
    PORT
      LAYER M5 ;
        RECT  1.392 0 1.416 0.084 ;
    END
  END fdm[796]
  PIN fdm[797]
    DIRECTION OUTPUT ;
    USE SIGNAL ;
    PORT
      LAYER M5 ;
        RECT  1.248 0 1.272 0.084 ;
    END
  END fdm[797]
  PIN fdm[798]
    DIRECTION OUTPUT ;
    USE SIGNAL ;
    PORT
      LAYER M5 ;
        RECT  1.056 0 1.08 0.084 ;
    END
  END fdm[798]
  PIN fdm[799]
    DIRECTION OUTPUT ;
    USE SIGNAL ;
    PORT
      LAYER M5 ;
        RECT  0.864 0 0.888 0.084 ;
    END
  END fdm[799]
  PIN fdm[79]
    DIRECTION OUTPUT ;
    USE SIGNAL ;
    PORT
      LAYER M5 ;
        RECT  138.432 0 138.456 0.084 ;
    END
  END fdm[79]
  PIN fdm[7]
    DIRECTION OUTPUT ;
    USE SIGNAL ;
    PORT
      LAYER M5 ;
        RECT  131.232 0 131.256 0.084 ;
    END
  END fdm[7]
  PIN fdm[800]
    DIRECTION OUTPUT ;
    USE SIGNAL ;
    PORT
      LAYER M5 ;
        RECT  0.672 0 0.696 0.084 ;
    END
  END fdm[800]
  PIN fdm[801]
    DIRECTION OUTPUT ;
    USE SIGNAL ;
    PORT
      LAYER M5 ;
        RECT  0.528 0 0.552 0.084 ;
    END
  END fdm[801]
  PIN fdm[802]
    DIRECTION OUTPUT ;
    USE SIGNAL ;
    PORT
      LAYER M5 ;
        RECT  0.336 0 0.36 0.084 ;
    END
  END fdm[802]
  PIN fdm[803]
    DIRECTION OUTPUT ;
    USE SIGNAL ;
    PORT
      LAYER M5 ;
        RECT  0.144 0 0.168 0.084 ;
    END
  END fdm[803]
  PIN fdm[80]
    DIRECTION OUTPUT ;
    USE SIGNAL ;
    PORT
      LAYER M5 ;
        RECT  138.624 0 138.648 0.084 ;
    END
  END fdm[80]
  PIN fdm[81]
    DIRECTION OUTPUT ;
    USE SIGNAL ;
    PORT
      LAYER M5 ;
        RECT  138.768 0 138.792 0.084 ;
    END
  END fdm[81]
  PIN fdm[82]
    DIRECTION OUTPUT ;
    USE SIGNAL ;
    PORT
      LAYER M5 ;
        RECT  138.96 0 138.984 0.084 ;
    END
  END fdm[82]
  PIN fdm[83]
    DIRECTION OUTPUT ;
    USE SIGNAL ;
    PORT
      LAYER M5 ;
        RECT  139.152 0 139.176 0.084 ;
    END
  END fdm[83]
  PIN fdm[84]
    DIRECTION OUTPUT ;
    USE SIGNAL ;
    PORT
      LAYER M5 ;
        RECT  139.296 0 139.32 0.084 ;
    END
  END fdm[84]
  PIN fdm[85]
    DIRECTION OUTPUT ;
    USE SIGNAL ;
    PORT
      LAYER M5 ;
        RECT  139.488 0 139.512 0.084 ;
    END
  END fdm[85]
  PIN fdm[86]
    DIRECTION OUTPUT ;
    USE SIGNAL ;
    PORT
      LAYER M5 ;
        RECT  139.68 0 139.704 0.084 ;
    END
  END fdm[86]
  PIN fdm[87]
    DIRECTION OUTPUT ;
    USE SIGNAL ;
    PORT
      LAYER M5 ;
        RECT  139.872 0 139.896 0.084 ;
    END
  END fdm[87]
  PIN fdm[88]
    DIRECTION OUTPUT ;
    USE SIGNAL ;
    PORT
      LAYER M5 ;
        RECT  140.016 0 140.04 0.084 ;
    END
  END fdm[88]
  PIN fdm[89]
    DIRECTION OUTPUT ;
    USE SIGNAL ;
    PORT
      LAYER M5 ;
        RECT  140.208 0 140.232 0.084 ;
    END
  END fdm[89]
  PIN fdm[8]
    DIRECTION OUTPUT ;
    USE SIGNAL ;
    PORT
      LAYER M5 ;
        RECT  131.424 0 131.448 0.084 ;
    END
  END fdm[8]
  PIN fdm[90]
    DIRECTION OUTPUT ;
    USE SIGNAL ;
    PORT
      LAYER M5 ;
        RECT  140.4 0 140.424 0.084 ;
    END
  END fdm[90]
  PIN fdm[91]
    DIRECTION OUTPUT ;
    USE SIGNAL ;
    PORT
      LAYER M5 ;
        RECT  140.592 0 140.616 0.084 ;
    END
  END fdm[91]
  PIN fdm[92]
    DIRECTION OUTPUT ;
    USE SIGNAL ;
    PORT
      LAYER M5 ;
        RECT  140.736 0 140.76 0.084 ;
    END
  END fdm[92]
  PIN fdm[93]
    DIRECTION OUTPUT ;
    USE SIGNAL ;
    PORT
      LAYER M5 ;
        RECT  140.928 0 140.952 0.084 ;
    END
  END fdm[93]
  PIN fdm[94]
    DIRECTION OUTPUT ;
    USE SIGNAL ;
    PORT
      LAYER M5 ;
        RECT  141.12 0 141.144 0.084 ;
    END
  END fdm[94]
  PIN fdm[95]
    DIRECTION OUTPUT ;
    USE SIGNAL ;
    PORT
      LAYER M5 ;
        RECT  141.312 0 141.336 0.084 ;
    END
  END fdm[95]
  PIN fdm[96]
    DIRECTION OUTPUT ;
    USE SIGNAL ;
    PORT
      LAYER M5 ;
        RECT  118.512 0 118.536 0.084 ;
    END
  END fdm[96]
  PIN fdm[97]
    DIRECTION OUTPUT ;
    USE SIGNAL ;
    PORT
      LAYER M5 ;
        RECT  118.704 0 118.728 0.084 ;
    END
  END fdm[97]
  PIN fdm[98]
    DIRECTION OUTPUT ;
    USE SIGNAL ;
    PORT
      LAYER M5 ;
        RECT  118.896 0 118.92 0.084 ;
    END
  END fdm[98]
  PIN fdm[99]
    DIRECTION OUTPUT ;
    USE SIGNAL ;
    PORT
      LAYER M5 ;
        RECT  119.04 0 119.064 0.084 ;
    END
  END fdm[99]
  PIN fdm[9]
    DIRECTION OUTPUT ;
    USE SIGNAL ;
    PORT
      LAYER M5 ;
        RECT  131.616 0 131.64 0.084 ;
    END
  END fdm[9]
  PIN VDD
    DIRECTION INOUT ;
    USE POWER ;
    PORT
      LAYER M5 ;
        RECT  137.592 2.151 137.712 23.769 ;
        RECT  132.192 2.151 132.312 23.769 ;
        RECT  126.792 2.151 126.912 23.769 ;
        RECT  121.392 2.151 121.512 23.769 ;
        RECT  115.992 2.151 116.112 23.769 ;
        RECT  110.592 2.151 110.712 23.769 ;
        RECT  105.192 2.151 105.312 23.769 ;
        RECT  99.792 2.151 99.912 23.769 ;
        RECT  94.392 2.151 94.512 23.769 ;
        RECT  88.992 2.151 89.112 23.769 ;
        RECT  83.592 2.151 83.712 23.769 ;
        RECT  78.192 2.151 78.312 23.769 ;
        RECT  72.792 2.151 72.912 23.769 ;
        RECT  67.392 2.151 67.512 23.769 ;
        RECT  61.992 2.151 62.112 23.769 ;
        RECT  56.592 2.151 56.712 23.769 ;
        RECT  51.192 2.151 51.312 23.769 ;
        RECT  45.792 2.151 45.912 23.769 ;
        RECT  40.392 2.151 40.512 23.769 ;
        RECT  34.992 2.151 35.112 23.769 ;
        RECT  29.592 2.151 29.712 23.769 ;
        RECT  24.192 2.151 24.312 23.769 ;
        RECT  18.792 2.151 18.912 23.769 ;
        RECT  13.392 2.151 13.512 23.769 ;
        RECT  7.992 2.151 8.112 23.769 ;
        RECT  2.592 2.151 2.712 23.769 ;
    END
  END VDD
  PIN VSS
    DIRECTION INOUT ;
    USE GROUND ;
    PORT
      LAYER M5 ;
        RECT  137.4 2.137 137.52 23.783 ;
        RECT  132 2.137 132.12 23.783 ;
        RECT  126.6 2.137 126.72 23.783 ;
        RECT  121.2 2.137 121.32 23.783 ;
        RECT  115.8 2.137 115.92 23.783 ;
        RECT  110.4 2.137 110.52 23.783 ;
        RECT  105 2.137 105.12 23.783 ;
        RECT  99.6 2.137 99.72 23.783 ;
        RECT  94.2 2.137 94.32 23.783 ;
        RECT  88.8 2.137 88.92 23.783 ;
        RECT  83.4 2.137 83.52 23.783 ;
        RECT  78 2.137 78.12 23.783 ;
        RECT  72.6 2.137 72.72 23.783 ;
        RECT  67.2 2.137 67.32 23.783 ;
        RECT  61.8 2.137 61.92 23.783 ;
        RECT  56.4 2.137 56.52 23.783 ;
        RECT  51 2.137 51.12 23.783 ;
        RECT  45.6 2.137 45.72 23.783 ;
        RECT  40.2 2.137 40.32 23.783 ;
        RECT  34.8 2.137 34.92 23.783 ;
        RECT  29.4 2.137 29.52 23.783 ;
        RECT  24 2.137 24.12 23.783 ;
        RECT  18.6 2.137 18.72 23.783 ;
        RECT  13.2 2.137 13.32 23.783 ;
        RECT  7.8 2.137 7.92 23.783 ;
        RECT  2.4 2.137 2.52 23.783 ;
    END
  END VSS
  OBS
    LAYER RVTN ;
     RECT  2.16 2.16 142.128 2.295 ;
     RECT  2.16 2.565 142.128 2.835 ;
     RECT  2.16 3.105 142.128 3.375 ;
     RECT  2.16 3.645 142.128 3.915 ;
     RECT  2.16 4.185 142.128 4.455 ;
     RECT  2.16 4.725 142.128 4.995 ;
     RECT  2.16 5.265 142.128 5.535 ;
     RECT  2.16 5.805 142.128 6.075 ;
     RECT  2.16 6.345 142.128 6.615 ;
     RECT  2.16 6.885 142.128 7.155 ;
     RECT  2.16 7.425 142.128 7.695 ;
     RECT  2.16 7.965 142.128 8.235 ;
     RECT  2.16 8.505 142.128 8.775 ;
     RECT  2.16 9.045 142.128 9.315 ;
     RECT  2.16 9.585 142.128 9.855 ;
     RECT  2.16 10.125 142.128 10.395 ;
     RECT  2.16 10.665 142.128 10.935 ;
     RECT  2.16 11.205 142.128 11.475 ;
     RECT  2.16 11.745 142.128 12.015 ;
     RECT  2.16 12.285 142.128 12.555 ;
     RECT  2.16 12.825 142.128 13.095 ;
     RECT  2.16 13.365 142.128 13.635 ;
     RECT  2.16 13.905 142.128 14.175 ;
     RECT  2.16 14.445 142.128 14.715 ;
     RECT  2.16 14.985 142.128 15.255 ;
     RECT  2.16 15.525 142.128 15.795 ;
     RECT  2.16 16.065 142.128 16.335 ;
     RECT  2.16 16.605 142.128 16.875 ;
     RECT  2.16 17.145 142.128 17.415 ;
     RECT  2.16 17.685 142.128 17.955 ;
     RECT  2.16 18.225 142.128 18.495 ;
     RECT  2.16 18.765 142.128 19.035 ;
     RECT  2.16 19.305 142.128 19.575 ;
     RECT  2.16 19.845 142.128 20.115 ;
     RECT  2.16 20.385 142.128 20.655 ;
     RECT  2.16 20.925 142.128 21.195 ;
     RECT  2.16 21.465 142.128 21.735 ;
     RECT  2.16 22.005 142.128 22.275 ;
     RECT  2.16 22.545 142.128 22.815 ;
     RECT  2.16 23.085 142.128 23.355 ;
     RECT  2.16 23.625 142.128 23.76 ;
    LAYER RVTP ;
     RECT  2.16 2.295 142.128 2.565 ;
     RECT  2.16 2.835 142.128 3.105 ;
     RECT  2.16 3.375 142.128 3.645 ;
     RECT  2.16 3.915 142.128 4.185 ;
     RECT  2.16 4.455 142.128 4.725 ;
     RECT  2.16 4.995 142.128 5.265 ;
     RECT  2.16 5.535 142.128 5.805 ;
     RECT  2.16 6.075 142.128 6.345 ;
     RECT  2.16 6.615 142.128 6.885 ;
     RECT  2.16 7.155 142.128 7.425 ;
     RECT  2.16 7.695 142.128 7.965 ;
     RECT  2.16 8.235 142.128 8.505 ;
     RECT  2.16 8.775 142.128 9.045 ;
     RECT  2.16 9.315 142.128 9.585 ;
     RECT  2.16 9.855 142.128 10.125 ;
     RECT  2.16 10.395 142.128 10.665 ;
     RECT  2.16 10.935 142.128 11.205 ;
     RECT  2.16 11.475 142.128 11.745 ;
     RECT  2.16 12.015 142.128 12.285 ;
     RECT  2.16 12.555 142.128 12.825 ;
     RECT  2.16 13.095 142.128 13.365 ;
     RECT  2.16 13.635 142.128 13.905 ;
     RECT  2.16 14.175 142.128 14.445 ;
     RECT  2.16 14.715 142.128 14.985 ;
     RECT  2.16 15.255 142.128 15.525 ;
     RECT  2.16 15.795 142.128 16.065 ;
     RECT  2.16 16.335 142.128 16.605 ;
     RECT  2.16 16.875 142.128 17.145 ;
     RECT  2.16 17.415 142.128 17.685 ;
     RECT  2.16 17.955 142.128 18.225 ;
     RECT  2.16 18.495 142.128 18.765 ;
     RECT  2.16 19.035 142.128 19.305 ;
     RECT  2.16 19.575 142.128 19.845 ;
     RECT  2.16 20.115 142.128 20.385 ;
     RECT  2.16 20.655 142.128 20.925 ;
     RECT  2.16 21.195 142.128 21.465 ;
     RECT  2.16 21.735 142.128 22.005 ;
     RECT  2.16 22.275 142.128 22.545 ;
     RECT  2.16 22.815 142.128 23.085 ;
     RECT  2.16 23.355 142.128 23.625 ;
    LAYER M1 ;
     RECT  2.16 2.151 142.128 23.769 ;
    LAYER M2 ;
     RECT  1.075 2.034 1.939 2.052 ;
     RECT  1.615 3.114 1.939 3.132 ;
     RECT  1.939 2.034 2.16 3.132 ;
     RECT  1.687 22.896 2.16 22.914 ;
     RECT  0.535 0.531 2.327 0.549 ;
     RECT  2.16 2.034 2.911 23.769 ;
     RECT  2.911 1.962 3.487 23.769 ;
     RECT  3.487 1.926 5.171 23.769 ;
     RECT  5.171 1.962 5.999 23.769 ;
     RECT  5.999 2.106 7.799 23.769 ;
     RECT  7.799 2.151 10.183 23.769 ;
     RECT  10.183 2.106 10.607 23.769 ;
     RECT  10.607 2.151 13.459 23.769 ;
     RECT  13.459 2.106 13.883 23.769 ;
     RECT  13.883 2.151 20.731 23.769 ;
     RECT  20.731 2.106 20.975 23.769 ;
     RECT  20.975 2.151 22.783 23.769 ;
     RECT  22.783 2.106 23.783 23.769 ;
     RECT  23.783 2.151 26.959 23.769 ;
     RECT  26.959 2.106 27.383 23.769 ;
     RECT  27.383 2.151 28.471 23.769 ;
     RECT  28.471 2.106 28.895 23.769 ;
     RECT  28.895 2.151 30.595 23.769 ;
     RECT  30.595 2.106 31.055 23.769 ;
     RECT  31.055 2.151 32.467 23.769 ;
     RECT  32.467 2.106 33.611 23.769 ;
     RECT  33.611 2.151 34.483 23.769 ;
     RECT  34.483 2.106 34.727 23.769 ;
     RECT  34.727 2.151 37.651 23.769 ;
     RECT  37.651 2.106 38.111 23.769 ;
     RECT  38.111 2.151 41.251 23.769 ;
     RECT  41.215 1.152 41.315 1.17 ;
     RECT  41.251 2.106 43.043 23.769 ;
     RECT  43.043 2.151 44.275 23.769 ;
     RECT  44.275 2.106 44.771 23.769 ;
     RECT  44.771 2.151 47.479 23.769 ;
     RECT  47.479 2.106 48.119 23.769 ;
     RECT  48.119 2.151 52.411 23.769 ;
     RECT  52.411 2.106 53.375 23.769 ;
     RECT  53.375 2.151 54.679 23.769 ;
     RECT  54.679 2.106 55.715 23.769 ;
     RECT  55.715 2.151 57.523 23.769 ;
     RECT  57.523 2.106 59.243 23.769 ;
     RECT  59.243 2.151 60.619 23.769 ;
     RECT  60.619 2.106 61.591 23.769 ;
     RECT  61.591 2.034 62.123 23.769 ;
     RECT  62.123 2.151 64.183 23.769 ;
     RECT  64.183 2.106 67.127 23.769 ;
     RECT  67.127 2.151 70.627 23.769 ;
     RECT  70.627 2.106 71.231 23.769 ;
     RECT  71.231 2.151 77.935 23.769 ;
     RECT  77.935 2.106 78.179 23.769 ;
     RECT  78.179 2.151 80.167 23.769 ;
     RECT  80.167 2.106 80.807 23.769 ;
     RECT  80.807 2.151 84.919 23.769 ;
     RECT  84.919 2.106 85.451 23.769 ;
     RECT  85.451 2.151 87.151 23.769 ;
     RECT  87.151 2.106 87.647 23.769 ;
     RECT  87.647 2.151 98.563 23.769 ;
     RECT  98.563 2.106 100.607 23.769 ;
     RECT  100.607 2.151 103.207 23.769 ;
     RECT  103.207 2.106 103.883 23.769 ;
     RECT  103.883 2.151 104.899 23.769 ;
     RECT  104.899 2.034 105.755 23.769 ;
     RECT  106.267 1.152 106.367 1.17 ;
     RECT  105.755 2.151 108.103 23.769 ;
     RECT  108.319 1.152 108.419 1.17 ;
     RECT  108.103 2.106 110.579 23.769 ;
     RECT  110.579 2.151 112.099 23.769 ;
     RECT  112.099 2.106 112.171 23.769 ;
     RECT  112.171 2.034 113.495 23.769 ;
     RECT  113.495 2.151 115.627 23.769 ;
     RECT  115.627 2.106 116.447 23.769 ;
     RECT  116.447 2.151 119.119 23.769 ;
     RECT  119.119 2.106 119.471 23.769 ;
     RECT  119.471 2.151 121.387 23.769 ;
     RECT  121.387 2.106 122.863 23.769 ;
     RECT  122.863 1.962 124.079 23.769 ;
     RECT  124.079 2.034 124.763 23.769 ;
     RECT  124.763 2.151 128.227 23.769 ;
     RECT  128.227 2.106 128.263 23.769 ;
     RECT  128.263 2.07 128.471 23.769 ;
     RECT  128.471 2.106 128.759 23.769 ;
     RECT  128.759 2.151 134.167 23.769 ;
     RECT  134.167 2.106 134.663 23.769 ;
     RECT  134.663 2.151 135.499 23.769 ;
     RECT  135.499 2.106 135.923 23.769 ;
     RECT  135.923 2.151 138.991 23.769 ;
     RECT  138.991 2.034 140.899 23.769 ;
     RECT  140.899 1.962 142.128 23.769 ;
     RECT  142.128 1.962 142.151 5.994 ;
     RECT  142.128 19.35 142.151 22.23 ;
     RECT  142.128 23.058 142.151 23.148 ;
     RECT  142.151 4.896 142.403 5.994 ;
     RECT  142.151 1.962 142.439 3.834 ;
     RECT  142.439 1.962 142.475 2.934 ;
     RECT  142.475 2.034 142.511 2.934 ;
     RECT  142.151 19.35 142.619 19.368 ;
     RECT  142.151 20.16 142.763 22.23 ;
     RECT  142.403 4.896 142.799 5.364 ;
     RECT  142.511 2.034 142.907 2.754 ;
     RECT  142.151 23.13 143.087 23.148 ;
     RECT  142.799 4.896 143.339 5.094 ;
     RECT  142.763 20.628 143.339 22.23 ;
     RECT  143.339 21.132 143.411 22.23 ;
     RECT  143.339 4.896 143.483 4.914 ;
     RECT  142.128 7.236 143.519 7.254 ;
     RECT  142.907 2.736 143.627 2.754 ;
     RECT  142.128 18.036 143.627 18.054 ;
     RECT  143.411 22.212 143.843 22.23 ;
     RECT  143.411 21.132 144.059 21.15 ;
     RECT  142.439 3.816 144.167 3.834 ;
    LAYER M3 ;
     RECT  22.68 0.091 22.698 0.139 ;
     RECT  47.088 0.091 48.078 0.139 ;
     RECT  50.292 0.091 50.31 0.139 ;
     RECT  52.272 0.091 52.29 0.139 ;
     RECT  76.068 0.091 76.734 0.139 ;
     RECT  85.284 0.091 85.302 0.139 ;
     RECT  95.724 0.091 96.678 0.139 ;
     RECT  98.424 0.091 98.442 0.139 ;
     RECT  100.908 0.091 100.926 0.139 ;
     RECT  101.844 0.091 101.862 0.139 ;
     RECT  102.672 0.091 102.69 0.139 ;
     RECT  104.076 0.091 104.094 0.139 ;
     RECT  133.308 0.091 133.326 0.139 ;
     RECT  39.672 0.091 39.69 0.187 ;
     RECT  70.308 0.091 70.326 0.235 ;
     RECT  20.988 0.091 21.294 0.523 ;
     RECT  31.68 0.091 31.698 0.523 ;
     RECT  39.636 0.187 39.69 0.523 ;
     RECT  44.82 0.091 44.838 0.523 ;
     RECT  71.1 0.091 71.118 0.523 ;
     RECT  72.036 0.091 72.774 0.523 ;
     RECT  141.444 0.091 142.398 0.523 ;
     RECT  143.316 0.091 143.478 0.523 ;
     RECT  2.808 0.091 2.826 0.526 ;
     RECT  0.54 0.52 0.558 0.557 ;
     RECT  15.228 0.091 15.93 0.571 ;
     RECT  18.144 0.091 18.486 0.571 ;
     RECT  26.676 0.091 27.234 0.571 ;
     RECT  31.68 0.523 32.346 0.571 ;
     RECT  52.272 0.139 52.542 0.571 ;
     RECT  64.836 0.091 65.394 0.571 ;
     RECT  88.236 0.091 88.254 0.571 ;
     RECT  100.476 0.139 100.926 0.571 ;
     RECT  101.844 0.139 102.69 0.571 ;
     RECT  106.344 0.091 106.83 0.571 ;
     RECT  129.852 0.091 129.87 0.571 ;
     RECT  140.544 0.091 140.562 0.571 ;
     RECT  63.756 0.571 63.774 0.619 ;
     RECT  64.764 0.571 65.394 0.619 ;
     RECT  9.288 0.523 9.306 1.099 ;
     RECT  31.68 0.571 32.994 1.099 ;
     RECT  41.22 0.091 41.238 1.099 ;
     RECT  67.752 0.091 67.77 1.099 ;
     RECT  68.904 0.091 68.922 1.099 ;
     RECT  95.724 0.139 96.75 1.099 ;
     RECT  98.136 0.139 98.55 1.099 ;
     RECT  106.344 0.571 107.478 1.099 ;
     RECT  22.572 0.139 22.698 1.147 ;
     RECT  36.612 0.091 36.99 1.147 ;
     RECT  63.612 0.619 65.394 1.147 ;
     RECT  66.312 0.091 66.33 1.147 ;
     RECT  76.068 0.139 77.058 1.147 ;
     RECT  94.104 0.091 94.122 1.147 ;
     RECT  95.184 1.099 96.75 1.147 ;
     RECT  106.308 1.099 107.478 1.147 ;
     RECT  108.324 0.091 108.342 1.147 ;
     RECT  109.512 0.523 109.53 1.147 ;
     RECT  117.468 0.091 117.486 1.147 ;
     RECT  118.404 0.571 118.422 1.147 ;
     RECT  136.08 0.091 136.458 1.147 ;
     RECT  141.444 0.523 144.162 1.147 ;
     RECT  75.528 1.147 77.274 1.627 ;
     RECT  75.528 1.627 77.418 1.675 ;
     RECT  122.292 0.091 122.31 1.675 ;
     RECT  135.972 1.147 136.458 1.675 ;
     RECT  137.304 1.147 137.322 1.675 ;
     RECT  140.508 0.571 140.562 1.675 ;
     RECT  2.304 0.526 2.826 1.723 ;
     RECT  8.928 1.099 9.306 1.723 ;
     RECT  11.808 0.091 11.826 1.723 ;
     RECT  15.228 0.571 16.434 1.723 ;
     RECT  18.144 0.571 18.99 1.723 ;
     RECT  19.764 0.571 19.782 1.723 ;
     RECT  20.916 0.523 21.294 1.723 ;
     RECT  22.14 1.147 22.698 1.723 ;
     RECT  26.676 0.571 28.35 1.723 ;
     RECT  31.068 1.099 32.994 1.723 ;
     RECT  34.38 0.571 34.398 1.723 ;
     RECT  36.612 1.147 37.638 1.723 ;
     RECT  39.636 0.523 40.158 1.723 ;
     RECT  41.22 1.099 41.922 1.723 ;
     RECT  43.236 0.571 43.254 1.723 ;
     RECT  44.352 0.523 44.838 1.723 ;
     RECT  45.972 1.675 45.99 1.723 ;
     RECT  46.98 0.139 48.078 1.723 ;
     RECT  50.292 0.139 50.598 1.723 ;
     RECT  52.272 0.571 52.758 1.723 ;
     RECT  53.892 0.571 53.91 1.723 ;
     RECT  54.756 0.091 55.638 1.723 ;
     RECT  58.464 0.091 58.482 1.723 ;
     RECT  59.94 0.091 60.174 1.723 ;
     RECT  61.632 0.091 61.65 1.723 ;
     RECT  63.612 1.147 66.33 1.723 ;
     RECT  67.752 1.099 68.922 1.723 ;
     RECT  69.804 0.235 70.326 1.723 ;
     RECT  71.1 0.523 72.774 1.723 ;
     RECT  74.232 0.091 74.25 1.723 ;
     RECT  75.312 1.675 77.418 1.723 ;
     RECT  79.2 0.091 79.218 1.723 ;
     RECT  80.46 0.091 80.478 1.723 ;
     RECT  81.756 0.571 81.774 1.723 ;
     RECT  82.944 0.091 82.962 1.723 ;
     RECT  84.816 0.139 85.302 1.723 ;
     RECT  87.588 0.571 88.254 1.723 ;
     RECT  89.352 0.091 89.874 1.723 ;
     RECT  91.584 0.091 91.602 1.723 ;
     RECT  93.24 0.091 93.258 1.723 ;
     RECT  94.104 1.147 96.75 1.723 ;
     RECT  98.136 1.099 99.234 1.723 ;
     RECT  100.476 0.571 102.69 1.723 ;
     RECT  104.004 0.139 104.094 1.723 ;
     RECT  106.272 1.147 107.478 1.723 ;
     RECT  108.324 1.147 109.53 1.723 ;
     RECT  110.376 0.091 110.394 1.723 ;
     RECT  111.24 0.091 111.258 1.723 ;
     RECT  112.14 0.091 112.158 1.723 ;
     RECT  113.796 0.091 113.814 1.723 ;
     RECT  114.732 0.091 114.75 1.723 ;
     RECT  116.64 1.147 116.658 1.723 ;
     RECT  117.468 1.147 118.422 1.723 ;
     RECT  120.096 0.091 120.762 1.723 ;
     RECT  122.292 1.675 122.634 1.723 ;
     RECT  123.588 0.091 123.93 1.723 ;
     RECT  125.604 0.091 125.622 1.723 ;
     RECT  127.8 0.091 127.818 1.723 ;
     RECT  129.852 0.571 130.518 1.723 ;
     RECT  131.472 0.091 132.174 1.723 ;
     RECT  133.308 0.139 133.722 1.723 ;
     RECT  134.892 0.091 134.91 1.723 ;
     RECT  135.972 1.675 137.322 1.723 ;
     RECT  138.168 0.091 138.186 1.723 ;
     RECT  139.14 0.091 139.59 1.723 ;
     RECT  140.4 1.675 140.562 1.723 ;
     RECT  1.944 1.723 14.022 1.771 ;
     RECT  69.768 1.723 77.886 1.771 ;
     RECT  78.624 1.723 82.962 1.771 ;
     RECT  83.736 1.723 83.754 1.771 ;
     RECT  84.816 1.723 90.414 1.771 ;
     RECT  91.152 1.723 110.394 1.771 ;
     RECT  111.132 1.723 140.562 1.771 ;
     RECT  141.3 1.147 144.162 1.771 ;
     RECT  69.768 1.771 83.754 1.819 ;
     RECT  84.816 1.771 110.394 2.011 ;
     RECT  111.132 1.771 144.162 2.011 ;
     RECT  1.08 1.723 1.098 2.057 ;
     RECT  15.228 1.723 34.974 2.155 ;
     RECT  36.216 1.723 68.958 2.155 ;
     RECT  69.768 1.819 83.79 2.155 ;
     RECT  84.816 2.011 144.162 2.155 ;
     RECT  1.944 1.771 14.166 2.191 ;
     RECT  14.94 2.155 34.974 2.191 ;
     RECT  36.216 2.155 144.162 2.191 ;
     RECT  1.944 2.191 144.162 2.875 ;
     RECT  1.62 2.875 144.162 3.137 ;
     RECT  2.232 3.137 144.162 3.839 ;
     RECT  2.232 3.839 143.514 3.955 ;
     RECT  2.196 3.955 143.514 5.369 ;
     RECT  2.196 5.369 142.398 5.999 ;
     RECT  143.496 5.369 143.514 7.259 ;
     RECT  2.196 5.999 142.11 7.349 ;
     RECT  2.268 7.349 142.11 8.195 ;
     RECT  2.268 8.195 142.074 8.429 ;
     RECT  2.415 8.429 142.074 8.699 ;
     RECT  129.456 8.699 142.074 9.077 ;
     RECT  2.415 8.699 128.646 9.211 ;
     RECT  2.376 9.211 128.646 9.239 ;
     RECT  2.376 9.239 58.41 9.293 ;
     RECT  2.415 9.293 58.41 9.509 ;
     RECT  79.236 9.239 97.938 9.509 ;
     RECT  129.528 9.077 142.074 9.779 ;
     RECT  129.528 9.779 141.786 10.049 ;
     RECT  129.528 10.049 141.75 10.319 ;
     RECT  2.415 9.509 38.502 10.843 ;
     RECT  39.276 9.509 58.41 10.843 ;
     RECT  2.415 10.843 58.41 11.399 ;
     RECT  59.148 9.239 78.498 11.939 ;
     RECT  59.292 11.939 78.498 12.091 ;
     RECT  79.272 9.509 97.938 12.091 ;
     RECT  129.528 10.319 141.606 12.325 ;
     RECT  39.276 11.399 58.41 12.559 ;
     RECT  129.528 12.325 141.714 12.721 ;
     RECT  2.415 11.399 38.502 12.901 ;
     RECT  39.276 12.559 58.446 12.901 ;
     RECT  59.292 12.091 97.938 12.901 ;
     RECT  98.676 9.239 128.646 12.901 ;
     RECT  129.456 12.721 141.714 12.901 ;
     RECT  59.292 12.901 128.646 13.063 ;
     RECT  129.384 12.901 141.75 13.063 ;
     RECT  2.415 12.901 58.482 13.099 ;
     RECT  59.292 13.063 141.75 13.099 ;
     RECT  2.415 13.099 141.75 13.261 ;
     RECT  2.415 13.261 141.822 14.827 ;
     RECT  2.415 14.827 141.894 15.331 ;
     RECT  2.415 15.331 142.002 16.411 ;
     RECT  2.376 16.411 142.002 16.645 ;
     RECT  2.376 16.645 142.074 17.339 ;
     RECT  71.748 17.339 142.074 17.609 ;
     RECT  2.376 17.339 71.01 17.611 ;
     RECT  129.744 17.609 142.074 17.725 ;
     RECT  71.748 17.609 128.97 18.571 ;
     RECT  129.744 17.725 142.11 18.571 ;
     RECT  71.748 18.571 142.11 19.345 ;
     RECT  2.304 17.611 71.01 19.543 ;
     RECT  2.268 19.543 71.01 19.579 ;
     RECT  71.748 19.345 142.614 19.579 ;
     RECT  2.268 19.579 142.614 20.155 ;
     RECT  2.268 20.155 142.758 20.623 ;
     RECT  143.604 18.031 143.622 20.623 ;
     RECT  2.268 20.623 143.622 21.127 ;
     RECT  2.268 21.127 144.054 22.891 ;
     RECT  1.692 22.891 144.054 23.405 ;
     RECT  2.304 23.405 144.054 23.549 ;
     RECT  2.304 23.549 16.11 23.585 ;
     RECT  66.348 23.549 81.09 23.585 ;
     RECT  123.588 23.549 144.054 23.585 ;
     RECT  36.144 23.549 38.358 23.621 ;
     RECT  39.096 23.549 39.258 23.621 ;
     RECT  66.348 23.585 68.454 23.621 ;
     RECT  81.864 23.549 92.79 23.621 ;
     RECT  93.564 23.549 94.878 23.621 ;
     RECT  96.12 23.549 113.85 23.621 ;
     RECT  133.992 23.585 144.054 23.621 ;
     RECT  41.184 23.549 51.282 23.657 ;
     RECT  69.228 23.585 81.09 23.657 ;
     RECT  133.992 23.621 138.582 23.657 ;
     RECT  2.304 23.585 6.858 23.693 ;
     RECT  24.015 23.549 35.226 23.693 ;
     RECT  123.588 23.585 133.146 23.693 ;
     RECT  7.596 23.585 16.11 23.729 ;
     RECT  16.92 23.549 23.058 23.729 ;
     RECT  24.015 23.693 25.794 23.729 ;
     RECT  26.712 23.693 35.226 23.729 ;
     RECT  40.14 23.549 40.305 23.729 ;
     RECT  41.4 23.657 51.282 23.729 ;
     RECT  52.092 23.549 65.178 23.729 ;
     RECT  67.14 23.621 67.986 23.729 ;
     RECT  69.228 23.657 78.534 23.729 ;
     RECT  79.308 23.657 81.09 23.729 ;
     RECT  81.864 23.621 82.386 23.729 ;
     RECT  84.816 23.621 92.718 23.729 ;
     RECT  96.336 23.621 98.154 23.729 ;
     RECT  98.928 23.621 113.85 23.729 ;
     RECT  122.616 23.549 122.85 23.729 ;
     RECT  123.588 23.693 124.002 23.729 ;
     RECT  139.464 23.621 139.734 23.729 ;
     RECT  52.092 23.729 64.026 23.741 ;
     RECT  67.14 23.729 67.77 23.741 ;
     RECT  69.516 23.729 78.462 23.741 ;
     RECT  84.816 23.729 86.562 23.741 ;
     RECT  124.992 23.693 133.146 23.741 ;
     RECT  134.532 23.657 137.862 23.741 ;
     RECT  140.472 23.621 144.054 23.741 ;
     RECT  18.615 23.729 23.058 23.777 ;
     RECT  24.015 23.729 25.218 23.777 ;
     RECT  40.215 23.729 40.305 23.777 ;
     RECT  51.015 23.729 51.282 23.777 ;
     RECT  67.14 23.741 67.305 23.777 ;
     RECT  87.336 23.729 92.718 23.777 ;
     RECT  104.292 23.729 113.85 23.777 ;
     RECT  84.924 23.741 86.562 23.789 ;
     RECT  9.468 23.729 14.706 23.885 ;
     RECT  18.936 23.777 23.058 23.885 ;
     RECT  24.156 23.777 25.218 23.885 ;
     RECT  41.4 23.729 50.238 23.885 ;
     RECT  51.156 23.777 51.282 23.885 ;
     RECT  69.516 23.741 77.058 23.885 ;
     RECT  85.356 23.789 86.562 23.885 ;
     RECT  87.336 23.777 88.398 23.885 ;
     RECT  89.352 23.777 92.718 23.885 ;
     RECT  114.588 23.549 121.41 23.885 ;
     RECT  137.34 23.741 137.862 23.885 ;
     RECT  3.744 23.693 6.858 23.933 ;
     RECT  7.596 23.729 8.658 23.933 ;
     RECT  9.468 23.885 9.486 23.933 ;
     RECT  10.296 23.885 14.706 23.933 ;
     RECT  15.48 23.729 15.894 23.933 ;
     RECT  16.92 23.729 17.802 23.933 ;
     RECT  18.936 23.885 22.086 23.933 ;
     RECT  22.824 23.885 23.058 23.933 ;
     RECT  24.516 23.885 25.218 23.933 ;
     RECT  26.712 23.729 30.834 23.933 ;
     RECT  31.572 23.729 35.226 23.933 ;
     RECT  36.144 23.621 38.25 23.933 ;
     RECT  39.24 23.621 39.258 23.933 ;
     RECT  41.4 23.885 48.87 23.933 ;
     RECT  49.716 23.885 50.238 23.933 ;
     RECT  51.156 23.885 51.174 23.933 ;
     RECT  52.092 23.741 62.406 23.933 ;
     RECT  64.908 23.729 65.178 23.933 ;
     RECT  66.348 23.621 66.366 23.933 ;
     RECT  67.14 23.777 67.194 23.933 ;
     RECT  69.516 23.885 75.33 23.933 ;
     RECT  76.104 23.885 77.058 23.933 ;
     RECT  77.976 23.741 78.462 23.933 ;
     RECT  79.308 23.729 80.838 23.933 ;
     RECT  83.196 23.621 84.078 23.933 ;
     RECT  85.464 23.885 86.562 23.933 ;
     RECT  87.336 23.885 88.326 23.933 ;
     RECT  89.424 23.885 92.718 23.933 ;
     RECT  93.672 23.621 94.878 23.933 ;
     RECT  96.588 23.729 98.154 23.933 ;
     RECT  98.928 23.729 103.554 23.933 ;
     RECT  104.292 23.777 110.106 23.933 ;
     RECT  111.132 23.777 113.85 23.933 ;
     RECT  114.588 23.885 115.506 23.933 ;
     RECT  116.244 23.885 121.194 23.933 ;
     RECT  122.616 23.729 122.742 23.933 ;
     RECT  124.992 23.741 132.786 23.933 ;
     RECT  134.532 23.741 136.242 23.933 ;
     RECT  137.556 23.885 137.79 23.933 ;
     RECT  139.464 23.729 139.482 23.933 ;
     RECT  141.192 23.741 144.054 23.933 ;
     RECT  18.936 23.933 21.15 23.981 ;
     RECT  22.968 23.933 22.986 23.981 ;
     RECT  24.516 23.933 25.038 23.981 ;
     RECT  26.712 23.933 26.802 23.981 ;
     RECT  35.208 23.933 35.226 23.981 ;
     RECT  43.74 23.933 43.758 23.981 ;
     RECT  47.232 23.933 47.25 23.981 ;
     RECT  48.492 23.933 48.51 23.981 ;
     RECT  53.028 23.933 53.046 23.981 ;
     RECT  54.036 23.933 54.342 23.981 ;
     RECT  56.988 23.933 57.006 23.981 ;
     RECT  58.932 23.933 59.166 23.981 ;
     RECT  72.936 23.933 72.954 23.981 ;
     RECT  91.368 23.933 91.53 23.981 ;
     RECT  102.6 23.933 103.086 23.981 ;
     RECT  116.82 23.933 116.838 23.981 ;
     RECT  19.692 23.981 20.682 24.029 ;
     RECT  61.74 23.933 61.758 24.029 ;
     RECT  89.424 23.933 89.442 24.029 ;
     RECT  125.316 23.933 125.334 24.029 ;
     RECT  127.044 23.933 127.638 24.029 ;
     RECT  131.004 23.933 131.022 24.029 ;
     RECT  2.304 23.693 2.862 24.077 ;
     RECT  3.744 23.933 4.374 24.509 ;
     RECT  8.208 23.933 8.586 24.509 ;
     RECT  18.936 23.981 18.954 24.509 ;
     RECT  79.308 23.933 79.326 24.509 ;
     RECT  10.836 23.933 11.286 24.557 ;
     RECT  12.744 23.933 14.706 24.557 ;
     RECT  15.588 23.933 15.894 24.557 ;
     RECT  16.92 23.933 17.01 24.557 ;
     RECT  27.864 23.933 27.882 24.557 ;
     RECT  30.528 23.933 30.762 24.557 ;
     RECT  33.336 23.933 33.93 24.557 ;
     RECT  37.008 23.933 38.25 24.557 ;
     RECT  41.544 23.933 42.138 24.557 ;
     RECT  63.216 23.741 64.026 24.557 ;
     RECT  67.14 23.933 67.158 24.557 ;
     RECT  86.544 23.933 86.562 24.557 ;
     RECT  112.716 23.933 112.734 24.557 ;
     RECT  114.588 23.933 115.182 24.557 ;
     RECT  123.588 23.729 123.606 24.557 ;
     RECT  129.276 23.933 129.294 24.557 ;
     RECT  137.772 23.933 137.79 24.557 ;
     RECT  30.528 24.557 30.546 24.605 ;
     RECT  60.372 23.933 60.642 24.989 ;
     RECT  19.692 24.029 20.466 25.037 ;
     RECT  5.112 23.933 5.13 25.085 ;
     RECT  13.644 24.557 14.706 25.085 ;
     RECT  15.588 24.557 15.606 25.085 ;
     RECT  17.748 23.933 17.766 25.085 ;
     RECT  19.908 25.037 20.466 25.085 ;
     RECT  22.068 23.933 22.086 25.085 ;
     RECT  60.624 24.989 60.642 25.085 ;
     RECT  63.252 24.557 64.026 25.085 ;
     RECT  122.724 23.933 122.742 25.085 ;
     RECT  134.532 23.933 134.55 25.085 ;
     RECT  8.568 24.509 8.586 25.133 ;
     RECT  11.268 24.557 11.286 25.133 ;
     RECT  14.22 25.085 14.706 25.133 ;
     RECT  16.992 24.557 17.01 25.133 ;
     RECT  24.516 23.981 24.534 25.133 ;
     RECT  26.784 23.981 26.802 25.133 ;
     RECT  28.728 23.933 28.746 25.133 ;
     RECT  31.896 23.933 31.914 25.133 ;
     RECT  36.144 23.933 36.162 25.133 ;
     RECT  80.1 23.933 80.838 25.133 ;
     RECT  82.008 23.729 82.386 25.133 ;
     RECT  91.368 23.981 91.386 25.133 ;
     RECT  93.96 23.933 93.978 25.133 ;
     RECT  98.928 23.933 98.946 25.133 ;
     RECT  101.34 23.933 101.646 25.133 ;
     RECT  103.068 23.981 103.086 25.133 ;
     RECT  105.984 23.933 106.074 25.133 ;
     RECT  2.844 24.077 2.862 25.805 ;
     RECT  4.356 24.509 4.374 25.805 ;
     RECT  12.744 24.557 12.762 25.805 ;
     RECT  38.232 24.557 38.25 25.805 ;
     RECT  54.324 23.981 54.342 25.805 ;
     RECT  58.932 23.981 58.95 25.805 ;
     RECT  64.008 25.085 64.026 25.805 ;
     RECT  80.1 25.133 80.442 25.805 ;
     RECT  97.884 23.933 97.902 25.805 ;
     RECT  106.056 25.133 106.074 25.805 ;
     RECT  108.864 23.933 108.882 25.805 ;
     RECT  113.832 23.933 113.85 25.805 ;
     RECT  115.164 24.557 115.182 25.805 ;
     RECT  120.708 23.933 120.726 25.805 ;
     RECT  130.14 23.933 130.158 25.805 ;
     RECT  135.9 23.933 135.918 25.805 ;
     RECT  141.48 23.933 144.054 25.805 ;
     RECT  72.144 25.819 72.162 25.901 ;
    LAYER M4 ;
     RECT  0.133 1.92 0.325 1.944 ;
     RECT  0.133 21.792 0.517 21.816 ;
     RECT  0.485 0.528 0.569 0.552 ;
     RECT  0.325 1.776 0.661 1.944 ;
     RECT  0.661 1.776 0.853 2.28 ;
     RECT  0.517 21.792 0.853 22.776 ;
     RECT  0.853 1.776 1.025 2.328 ;
     RECT  0.325 20.448 1.045 20.472 ;
     RECT  1.237 3.504 1.381 3.528 ;
     RECT  1.045 20.4 1.381 20.472 ;
     RECT  0.853 21.792 1.381 23.688 ;
     RECT  1.025 1.728 1.565 2.328 ;
     RECT  1.381 3.408 1.565 3.528 ;
     RECT  0.661 25.68 1.573 25.704 ;
     RECT  1.381 20.4 1.765 23.688 ;
     RECT  1.765 4.56 2.293 4.584 ;
     RECT  1.765 19.824 2.293 23.688 ;
     RECT  1.909 17.616 2.329 17.64 ;
     RECT  2.293 6.384 2.365 6.408 ;
     RECT  1.565 1.728 2.408 3.528 ;
     RECT  2.293 4.56 2.408 5.112 ;
     RECT  2.365 6.384 2.408 6.888 ;
     RECT  2.365 9.264 2.408 9.288 ;
     RECT  2.329 17.616 2.408 17.736 ;
     RECT  2.293 19.824 2.408 24.072 ;
     RECT  2.408 1.728 2.704 24.072 ;
     RECT  2.704 20.4 2.801 24.072 ;
     RECT  2.704 1.728 2.819 9.288 ;
     RECT  2.293 0.096 2.837 0.12 ;
     RECT  2.801 23.376 2.867 24.072 ;
     RECT  2.801 20.4 2.873 22.104 ;
     RECT  1.573 25.68 2.915 25.8 ;
     RECT  2.704 10.848 2.953 10.872 ;
     RECT  2.873 20.448 3.089 22.104 ;
     RECT  2.819 1.728 3.203 9.144 ;
     RECT  3.203 6.192 3.341 9.144 ;
     RECT  2.704 17.088 3.341 18.792 ;
     RECT  3.089 20.88 3.377 22.104 ;
     RECT  3.377 20.88 3.413 21.72 ;
     RECT  3.341 6.192 3.441 9.048 ;
     RECT  3.413 20.88 3.449 21.096 ;
     RECT  3.203 1.728 3.593 5.16 ;
     RECT  3.441 7.344 3.629 9.048 ;
     RECT  3.341 17.088 3.629 17.112 ;
     RECT  3.593 1.728 3.724 4.104 ;
     RECT  2.867 23.952 3.733 24.072 ;
     RECT  3.629 7.344 3.737 8.424 ;
     RECT  3.341 18.144 3.805 18.792 ;
     RECT  2.704 14.832 3.845 14.856 ;
     RECT  2.704 15.936 3.877 15.96 ;
     RECT  3.449 21.072 3.997 21.096 ;
     RECT  3.733 23.952 4.069 24.504 ;
     RECT  3.593 5.136 4.273 5.16 ;
     RECT  3.441 6.192 4.273 6.264 ;
     RECT  4.069 23.904 4.307 24.504 ;
     RECT  4.307 23.904 4.381 23.928 ;
     RECT  3.737 7.392 4.385 8.424 ;
     RECT  2.915 25.776 4.385 25.8 ;
     RECT  3.877 15.936 4.417 16.872 ;
     RECT  3.805 18.144 4.565 18.84 ;
     RECT  4.417 15.888 4.597 16.872 ;
     RECT  4.645 8.976 4.732 9 ;
     RECT  4.565 18.576 4.733 18.84 ;
     RECT  4.597 15.888 4.787 17.592 ;
     RECT  4.273 5.136 4.885 6.264 ;
     RECT  4.385 7.392 4.885 7.992 ;
     RECT  3.724 1.728 4.889 3.96 ;
     RECT  4.885 5.136 5.033 7.992 ;
     RECT  4.733 18.576 5.077 19.416 ;
     RECT  5.077 18.576 5.123 19.464 ;
     RECT  4.787 16.848 5.213 17.592 ;
     RECT  5.101 25.056 5.219 25.08 ;
     RECT  4.889 3.936 5.281 3.96 ;
     RECT  5.033 5.136 5.281 7.896 ;
     RECT  5.213 16.848 5.393 16.968 ;
     RECT  5.393 16.944 5.429 16.968 ;
     RECT  4.889 1.728 5.645 2.808 ;
     RECT  5.605 21.648 5.701 21.672 ;
     RECT  5.701 21.648 5.789 21.768 ;
     RECT  5.281 3.936 6.005 7.896 ;
     RECT  5.123 18.816 6.073 19.464 ;
     RECT  5.645 1.728 6.22 2.76 ;
     RECT  6.005 3.936 6.293 7.512 ;
     RECT  6.293 3.936 6.437 7.464 ;
     RECT  6.437 3.936 6.509 3.96 ;
     RECT  6.073 18.816 6.685 19.8 ;
     RECT  5.789 21.648 6.829 21.672 ;
     RECT  6.22 1.728 6.833 2.232 ;
     RECT  4.381 23.376 6.937 23.928 ;
     RECT  6.685 18.816 6.949 19.992 ;
     RECT  6.829 21.648 7.429 22.008 ;
     RECT  7.441 4.128 7.513 4.152 ;
     RECT  7.513 3.936 7.669 4.152 ;
     RECT  6.437 5.184 7.669 7.464 ;
     RECT  7.429 25.728 7.715 25.752 ;
     RECT  6.833 1.728 7.808 2.088 ;
     RECT  7.669 3.36 7.808 4.152 ;
     RECT  7.669 5.184 7.808 8.184 ;
     RECT  6.949 18.72 7.808 19.992 ;
     RECT  7.429 21.264 7.808 22.008 ;
     RECT  6.937 23.28 7.808 23.928 ;
     RECT  7.808 1.728 8.104 23.928 ;
     RECT  8.104 21.216 8.197 23.928 ;
     RECT  8.104 18.72 8.273 19.8 ;
     RECT  8.197 21.216 8.281 24.504 ;
     RECT  8.104 3.84 8.291 6.936 ;
     RECT  8.104 8.544 8.425 8.568 ;
     RECT  8.281 21.216 8.531 23.928 ;
     RECT  8.531 21.216 8.561 21.672 ;
     RECT  8.557 25.104 8.771 25.128 ;
     RECT  8.561 21.648 8.849 21.672 ;
     RECT  8.104 1.728 8.876 2.184 ;
     RECT  8.876 1.104 8.963 2.184 ;
     RECT  8.291 3.888 9.313 6.936 ;
     RECT  9.26 0.528 9.347 0.552 ;
     RECT  9.313 3.408 9.353 6.936 ;
     RECT  9.353 5.184 9.461 6.936 ;
     RECT  8.273 19.488 9.493 19.8 ;
     RECT  8.963 1.728 9.596 2.184 ;
     RECT  8.531 23.376 9.673 23.928 ;
     RECT  9.596 1.728 9.683 2.28 ;
     RECT  9.353 3.408 9.853 3.96 ;
     RECT  9.683 1.728 9.857 2.184 ;
     RECT  9.673 22.8 9.875 23.928 ;
     RECT  9.493 19.488 10.213 20.52 ;
     RECT  10.213 19.488 10.261 21.144 ;
     RECT  10.261 19.488 10.469 21.192 ;
     RECT  10.357 25.728 10.547 25.752 ;
     RECT  10.501 22.176 10.585 22.2 ;
     RECT  9.461 5.184 10.643 6.888 ;
     RECT  9.875 23.376 10.825 23.928 ;
     RECT  9.857 1.728 10.885 1.896 ;
     RECT  10.469 19.488 11.009 21.144 ;
     RECT  10.825 23.376 11.123 24.552 ;
     RECT  10.643 5.184 11.153 6.792 ;
     RECT  10.885 1.728 11.429 2.328 ;
     RECT  9.853 3.312 11.429 3.96 ;
     RECT  11.429 1.728 11.461 3.96 ;
     RECT  11.153 5.184 11.461 6.408 ;
     RECT  11.257 25.104 11.507 25.128 ;
     RECT  11.461 1.728 11.548 6.408 ;
     RECT  11.548 4.608 11.747 6.408 ;
     RECT  11.605 0.096 11.837 0.12 ;
     RECT  11.123 23.376 11.843 23.928 ;
     RECT  11.009 19.488 11.941 20.472 ;
     RECT  11.548 1.728 12.017 3.336 ;
     RECT  11.941 19.344 12.053 20.472 ;
     RECT  12.689 25.776 12.773 25.8 ;
     RECT  12.193 6.816 12.949 6.84 ;
     RECT  11.843 23.856 13.021 23.928 ;
     RECT  12.053 19.344 13.129 20.184 ;
     RECT  12.017 1.728 13.208 2.904 ;
     RECT  11.747 4.608 13.208 5.64 ;
     RECT  12.949 6.816 13.208 7.368 ;
     RECT  13.129 19.344 13.208 21 ;
     RECT  13.021 23.856 13.208 24.552 ;
     RECT  13.208 1.728 13.283 24.552 ;
     RECT  13.283 1.728 13.504 23.928 ;
     RECT  13.504 19.584 13.619 23.928 ;
     RECT  13.619 22.128 13.889 23.928 ;
     RECT  13.504 1.728 14.033 2.328 ;
     RECT  13.633 25.056 14.209 25.08 ;
     RECT  13.619 19.584 14.243 21.144 ;
     RECT  13.504 5.472 14.285 7.368 ;
     RECT  13.889 23.376 14.317 23.928 ;
     RECT  14.209 25.056 14.317 25.128 ;
     RECT  13.889 22.128 14.321 22.152 ;
     RECT  14.033 1.776 14.501 2.328 ;
     RECT  14.317 23.376 14.867 25.128 ;
     RECT  14.243 20.112 14.893 21.144 ;
     RECT  14.285 5.472 15.001 6.84 ;
     RECT  14.485 0.144 15.013 0.168 ;
     RECT  15.001 4.512 15.109 6.84 ;
     RECT  14.867 25.056 15.251 25.128 ;
     RECT  14.893 20.112 15.325 21.384 ;
     RECT  14.501 1.776 15.397 2.184 ;
     RECT  14.867 23.376 15.397 23.928 ;
     RECT  15.397 22.704 15.509 23.928 ;
     RECT  15.397 1.728 15.613 2.184 ;
     RECT  15.109 3.936 15.833 6.84 ;
     RECT  15.509 23.376 15.833 23.928 ;
     RECT  15.251 25.056 15.865 25.08 ;
     RECT  15.013 0.096 15.941 0.168 ;
     RECT  15.833 3.936 15.971 5.736 ;
     RECT  15.325 19.968 16.409 21.384 ;
     RECT  16.261 0.576 16.445 0.6 ;
     RECT  16.409 19.968 16.661 21.144 ;
     RECT  15.833 23.376 16.691 23.4 ;
     RECT  15.865 24.528 16.837 25.08 ;
     RECT  15.613 1.728 16.873 2.28 ;
     RECT  16.661 19.968 16.873 21 ;
     RECT  16.837 23.808 16.981 25.08 ;
     RECT  16.981 23.808 17.057 25.128 ;
     RECT  17.057 23.904 17.219 25.128 ;
     RECT  16.873 19.344 17.309 21 ;
     RECT  16.873 1.728 17.381 2.76 ;
     RECT  17.219 23.904 17.813 23.928 ;
     RECT  15.971 3.936 18.025 3.96 ;
     RECT  15.971 5.088 18.025 5.736 ;
     RECT  17.125 22.512 18.025 22.776 ;
     RECT  18.025 22.512 18.061 23.772 ;
     RECT  17.219 25.056 18.275 25.128 ;
     RECT  18.025 3.936 18.465 5.736 ;
     RECT  17.893 0.096 18.497 0.12 ;
     RECT  17.381 1.728 18.608 1.896 ;
     RECT  18.465 3.36 18.608 5.736 ;
     RECT  15.833 6.816 18.608 6.84 ;
     RECT  17.309 20.112 18.608 21 ;
     RECT  18.061 22.176 18.608 23.772 ;
     RECT  18.608 1.728 18.805 23.772 ;
     RECT  18.805 1.728 18.904 24.504 ;
     RECT  18.904 23.376 18.965 24.504 ;
     RECT  18.904 6.816 19.043 7.464 ;
     RECT  18.904 19.632 19.235 22.2 ;
     RECT  18.904 1.728 19.289 3.48 ;
     RECT  18.469 25.728 19.379 25.752 ;
     RECT  19.289 3.36 19.433 3.48 ;
     RECT  19.433 3.456 19.613 3.48 ;
     RECT  18.965 23.376 19.715 23.976 ;
     RECT  18.917 0.576 19.793 0.6 ;
     RECT  19.235 20.4 19.933 22.2 ;
     RECT  19.043 7.44 19.973 7.464 ;
     RECT  19.681 25.008 20.099 25.08 ;
     RECT  18.904 4.512 20.113 5.496 ;
     RECT  20.113 4.08 20.153 5.496 ;
     RECT  19.933 20.4 20.153 22.728 ;
     RECT  20.153 5.472 20.329 5.496 ;
     RECT  20.153 22.704 20.435 22.728 ;
     RECT  20.153 20.4 20.509 21.672 ;
     RECT  19.715 23.904 20.653 23.976 ;
     RECT  19.289 1.728 20.689 2.328 ;
     RECT  20.689 1.728 20.693 2.904 ;
     RECT  20.099 25.056 20.819 25.08 ;
     RECT  20.581 0.096 20.905 0.12 ;
     RECT  20.905 0.096 21.011 0.552 ;
     RECT  20.653 6.864 21.125 6.888 ;
     RECT  20.653 23.904 21.155 24.024 ;
     RECT  20.693 2.88 21.161 2.904 ;
     RECT  21.155 23.904 21.301 23.976 ;
     RECT  21.011 0.096 21.305 0.12 ;
     RECT  20.329 5.472 21.409 5.688 ;
     RECT  20.509 19.92 21.737 21.672 ;
     RECT  20.693 1.728 21.829 1.8 ;
     RECT  21.301 23.376 21.875 23.976 ;
     RECT  21.829 1.152 22.169 1.8 ;
     RECT  20.153 4.08 22.237 4.104 ;
     RECT  22.057 25.056 22.259 25.08 ;
     RECT  22.237 3.552 22.277 4.104 ;
     RECT  21.737 19.92 22.313 21.384 ;
     RECT  22.213 0.144 22.357 0.168 ;
     RECT  22.277 3.552 22.489 3.96 ;
     RECT  22.169 1.728 22.549 1.8 ;
     RECT  21.409 5.184 22.561 5.688 ;
     RECT  21.875 23.376 22.595 23.928 ;
     RECT  22.357 0.096 22.601 0.168 ;
     RECT  22.601 0.096 22.709 0.12 ;
     RECT  22.313 20.832 22.885 21.384 ;
     RECT  22.549 1.728 22.921 1.848 ;
     RECT  22.489 3.072 22.921 3.96 ;
     RECT  22.595 23.472 22.957 23.928 ;
     RECT  22.921 1.728 23.005 3.96 ;
     RECT  22.957 23.472 23.699 23.976 ;
     RECT  23.699 23.472 23.713 23.88 ;
     RECT  22.561 5.184 23.756 6.072 ;
     RECT  23.065 7.44 23.756 7.464 ;
     RECT  22.885 20.832 23.785 22.056 ;
     RECT  23.756 5.184 23.893 7.464 ;
     RECT  23.005 3.072 23.965 3.96 ;
     RECT  23.893 5.04 23.965 7.464 ;
     RECT  23.005 1.728 24.008 1.8 ;
     RECT  23.965 3.072 24.008 7.464 ;
     RECT  23.029 8.544 24.008 8.568 ;
     RECT  23.785 20.16 24.008 22.056 ;
     RECT  23.713 23.376 24.008 23.88 ;
     RECT  24.008 1.728 24.304 23.88 ;
     RECT  24.304 23.04 24.419 23.88 ;
     RECT  24.304 2.88 24.437 7.224 ;
     RECT  24.304 8.544 24.445 8.568 ;
     RECT  24.419 23.328 24.445 23.88 ;
     RECT  23.989 25.728 24.467 25.752 ;
     RECT  24.437 3.072 24.473 7.224 ;
     RECT  24.473 3.888 24.515 7.224 ;
     RECT  24.476 25.104 24.563 25.128 ;
     RECT  24.304 19.92 24.803 22.056 ;
     RECT  24.445 23.376 24.865 23.88 ;
     RECT  24.515 3.936 24.995 7.224 ;
     RECT  24.865 23.376 25.009 23.928 ;
     RECT  24.803 20.016 25.333 22.056 ;
     RECT  25.292 17.616 25.379 17.64 ;
     RECT  25.333 20.016 25.429 22.296 ;
     RECT  25.009 23.376 25.429 23.976 ;
     RECT  25.429 20.016 25.475 23.976 ;
     RECT  25.429 2.88 25.517 2.904 ;
     RECT  25.475 20.016 25.667 23.928 ;
     RECT  24.304 1.728 25.765 1.848 ;
     RECT  24.995 5.184 26.089 7.224 ;
     RECT  24.995 3.936 26.129 3.96 ;
     RECT  26.089 5.184 26.129 7.368 ;
     RECT  26.129 5.184 26.149 6.264 ;
     RECT  25.667 20.016 26.156 23.544 ;
     RECT  26.149 4.704 26.165 6.264 ;
     RECT  26.165 4.704 26.195 6.024 ;
     RECT  25.765 1.728 26.237 1.896 ;
     RECT  26.156 19.68 26.273 23.544 ;
     RECT  26.273 22.272 26.281 23.544 ;
     RECT  26.281 22.992 26.381 23.544 ;
     RECT  26.273 19.68 26.533 21.144 ;
     RECT  26.492 17.616 26.579 17.64 ;
     RECT  26.381 23.376 26.701 23.544 ;
     RECT  26.237 1.728 26.773 1.752 ;
     RECT  26.773 1.152 26.915 1.752 ;
     RECT  26.773 25.104 26.915 25.128 ;
     RECT  26.533 19.392 27.029 21.144 ;
     RECT  26.341 0.096 27.245 0.12 ;
     RECT  26.129 7.344 27.253 7.368 ;
     RECT  26.195 4.704 27.277 5.208 ;
     RECT  27.253 6.816 27.299 7.368 ;
     RECT  27.277 3.888 27.313 5.208 ;
     RECT  27.299 6.816 27.353 6.84 ;
     RECT  27.029 20.016 27.389 21.144 ;
     RECT  26.915 1.728 27.397 1.752 ;
     RECT  27.389 20.16 27.445 21.144 ;
     RECT  27.313 3.888 27.461 5.496 ;
     RECT  27.461 3.936 27.637 5.496 ;
     RECT  26.701 23.376 27.853 23.976 ;
     RECT  27.397 1.728 27.925 1.8 ;
     RECT  27.853 23.376 27.971 24.552 ;
     RECT  27.925 1.728 28.069 2.328 ;
     RECT  28.069 1.728 28.217 2.904 ;
     RECT  27.781 0.576 28.361 0.6 ;
     RECT  27.445 20.16 28.537 21.672 ;
     RECT  27.637 3.936 29.113 6.264 ;
     RECT  28.717 25.104 29.219 25.128 ;
     RECT  28.217 1.728 29.257 2.856 ;
     RECT  29.257 1.728 29.269 2.904 ;
     RECT  29.113 3.936 29.269 6.888 ;
     RECT  29.269 1.728 29.408 6.888 ;
     RECT  28.537 20.16 29.408 21.768 ;
     RECT  27.971 23.376 29.408 23.928 ;
     RECT  29.269 0.096 29.411 0.12 ;
     RECT  29.408 1.728 29.704 23.928 ;
     RECT  29.704 3.84 29.837 3.864 ;
     RECT  29.704 19.968 30.053 23.928 ;
     RECT  29.704 1.728 30.131 2.28 ;
     RECT  29.704 5.04 30.413 6.264 ;
     RECT  30.053 23.376 30.517 23.928 ;
     RECT  30.413 5.184 30.833 6.264 ;
     RECT  30.517 23.376 30.851 24.6 ;
     RECT  29.704 7.44 30.881 7.464 ;
     RECT  30.833 5.184 30.917 6.312 ;
     RECT  30.053 19.968 30.917 22.248 ;
     RECT  30.851 23.376 31.043 24.552 ;
     RECT  30.131 1.728 31.057 1.896 ;
     RECT  31.057 1.104 31.187 1.896 ;
     RECT  31.345 3.696 31.453 3.912 ;
     RECT  31.187 1.728 31.525 1.896 ;
     RECT  31.453 2.88 31.525 3.912 ;
     RECT  31.525 1.728 31.669 3.912 ;
     RECT  30.917 5.184 31.669 6.264 ;
     RECT  30.917 19.968 31.673 21.672 ;
     RECT  31.333 0.096 31.709 0.12 ;
     RECT  31.669 1.728 31.715 6.264 ;
     RECT  31.715 1.728 31.853 2.904 ;
     RECT  31.673 20.544 31.961 21.672 ;
     RECT  31.853 1.728 31.997 2.184 ;
     RECT  31.885 25.104 32.099 25.128 ;
     RECT  32.317 0.528 32.627 0.552 ;
     RECT  31.043 23.376 32.627 23.928 ;
     RECT  31.715 3.888 32.717 6.264 ;
     RECT  32.717 3.888 32.893 3.96 ;
     RECT  32.893 3.36 32.963 3.96 ;
     RECT  32.893 8.544 32.977 8.568 ;
     RECT  32.773 0.576 33.005 0.6 ;
     RECT  32.963 3.36 33.077 3.912 ;
     RECT  31.961 20.544 33.113 21.144 ;
     RECT  32.857 22.704 33.185 22.728 ;
     RECT  31.997 1.728 33.301 1.8 ;
     RECT  32.627 23.808 33.325 23.928 ;
     RECT  33.325 23.808 33.649 24.552 ;
     RECT  33.077 3.888 33.683 3.912 ;
     RECT  33.605 7.968 33.689 7.992 ;
     RECT  33.301 1.728 33.725 2.184 ;
     RECT  32.717 5.184 33.937 6.264 ;
     RECT  33.113 21.12 34.153 21.144 ;
     RECT  33.649 23.712 34.259 24.552 ;
     RECT  34.153 21.12 34.297 21.384 ;
     RECT  34.213 0.576 34.409 0.6 ;
     RECT  33.937 4.8 34.657 6.264 ;
     RECT  34.645 0.096 34.787 0.12 ;
     RECT  34.405 2.88 34.801 3 ;
     RECT  34.657 4.128 34.801 6.264 ;
     RECT  33.725 1.728 34.808 1.848 ;
     RECT  34.801 2.88 34.808 6.264 ;
     RECT  34.297 20.4 34.808 21.96 ;
     RECT  34.259 23.712 34.808 23.976 ;
     RECT  34.808 1.728 34.985 23.976 ;
     RECT  34.985 2.016 35.104 23.976 ;
     RECT  35.104 20.304 35.219 23.976 ;
     RECT  34.933 25.728 35.219 25.752 ;
     RECT  35.104 2.016 35.267 6.888 ;
     RECT  35.267 2.88 35.315 6.888 ;
     RECT  35.315 5.184 35.353 6.888 ;
     RECT  35.315 2.88 35.813 4.152 ;
     RECT  35.813 2.88 35.929 2.904 ;
     RECT  35.219 23.376 36.035 23.976 ;
     RECT  35.989 1.776 36.161 1.8 ;
     RECT  35.219 20.304 36.277 22.104 ;
     RECT  35.813 4.128 36.317 4.152 ;
     RECT  36.277 20.304 36.317 22.392 ;
     RECT  36.161 1.728 36.353 1.8 ;
     RECT  36.133 25.104 36.755 25.128 ;
     RECT  36.035 23.376 36.997 23.928 ;
     RECT  36.557 0.096 37.001 0.12 ;
     RECT  35.353 5.184 37.148 5.736 ;
     RECT  36.317 22.368 37.217 22.392 ;
     RECT  37.177 3.408 37.261 3.432 ;
     RECT  36.317 20.304 37.285 21.144 ;
     RECT  37.148 4.896 37.393 5.736 ;
     RECT  36.353 1.728 37.429 1.752 ;
     RECT  37.285 20.304 37.465 21.192 ;
     RECT  36.997 23.376 37.465 24.552 ;
     RECT  37.465 22.704 37.475 24.552 ;
     RECT  37.429 1.728 37.609 2.184 ;
     RECT  37.475 24.528 37.667 24.552 ;
     RECT  37.609 1.152 37.693 2.184 ;
     RECT  37.465 20.304 37.865 21.672 ;
     RECT  37.093 0.144 37.907 0.168 ;
     RECT  37.693 1.728 38.197 2.184 ;
     RECT  37.393 3.888 38.243 6.552 ;
     RECT  38.149 25.776 38.261 25.8 ;
     RECT  38.243 4.56 38.297 6.552 ;
     RECT  37.475 22.704 38.297 23.4 ;
     RECT  38.297 4.656 38.441 6.552 ;
     RECT  38.185 11.376 38.501 11.4 ;
     RECT  38.441 5.04 38.533 6.552 ;
     RECT  38.501 10.848 38.585 11.4 ;
     RECT  38.533 5.04 38.837 6.792 ;
     RECT  38.585 11.376 38.915 11.4 ;
     RECT  38.861 14.256 38.945 14.28 ;
     RECT  38.297 23.376 39.052 23.4 ;
     RECT  37.865 20.304 39.161 21.192 ;
     RECT  39.052 23.376 39.229 23.448 ;
     RECT  39.161 20.304 39.308 21.144 ;
     RECT  39.229 23.376 39.313 23.928 ;
     RECT  39.397 0.096 39.581 0.12 ;
     RECT  39.581 0.096 39.701 0.216 ;
     RECT  38.837 6.288 39.769 6.792 ;
     RECT  38.837 5.04 39.877 5.208 ;
     RECT  39.769 6.288 39.877 6.84 ;
     RECT  39.313 23.376 39.925 23.772 ;
     RECT  39.925 25.584 39.973 25.608 ;
     RECT  39.877 3.84 40.021 3.864 ;
     RECT  39.308 19.92 40.069 21.144 ;
     RECT  39.701 0.144 40.129 0.216 ;
     RECT  38.197 1.728 40.208 2.712 ;
     RECT  40.021 3.84 40.208 3.912 ;
     RECT  39.877 5.04 40.208 6.84 ;
     RECT  38.869 12.48 40.208 12.504 ;
     RECT  39.193 14.208 40.208 14.232 ;
     RECT  40.069 18 40.208 18.024 ;
     RECT  40.069 19.536 40.208 21.144 ;
     RECT  39.925 22.56 40.208 23.772 ;
     RECT  40.208 1.728 40.312 23.772 ;
     RECT  40.129 0.144 40.355 0.552 ;
     RECT  39.973 25.584 40.355 25.752 ;
     RECT  40.312 1.728 40.504 23.502 ;
     RECT  40.504 14.208 40.643 14.232 ;
     RECT  40.504 19.536 40.673 21.96 ;
     RECT  40.504 2.88 40.691 3.912 ;
     RECT  40.355 25.728 40.691 25.752 ;
     RECT  40.504 7.968 40.717 8.088 ;
     RECT  40.717 7.968 40.853 7.992 ;
     RECT  40.691 2.88 40.997 3.864 ;
     RECT  40.504 5.04 41.069 5.64 ;
     RECT  40.837 0.096 41.249 0.12 ;
     RECT  40.673 20.16 41.321 21.96 ;
     RECT  40.504 23.376 41.345 23.502 ;
     RECT  40.997 2.88 41.411 2.904 ;
     RECT  41.345 23.376 41.533 23.928 ;
     RECT  41.321 21.936 41.569 21.96 ;
     RECT  41.069 5.184 41.677 5.64 ;
     RECT  40.504 6.672 41.677 6.84 ;
     RECT  41.569 21.936 41.753 22.248 ;
     RECT  40.504 1.728 41.893 1.8 ;
     RECT  41.893 1.104 41.941 1.8 ;
     RECT  41.677 5.184 42.073 6.84 ;
     RECT  41.941 1.104 42.131 2.328 ;
     RECT  41.533 23.376 42.131 24.552 ;
     RECT  42.073 5.184 42.14 6.888 ;
     RECT  42.14 4.944 42.157 6.888 ;
     RECT  42.157 4.944 42.227 6.84 ;
     RECT  42.131 23.856 42.323 24.552 ;
     RECT  41.321 20.16 42.329 20.856 ;
     RECT  42.037 3.936 42.725 3.96 ;
     RECT  42.131 1.728 42.805 2.328 ;
     RECT  42.329 20.448 42.941 20.856 ;
     RECT  41.753 21.936 42.973 21.96 ;
     RECT  42.805 1.728 43.117 2.904 ;
     RECT  42.997 0.576 43.265 0.6 ;
     RECT  42.941 20.832 43.297 20.856 ;
     RECT  42.973 21.936 43.297 22.104 ;
     RECT  43.117 1.728 43.373 3.72 ;
     RECT  43.373 1.728 43.589 2.28 ;
     RECT  42.227 5.136 43.621 6.84 ;
     RECT  43.621 5.136 43.657 7.512 ;
     RECT  42.323 23.856 43.729 23.928 ;
     RECT  43.657 5.088 43.741 7.512 ;
     RECT  43.741 5.472 43.811 7.512 ;
     RECT  43.729 23.856 43.873 23.976 ;
     RECT  43.589 1.728 43.877 1.848 ;
     RECT  43.297 20.832 43.913 22.104 ;
     RECT  43.373 3.696 44.165 3.72 ;
     RECT  43.913 20.832 44.377 21.672 ;
     RECT  44.341 0.528 44.483 0.552 ;
     RECT  43.873 23.808 44.483 23.976 ;
     RECT  44.483 23.808 44.557 23.928 ;
     RECT  44.377 20.592 44.629 21.672 ;
     RECT  44.765 0.096 44.849 0.12 ;
     RECT  44.557 23.376 44.881 23.928 ;
     RECT  43.877 1.728 45.157 1.8 ;
     RECT  43.811 5.472 45.169 6.84 ;
     RECT  45.169 5.04 45.233 6.84 ;
     RECT  45.233 5.04 45.397 6.936 ;
     RECT  45.157 1.728 45.608 2.328 ;
     RECT  45.397 4.512 45.608 6.936 ;
     RECT  40.504 12.48 45.608 12.504 ;
     RECT  44.629 20.352 45.608 21.672 ;
     RECT  44.881 22.752 45.608 23.928 ;
     RECT  45.608 1.728 45.904 23.928 ;
     RECT  45.904 1.728 45.961 1.848 ;
     RECT  45.961 1.68 46.115 1.848 ;
     RECT  45.904 3.36 46.211 6.648 ;
     RECT  46.211 3.36 46.253 6.552 ;
     RECT  46.253 3.36 46.451 4.104 ;
     RECT  46.451 3.936 46.469 4.104 ;
     RECT  46.789 0.096 46.925 0.12 ;
     RECT  46.925 0.096 47.009 0.168 ;
     RECT  46.115 1.728 47.125 1.848 ;
     RECT  46.253 5.184 47.185 6.552 ;
     RECT  45.904 23.856 47.188 23.928 ;
     RECT  47.185 5.184 47.329 6.744 ;
     RECT  47.188 23.856 47.363 23.976 ;
     RECT  47.363 23.856 47.42 23.928 ;
     RECT  45.904 20.4 47.437 20.904 ;
     RECT  46.469 4.08 47.617 4.104 ;
     RECT  47.437 20.4 47.653 21.144 ;
     RECT  47.617 3.984 47.66 4.104 ;
     RECT  47.66 3.936 47.747 4.104 ;
     RECT  47.125 1.728 47.845 2.184 ;
     RECT  47.747 3.984 47.945 4.008 ;
     RECT  47.329 5.136 47.945 6.744 ;
     RECT  47.009 0.096 48.089 0.12 ;
     RECT  47.945 5.184 48.125 6.744 ;
     RECT  47.42 23.376 48.481 23.928 ;
     RECT  47.845 1.728 48.521 2.952 ;
     RECT  47.653 20.16 48.589 21.144 ;
     RECT  45.904 22.128 48.589 22.152 ;
     RECT  48.589 20.16 48.629 22.152 ;
     RECT  48.125 5.184 48.949 6.552 ;
     RECT  48.949 4.896 49.061 6.552 ;
     RECT  48.481 23.376 49.139 23.976 ;
     RECT  48.629 20.16 49.489 21.672 ;
     RECT  49.489 20.112 49.529 21.672 ;
     RECT  48.521 1.728 49.601 2.904 ;
     RECT  49.601 1.728 49.709 2.184 ;
     RECT  49.061 4.896 49.909 5.16 ;
     RECT  49.909 3.936 50.137 5.16 ;
     RECT  50.005 0.096 50.197 0.12 ;
     RECT  50.197 0.096 50.321 0.168 ;
     RECT  50.137 3.888 50.389 5.16 ;
     RECT  49.061 6.24 50.389 6.552 ;
     RECT  50.321 0.144 50.609 0.168 ;
     RECT  49.529 20.112 50.821 21.144 ;
     RECT  50.129 22.224 50.821 22.248 ;
     RECT  50.389 3.888 50.893 6.552 ;
     RECT  50.821 20.112 50.893 22.248 ;
     RECT  49.709 1.728 51.008 1.8 ;
     RECT  50.893 3.024 51.008 6.552 ;
     RECT  45.904 12.48 51.008 12.504 ;
     RECT  50.893 19.872 51.008 22.248 ;
     RECT  49.139 23.376 51.008 23.928 ;
     RECT  50.341 25.728 51.299 25.752 ;
     RECT  51.008 1.728 51.304 23.928 ;
     RECT  51.304 1.728 51.833 1.848 ;
     RECT  52.165 0.096 52.3 0.12 ;
     RECT  52.3 0.096 52.301 0.168 ;
     RECT  51.304 19.968 52.301 20.856 ;
     RECT  52.301 0.144 52.501 0.168 ;
     RECT  52.501 0.144 52.553 0.6 ;
     RECT  51.304 5.472 52.652 6.552 ;
     RECT  52.301 20.208 52.729 20.856 ;
     RECT  51.304 22.176 52.729 22.2 ;
     RECT  52.652 5.472 52.739 6.792 ;
     RECT  52.553 0.576 52.769 0.6 ;
     RECT  52.729 20.208 52.769 22.2 ;
     RECT  51.833 1.728 52.865 1.752 ;
     RECT  51.304 3.888 52.873 4.44 ;
     RECT  51.304 23.376 52.948 23.928 ;
     RECT  52.948 23.376 53.021 23.976 ;
     RECT  52.873 3.312 53.165 4.44 ;
     RECT  53.165 3.888 53.197 4.44 ;
     RECT  52.739 5.472 53.197 6.552 ;
     RECT  52.769 20.208 53.345 21.672 ;
     RECT  53.749 0.576 53.921 0.6 ;
     RECT  52.865 1.728 53.941 1.848 ;
     RECT  53.021 23.856 54.179 23.976 ;
     RECT  53.941 1.728 54.245 2.184 ;
     RECT  53.197 3.888 54.281 6.552 ;
     RECT  53.749 25.776 54.353 25.8 ;
     RECT  54.281 3.888 54.425 4.248 ;
     RECT  53.345 20.832 54.425 21.672 ;
     RECT  54.245 1.728 54.497 1.8 ;
     RECT  54.179 23.856 54.601 23.928 ;
     RECT  54.529 3.072 54.641 3.096 ;
     RECT  54.469 0.096 54.899 0.552 ;
     RECT  54.601 23.232 54.929 23.928 ;
     RECT  54.281 5.76 55.105 6.552 ;
     RECT  55.105 5.76 55.331 7.08 ;
     RECT  54.425 20.832 55.397 21.144 ;
     RECT  54.899 0.096 55.649 0.12 ;
     RECT  54.497 1.728 55.709 1.752 ;
     RECT  54.425 4.224 55.861 4.248 ;
     RECT  55.753 2.832 55.969 2.856 ;
     RECT  55.861 4.224 55.969 4.68 ;
     RECT  55.709 1.728 56.293 1.8 ;
     RECT  55.969 2.832 56.293 4.68 ;
     RECT  56.293 1.728 56.408 4.68 ;
     RECT  55.331 5.76 56.408 6.648 ;
     RECT  51.304 12.48 56.408 12.504 ;
     RECT  55.397 20.928 56.408 21.144 ;
     RECT  54.929 23.376 56.408 23.928 ;
     RECT  56.408 1.728 56.704 23.928 ;
     RECT  56.704 2.784 56.819 6.84 ;
     RECT  56.704 1.728 56.837 1.8 ;
     RECT  56.704 23.376 56.972 23.928 ;
     RECT  56.819 2.784 56.989 6.648 ;
     RECT  56.989 6.528 57.017 6.648 ;
     RECT  56.972 23.376 57.059 23.976 ;
     RECT  56.989 2.784 57.197 5.256 ;
     RECT  57.197 3.408 57.485 5.256 ;
     RECT  56.704 20.736 57.737 22.2 ;
     RECT  56.837 1.728 57.877 1.752 ;
     RECT  57.485 3.84 57.985 5.256 ;
     RECT  57.017 6.528 57.985 6.552 ;
     RECT  58.069 0.096 58.493 0.12 ;
     RECT  57.877 1.728 58.589 1.8 ;
     RECT  57.985 3.84 58.601 6.552 ;
     RECT  57.737 20.736 58.633 21.672 ;
     RECT  58.589 1.728 58.673 2.28 ;
     RECT  58.261 25.776 58.961 25.8 ;
     RECT  57.059 23.376 59.137 23.928 ;
     RECT  58.601 4.512 59.267 6.552 ;
     RECT  58.633 19.776 59.357 21.672 ;
     RECT  59.137 23.376 59.363 23.976 ;
     RECT  58.673 1.728 59.701 1.752 ;
     RECT  59.357 19.776 59.713 21.288 ;
     RECT  59.363 23.376 59.713 23.928 ;
     RECT  59.713 23.088 59.891 23.928 ;
     RECT  59.713 19.344 59.933 21.288 ;
     RECT  59.941 3.312 60.028 3.336 ;
     RECT  59.267 4.512 60.289 4.68 ;
     RECT  59.267 5.664 60.289 6.552 ;
     RECT  60.361 24.96 60.611 24.984 ;
     RECT  59.933 20.544 60.653 21.288 ;
     RECT  59.933 19.344 60.901 19.368 ;
     RECT  59.891 23.856 60.908 23.928 ;
     RECT  59.701 1.728 60.937 2.184 ;
     RECT  60.901 18.96 61.004 19.368 ;
     RECT  60.653 20.544 61.004 20.616 ;
     RECT  60.613 25.056 61.139 25.08 ;
     RECT  60.937 1.728 61.369 2.28 ;
     RECT  60.421 3.408 61.369 3.432 ;
     RECT  61.369 1.728 61.585 3.432 ;
     RECT  60.289 4.512 61.585 6.552 ;
     RECT  61.585 1.728 61.613 6.552 ;
     RECT  59.845 0.096 61.661 0.12 ;
     RECT  60.908 23.376 61.729 23.928 ;
     RECT  61.613 1.728 61.808 6.648 ;
     RECT  56.704 12.48 61.808 12.504 ;
     RECT  61.004 18.96 61.808 20.616 ;
     RECT  61.729 22.752 61.808 24.024 ;
     RECT  61.808 1.728 62.051 24.024 ;
     RECT  62.051 1.728 62.104 23.928 ;
     RECT  62.104 23.328 62.129 23.928 ;
     RECT  62.104 3.936 62.483 7.08 ;
     RECT  62.104 18.96 62.525 21.432 ;
     RECT  62.129 23.376 62.813 23.928 ;
     RECT  62.525 19.776 63.029 21.432 ;
     RECT  62.104 1.728 63.089 1.896 ;
     RECT  62.483 3.984 63.097 7.08 ;
     RECT  62.813 23.568 63.155 23.928 ;
     RECT  63.089 1.728 63.173 2.856 ;
     RECT  63.097 3.984 63.181 7.464 ;
     RECT  63.029 19.872 63.205 21.432 ;
     RECT  63.155 23.904 63.205 23.928 ;
     RECT  63.205 23.904 63.241 24.552 ;
     RECT  63.173 1.728 63.245 2.328 ;
     RECT  63.181 3.984 63.251 6.84 ;
     RECT  63.251 5.184 63.389 6.84 ;
     RECT  63.253 0.576 63.445 0.6 ;
     RECT  63.241 23.904 63.491 25.08 ;
     RECT  63.205 19.872 63.529 21.672 ;
     RECT  63.529 19.872 63.683 22.2 ;
     RECT  63.491 23.904 63.721 23.928 ;
     RECT  63.491 25.056 63.875 25.08 ;
     RECT  63.953 25.776 64.037 25.8 ;
     RECT  63.251 3.984 64.069 4.008 ;
     RECT  63.445 0.576 64.109 0.648 ;
     RECT  63.389 5.184 64.609 5.208 ;
     RECT  63.389 6.24 64.609 6.84 ;
     RECT  64.109 0.576 64.693 0.6 ;
     RECT  64.069 3.84 64.748 4.008 ;
     RECT  64.609 5.184 64.748 6.84 ;
     RECT  63.245 1.728 64.789 2.184 ;
     RECT  64.693 0.096 64.793 0.6 ;
     RECT  64.748 3.84 64.835 6.84 ;
     RECT  64.165 23.376 64.853 23.448 ;
     RECT  63.683 19.92 65.005 20.616 ;
     RECT  64.853 23.376 65.267 23.928 ;
     RECT  65.005 19.92 65.317 20.808 ;
     RECT  63.683 22.176 65.317 22.2 ;
     RECT  65.317 19.92 65.329 22.2 ;
     RECT  65.329 19.776 65.404 22.2 ;
     RECT  64.835 4.08 65.603 6.84 ;
     RECT  64.789 1.728 65.605 2.856 ;
     RECT  65.605 1.152 65.693 2.856 ;
     RECT  65.693 1.152 65.801 1.8 ;
     RECT  65.267 23.376 66.337 23.544 ;
     RECT  64.793 0.096 66.341 0.12 ;
     RECT  65.801 1.728 66.661 1.8 ;
     RECT  65.693 2.832 66.661 2.856 ;
     RECT  65.404 19.776 66.913 20.808 ;
     RECT  65.404 22.08 66.913 22.2 ;
     RECT  66.337 23.376 67.129 23.928 ;
     RECT  66.661 1.728 67.208 2.856 ;
     RECT  65.603 4.08 67.208 4.104 ;
     RECT  65.603 5.088 67.208 6.84 ;
     RECT  66.697 7.968 67.208 8.568 ;
     RECT  62.104 12.48 67.208 12.504 ;
     RECT  66.913 19.776 67.208 22.2 ;
     RECT  67.129 23.376 67.208 24.552 ;
     RECT  67.208 1.728 67.427 24.552 ;
     RECT  67.427 1.728 67.504 23.736 ;
     RECT  67.504 5.232 67.601 5.256 ;
     RECT  67.504 21.792 67.619 23.736 ;
     RECT  67.619 21.984 67.637 23.736 ;
     RECT  67.504 3.936 67.645 3.96 ;
     RECT  67.504 8.544 67.673 8.568 ;
     RECT  67.637 23.376 67.781 23.736 ;
     RECT  67.741 0.096 67.825 0.12 ;
     RECT  67.504 1.728 68.252 1.8 ;
     RECT  68.252 1.104 68.339 1.8 ;
     RECT  67.504 18.192 68.579 18.216 ;
     RECT  67.637 21.984 68.617 22.248 ;
     RECT  68.617 21.984 68.681 22.008 ;
     RECT  67.504 19.776 68.753 20.616 ;
     RECT  67.504 6.288 68.893 6.84 ;
     RECT  68.821 0.096 68.933 0.12 ;
     RECT  67.781 23.376 69.251 23.496 ;
     RECT  69.013 2.88 69.289 2.904 ;
     RECT  68.339 1.728 69.349 1.8 ;
     RECT  69.289 2.88 69.349 3.336 ;
     RECT  69.205 0.144 69.541 0.168 ;
     RECT  69.349 1.728 69.761 3.336 ;
     RECT  69.541 0.144 69.833 0.264 ;
     RECT  68.893 5.712 69.937 6.84 ;
     RECT  69.761 1.728 70.013 2.904 ;
     RECT  69.937 5.664 70.117 6.84 ;
     RECT  70.009 4.512 70.165 4.536 ;
     RECT  70.117 5.616 70.204 6.84 ;
     RECT  69.349 23.856 70.22 23.928 ;
     RECT  70.165 4.464 70.364 4.536 ;
     RECT  70.364 3.936 70.451 4.536 ;
     RECT  67.504 12.48 70.693 12.504 ;
     RECT  70.693 12.384 70.733 12.504 ;
     RECT  70.204 5.664 71.18 6.84 ;
     RECT  70.22 23.376 71.219 23.928 ;
     RECT  71.18 5.616 71.267 6.84 ;
     RECT  71.267 5.616 71.273 6.552 ;
     RECT  68.753 19.776 71.345 20.52 ;
     RECT  71.345 19.776 71.377 19.8 ;
     RECT  71.377 19.632 71.417 19.8 ;
     RECT  70.451 4.512 71.629 4.536 ;
     RECT  71.273 5.616 71.629 6.408 ;
     RECT  70.253 0.096 71.701 0.12 ;
     RECT  70.013 1.728 71.777 2.184 ;
     RECT  71.701 0.096 71.939 0.552 ;
     RECT  71.629 4.512 71.989 6.408 ;
     RECT  71.777 1.824 72.025 2.184 ;
     RECT  71.989 3.84 72.025 6.408 ;
     RECT  70.733 12.384 72.284 12.408 ;
     RECT  72.133 25.824 72.371 25.848 ;
     RECT  72.025 1.824 72.373 6.408 ;
     RECT  71.219 23.616 72.38 23.928 ;
     RECT  72.277 22.128 72.421 22.152 ;
     RECT  72.373 1.824 72.608 6.84 ;
     RECT  72.284 12.384 72.608 12.552 ;
     RECT  71.417 19.632 72.608 19.656 ;
     RECT  72.421 21.984 72.608 22.152 ;
     RECT  72.38 23.376 72.608 23.928 ;
     RECT  72.608 1.824 72.757 23.928 ;
     RECT  71.939 0.096 72.785 0.12 ;
     RECT  72.757 1.728 72.904 23.928 ;
     RECT  72.904 22.752 72.908 23.928 ;
     RECT  72.904 1.728 72.965 3.624 ;
     RECT  72.908 22.752 72.995 23.976 ;
     RECT  72.965 1.728 73.109 2.856 ;
     RECT  72.995 22.752 73.933 23.928 ;
     RECT  73.933 22.704 74.005 23.928 ;
     RECT  73.109 1.728 74.045 2.328 ;
     RECT  74.005 22.08 74.045 23.928 ;
     RECT  72.904 4.656 74.101 5.304 ;
     RECT  72.904 6.528 74.101 6.552 ;
     RECT  74.101 4.512 74.147 5.304 ;
     RECT  74.101 6.288 74.221 6.552 ;
     RECT  74.177 0.096 74.261 0.12 ;
     RECT  74.045 22.08 74.329 22.104 ;
     RECT  74.147 4.512 74.365 4.584 ;
     RECT  72.904 19.632 74.965 20.52 ;
     RECT  74.965 19.344 75.011 20.52 ;
     RECT  75.011 19.344 75.053 19.368 ;
     RECT  74.329 21.648 75.161 22.104 ;
     RECT  74.045 1.728 75.197 1.848 ;
     RECT  75.197 1.728 75.232 1.752 ;
     RECT  74.365 3.648 75.409 4.584 ;
     RECT  75.011 20.496 75.409 20.52 ;
     RECT  75.232 1.68 75.445 1.752 ;
     RECT  75.409 3.648 75.449 4.824 ;
     RECT  75.445 1.152 75.557 1.752 ;
     RECT  74.045 23.376 75.683 23.928 ;
     RECT  75.829 0.096 76.021 0.12 ;
     RECT  75.161 21.648 76.025 21.672 ;
     RECT  75.449 3.648 76.417 3.816 ;
     RECT  75.449 4.8 76.489 4.824 ;
     RECT  74.221 5.856 76.489 6.552 ;
     RECT  76.021 0.096 76.549 0.168 ;
     RECT  76.549 0.096 76.709 0.216 ;
     RECT  76.709 0.096 76.745 0.168 ;
     RECT  76.489 4.8 76.777 6.552 ;
     RECT  76.417 3.312 76.844 3.816 ;
     RECT  76.777 4.8 76.844 6.84 ;
     RECT  75.683 23.712 76.844 23.928 ;
     RECT  76.844 3.312 76.931 6.84 ;
     RECT  76.745 0.144 77.069 0.168 ;
     RECT  75.557 1.728 77.077 1.752 ;
     RECT  75.409 20.496 77.137 20.616 ;
     RECT  77.137 20.304 77.173 20.616 ;
     RECT  76.931 4.8 77.209 6.84 ;
     RECT  77.077 1.152 77.285 1.752 ;
     RECT  77.285 1.632 77.459 1.752 ;
     RECT  77.459 1.728 77.797 1.752 ;
     RECT  77.797 1.728 77.965 1.8 ;
     RECT  77.965 1.728 78.008 1.896 ;
     RECT  76.931 3.312 78.008 3.336 ;
     RECT  77.209 4.8 78.008 7.464 ;
     RECT  77.845 9.12 78.008 9.144 ;
     RECT  72.904 12.48 78.008 12.504 ;
     RECT  77.173 20.304 78.008 21 ;
     RECT  76.844 23.376 78.008 23.928 ;
     RECT  78.008 1.728 78.304 23.928 ;
     RECT  78.304 20.304 78.473 21.912 ;
     RECT  78.304 1.728 78.563 7.08 ;
     RECT  78.473 20.496 78.659 21.912 ;
     RECT  79.045 0.096 79.229 0.12 ;
     RECT  78.563 2.88 79.235 7.08 ;
     RECT  78.304 23.376 79.297 23.928 ;
     RECT  78.659 20.496 79.301 21.624 ;
     RECT  79.235 2.88 79.553 4.104 ;
     RECT  79.297 23.376 79.633 24.504 ;
     RECT  79.235 5.184 79.693 7.08 ;
     RECT  79.301 20.592 79.693 21.624 ;
     RECT  79.633 23.376 79.693 23.448 ;
     RECT  79.693 20.592 79.697 23.448 ;
     RECT  78.563 1.728 79.765 1.8 ;
     RECT  79.553 2.88 79.769 3.432 ;
     RECT  79.633 24.48 80.003 24.504 ;
     RECT  79.765 1.728 80.233 1.896 ;
     RECT  80.233 1.728 80.339 2.28 ;
     RECT  79.765 25.776 80.453 25.8 ;
     RECT  80.449 0.096 80.533 0.12 ;
     RECT  79.697 20.592 80.561 23.4 ;
     RECT  80.561 22.464 80.668 23.4 ;
     RECT  79.693 5.184 80.773 7.416 ;
     RECT  79.769 3.36 80.849 3.432 ;
     RECT  80.668 22.464 80.849 23.448 ;
     RECT  80.773 5.184 80.917 7.464 ;
     RECT  80.849 3.408 81.025 3.432 ;
     RECT  80.917 4.608 81.025 7.464 ;
     RECT  81.025 3.408 81.065 7.464 ;
     RECT  80.561 20.592 81.164 21.384 ;
     RECT  81.164 20.208 81.251 21.384 ;
     RECT  80.339 1.728 81.397 1.848 ;
     RECT  81.065 3.984 81.533 7.464 ;
     RECT  81.397 1.728 81.605 2.184 ;
     RECT  81.251 20.592 81.637 21.384 ;
     RECT  81.533 4.608 81.641 7.464 ;
     RECT  81.701 0.576 81.785 0.6 ;
     RECT  81.605 1.728 82.001 1.848 ;
     RECT  81.641 5.232 82.609 7.464 ;
     RECT  82.609 4.512 82.741 7.464 ;
     RECT  82.001 1.728 82.981 1.8 ;
     RECT  80.849 23.376 83.141 23.448 ;
     RECT  82.981 1.728 83.149 1.896 ;
     RECT  83.149 1.728 83.221 2.28 ;
     RECT  83.221 1.728 83.269 2.808 ;
     RECT  82.741 3.984 83.269 7.464 ;
     RECT  81.637 20.592 83.269 22.104 ;
     RECT  83.269 1.728 83.408 7.464 ;
     RECT  78.304 12.48 83.408 12.504 ;
     RECT  83.269 19.776 83.408 22.104 ;
     RECT  83.141 23.376 83.408 23.928 ;
     RECT  80.809 25.104 83.411 25.128 ;
     RECT  83.408 1.728 83.704 23.928 ;
     RECT  83.704 3.408 83.765 6.552 ;
     RECT  83.704 23.376 84.133 23.928 ;
     RECT  83.704 19.968 84.419 22.008 ;
     RECT  82.261 0.096 84.613 0.12 ;
     RECT  83.765 4.128 84.757 4.152 ;
     RECT  83.765 5.328 84.757 6.552 ;
     RECT  84.613 0.096 84.845 0.168 ;
     RECT  84.133 23.376 84.917 23.784 ;
     RECT  84.419 21.648 84.989 22.008 ;
     RECT  84.917 23.76 84.997 23.784 ;
     RECT  84.757 4.128 85.052 6.552 ;
     RECT  83.704 1.728 85.129 2.328 ;
     RECT  84.845 0.096 85.313 0.12 ;
     RECT  85.129 1.728 85.453 2.952 ;
     RECT  85.052 4.128 85.453 6.792 ;
     RECT  85.453 1.728 85.457 6.792 ;
     RECT  85.457 3.696 85.477 6.792 ;
     RECT  84.419 19.968 85.529 20.664 ;
     RECT  85.477 3.696 86.141 6.84 ;
     RECT  84.989 21.648 86.141 21.672 ;
     RECT  85.141 23.856 86.245 23.928 ;
     RECT  86.245 23.424 86.249 23.928 ;
     RECT  86.249 23.424 86.348 23.448 ;
     RECT  86.141 4.56 86.537 6.84 ;
     RECT  85.457 1.728 86.569 2.328 ;
     RECT  86.537 4.656 86.753 6.84 ;
     RECT  85.529 19.968 86.753 20.616 ;
     RECT  86.533 24.528 86.819 24.552 ;
     RECT  86.569 1.728 86.969 3.144 ;
     RECT  86.969 1.728 87.077 2.328 ;
     RECT  86.348 23.376 87.281 23.448 ;
     RECT  86.389 0.144 87.301 0.168 ;
     RECT  87.301 0.144 87.617 0.6 ;
     RECT  86.753 5.664 87.779 6.84 ;
     RECT  86.753 20.448 87.797 20.616 ;
     RECT  87.617 0.144 87.829 0.168 ;
     RECT  87.469 22.08 87.829 22.104 ;
     RECT  87.281 23.376 87.829 23.928 ;
     RECT  86.753 4.656 88.405 4.68 ;
     RECT  88.405 4.56 88.549 4.68 ;
     RECT  87.779 5.664 88.549 6.696 ;
     RECT  87.829 22.08 88.645 23.928 ;
     RECT  88.645 22.08 88.787 24.216 ;
     RECT  87.077 1.728 88.808 2.184 ;
     RECT  88.549 4.56 88.808 6.696 ;
     RECT  83.704 12.48 88.808 12.504 ;
     RECT  87.797 20.496 88.808 20.616 ;
     RECT  88.787 22.08 88.808 24.024 ;
     RECT  88.808 1.728 89.104 24.024 ;
     RECT  89.104 1.728 89.267 6.888 ;
     RECT  89.104 8.544 89.267 8.568 ;
     RECT  87.829 0.096 89.363 0.168 ;
     RECT  89.104 23.376 89.453 24.024 ;
     RECT  89.267 4.512 89.507 6.888 ;
     RECT  89.267 1.728 89.597 2.904 ;
     RECT  89.363 0.096 89.885 0.12 ;
     RECT  89.104 20.592 90.083 21.672 ;
     RECT  90.083 20.736 90.097 21.672 ;
     RECT  89.507 4.56 90.173 6.888 ;
     RECT  89.453 23.376 90.641 23.928 ;
     RECT  89.597 1.728 90.709 1.8 ;
     RECT  89.597 2.88 90.709 2.904 ;
     RECT  90.097 20.736 90.853 22.2 ;
     RECT  90.709 1.728 91.177 2.904 ;
     RECT  90.853 20.736 91.177 22.296 ;
     RECT  90.173 4.56 91.393 6.552 ;
     RECT  91.357 25.104 91.475 25.128 ;
     RECT  90.641 23.904 91.501 23.928 ;
     RECT  91.393 4.56 91.505 7.368 ;
     RECT  91.429 0.096 91.613 0.12 ;
     RECT  91.177 1.728 91.757 3.096 ;
     RECT  91.757 2.736 91.765 3.096 ;
     RECT  91.501 23.904 91.811 23.976 ;
     RECT  91.177 20.736 91.897 22.344 ;
     RECT  91.765 2.736 91.957 3.432 ;
     RECT  91.897 20.304 91.973 22.344 ;
     RECT  91.811 23.904 92.077 23.928 ;
     RECT  91.957 2.736 92.081 3.48 ;
     RECT  92.081 2.832 92.261 3.48 ;
     RECT  92.261 2.832 92.387 2.904 ;
     RECT  92.54 3.936 92.581 3.96 ;
     RECT  91.505 5.04 92.581 7.368 ;
     RECT  92.581 3.936 92.657 7.368 ;
     RECT  92.657 3.936 92.837 6.552 ;
     RECT  92.387 2.88 92.915 2.904 ;
     RECT  91.973 20.304 92.972 21.432 ;
     RECT  92.837 3.936 93.337 4.536 ;
     RECT  91.757 1.728 93.725 1.752 ;
     RECT  93.725 1.728 93.925 1.8 ;
     RECT  93.337 3.888 94.021 4.536 ;
     RECT  92.837 5.616 94.021 6.552 ;
     RECT  92.972 20.304 94.021 21.96 ;
     RECT  94.021 3.888 94.057 6.552 ;
     RECT  93.949 25.104 94.069 25.128 ;
     RECT  94.057 3.888 94.093 7.464 ;
     RECT  94.069 25.104 94.163 25.752 ;
     RECT  93.185 0.096 94.177 0.12 ;
     RECT  93.925 1.728 94.208 1.848 ;
     RECT  94.093 3.024 94.208 7.464 ;
     RECT  94.057 8.544 94.208 8.568 ;
     RECT  89.104 12.48 94.208 12.504 ;
     RECT  94.021 20.304 94.208 22.152 ;
     RECT  92.077 23.376 94.208 23.928 ;
     RECT  94.208 1.728 94.309 23.928 ;
     RECT  94.163 25.728 94.499 25.752 ;
     RECT  94.309 1.152 94.504 23.928 ;
     RECT  94.504 22.272 94.565 22.296 ;
     RECT  94.504 1.152 94.709 1.8 ;
     RECT  94.504 23.376 94.889 23.928 ;
     RECT  94.709 1.152 95.132 1.752 ;
     RECT  95.132 1.104 95.219 1.752 ;
     RECT  94.504 3.936 95.465 7.464 ;
     RECT  94.504 19.92 95.568 21.144 ;
     RECT  95.465 3.936 95.699 6.984 ;
     RECT  95.365 0.096 95.749 0.12 ;
     RECT  95.699 3.936 95.897 6.84 ;
     RECT  95.965 2.88 96.037 2.904 ;
     RECT  95.897 4.272 96.076 6.84 ;
     RECT  96.037 2.88 96.149 2.952 ;
     RECT  96.149 2.928 96.293 2.952 ;
     RECT  95.568 19.92 96.316 20.856 ;
     RECT  96.076 5.184 96.401 6.84 ;
     RECT  94.889 23.376 96.577 23.448 ;
     RECT  96.401 6 96.617 6.84 ;
     RECT  95.749 0.096 96.689 0.168 ;
     RECT  96.689 0.144 96.761 0.168 ;
     RECT  95.219 1.728 96.805 1.752 ;
     RECT  97.045 3.792 97.109 3.816 ;
     RECT  97.109 3.792 97.193 3.96 ;
     RECT  96.316 20.592 97.261 20.856 ;
     RECT  97.141 8.544 97.265 8.568 ;
     RECT  96.805 1.728 97.333 1.8 ;
     RECT  96.577 22.176 97.373 22.2 ;
     RECT  96.617 6 97.441 6.552 ;
     RECT  97.333 1.728 97.484 2.184 ;
     RECT  97.193 3.792 97.484 3.816 ;
     RECT  97.484 1.728 97.571 3.816 ;
     RECT  97.261 20.592 97.697 21.144 ;
     RECT  96.577 23.376 97.861 23.928 ;
     RECT  96.469 25.776 97.913 25.8 ;
     RECT  97.861 0.096 98.053 0.12 ;
     RECT  97.571 3.792 98.093 3.816 ;
     RECT  98.053 0.096 98.453 0.168 ;
     RECT  98.453 0.144 98.561 0.168 ;
     RECT  97.441 5.088 98.593 6.552 ;
     RECT  97.861 22.752 98.627 23.928 ;
     RECT  98.593 5.088 98.668 6.648 ;
     RECT  97.697 20.736 98.693 21.144 ;
     RECT  98.521 3.84 99.061 3.864 ;
     RECT  99.061 3.264 99.097 3.864 ;
     RECT  97.571 1.728 99.157 2.184 ;
     RECT  99.157 1.728 99.169 2.28 ;
     RECT  99.097 3.264 99.169 3.96 ;
     RECT  99.169 1.728 99.205 3.96 ;
     RECT  98.693 20.736 99.241 21.672 ;
     RECT  98.668 5.04 99.277 6.648 ;
     RECT  99.205 1.104 99.347 3.96 ;
     RECT  98.917 25.104 99.347 25.128 ;
     RECT  99.241 20.688 99.493 21.672 ;
     RECT  98.627 22.752 99.493 22.776 ;
     RECT  99.347 1.728 99.608 3.96 ;
     RECT  99.277 5.04 99.608 6.936 ;
     RECT  94.504 12.48 99.608 12.504 ;
     RECT  98.876 19.68 99.608 19.704 ;
     RECT  99.493 20.688 99.608 22.776 ;
     RECT  98.627 23.856 99.608 23.928 ;
     RECT  99.608 1.728 99.904 23.928 ;
     RECT  99.904 7.968 100.067 8.568 ;
     RECT  99.904 19.92 100.115 23.928 ;
     RECT  100.115 20.16 100.145 23.928 ;
     RECT  100.067 8.544 100.181 8.568 ;
     RECT  100.213 0.096 100.405 0.12 ;
     RECT  99.904 3.168 100.649 6.936 ;
     RECT  100.145 23.376 100.787 23.928 ;
     RECT  100.649 3.84 100.865 6.936 ;
     RECT  100.145 20.16 100.937 22.2 ;
     RECT  100.405 0.096 101.125 0.168 ;
     RECT  100.865 3.84 101.189 5.496 ;
     RECT  101.125 0.096 101.333 0.6 ;
     RECT  99.904 1.728 101.369 1.8 ;
     RECT  100.937 22.176 101.405 22.2 ;
     RECT  101.189 5.088 101.441 5.496 ;
     RECT  100.865 6.528 101.689 6.936 ;
     RECT  101.329 25.104 101.699 25.128 ;
     RECT  101.441 5.472 102.125 5.496 ;
     RECT  101.189 3.84 102.197 4.056 ;
     RECT  101.333 0.096 102.233 0.216 ;
     RECT  102.233 0.096 102.341 0.168 ;
     RECT  100.937 20.16 102.445 20.904 ;
     RECT  102.365 22.464 102.445 22.488 ;
     RECT  102.445 20.16 102.449 22.488 ;
     RECT  101.369 1.728 102.553 1.752 ;
     RECT  100.787 23.856 102.589 23.928 ;
     RECT  102.589 23.856 102.611 23.976 ;
     RECT  102.553 1.728 102.637 1.848 ;
     RECT  102.197 3.84 102.665 3.864 ;
     RECT  102.449 20.16 102.665 21.672 ;
     RECT  102.553 5.28 103.093 5.304 ;
     RECT  101.689 6.528 103.093 7.08 ;
     RECT  102.611 23.904 103.139 23.976 ;
     RECT  103.093 5.28 103.277 7.08 ;
     RECT  103.277 6.048 103.313 7.08 ;
     RECT  102.637 1.728 103.621 1.8 ;
     RECT  103.057 25.104 103.667 25.128 ;
     RECT  102.665 20.304 103.705 21.672 ;
     RECT  102.341 0.096 103.949 0.12 ;
     RECT  103.949 0.096 104.033 0.168 ;
     RECT  103.957 25.776 104.099 25.8 ;
     RECT  104.033 0.096 104.105 0.12 ;
     RECT  103.705 3.936 104.317 3.96 ;
     RECT  103.139 23.904 104.32 23.928 ;
     RECT  104.317 3.936 104.341 4.152 ;
     RECT  103.621 1.728 104.533 2.184 ;
     RECT  104.32 23.856 104.533 23.928 ;
     RECT  103.313 6.288 104.636 7.08 ;
     RECT  104.341 3.408 104.869 4.152 ;
     RECT  104.821 5.184 104.869 5.208 ;
     RECT  104.533 1.728 105.008 2.328 ;
     RECT  104.869 3.36 105.008 5.208 ;
     RECT  104.636 6.192 105.008 7.08 ;
     RECT  99.904 12.48 105.008 12.504 ;
     RECT  103.705 19.968 105.008 21.672 ;
     RECT  104.749 22.752 105.008 22.776 ;
     RECT  104.533 23.76 105.008 23.928 ;
     RECT  105.008 1.728 105.304 23.928 ;
     RECT  105.304 20.016 105.365 21.192 ;
     RECT  105.304 5.184 105.401 5.208 ;
     RECT  105.304 6.624 105.401 6.936 ;
     RECT  105.304 3.84 105.437 4.152 ;
     RECT  105.397 25.776 105.685 25.8 ;
     RECT  105.365 20.016 105.733 21.096 ;
     RECT  105.304 1.728 105.82 2.808 ;
     RECT  105.685 25.728 105.973 25.8 ;
     RECT  105.82 1.728 106.013 1.848 ;
     RECT  105.973 25.104 106.085 25.8 ;
     RECT  106.085 25.104 106.163 25.128 ;
     RECT  106.013 1.728 106.268 1.8 ;
     RECT  106.268 1.104 106.355 1.8 ;
     RECT  105.401 6.72 106.403 6.936 ;
     RECT  106.364 14.16 106.405 14.184 ;
     RECT  105.437 3.84 106.477 3.864 ;
     RECT  106.405 13.824 106.547 14.28 ;
     RECT  106.357 5.472 106.585 5.496 ;
     RECT  105.304 23.376 106.588 23.928 ;
     RECT  106.547 13.824 106.733 13.848 ;
     RECT  105.733 20.016 106.805 20.904 ;
     RECT  105.973 0.096 106.841 0.12 ;
     RECT  105.304 12.48 106.873 12.504 ;
     RECT  106.585 5.28 106.885 5.496 ;
     RECT  106.873 12 106.913 12.504 ;
     RECT  106.913 12 106.957 12.024 ;
     RECT  106.477 3.84 106.985 4.248 ;
     RECT  106.355 1.728 107.029 1.8 ;
     RECT  107.029 1.728 107.129 1.896 ;
     RECT  106.805 20.592 107.413 20.904 ;
     RECT  107.221 25.728 107.459 25.752 ;
     RECT  107.221 0.576 107.489 0.6 ;
     RECT  106.985 4.224 107.557 4.248 ;
     RECT  106.885 5.28 107.557 5.736 ;
     RECT  106.403 6.72 107.557 6.84 ;
     RECT  107.557 25.776 107.699 25.8 ;
     RECT  107.413 20.592 107.701 21 ;
     RECT  106.588 23.904 107.708 23.928 ;
     RECT  107.557 4.224 107.777 6.84 ;
     RECT  107.701 20.592 107.893 21.672 ;
     RECT  106.477 18.96 107.939 18.984 ;
     RECT  107.708 23.376 108.131 23.928 ;
     RECT  107.893 20.304 108.173 21.672 ;
     RECT  108.269 0.096 108.353 0.12 ;
     RECT  107.777 4.224 108.601 5.736 ;
     RECT  108.173 20.592 108.62 21.672 ;
     RECT  108.601 3.984 108.641 5.736 ;
     RECT  108.62 20.592 108.707 22.44 ;
     RECT  107.129 1.728 108.773 1.8 ;
     RECT  108.773 1.152 108.857 1.8 ;
     RECT  108.641 3.984 108.893 4.008 ;
     RECT  108.805 25.776 108.893 25.8 ;
     RECT  108.641 5.088 108.949 5.736 ;
     RECT  107.777 6.816 108.949 6.84 ;
     RECT  108.707 20.592 109.109 21.768 ;
     RECT  108.997 2.88 109.145 2.904 ;
     RECT  109.109 20.592 109.145 21.672 ;
     RECT  108.131 23.904 109.189 23.928 ;
     RECT  108.857 1.728 109.349 1.8 ;
     RECT  109.189 23.856 109.349 23.928 ;
     RECT  109.484 0.528 109.571 0.552 ;
     RECT  108.949 5.088 109.861 6.84 ;
     RECT  109.145 20.592 109.909 21.432 ;
     RECT  109.349 23.76 110.113 23.928 ;
     RECT  109.909 20.16 110.252 21.432 ;
     RECT  109.349 1.728 110.408 2.856 ;
     RECT  109.861 5.088 110.408 6.888 ;
     RECT  110.252 20.16 110.408 22.104 ;
     RECT  110.113 23.376 110.408 23.928 ;
     RECT  110.293 25.728 110.483 25.752 ;
     RECT  110.408 1.728 110.704 23.928 ;
     RECT  110.704 20.4 110.801 23.928 ;
     RECT  110.704 1.728 110.873 3.96 ;
     RECT  110.873 2.832 110.915 3.96 ;
     RECT  110.704 5.04 110.953 6.312 ;
     RECT  110.801 20.688 111.125 23.928 ;
     RECT  111.125 23.04 111.341 23.928 ;
     RECT  110.915 2.88 111.347 3.96 ;
     RECT  111.341 23.328 111.395 23.928 ;
     RECT  110.704 19.344 111.485 19.368 ;
     RECT  111.125 20.688 111.485 21.672 ;
     RECT  111.485 20.784 112.061 21.672 ;
     RECT  109.909 0.096 112.169 0.12 ;
     RECT  110.953 5.04 112.273 6.024 ;
     RECT  112.273 5.04 112.525 6.072 ;
     RECT  111.347 2.88 112.601 3.336 ;
     RECT  112.525 5.04 112.636 6.84 ;
     RECT  111.395 23.376 112.705 23.928 ;
     RECT  110.873 1.728 112.781 1.8 ;
     RECT  112.061 20.784 112.849 21.528 ;
     RECT  112.705 23.376 112.979 24.552 ;
     RECT  112.601 3.312 113.093 3.336 ;
     RECT  113.093 3.312 113.641 3.432 ;
     RECT  112.849 20.16 113.653 21.528 ;
     RECT  112.636 6.816 113.708 6.84 ;
     RECT  113.653 20.16 113.708 21.576 ;
     RECT  113.708 6.816 113.795 7.08 ;
     RECT  113.708 19.92 113.795 21.576 ;
     RECT  113.821 25.776 113.905 25.8 ;
     RECT  112.979 23.376 113.965 23.928 ;
     RECT  113.795 20.16 114.029 21.576 ;
     RECT  113.965 22.656 114.029 23.928 ;
     RECT  113.641 2.736 114.14 3.432 ;
     RECT  112.781 1.728 114.181 1.752 ;
     RECT  114.14 2.736 114.181 3.72 ;
     RECT  114.029 20.16 114.185 23.928 ;
     RECT  114.185 20.16 114.221 22.2 ;
     RECT  114.181 1.728 114.227 3.72 ;
     RECT  112.636 5.04 114.289 5.736 ;
     RECT  114.185 23.376 114.419 23.928 ;
     RECT  114.419 23.904 114.577 23.928 ;
     RECT  114.289 5.04 114.685 5.832 ;
     RECT  113.317 0.096 114.761 0.12 ;
     RECT  114.227 1.728 114.761 2.76 ;
     RECT  114.565 25.728 114.901 25.752 ;
     RECT  114.901 25.728 115.091 25.8 ;
     RECT  114.577 23.904 115.139 24.552 ;
     RECT  115.091 25.776 115.193 25.8 ;
     RECT  115.139 23.904 115.513 23.928 ;
     RECT  114.685 4.128 115.525 5.832 ;
     RECT  115.253 9.12 115.525 9.144 ;
     RECT  114.761 1.728 115.808 2.184 ;
     RECT  115.525 3.888 115.808 5.832 ;
     RECT  113.795 6.816 115.808 6.84 ;
     RECT  115.525 8.544 115.808 9.144 ;
     RECT  114.221 20.832 115.808 22.2 ;
     RECT  115.513 23.376 115.808 23.928 ;
     RECT  115.813 0.336 116.005 0.36 ;
     RECT  116.005 0.24 116.101 0.36 ;
     RECT  115.808 1.728 116.104 23.928 ;
     RECT  116.104 20.832 116.237 23.928 ;
     RECT  116.101 0.096 116.243 0.36 ;
     RECT  116.104 3.264 116.273 5.976 ;
     RECT  116.243 0.336 116.291 0.36 ;
     RECT  116.273 3.312 116.453 5.976 ;
     RECT  116.104 1.728 116.533 1.8 ;
     RECT  116.237 23.376 116.579 23.928 ;
     RECT  116.453 3.312 116.675 5.928 ;
     RECT  116.104 8.544 116.677 8.568 ;
     RECT  116.579 23.856 116.809 23.928 ;
     RECT  116.809 23.856 116.915 23.976 ;
     RECT  116.237 20.832 117.301 21.912 ;
     RECT  117.301 19.92 117.385 21.912 ;
     RECT  117.385 19.92 117.388 22.008 ;
     RECT  117.413 0.096 117.497 0.12 ;
     RECT  116.675 4.128 117.817 5.928 ;
     RECT  116.533 1.152 117.857 1.8 ;
     RECT  117.817 4.128 118.22 6.024 ;
     RECT  118.22 4.128 118.307 6.504 ;
     RECT  116.915 23.856 118.429 23.928 ;
     RECT  118.165 0.576 118.433 0.6 ;
     RECT  118.307 4.128 118.537 6.024 ;
     RECT  118.249 19.152 118.549 19.176 ;
     RECT  117.388 20.448 118.549 22.008 ;
     RECT  118.549 19.152 118.595 22.008 ;
     RECT  118.595 20.832 118.609 22.008 ;
     RECT  118.609 20.832 118.649 22.2 ;
     RECT  118.537 3.984 118.685 6.024 ;
     RECT  117.857 1.728 119.029 1.8 ;
     RECT  119.029 1.728 119.117 1.896 ;
     RECT  118.685 3.984 119.189 4.152 ;
     RECT  118.429 23.376 119.267 23.928 ;
     RECT  118.649 22.176 119.437 22.2 ;
     RECT  118.595 19.632 119.66 19.656 ;
     RECT  118.649 20.832 119.66 21.144 ;
     RECT  119.117 1.728 119.693 1.8 ;
     RECT  119.693 1.728 119.749 1.752 ;
     RECT  118.685 5.136 119.761 6.024 ;
     RECT  119.66 19.632 120.049 21.144 ;
     RECT  119.437 22.176 120.049 22.44 ;
     RECT  119.761 5.136 120.089 6.84 ;
     RECT  120.049 19.632 120.089 22.44 ;
     RECT  119.749 1.152 120.161 1.752 ;
     RECT  119.257 3.888 120.553 3.912 ;
     RECT  120.089 5.136 120.553 6.12 ;
     RECT  120.161 1.728 120.661 1.752 ;
     RECT  120.653 25.776 120.737 25.8 ;
     RECT  120.661 1.728 120.853 2.184 ;
     RECT  120.089 20.304 120.853 22.44 ;
     RECT  119.267 23.856 120.853 23.928 ;
     RECT  120.853 1.728 120.949 2.328 ;
     RECT  120.553 3.888 120.949 6.12 ;
     RECT  120.949 1.728 121.208 6.12 ;
     RECT  120.869 8.544 121.208 8.568 ;
     RECT  120.853 20.304 121.208 23.928 ;
     RECT  121.208 1.728 121.235 23.928 ;
     RECT  121.235 1.728 121.427 23.88 ;
     RECT  121.427 1.728 121.504 23.502 ;
     RECT  121.504 3.888 121.667 3.96 ;
     RECT  121.504 8.544 121.673 8.568 ;
     RECT  121.504 1.728 121.997 1.896 ;
     RECT  121.504 5.088 122.003 6.504 ;
     RECT  122.003 5.088 122.213 6.312 ;
     RECT  119.941 0.096 122.321 0.12 ;
     RECT  122.293 25.728 122.435 25.752 ;
     RECT  121.504 20.304 122.473 21.672 ;
     RECT  121.997 1.728 122.588 1.752 ;
     RECT  121.504 23.376 122.605 23.448 ;
     RECT  122.213 5.088 122.609 6.264 ;
     RECT  122.588 1.68 122.675 1.752 ;
     RECT  122.473 20.304 122.684 20.328 ;
     RECT  122.605 23.376 122.689 23.928 ;
     RECT  122.684 20.16 122.771 20.328 ;
     RECT  122.473 21.36 122.821 21.672 ;
     RECT  121.667 3.888 122.929 3.912 ;
     RECT  122.609 5.088 122.929 5.736 ;
     RECT  122.675 1.728 122.965 1.752 ;
     RECT  122.965 1.728 123.257 2.184 ;
     RECT  122.821 21.36 123.293 22.344 ;
     RECT  122.713 25.056 123.395 25.08 ;
     RECT  123.577 24.528 123.731 24.552 ;
     RECT  122.929 3.888 123.793 5.736 ;
     RECT  123.793 3.888 123.833 5.784 ;
     RECT  123.349 0.096 123.865 0.12 ;
     RECT  123.865 0.096 123.941 0.216 ;
     RECT  123.941 0.192 123.949 0.216 ;
     RECT  122.771 20.304 124.117 20.328 ;
     RECT  124.117 20.304 124.181 21.144 ;
     RECT  123.257 1.728 124.253 1.752 ;
     RECT  124.181 19.968 124.265 21.144 ;
     RECT  123.293 22.32 124.409 22.344 ;
     RECT  123.833 4.512 124.513 5.784 ;
     RECT  124.265 20.16 124.549 21.144 ;
     RECT  124.253 1.728 124.597 1.8 ;
     RECT  122.689 23.376 124.597 23.496 ;
     RECT  124.513 4.512 124.693 6.024 ;
     RECT  124.693 4.512 124.729 6.888 ;
     RECT  124.597 23.376 124.757 23.544 ;
     RECT  124.597 1.728 124.765 1.848 ;
     RECT  124.729 4.512 124.835 7.32 ;
     RECT  124.765 1.728 124.849 2.28 ;
     RECT  124.835 4.512 124.913 6.84 ;
     RECT  124.757 23.376 124.981 23.592 ;
     RECT  124.913 4.512 125.305 6.024 ;
     RECT  124.981 23.376 125.305 23.928 ;
     RECT  125.305 23.376 125.555 24.024 ;
     RECT  125.125 0.096 125.633 0.12 ;
     RECT  125.305 4.224 125.633 6.024 ;
     RECT  124.549 20.16 125.773 22.056 ;
     RECT  125.555 23.376 125.773 23.928 ;
     RECT  124.849 1.728 125.837 1.8 ;
     RECT  125.773 20.16 126.277 23.928 ;
     RECT  125.837 1.728 126.565 1.896 ;
     RECT  126.565 1.728 126.608 2.04 ;
     RECT  125.633 4.224 126.608 5.88 ;
     RECT  125.461 8.544 126.608 8.568 ;
     RECT  124.213 16.032 126.608 16.056 ;
     RECT  126.277 20.112 126.608 23.928 ;
     RECT  126.608 1.728 126.904 23.928 ;
     RECT  126.904 23.76 126.949 23.928 ;
     RECT  126.904 19.92 127.001 22.488 ;
     RECT  126.904 4.944 127.145 7.128 ;
     RECT  126.904 1.728 127.541 1.8 ;
     RECT  126.949 23.76 127.541 24.024 ;
     RECT  127.001 19.92 127.685 22.152 ;
     RECT  127.541 23.904 127.715 24.024 ;
     RECT  127.669 0.096 127.829 0.12 ;
     RECT  127.685 19.92 127.829 21.672 ;
     RECT  127.145 5.136 128.081 7.128 ;
     RECT  128.041 18.768 128.147 18.792 ;
     RECT  127.829 19.92 128.153 20.328 ;
     RECT  126.904 2.88 128.185 3.864 ;
     RECT  128.153 20.256 128.189 20.328 ;
     RECT  128.081 5.664 129.085 7.128 ;
     RECT  128.185 2.88 129.197 4.104 ;
     RECT  129.197 3.84 129.229 4.104 ;
     RECT  129.085 5.088 129.229 7.128 ;
     RECT  127.715 23.904 129.232 23.928 ;
     RECT  129.232 23.856 129.265 23.928 ;
     RECT  128.761 18.96 129.373 18.984 ;
     RECT  129.265 23.856 129.491 24.552 ;
     RECT  129.491 23.856 129.553 23.928 ;
     RECT  129.229 3.84 129.665 7.128 ;
     RECT  127.541 1.728 129.761 1.752 ;
     RECT  129.665 5.712 129.877 7.128 ;
     RECT  129.637 0.096 129.881 0.12 ;
     RECT  128.189 20.304 129.913 20.328 ;
     RECT  129.877 5.712 129.953 7.176 ;
     RECT  129.665 3.84 129.989 4.296 ;
     RECT  129.913 20.208 130.093 20.328 ;
     RECT  127.829 21.36 130.093 21.672 ;
     RECT  129.973 25.776 130.169 25.8 ;
     RECT  130.093 20.208 130.211 21.672 ;
     RECT  129.373 18.96 130.417 19.224 ;
     RECT  130.211 20.208 130.417 20.328 ;
     RECT  129.761 1.728 130.453 1.8 ;
     RECT  130.165 0.576 130.529 0.6 ;
     RECT  130.453 1.728 130.547 1.896 ;
     RECT  129.553 23.376 130.547 23.928 ;
     RECT  129.953 5.712 130.813 5.736 ;
     RECT  130.417 18.96 130.961 20.328 ;
     RECT  130.547 23.904 130.993 23.928 ;
     RECT  129.989 3.936 131.101 4.296 ;
     RECT  130.993 23.904 131.123 24.024 ;
     RECT  131.101 3.936 131.413 4.536 ;
     RECT  130.813 5.52 131.413 5.736 ;
     RECT  131.317 2.928 131.425 2.952 ;
     RECT  131.413 3.936 131.425 5.736 ;
     RECT  131.123 23.904 131.597 23.928 ;
     RECT  130.547 1.728 131.605 1.752 ;
     RECT  131.425 2.928 131.605 5.736 ;
     RECT  131.065 22.8 131.797 22.824 ;
     RECT  130.211 21.648 131.821 21.672 ;
     RECT  131.797 22.752 131.821 22.824 ;
     RECT  131.221 0.096 131.845 0.12 ;
     RECT  131.845 0.096 131.987 0.216 ;
     RECT  131.605 1.728 132.008 5.736 ;
     RECT  129.953 7.152 132.008 7.176 ;
     RECT  131.093 8.544 132.008 8.568 ;
     RECT  126.904 16.032 132.008 16.056 ;
     RECT  130.961 19.392 132.008 20.328 ;
     RECT  131.821 21.648 132.008 22.824 ;
     RECT  131.597 23.856 132.008 23.928 ;
     RECT  132.008 1.728 132.304 23.928 ;
     RECT  132.304 19.776 132.473 22.056 ;
     RECT  132.304 1.728 132.725 1.848 ;
     RECT  132.304 23.376 132.797 23.928 ;
     RECT  132.304 3.312 133.091 5.304 ;
     RECT  132.797 23.376 133.157 23.736 ;
     RECT  132.304 8.544 133.193 8.568 ;
     RECT  131.987 0.096 133.337 0.12 ;
     RECT  132.473 21.936 133.369 22.056 ;
     RECT  133.157 23.376 133.369 23.448 ;
     RECT  132.725 1.728 133.373 1.8 ;
     RECT  132.473 19.776 133.441 20.568 ;
     RECT  133.369 21.936 133.441 23.448 ;
     RECT  133.091 3.408 133.445 5.304 ;
     RECT  133.441 19.776 133.589 23.448 ;
     RECT  133.589 22.8 133.619 23.448 ;
     RECT  133.445 3.936 133.693 5.304 ;
     RECT  132.304 6.288 133.693 7.176 ;
     RECT  133.381 0.144 133.733 0.168 ;
     RECT  133.589 19.776 133.861 21.528 ;
     RECT  133.693 3.936 134.093 7.176 ;
     RECT  133.373 1.728 134.444 1.752 ;
     RECT  133.619 23.376 134.444 23.448 ;
     RECT  134.444 1.728 134.557 2.28 ;
     RECT  133.861 19.488 134.633 21.528 ;
     RECT  134.521 25.056 134.675 25.08 ;
     RECT  134.557 1.728 134.705 2.328 ;
     RECT  134.444 23.376 134.809 23.544 ;
     RECT  134.633 19.488 134.917 21.144 ;
     RECT  134.093 4.512 135.133 7.176 ;
     RECT  134.917 19.008 135.353 21.144 ;
     RECT  134.705 1.728 135.533 1.8 ;
     RECT  135.353 19.008 135.713 20.52 ;
     RECT  135.533 1.728 135.733 1.752 ;
     RECT  135.133 4.32 135.961 7.176 ;
     RECT  135.961 4.32 136.033 7.464 ;
     RECT  136.033 4.32 136.124 7.512 ;
     RECT  136.124 3.696 136.213 7.512 ;
     RECT  136.213 3.408 136.253 7.512 ;
     RECT  136.253 3.408 136.296 5.256 ;
     RECT  134.809 23.376 136.307 23.928 ;
     RECT  135.713 20.304 136.453 20.52 ;
     RECT  134.821 0.096 136.469 0.12 ;
     RECT  136.296 3.36 136.693 5.256 ;
     RECT  136.693 3.312 136.741 5.256 ;
     RECT  135.845 25.776 136.931 25.8 ;
     RECT  136.741 3.072 137.221 5.256 ;
     RECT  135.713 19.008 137.269 19.032 ;
     RECT  136.453 20.304 137.269 20.808 ;
     RECT  136.253 6.24 137.293 7.512 ;
     RECT  136.357 8.544 137.293 8.568 ;
     RECT  135.733 1.152 137.317 1.752 ;
     RECT  137.221 2.976 137.317 5.256 ;
     RECT  136.307 23.376 137.317 23.736 ;
     RECT  137.317 1.152 137.333 5.256 ;
     RECT  136.717 21.792 137.365 21.816 ;
     RECT  137.317 23.376 137.365 23.88 ;
     RECT  137.333 1.728 137.408 5.256 ;
     RECT  137.293 6.24 137.408 8.568 ;
     RECT  132.304 16.032 137.408 16.056 ;
     RECT  136.453 17.52 137.408 17.544 ;
     RECT  137.269 18.816 137.408 20.808 ;
     RECT  137.365 21.792 137.408 23.88 ;
     RECT  137.408 1.728 137.509 23.88 ;
     RECT  137.509 1.728 137.704 23.928 ;
     RECT  137.704 20.544 137.761 23.928 ;
     RECT  137.704 18.864 137.843 19.464 ;
     RECT  137.761 20.544 137.843 24.552 ;
     RECT  137.843 20.544 137.873 22.248 ;
     RECT  137.843 23.376 137.873 24.552 ;
     RECT  137.843 19.344 137.909 19.464 ;
     RECT  137.873 20.544 137.981 21.144 ;
     RECT  137.873 24.528 138.083 24.552 ;
     RECT  137.704 3.936 138.227 8.232 ;
     RECT  137.704 1.728 138.521 2.28 ;
     RECT  137.981 21.12 138.557 21.144 ;
     RECT  137.704 16.032 138.877 17.736 ;
     RECT  137.909 19.344 138.877 19.368 ;
     RECT  138.227 7.056 138.913 8.232 ;
     RECT  138.877 16.032 138.917 19.368 ;
     RECT  138.949 25.776 139.091 25.8 ;
     RECT  139.189 9.456 139.276 9.48 ;
     RECT  138.227 3.936 139.277 5.88 ;
     RECT  138.913 7.056 139.285 8.28 ;
     RECT  137.873 22.224 139.285 22.248 ;
     RECT  137.873 23.376 139.285 23.448 ;
     RECT  139.277 5.04 139.417 5.88 ;
     RECT  139.285 7.056 139.417 9.192 ;
     RECT  138.037 0.096 139.445 0.12 ;
     RECT  138.725 2.736 139.453 2.904 ;
     RECT  139.277 3.936 139.453 3.96 ;
     RECT  139.285 22.224 139.453 23.448 ;
     RECT  138.917 18.432 139.525 19.368 ;
     RECT  139.013 20.496 139.525 20.52 ;
     RECT  139.445 0.096 139.529 0.168 ;
     RECT  139.453 22.224 139.537 23.928 ;
     RECT  139.537 22.224 139.561 23.736 ;
     RECT  139.561 22.176 139.709 23.736 ;
     RECT  139.417 5.04 139.715 9.192 ;
     RECT  138.917 16.032 139.741 17.112 ;
     RECT  139.715 7.92 139.763 9.192 ;
     RECT  139.453 2.736 139.781 3.96 ;
     RECT  139.763 7.968 139.781 9.192 ;
     RECT  137.704 11.376 139.853 11.4 ;
     RECT  139.741 15.984 139.861 17.112 ;
     RECT  139.861 15.84 139.957 17.112 ;
     RECT  139.525 18.432 139.957 20.52 ;
     RECT  139.957 15.408 139.985 20.52 ;
     RECT  139.781 7.968 139.997 9.144 ;
     RECT  139.985 15.408 140.101 20.856 ;
     RECT  140.101 15.408 140.137 21.096 ;
     RECT  139.715 5.04 140.195 6.456 ;
     RECT  140.137 14.784 140.249 21.096 ;
     RECT  138.521 1.728 140.348 1.752 ;
     RECT  140.249 20.976 140.353 21.096 ;
     RECT  139.997 8.16 140.357 9.144 ;
     RECT  139.529 0.096 140.497 0.12 ;
     RECT  139.709 23.376 140.501 23.736 ;
     RECT  140.053 11.424 140.573 11.448 ;
     RECT  140.353 20.976 140.605 21.192 ;
     RECT  139.709 22.176 140.605 22.2 ;
     RECT  140.497 0.096 140.627 0.6 ;
     RECT  140.605 20.976 140.627 22.2 ;
     RECT  140.357 8.4 140.749 9.144 ;
     RECT  139.697 10.272 140.749 10.296 ;
     RECT  140.195 5.136 140.773 6.456 ;
     RECT  140.348 1.68 140.876 1.752 ;
     RECT  139.781 2.832 140.876 3.96 ;
     RECT  140.749 8.4 140.941 10.296 ;
     RECT  140.749 11.904 140.941 11.976 ;
     RECT  140.876 1.68 140.963 3.96 ;
     RECT  140.941 8.4 141.005 9.816 ;
     RECT  140.249 14.784 141.005 19.944 ;
     RECT  141.005 8.4 141.041 8.424 ;
     RECT  141.005 9.696 141.041 9.768 ;
     RECT  140.893 22.704 141.049 22.824 ;
     RECT  140.773 5.136 141.077 6.84 ;
     RECT  140.941 11.952 141.107 11.976 ;
     RECT  140.963 1.68 141.113 1.8 ;
     RECT  141.041 9.744 141.113 9.768 ;
     RECT  141.049 22.704 141.185 22.776 ;
     RECT  141.109 23.904 141.221 23.928 ;
     RECT  141.113 1.68 141.289 1.752 ;
     RECT  141.005 14.784 141.293 18.84 ;
     RECT  140.627 20.976 141.301 21.672 ;
     RECT  141.077 5.136 141.347 5.784 ;
     RECT  141.181 6.864 141.347 6.888 ;
     RECT  141.005 19.92 141.347 19.944 ;
     RECT  141.347 5.232 141.365 5.784 ;
     RECT  141.289 1.152 141.373 1.752 ;
     RECT  141.301 20.976 141.397 21.576 ;
     RECT  141.293 14.784 141.443 16.536 ;
     RECT  140.963 2.88 141.473 3.96 ;
     RECT  141.365 5.376 141.473 5.784 ;
     RECT  141.443 14.784 141.539 15.384 ;
     RECT  141.397 19.968 141.545 21.576 ;
     RECT  141.505 12.528 141.589 12.552 ;
     RECT  141.473 2.88 141.617 3.864 ;
     RECT  141.541 7.968 141.625 7.992 ;
     RECT  141.473 5.712 141.653 5.784 ;
     RECT  141.539 14.832 141.683 15.384 ;
     RECT  141.293 18.144 141.689 18.84 ;
     RECT  141.545 21.12 141.731 21.576 ;
     RECT  141.731 21.12 141.772 21.336 ;
     RECT  141.617 2.88 141.797 2.904 ;
     RECT  141.443 16.512 141.827 16.536 ;
     RECT  141.689 18.144 141.833 18.504 ;
     RECT  141.772 21.12 141.841 21.144 ;
     RECT  140.627 0.096 141.865 0.168 ;
     RECT  141.683 14.832 141.905 14.856 ;
     RECT  141.373 1.728 141.941 1.752 ;
     RECT  141.545 19.968 141.941 19.992 ;
     RECT  141.653 5.76 142.013 5.784 ;
     RECT  141.833 18.48 142.085 18.504 ;
     RECT  141.185 22.752 142.093 22.776 ;
     RECT  141.937 23.952 142.403 23.976 ;
     RECT  141.865 0.096 142.405 0.6 ;
     RECT  142.405 0.096 142.739 1.224 ;
     RECT  141.425 25.776 143.377 25.8 ;
     RECT  143.053 23.376 143.459 23.4 ;
     RECT  142.739 0.096 143.489 1.176 ;
     RECT  143.377 25.152 143.564 25.8 ;
     RECT  143.564 25.104 143.651 25.8 ;
     RECT  143.489 0.528 144.035 1.176 ;
     RECT  143.651 25.152 144.065 25.8 ;
     RECT  144.035 0.528 144.179 0.552 ;
     RECT  144.065 25.152 144.179 25.176 ;
    LAYER M5 ;
     RECT  0.144 0.016 144.168 0.563 ;
     RECT  0.144 0.563 144.024 0.659 ;
     RECT  144 0.659 144.024 1.187 ;
     RECT  0.144 0.659 142.728 1.235 ;
     RECT  0.144 1.235 141.864 1.763 ;
     RECT  0.144 1.763 3.768 1.811 ;
     RECT  5.28 1.763 25.992 1.811 ;
     RECT  27.408 1.763 32.088 1.811 ;
     RECT  33.312 1.763 36.024 1.811 ;
     RECT  37.44 1.763 44.136 1.811 ;
     RECT  45.168 1.763 51.816 1.811 ;
     RECT  52.896 1.763 54.312 1.811 ;
     RECT  55.728 1.763 58.632 1.811 ;
     RECT  59.712 1.763 75.144 1.811 ;
     RECT  77.808 1.763 94.68 1.811 ;
     RECT  96.816 1.763 101.304 1.811 ;
     RECT  102.576 1.763 105.816 1.811 ;
     RECT  106.848 1.763 119.448 1.811 ;
     RECT  124.272 1.763 127.848 1.811 ;
     RECT  128.928 1.763 130.536 1.811 ;
     RECT  134.496 1.763 135.384 1.811 ;
     RECT  5.28 1.811 20.424 1.859 ;
     RECT  22.56 1.811 22.968 1.859 ;
     RECT  24 1.811 25.992 1.859 ;
     RECT  27.936 1.811 31.56 1.859 ;
     RECT  33.312 1.811 35.88 1.859 ;
     RECT  40.032 1.811 43.56 1.859 ;
     RECT  45.168 1.811 49.512 1.859 ;
     RECT  51 1.811 51.816 1.859 ;
     RECT  52.896 1.811 53.976 1.859 ;
     RECT  69.024 1.811 74.952 1.859 ;
     RECT  78 1.811 81.96 1.859 ;
     RECT  93.936 1.811 94.512 1.859 ;
     RECT  102.576 1.811 102.6 1.859 ;
     RECT  103.632 1.811 105.816 1.859 ;
     RECT  124.608 1.811 124.824 1.859 ;
     RECT  7.488 1.859 9.864 1.907 ;
     RECT  10.896 1.859 20.424 1.907 ;
     RECT  25.44 1.859 25.8 1.907 ;
     RECT  27.936 1.859 30.504 1.907 ;
     RECT  37.44 1.811 38.712 1.907 ;
     RECT  59.712 1.811 65.112 1.907 ;
     RECT  66.672 1.811 67.512 1.907 ;
     RECT  78 1.859 80.328 1.907 ;
     RECT  82.992 1.811 86.952 1.907 ;
     RECT  107.04 1.811 107.064 1.907 ;
     RECT  119.04 1.811 119.064 1.907 ;
     RECT  120.672 1.763 121.944 1.907 ;
     RECT  125.856 1.811 127.848 1.907 ;
     RECT  130.512 1.811 130.536 1.907 ;
     RECT  0.144 1.811 3.288 1.955 ;
     RECT  126.576 1.907 127.848 2.051 ;
     RECT  137.328 1.763 138.792 2.051 ;
     RECT  7.488 1.907 8.232 2.099 ;
     RECT  7.8 2.099 8.232 2.195 ;
     RECT  9.456 1.907 9.672 2.195 ;
     RECT  10.896 1.907 16.872 2.195 ;
     RECT  18.6 1.907 20.424 2.195 ;
     RECT  31.536 1.859 31.56 2.195 ;
     RECT  33.312 1.859 33.336 2.195 ;
     RECT  37.44 1.907 38.232 2.195 ;
     RECT  47.136 1.859 49.512 2.195 ;
     RECT  53.952 1.859 53.976 2.195 ;
     RECT  59.712 1.907 62.112 2.195 ;
     RECT  63.12 1.907 65.112 2.195 ;
     RECT  69.024 1.859 70.104 2.195 ;
     RECT  71.184 1.859 73.896 2.195 ;
     RECT  81.408 1.859 81.432 2.195 ;
     RECT  83.184 1.907 86.952 2.195 ;
     RECT  88.032 1.811 89.496 2.195 ;
     RECT  97.344 1.811 99.912 2.195 ;
     RECT  103.632 1.859 105.768 2.195 ;
     RECT  112.416 1.811 116.28 2.195 ;
     RECT  120.672 1.907 121.512 2.195 ;
     RECT  122.976 1.763 123 2.195 ;
     RECT  131.616 1.763 133.224 2.195 ;
     RECT  5.28 1.859 6.456 2.243 ;
     RECT  27.936 1.907 30.12 2.243 ;
     RECT  72.048 2.195 73.896 2.243 ;
     RECT  0.672 1.955 3.288 2.291 ;
     RECT  9.648 2.195 9.672 2.291 ;
     RECT  15.744 2.195 16.488 2.291 ;
     RECT  29.04 2.243 30.12 2.291 ;
     RECT  49.488 2.195 49.512 2.291 ;
     RECT  56.304 1.811 57.048 2.291 ;
     RECT  58.608 1.811 58.632 2.291 ;
     RECT  60.432 2.195 62.112 2.291 ;
     RECT  80.304 1.907 80.328 2.291 ;
     RECT  83.184 2.195 84.84 2.291 ;
     RECT  99.168 2.195 99.912 2.291 ;
     RECT  109.008 1.811 111.192 2.291 ;
     RECT  124.8 1.859 124.824 2.291 ;
     RECT  134.496 1.811 134.52 2.291 ;
     RECT  0.864 2.291 3.288 2.339 ;
     RECT  10.896 2.195 14.328 2.339 ;
     RECT  20.064 2.195 20.088 2.339 ;
     RECT  22.944 1.859 22.968 2.339 ;
     RECT  27.936 2.243 27.96 2.339 ;
     RECT  29.04 2.291 29.712 2.339 ;
     RECT  40.032 1.859 42.84 2.339 ;
     RECT  45.168 1.859 45.912 2.339 ;
     RECT  72.432 2.243 73.896 2.339 ;
     RECT  83.232 2.291 83.928 2.339 ;
     RECT  86.064 2.195 86.904 2.339 ;
     RECT  112.416 2.195 114.216 2.339 ;
     RECT  120.864 2.195 121.512 2.339 ;
     RECT  90.528 1.811 92.904 2.387 ;
     RECT  40.032 2.339 41.4 2.531 ;
     RECT  61.68 2.291 62.112 2.531 ;
     RECT  137.4 2.051 138.792 2.821 ;
     RECT  140.928 1.763 141.384 2.821 ;
     RECT  97.536 2.195 97.56 2.867 ;
     RECT  11.472 2.339 11.832 2.915 ;
     RECT  25.44 1.907 25.464 2.915 ;
     RECT  34.416 1.859 35.88 2.915 ;
     RECT  40.2 2.531 41.4 2.915 ;
     RECT  42.816 2.339 42.84 2.915 ;
     RECT  69.024 2.195 69.624 2.915 ;
     RECT  90.528 2.387 90.552 2.915 ;
     RECT  91.776 2.387 92.904 2.915 ;
     RECT  109.008 2.291 109.032 2.915 ;
     RECT  112.416 2.339 113.88 2.915 ;
     RECT  126.6 2.051 127.848 2.915 ;
     RECT  128.928 1.811 128.952 2.915 ;
     RECT  47.856 2.195 47.88 2.963 ;
     RECT  34.416 2.915 35.688 3.011 ;
     RECT  137.4 2.821 138.936 3.061 ;
     RECT  1.248 2.339 3.288 3.157 ;
     RECT  99.6 2.291 99.912 3.157 ;
     RECT  101.28 1.811 101.304 3.157 ;
     RECT  140.112 2.821 141.384 3.157 ;
     RECT  24 1.859 24.408 3.205 ;
     RECT  60.432 2.291 60.456 3.301 ;
     RECT  110.4 2.291 111.192 3.301 ;
     RECT  115.8 2.195 116.28 3.301 ;
     RECT  136.752 3.061 138.936 3.301 ;
     RECT  7.8 2.195 8.112 3.349 ;
     RECT  18.6 2.195 18.912 3.349 ;
     RECT  45.6 2.339 45.912 3.349 ;
     RECT  136.704 3.301 138.936 3.349 ;
     RECT  1.248 3.157 3.576 3.397 ;
     RECT  37.872 2.195 38.232 3.397 ;
     RECT  72.432 2.339 72.912 3.397 ;
     RECT  78 1.907 79.272 3.397 ;
     RECT  136.368 3.349 138.936 3.397 ;
     RECT  34.8 3.011 35.688 3.443 ;
     RECT  56.4 2.291 57.048 3.443 ;
     RECT  59.952 3.301 60.456 3.443 ;
     RECT  91.776 2.915 91.992 3.443 ;
     RECT  104.352 2.195 105.768 3.443 ;
     RECT  113.136 2.915 113.88 3.443 ;
     RECT  121.104 2.339 121.512 3.443 ;
     RECT  34.8 3.443 35.496 3.491 ;
     RECT  91.968 3.443 91.992 3.491 ;
     RECT  1.248 3.397 3.672 3.539 ;
     RECT  136.224 3.397 138.936 3.685 ;
     RECT  131.856 2.195 133.224 3.733 ;
     RECT  40.2 2.915 40.824 3.827 ;
     RECT  7.68 3.349 8.112 3.829 ;
     RECT  104.88 3.443 105.768 3.875 ;
     RECT  7.68 3.829 8.28 3.877 ;
     RECT  23.088 3.205 24.408 3.877 ;
     RECT  115.8 3.301 116.664 3.877 ;
     RECT  31.68 3.301 31.704 3.923 ;
     RECT  11.76 2.915 11.784 3.925 ;
     RECT  18.48 3.349 18.912 3.925 ;
     RECT  23.088 3.877 24.504 3.925 ;
     RECT  29.136 2.339 29.712 3.925 ;
     RECT  33.648 3.877 33.672 3.925 ;
     RECT  51 1.859 51.312 3.925 ;
     RECT  61.8 2.531 62.112 3.925 ;
     RECT  63.12 2.195 63.144 3.925 ;
     RECT  66.72 1.907 67.512 3.925 ;
     RECT  69.6 2.915 69.624 3.925 ;
     RECT  94.2 1.859 94.512 3.925 ;
     RECT  121.2 3.443 121.512 3.925 ;
     RECT  131.808 3.733 133.224 3.925 ;
     RECT  83.232 2.339 83.712 3.973 ;
     RECT  99.6 3.157 101.304 4.019 ;
     RECT  64.8 2.195 64.824 4.069 ;
     RECT  1.776 3.539 3.672 4.115 ;
     RECT  76.896 3.301 76.92 4.115 ;
     RECT  115.536 3.877 116.664 4.117 ;
     RECT  56.4 3.443 56.712 4.213 ;
     RECT  23.04 3.925 24.504 4.261 ;
     RECT  49.92 3.925 49.944 4.261 ;
     RECT  51 3.925 52.104 4.261 ;
     RECT  94.2 3.925 95.304 4.261 ;
     RECT  64.8 4.069 65.592 4.355 ;
     RECT  15.84 2.291 15.864 4.501 ;
     RECT  45.6 3.349 46.44 4.501 ;
     RECT  59.952 3.443 59.976 4.501 ;
     RECT  84.96 4.117 84.984 4.501 ;
     RECT  88.416 2.195 89.352 4.501 ;
     RECT  121.2 3.925 121.656 4.501 ;
     RECT  69.6 3.925 70.44 4.547 ;
     RECT  61.8 3.925 63.144 4.549 ;
     RECT  1.776 4.115 3.576 4.595 ;
     RECT  88.416 4.501 89.496 4.595 ;
     RECT  136.176 3.685 138.936 4.595 ;
     RECT  11.472 3.925 11.784 4.643 ;
     RECT  72.384 3.397 72.912 4.645 ;
     RECT  86.88 2.339 86.904 4.645 ;
     RECT  94.2 4.261 96.024 4.645 ;
     RECT  55.872 4.213 56.712 4.691 ;
     RECT  59.232 4.501 59.976 4.691 ;
     RECT  56.4 4.691 56.712 4.741 ;
     RECT  32.928 3.925 33.672 4.789 ;
     RECT  34.8 3.491 35.304 4.789 ;
     RECT  37.2 3.397 38.232 4.931 ;
     RECT  78 3.397 80.088 4.933 ;
     RECT  45.408 4.501 46.44 5.029 ;
     RECT  125.472 4.501 125.496 5.029 ;
     RECT  92.592 3.925 92.616 5.075 ;
     RECT  110.4 3.301 111.336 5.075 ;
     RECT  114.192 3.685 114.216 5.075 ;
     RECT  15.84 4.501 15.96 5.077 ;
     RECT  120.912 4.501 121.656 5.077 ;
     RECT  104.88 3.875 105.312 5.123 ;
     RECT  118.416 4.789 118.44 5.125 ;
     RECT  49.92 4.261 52.104 5.171 ;
     RECT  108.192 4.213 108.216 5.171 ;
     RECT  131.136 3.925 133.944 5.171 ;
     RECT  5.28 2.243 6.168 5.173 ;
     RECT  28.512 3.925 29.712 5.173 ;
     RECT  37.584 4.931 38.232 5.173 ;
     RECT  77.856 4.933 80.088 5.173 ;
     RECT  94.08 4.645 96.024 5.173 ;
     RECT  11.472 4.643 11.736 5.219 ;
     RECT  77.856 5.173 80.376 5.219 ;
     RECT  82.752 3.973 83.712 5.221 ;
     RECT  115.248 4.117 116.664 5.267 ;
     RECT  131.136 5.171 133.08 5.315 ;
     RECT  56.4 4.741 56.808 5.317 ;
     RECT  84.768 4.501 84.984 5.317 ;
     RECT  138.912 4.595 138.936 5.365 ;
     RECT  140.112 3.157 141.576 5.365 ;
     RECT  21.504 4.069 21.528 5.459 ;
     RECT  59.232 4.691 59.256 5.459 ;
     RECT  50.112 5.171 52.104 5.461 ;
     RECT  50.112 5.461 52.728 5.507 ;
     RECT  84.768 5.317 85.512 5.507 ;
     RECT  118.272 5.125 118.44 5.507 ;
     RECT  23.04 4.261 24.984 5.603 ;
     RECT  11.712 5.219 11.736 5.605 ;
     RECT  13.2 2.339 13.512 5.605 ;
     RECT  40.2 3.827 40.728 5.605 ;
     RECT  72.096 4.645 72.912 5.605 ;
     RECT  136.176 4.595 137.712 5.605 ;
     RECT  47.712 3.925 47.736 5.651 ;
     RECT  5.28 5.173 6.648 5.653 ;
     RECT  32.928 4.789 35.304 5.699 ;
     RECT  106.368 5.461 106.392 5.701 ;
     RECT  42.192 3.925 42.216 5.747 ;
     RECT  61.8 4.549 63.24 5.747 ;
     RECT  65.568 4.355 65.592 5.747 ;
     RECT  69.6 4.547 70.2 5.747 ;
     RECT  71.232 5.605 72.912 5.747 ;
     RECT  77.856 5.219 79.224 5.747 ;
     RECT  86.88 4.645 87.768 5.747 ;
     RECT  37.584 5.173 38.76 5.795 ;
     RECT  69.6 5.747 70.152 5.795 ;
     RECT  77.856 5.747 78.312 5.845 ;
     RECT  28.464 5.173 29.712 5.987 ;
     RECT  108.96 5.557 108.984 5.987 ;
     RECT  120.912 5.077 121.896 5.989 ;
     RECT  26.16 4.693 26.184 6.035 ;
     RECT  94.08 5.173 96.072 6.035 ;
     RECT  43.68 5.077 43.704 6.133 ;
     RECT  80.352 5.219 80.376 6.181 ;
     RECT  105 5.123 105.312 6.181 ;
     RECT  129.408 4.261 129.432 6.181 ;
     RECT  11.712 5.605 13.512 6.229 ;
     RECT  110.4 5.075 110.904 6.229 ;
     RECT  136.08 5.605 137.712 6.229 ;
     RECT  138.912 5.365 141.576 6.229 ;
     RECT  28.752 5.987 29.712 6.275 ;
     RECT  50.112 5.507 51.312 6.275 ;
     RECT  11.712 6.229 14.232 6.323 ;
     RECT  30.864 5.365 30.888 6.323 ;
     RECT  50.4 6.275 51.312 6.323 ;
     RECT  74.112 4.501 74.136 6.323 ;
     RECT  80.064 6.181 80.376 6.323 ;
     RECT  92.88 5.605 92.904 6.323 ;
     RECT  98.592 5.317 98.616 6.323 ;
     RECT  109.872 6.229 110.904 6.323 ;
     RECT  129.408 6.181 129.912 6.323 ;
     RECT  99.6 4.019 100.344 6.371 ;
     RECT  2.304 4.595 3.576 6.419 ;
     RECT  56.4 5.317 56.952 6.419 ;
     RECT  70.128 5.795 70.152 6.419 ;
     RECT  112.56 5.653 112.584 6.515 ;
     RECT  118.272 5.507 118.296 6.515 ;
     RECT  120.912 5.989 121.992 6.515 ;
     RECT  61.8 5.747 63.144 6.517 ;
     RECT  66.72 3.925 67.608 6.517 ;
     RECT  136.08 6.229 141.576 6.517 ;
     RECT  15.408 5.077 15.96 6.563 ;
     RECT  37.584 5.795 37.608 6.563 ;
     RECT  45.264 5.029 46.44 6.563 ;
     RECT  80.064 6.323 80.184 6.563 ;
     RECT  94.08 6.035 95.688 6.563 ;
     RECT  45.264 6.563 46.2 6.659 ;
     RECT  61.632 6.517 63.144 6.659 ;
     RECT  66.72 6.517 67.8 6.659 ;
     RECT  104.688 6.181 105.312 6.659 ;
     RECT  38.736 5.795 38.76 6.757 ;
     RECT  5.136 5.653 6.648 6.803 ;
     RECT  38.544 6.757 38.76 6.803 ;
     RECT  52.704 5.507 52.728 6.803 ;
     RECT  85.104 5.507 85.512 6.803 ;
     RECT  119.856 5.461 119.88 6.803 ;
     RECT  5.136 6.803 6.216 6.805 ;
     RECT  17.616 3.925 18.912 6.805 ;
     RECT  12.528 6.323 14.232 6.851 ;
     RECT  15.936 6.563 15.96 6.851 ;
     RECT  17.616 6.805 19.032 6.851 ;
     RECT  23.04 5.603 24.504 6.851 ;
     RECT  40.2 5.605 40.776 6.851 ;
     RECT  56.4 6.419 56.808 6.851 ;
     RECT  71.232 5.747 71.256 6.851 ;
     RECT  72.384 5.747 72.912 6.851 ;
     RECT  82.032 5.221 83.712 6.851 ;
     RECT  85.488 6.803 85.512 6.851 ;
     RECT  87.6 5.747 87.768 6.851 ;
     RECT  4.896 6.805 6.216 6.899 ;
     RECT  10.608 6.373 10.632 6.899 ;
     RECT  29.136 6.275 29.712 6.899 ;
     RECT  34.8 5.699 35.304 6.899 ;
     RECT  42.096 6.517 42.12 6.899 ;
     RECT  43.68 6.133 43.8 6.899 ;
     RECT  88.8 4.595 89.496 6.899 ;
     RECT  91.728 5.845 91.752 6.899 ;
     RECT  109.872 6.323 110.712 6.899 ;
     RECT  135.696 6.517 141.576 6.899 ;
     RECT  45.264 6.659 45.912 6.947 ;
     RECT  99.6 6.371 100.296 6.947 ;
     RECT  106.368 5.701 106.92 6.947 ;
     RECT  95.664 6.563 95.688 6.995 ;
     RECT  55.296 6.229 55.32 7.091 ;
     RECT  61.8 6.659 63.144 7.091 ;
     RECT  113.76 5.365 113.784 7.091 ;
     RECT  128.208 6.709 128.232 7.139 ;
     RECT  129.888 6.323 129.912 7.187 ;
     RECT  124.8 5.029 125.496 7.331 ;
     RECT  13.2 6.851 14.232 7.379 ;
     RECT  27.264 6.805 27.288 7.379 ;
     RECT  4.896 6.899 6.168 7.427 ;
     RECT  80.16 6.563 80.184 7.427 ;
     RECT  2.4 6.419 3.576 7.475 ;
     RECT  5.808 7.427 6.168 7.475 ;
     RECT  18.6 6.851 19.032 7.475 ;
     RECT  63.12 7.091 63.144 7.475 ;
     RECT  77.472 5.845 78.312 7.475 ;
     RECT  82.752 6.851 83.712 7.475 ;
     RECT  136.08 6.899 141.576 7.475 ;
     RECT  5.808 7.475 5.832 7.523 ;
     RECT  43.776 6.899 43.8 7.523 ;
     RECT  136.08 7.475 138.216 7.523 ;
     RECT  32.928 5.699 33.672 8.003 ;
     RECT  40.2 6.851 40.728 8.003 ;
     RECT  66.72 6.659 67.608 8.003 ;
     RECT  139.2 7.475 141.576 8.003 ;
     RECT  40.2 8.003 40.68 8.099 ;
     RECT  7.68 3.877 8.376 8.195 ;
     RECT  7.8 8.195 8.376 8.579 ;
     RECT  23.04 6.851 24.408 8.579 ;
     RECT  32.928 8.003 32.952 8.579 ;
     RECT  66.768 8.003 67.608 8.579 ;
     RECT  88.8 6.899 89.256 8.579 ;
     RECT  94.08 6.563 94.512 8.579 ;
     RECT  97.152 3.925 97.176 8.579 ;
     RECT  99.6 6.947 100.152 8.579 ;
     RECT  115.296 5.267 116.664 8.579 ;
     RECT  120.912 6.515 121.656 8.579 ;
     RECT  125.472 7.331 125.496 8.579 ;
     RECT  131.136 5.315 132.984 8.579 ;
     RECT  136.368 7.523 136.392 8.579 ;
     RECT  2.4 7.475 3.384 8.675 ;
     RECT  4.656 7.957 4.68 9.011 ;
     RECT  2.4 8.675 3.288 9.155 ;
     RECT  77.856 7.475 78.312 9.155 ;
     RECT  115.296 8.579 116.112 9.155 ;
     RECT  139.2 8.003 140.952 9.491 ;
     RECT  139.728 9.491 140.952 9.779 ;
     RECT  139.728 9.779 140.904 10.307 ;
     RECT  2.4 9.155 2.904 10.883 ;
     RECT  38.544 6.803 38.568 10.883 ;
     RECT  137.4 7.523 138.216 11.411 ;
     RECT  140.064 10.307 140.088 11.459 ;
     RECT  140.88 11.893 140.904 11.941 ;
     RECT  106.896 6.947 106.92 12.035 ;
     RECT  72.6 6.851 72.912 12.517 ;
     RECT  140.88 11.941 141.096 12.517 ;
     RECT  106.416 12.469 106.44 13.813 ;
     RECT  40.2 8.099 40.512 14.197 ;
     RECT  38.88 11.365 38.904 14.291 ;
     RECT  106.416 13.813 106.536 14.291 ;
     RECT  140.88 12.517 141.576 15.349 ;
     RECT  139.872 15.829 139.896 16.405 ;
     RECT  140.88 15.349 141.672 16.405 ;
     RECT  139.872 16.405 141.672 16.501 ;
     RECT  139.872 16.501 141.816 16.835 ;
     RECT  2.4 10.883 2.712 17.077 ;
     RECT  137.4 11.411 137.712 17.509 ;
     RECT  2.4 17.077 3.384 17.605 ;
     RECT  40.2 14.197 40.632 17.989 ;
     RECT  139.104 17.077 139.128 17.989 ;
     RECT  140.4 16.835 141.816 17.989 ;
     RECT  4.752 15.877 4.776 18.565 ;
     RECT  7.8 8.579 8.112 18.709 ;
     RECT  136.464 17.509 137.712 18.853 ;
     RECT  61.8 7.091 62.112 18.949 ;
     RECT  139.104 17.989 141.816 19.379 ;
     RECT  4.752 18.565 5.112 19.427 ;
     RECT  26.544 17.605 26.568 19.427 ;
     RECT  5.088 19.427 5.112 19.475 ;
     RECT  136.464 18.853 137.832 19.475 ;
     RECT  13.2 7.379 13.512 19.477 ;
     RECT  13.104 19.477 13.512 19.573 ;
     RECT  13.104 19.573 14.232 19.619 ;
     RECT  18.6 7.475 18.912 19.621 ;
     RECT  25.344 17.605 25.368 19.669 ;
     RECT  99.6 8.579 99.912 19.669 ;
     RECT  83.4 7.475 83.712 19.765 ;
     RECT  133.872 19.477 133.896 19.765 ;
     RECT  61.056 18.949 62.112 19.811 ;
     RECT  1.92 17.605 3.384 19.813 ;
     RECT  24 8.579 24.312 19.909 ;
     RECT  25.344 19.669 26.232 19.909 ;
     RECT  40.08 17.989 40.632 19.909 ;
     RECT  72.336 12.517 72.912 19.909 ;
     RECT  94.2 8.579 94.512 19.909 ;
     RECT  98.928 19.669 99.912 19.909 ;
     RECT  6.96 18.709 8.112 20.003 ;
     RECT  124.224 16.021 124.248 20.003 ;
     RECT  51 6.323 51.312 20.101 ;
     RECT  110.4 6.899 110.712 20.149 ;
     RECT  83.28 19.765 83.712 20.197 ;
     RECT  106.416 14.291 106.44 20.197 ;
     RECT  128.112 18.757 128.136 20.291 ;
     RECT  133.776 19.765 133.896 20.291 ;
     RECT  39.36 19.909 40.632 20.293 ;
     RECT  45.6 6.947 45.912 20.341 ;
     RECT  1.776 19.813 3.384 20.389 ;
     RECT  68.544 18.181 68.568 20.389 ;
     RECT  1.056 20.389 3.384 20.437 ;
     RECT  118.56 19.141 118.584 20.483 ;
     RECT  78 9.155 78.312 20.485 ;
     RECT  139.968 19.379 141.816 20.485 ;
     RECT  72.336 19.909 73.896 20.531 ;
     RECT  74.976 19.333 75 20.531 ;
     RECT  18.6 19.621 19.224 20.579 ;
     RECT  38.736 20.293 40.632 20.579 ;
     RECT  133.872 20.291 133.896 20.579 ;
     RECT  88.8 8.579 89.112 20.581 ;
     RECT  109.92 20.149 110.712 20.581 ;
     RECT  94.2 19.909 96.264 20.627 ;
     RECT  83.28 20.197 84.408 20.629 ;
     RECT  98.928 19.909 100.104 20.723 ;
     RECT  40.2 20.579 40.632 20.725 ;
     RECT  88.8 20.581 90.072 20.725 ;
     RECT  94.2 20.627 95.496 20.725 ;
     RECT  136.464 19.475 137.712 20.819 ;
     RECT  50.304 20.101 51.312 20.821 ;
     RECT  78 20.485 79.224 20.821 ;
     RECT  126.6 2.915 126.912 20.821 ;
     RECT  13.2 19.619 14.232 20.867 ;
     RECT  81.216 20.197 81.24 20.867 ;
     RECT  88.8 20.725 90.6 20.867 ;
     RECT  106.416 20.197 106.488 20.915 ;
     RECT  107.904 18.949 107.928 20.963 ;
     RECT  40.2 20.725 40.68 21.013 ;
     RECT  115.8 9.155 116.112 21.013 ;
     RECT  0.336 20.437 3.384 21.061 ;
     RECT  24 19.909 26.232 21.061 ;
     RECT  103.248 20.725 103.272 21.061 ;
     RECT  105 6.659 105.312 21.061 ;
     RECT  121.2 8.579 121.512 21.061 ;
     RECT  122.736 20.149 122.76 21.061 ;
     RECT  82.32 20.629 84.408 21.107 ;
     RECT  98.928 20.723 99.912 21.109 ;
     RECT  40.2 21.013 41.016 21.155 ;
     RECT  60.336 20.581 60.36 21.155 ;
     RECT  78 20.821 79.656 21.155 ;
     RECT  82.992 21.107 84.408 21.155 ;
     RECT  94.08 20.725 95.496 21.155 ;
     RECT  109.104 20.581 110.712 21.155 ;
     RECT  119.712 20.149 119.736 21.155 ;
     RECT  139.056 20.485 141.816 21.155 ;
     RECT  10.272 20.293 10.296 21.203 ;
     RECT  38.736 20.579 38.76 21.203 ;
     RECT  117.312 19.909 117.336 21.203 ;
     RECT  7.8 20.003 8.112 21.205 ;
     RECT  7.8 21.205 8.424 21.253 ;
     RECT  109.92 21.155 110.712 21.253 ;
     RECT  0.336 21.061 3.96 21.299 ;
     RECT  121.2 21.061 122.76 21.395 ;
     RECT  63.648 19.861 63.672 21.443 ;
     RECT  124.56 20.965 124.584 21.443 ;
     RECT  94.08 21.155 94.512 21.541 ;
     RECT  113.76 19.909 113.784 21.541 ;
     RECT  40.2 21.155 40.872 21.587 ;
     RECT  139.056 21.155 141.72 21.587 ;
     RECT  78 21.155 79.224 21.635 ;
     RECT  7.44 21.253 8.424 21.637 ;
     RECT  130.176 20.965 130.2 21.637 ;
     RECT  132 8.579 132.312 21.637 ;
     RECT  23.28 21.061 26.232 21.683 ;
     RECT  27.456 20.533 27.48 21.683 ;
     RECT  44.976 20.341 45.912 21.683 ;
     RECT  90.576 20.867 90.6 21.683 ;
     RECT  98.736 21.109 99.912 21.683 ;
     RECT  136.896 20.819 137.712 21.685 ;
     RECT  0.336 21.299 2.904 21.781 ;
     RECT  67.2 8.579 67.512 21.781 ;
     RECT  68.544 20.389 69.048 21.781 ;
     RECT  78 21.635 78.648 21.923 ;
     RECT  125.904 20.821 126.912 21.925 ;
     RECT  93.024 21.157 93.048 21.971 ;
     RECT  113.664 21.541 113.784 21.973 ;
     RECT  130.176 21.637 132.312 22.021 ;
     RECT  18.6 20.579 18.912 22.069 ;
     RECT  13.2 20.867 13.656 22.163 ;
     RECT  94.032 21.541 94.512 22.163 ;
     RECT  18.6 22.069 19.128 22.165 ;
     RECT  65.328 21.301 65.352 22.211 ;
     RECT  50.16 20.821 51.312 22.259 ;
     RECT  67.2 21.781 69.048 22.259 ;
     RECT  25.44 21.683 26.232 22.307 ;
     RECT  67.2 22.259 67.608 22.307 ;
     RECT  108.672 21.637 108.696 22.451 ;
     RECT  103.248 21.061 105.72 22.453 ;
     RECT  40.2 21.587 40.68 22.549 ;
     RECT  88.8 20.867 89.112 22.549 ;
     RECT  109.92 21.253 110.808 22.549 ;
     RECT  88.656 22.549 89.112 22.597 ;
     RECT  34.8 6.899 35.112 22.741 ;
     RECT  139.056 21.587 141.336 22.741 ;
     RECT  10.512 22.165 10.536 22.789 ;
     RECT  130.176 22.021 132.552 22.835 ;
     RECT  109.92 22.549 111 23.317 ;
     RECT  3.936 21.299 3.96 23.365 ;
     RECT  5.712 21.733 5.736 23.365 ;
     RECT  7.44 21.637 8.52 23.365 ;
     RECT  9.84 22.789 10.536 23.365 ;
     RECT  13.2 22.163 13.512 23.365 ;
     RECT  18.48 22.165 19.176 23.365 ;
     RECT  20.4 22.693 20.424 23.365 ;
     RECT  21.504 20.773 21.528 23.365 ;
     RECT  23.28 21.683 24.456 23.365 ;
     RECT  25.44 22.307 26.088 23.365 ;
     RECT  29.4 6.899 29.712 23.365 ;
     RECT  34.8 22.741 35.208 23.365 ;
     RECT  39.936 22.549 40.68 23.365 ;
     RECT  45.6 21.683 45.912 23.365 ;
     RECT  50.496 22.259 51.312 23.365 ;
     RECT  56.4 6.851 56.712 23.365 ;
     RECT  59.856 23.077 59.88 23.365 ;
     RECT  61.8 19.811 62.112 23.365 ;
     RECT  67.2 22.307 67.512 23.365 ;
     RECT  69.024 22.259 69.048 23.365 ;
     RECT  72.336 20.531 72.912 23.365 ;
     RECT  74.016 22.069 74.04 23.365 ;
     RECT  78 21.923 78.312 23.365 ;
     RECT  82.992 21.155 83.712 23.365 ;
     RECT  87.84 22.597 89.112 23.365 ;
     RECT  90.912 22.261 90.936 23.365 ;
     RECT  94.08 22.163 94.512 23.365 ;
     RECT  97.872 22.741 97.896 23.365 ;
     RECT  99.504 21.683 99.912 23.365 ;
     RECT  102.384 22.453 105.72 23.365 ;
     RECT  107.424 20.965 107.688 23.365 ;
     RECT  109.92 23.317 111.384 23.365 ;
     RECT  113.664 21.973 114.072 23.365 ;
     RECT  115.056 21.013 116.112 23.365 ;
     RECT  121.2 21.395 122.424 23.365 ;
     RECT  125.808 21.925 126.912 23.365 ;
     RECT  130.176 22.835 130.536 23.365 ;
     RECT  131.808 22.835 132.552 23.365 ;
     RECT  133.584 22.789 133.608 23.365 ;
     RECT  136.896 21.685 137.832 23.365 ;
     RECT  139.056 22.741 142.056 23.365 ;
     RECT  18.48 23.365 32.616 23.413 ;
     RECT  54.864 23.365 54.888 23.413 ;
     RECT  76.896 23.365 78.888 23.413 ;
     RECT  80.16 23.365 84.84 23.413 ;
     RECT  86.4 23.365 90.936 23.413 ;
     RECT  92.16 23.365 93.096 23.413 ;
     RECT  94.08 23.365 96.312 23.413 ;
     RECT  97.344 23.365 98.472 23.413 ;
     RECT  99.504 23.365 100.776 23.413 ;
     RECT  120.864 23.365 124.296 23.413 ;
     RECT  125.328 23.365 126.912 23.413 ;
     RECT  131.808 23.365 134.136 23.413 ;
     RECT  135.216 23.365 142.056 23.413 ;
     RECT  60.96 23.365 62.76 23.557 ;
     RECT  34.8 23.365 42.12 23.701 ;
     RECT  75.648 23.365 75.672 23.701 ;
     RECT  76.896 23.413 84.84 23.701 ;
     RECT  54.672 23.413 54.888 23.749 ;
     RECT  55.92 23.365 59.88 23.749 ;
     RECT  75.648 23.701 84.84 23.749 ;
     RECT  109.92 23.365 116.568 23.749 ;
     RECT  120.864 23.413 126.912 23.749 ;
     RECT  13.2 23.365 16.68 23.797 ;
     RECT  18.096 23.413 32.616 23.797 ;
     RECT  34.032 23.701 42.12 23.797 ;
     RECT  44.976 23.365 45.912 23.797 ;
     RECT  70.272 23.365 71.208 23.797 ;
     RECT  72.336 23.365 74.616 23.797 ;
     RECT  3.936 23.365 11.832 23.845 ;
     RECT  13.2 23.797 16.872 23.845 ;
     RECT  18.096 23.797 42.12 23.845 ;
     RECT  44.256 23.797 45.912 23.845 ;
     RECT  54.672 23.749 59.88 23.845 ;
     RECT  60.96 23.557 63.144 23.845 ;
     RECT  64.176 23.365 69.24 23.845 ;
     RECT  70.272 23.797 74.616 23.845 ;
     RECT  75.648 23.749 84.984 23.845 ;
     RECT  86.256 23.413 90.936 23.845 ;
     RECT  92.16 23.413 96.312 23.845 ;
     RECT  97.344 23.413 100.776 23.845 ;
     RECT  109.392 23.749 116.568 23.845 ;
     RECT  118.512 23.365 119.256 23.845 ;
     RECT  120.864 23.749 127.32 23.845 ;
     RECT  129.792 23.365 130.536 23.845 ;
     RECT  131.808 23.413 142.056 23.845 ;
     RECT  3.936 23.845 16.872 23.893 ;
     RECT  18.096 23.845 46.44 23.893 ;
     RECT  47.472 23.365 52.92 23.893 ;
     RECT  53.952 23.845 63.144 23.893 ;
     RECT  64.176 23.845 90.936 23.893 ;
     RECT  92.16 23.845 101.16 23.893 ;
     RECT  102.384 23.365 108.12 23.893 ;
     RECT  109.2 23.845 127.32 23.893 ;
     RECT  129.264 23.845 130.536 23.893 ;
     RECT  131.616 23.845 142.056 23.893 ;
     RECT  0.144 21.781 2.904 23.941 ;
     RECT  3.936 23.893 142.056 23.941 ;
     RECT  143.424 23.365 143.448 25.093 ;
     RECT  143.424 25.093 143.64 25.141 ;
     RECT  0.144 23.941 142.392 25.765 ;
     RECT  143.424 25.141 144.168 25.765 ;
     RECT  0.144 25.765 144.168 25.872 ;
  END
END ot_s81_hc_ctfnq1
END LIBRARY
